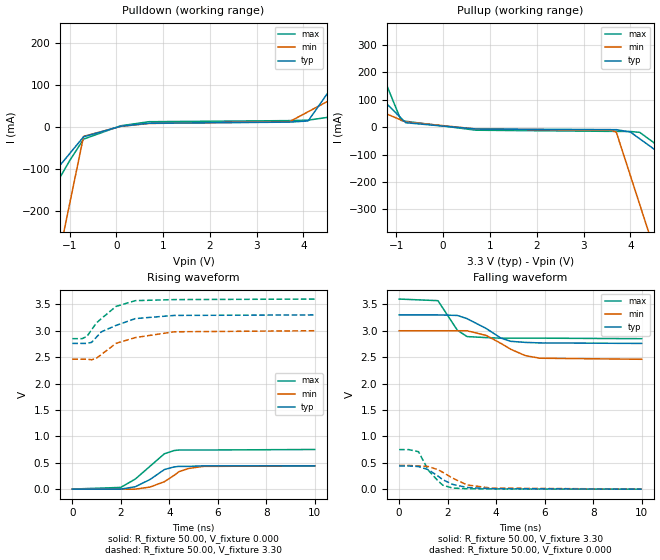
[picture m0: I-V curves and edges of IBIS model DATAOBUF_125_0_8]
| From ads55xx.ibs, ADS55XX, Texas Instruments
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|   Model DATAOBUF_125_0_8
[Model]   DATAOBUF_125_0_8
Model_type   Output
Polarity   Non-Inverting
Vmeas =   1.65V
C_comp   3.00pF   3.00pF   3.00pF
[Temperature Range]   50.00   0.10k   -20.00
[Voltage Range]   3.30V   3.00V   3.60V
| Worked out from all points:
|   slope of the pulldown table from 0 to 0.495 V, typ, clamps not added: 62.9 ohm
|   slope of the pullup table from 0 to 0.495 V, typ, clamps not added: 83.5 ohm
|   rising waveform, R_fixture 50.00, V_fixture 0.000: 20-80 % time 954ps typ, 1.01ns min, 1.11ns max; typ from 0 V to 0.44 V
|   rising waveform, R_fixture 50.00, V_fixture 3.30: 20-80 % time 1.33ns typ, 1.49ns min, 1ns max; typ from 2.76 V to 3.3 V
|   falling waveform, R_fixture 50.00, V_fixture 3.30: 20-80 % time 1.18ns typ, 1.28ns min, 616ps max; typ from 3.3 V to 2.76 V
|   falling waveform, R_fixture 50.00, V_fixture 0.000: 20-80 % time 970ps typ, 1.11ns min, 700ps max; typ from 0.44 V to 0.001 V
[Pulldown]
| voltage   I(typ)   I(min)   I(max)
-3.3V     -372.9mA   -1.424A    -524.1mA
-2.3V     -238.3mA   -884.7mA   -331.1mA
-1.9V     -184.5mA   -669mA     -253.9mA
-1.5V     -130.7mA   -453.3mA   -176.7mA
-1V       -63.35mA   -183.7mA   -80.18mA
-700mV    -22.97mA   -21.98mA   -28.5mA
100mV     2.25mA     1.9mA      3.39mA
700mV     9.17mA     8.74mA     12.95mA
3.7V      11.9mA     12.89mA    15.5mA
4.1V      14.74mA    36.61mA    16.56mA
5.5V      236.9mA    119.6mA    39.12mA
6.6V      411.5mA    184.9mA    57.88mA
[Pullup]
| voltage   I(typ)   I(min)   I(max)
-3.3V     441.6mA    197.5mA    1.029A
-1.9V     203.3mA    97.53mA    443mA
-1.7V     169.3mA    83.25mA    359.3mA
-900mV    33.12mA    26.13mA    24.62mA
-800mV    16.1mA     18.99mA    21.37mA
700mV     -6.9mA     -6.63mA    -11.18mA
3.6V      -9.09mA    -11.8mA    -15.42mA
3.7V      -9.22mA    -18.38mA   -15.48mA
4V        -17.8mA    -176.5mA   -15.89mA
4.2V      -42.42mA   -282mA     -19.03mA
4.5V      -79.35mA   -440.1mA   -56.42mA
6.6V      -337.9mA   -1.547A    -375.8mA
[Ramp]
| variable   typ   min   max
dV/dt_r   0.26/0.90n   0.27/1.07n   0.45/1.12n
dV/dt_f   0.32/1.15n   0.32/1.30n   0.45/0.61n
R_load = 50.00
[Rising Waveform]
R_fixture = 50.00
V_fixture = 0.000
V_fixture_min = 0.000
V_fixture_max = 0.000
| time   V(typ)   V(min)   V(max)
0s        16.26nV    19.53nV    30.54nV
2ns       -1.68mV    -1.17mV    31.66mV
2.6ns     44.29mV    -1.11mV    190mV
3.2ns     180mV      37.62mV    430mV
3.8ns     370mV      140mV      670mV
4.2ns     420mV      260mV      730mV
4.4ns     430mV      330mV      740mV
4.8ns     430mV      390mV      740mV
5.4ns     440mV      430mV      740mV
10ns      440mV      440mV      750mV
[Rising Waveform]
R_fixture = 50.00
V_fixture = 3.30
V_fixture_min = 3.00
V_fixture_max = 3.60
| time   V(typ)   V(min)   V(max)
0s        2.76V      2.46V      2.85V
400ps     2.76V      2.46V      2.85V
600ps     2.76V      2.46V      2.89V
800ps     2.78V      2.45V      3.02V
1ns       2.88V      2.48V      3.15V
1.2ns     2.98V      2.55V      3.23V
1.8ns     3.1V       2.76V      3.46V
2.6ns     3.23V      2.87V      3.57V
4.2ns     3.29V      2.98V      3.59V
10ns      3.3V       3V         3.6V
[Falling Waveform]
R_fixture = 50.00
V_fixture = 3.30
V_fixture_min = 3.00
V_fixture_max = 3.60
| time   V(typ)   V(min)   V(max)
0s        3.3V       3V         3.6V
1.6ns     3.3V       3V         3.57V
2.4ns     3.29V      3V         3.01V
2.8ns     3.23V      3V         2.89V
3.6ns     3.04V      2.91V      2.87V
4.2ns     2.86V      2.76V      2.86V
4.6ns     2.8V       2.65V      2.86V
5.2ns     2.78V      2.53V      2.86V
5.8ns     2.77V      2.48V      2.86V
10ns      2.76V      2.46V      2.85V
[Falling Waveform]
R_fixture = 50.00
V_fixture = 0.000
V_fixture_min = 0.000
V_fixture_max = 0.000
| time   V(typ)   V(min)   V(max)
0s        440mV      450mV      750mV
400ps     440mV      450mV      750mV
800ps     430mV      440mV      710mV
1.2ns     370mV      430mV      360mV
1.6ns     250mV      370mV      160mV
1.8ns     180mV      320mV      76.91mV
2.2ns     92.78mV    210mV      21.78mV
2.8ns     33.05mV    81.24mV    9.8mV
3.8ns     10.97mV    20.92mV    5.51mV
10ns      1.49mV     1.8mV      1.17mV
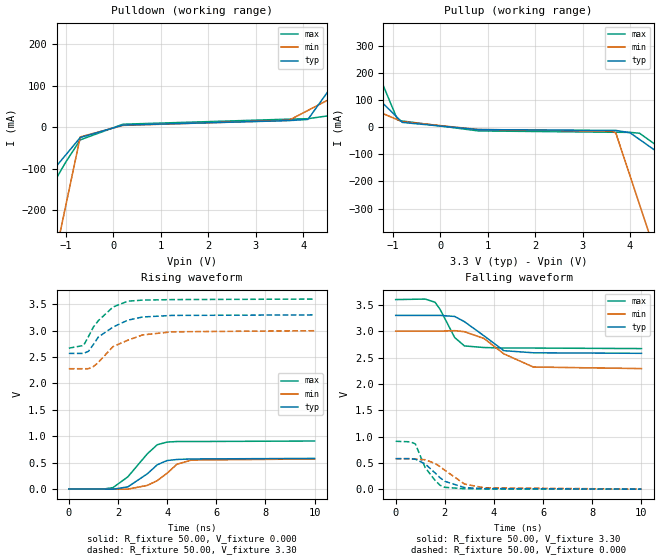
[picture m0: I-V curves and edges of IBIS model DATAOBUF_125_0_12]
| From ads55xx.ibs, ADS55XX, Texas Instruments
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|   Model DATAOBUF_125_0_12
[Model]   DATAOBUF_125_0_12
Model_type   Output
Polarity   Non-Inverting
Vmeas =   1.65V
C_comp   3.00pF   3.00pF   3.00pF
[Temperature Range]   50.00   0.10k   -20.00
[Voltage Range]   3.30V   3.00V   3.60V
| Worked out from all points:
|   slope of the pulldown table from 0 to 0.495 V, typ, clamps not added: 50.3 ohm
|   slope of the pullup table from 0 to 0.495 V, typ, clamps not added: 70.8 ohm
|   rising waveform, R_fixture 50.00, V_fixture 0.000: 20-80 % time 929ps typ, 949ps min, 1.02ns max; typ from 0 V to 0.58 V
|   rising waveform, R_fixture 50.00, V_fixture 3.30: 20-80 % time 1.21ns typ, 1.38ns min, 937ps max; typ from 2.57 V to 3.3 V
|   falling waveform, R_fixture 50.00, V_fixture 3.30: 20-80 % time 1.19ns typ, 1.32ns min, 642ps max; typ from 3.3 V to 2.58 V
|   falling waveform, R_fixture 50.00, V_fixture 0.000: 20-80 % time 887ps typ, 1.04ns min, 659ps max; typ from 0.58 V to 0.001 V
[Pulldown]
| voltage   I(typ)   I(min)   I(max)
-3.3V     -380.4mA   -1.43A     -533.1mA
-2.3V     -243.7mA   -889.2mA   -337.4mA
-1.9V     -189.1mA   -672.8mA   -259.2mA
-1.7V     -161.7mA   -564.6mA   -220mA
-1.5V     -134.4mA   -456.4mA   -180.9mA
-1V       -66.02mA   -185.9mA   -83.03mA
-700mV    -25.01mA   -23.62mA   -30.58mA
200mV     4.94mA     4.18mA     7.01mA
3.7V      15.69mA    16.43mA    19.22mA
4.1V      18.55mA    40.15mA    20.3mA
5.5V      240.7mA    123.2mA    43mA
6.6V      415.3mA    188.4mA    61.87mA
[Pullup]
| voltage   I(typ)   I(min)   I(max)
-3.3V     445.9mA    201.3mA    1.033A
-3.1V     411.6mA    186.8mA    949.1mA
-1.9V     205.9mA    99.81mA    445.6mA
-900mV    34.49mA    27.31mA    26mA
-800mV    17.35mA    20.06mA    22.63mA
800mV     -9.11mA    -8.62mA    -13.93mA
3.6V      -11.95mA   -14.58mA   -18.78mA
3.7V      -12.08mA   -21.17mA   -18.84mA
4V        -20.68mA   -179.4mA   -19.28mA
4.2V      -45.32mA   -284.8mA   -22.43mA
4.5V      -82.28mA   -443mA     -59.83mA
6.6V      -341mA     -1.55A     -379.3mA
[Ramp]
| variable   typ   min   max
dV/dt_r   0.35/0.88n   0.34/1.03n   0.55/1.02n
dV/dt_f   0.43/1.15n   0.43/1.32n   0.56/0.62n
R_load = 50.00
[Rising Waveform]
R_fixture = 50.00
V_fixture = 0.000
V_fixture_min = 0.000
V_fixture_max = 0.000
| time   V(typ)   V(min)   V(max)
0s        15.03nV    18.26nV    28.69nV
1.4ns     -1.2mV     -2.01mV    -2.37mV
1.8ns     -2.69mV    -1.43mV    27.92mV
2.4ns     40.54mV    -2.56mV    230mV
3.2ns     290mV      69.48mV    670mV
3.6ns     460mV      160mV      840mV
4ns       540mV      300mV      890mV
4.4ns     560mV      470mV      900mV
5ns       570mV      550mV      900mV
10ns      580mV      570mV      910mV
[Rising Waveform]
R_fixture = 50.00
V_fixture = 3.30
V_fixture_min = 3.00
V_fixture_max = 3.60
| time   V(typ)   V(min)   V(max)
0s        2.57V      2.28V      2.67V
600ps     2.57V      2.28V      2.72V
800ps     2.61V      2.28V      2.89V
1ns       2.74V      2.32V      3.07V
1.2ns     2.88V      2.4V       3.19V
1.8ns     3.07V      2.7V       3.45V
2.4ns     3.2V       2.82V      3.56V
3ns       3.26V      2.92V      3.58V
4.2ns     3.29V      2.98V      3.59V
10ns      3.3V       3V         3.6V
[Falling Waveform]
R_fixture = 50.00
V_fixture = 3.30
V_fixture_min = 3.00
V_fixture_max = 3.60
| time   V(typ)   V(min)   V(max)
0s        3.3V       3V         3.6V
1.2ns     3.3V       3V         3.61V
1.6ns     3.3V       3V         3.55V
1.8ns     3.3V       3V         3.42V
2.4ns     3.28V      3.01V      2.88V
2.8ns     3.18V      2.99V      2.72V
3.6ns     2.91V      2.86V      2.69V
4.4ns     2.63V      2.57V      2.68V
5.6ns     2.59V      2.32V      2.68V
10ns      2.58V      2.29V      2.67V
[Falling Waveform]
R_fixture = 50.00
V_fixture = 0.000
V_fixture_min = 0.000
V_fixture_max = 0.000
| time   V(typ)   V(min)   V(max)
0s        580mV      580mV      910mV
600ps     580mV      580mV      900mV
800ps     570mV      570mV      860mV
1.2ns     480mV      560mV      410mV
1.6ns     310mV      490mV      170mV
1.8ns     220mV      430mV      77.11mV
2ns       150mV      360mV      35.68mV
2.8ns     30.76mV    98.9mV     9.26mV
3.6ns     12.05mV    26.42mV    5.69mV
10ns      1.37mV     1.69mV     1.11mV
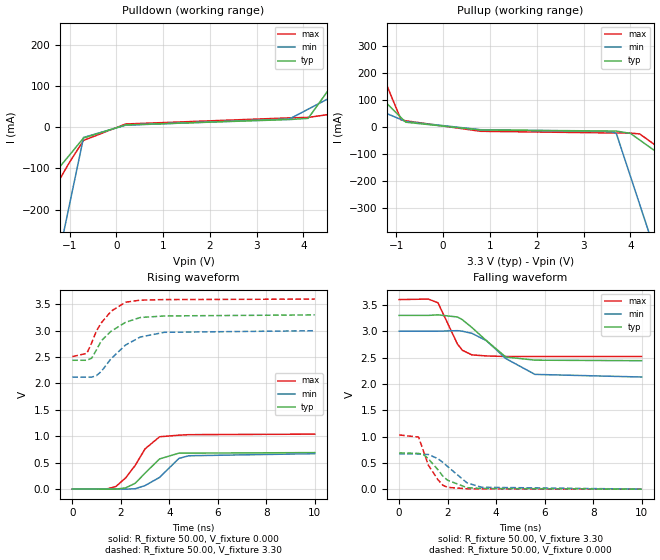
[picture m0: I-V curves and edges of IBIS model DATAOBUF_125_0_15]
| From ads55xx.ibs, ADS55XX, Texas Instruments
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|   Model DATAOBUF_125_0_15
[Model]   DATAOBUF_125_0_15
Model_type   Output
Polarity   Non-Inverting
Vmeas =   1.65V
C_comp   3.00pF   3.00pF   3.00pF
[Temperature Range]   50.00   0.10k   -20.00
[Voltage Range]   3.30V   3.00V   3.60V
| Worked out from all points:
|   slope of the pulldown table from 0 to 0.495 V, typ, clamps not added: 44.7 ohm
|   slope of the pullup table from 0 to 0.495 V, typ, clamps not added: 63.7 ohm
|   rising waveform, R_fixture 50.00, V_fixture 0.000: 20-80 % time 904ps typ, 953ps min, 964ps max; typ from 0 V to 0.69 V
|   rising waveform, R_fixture 50.00, V_fixture 3.30: 20-80 % time 1.13ns typ, 1.24ns min, 872ps max; typ from 2.44 V to 3.3 V
|   falling waveform, R_fixture 50.00, V_fixture 3.30: 20-80 % time 1.24ns typ, 1.41ns min, 645ps max; typ from 3.3 V to 2.44 V
|   falling waveform, R_fixture 50.00, V_fixture 0.000: 20-80 % time 842ps typ, 1.02ns min, 634ps max; typ from 0.69 V to 0.001 V
[Pulldown]
| voltage   I(typ)   I(min)   I(max)
-3.3V     -385.4mA   -1.435A    -539.7mA
-2.3V     -247.3mA   -892.8mA   -342.1mA
-1.9V     -192mA     -675.9mA   -263.1mA
-1.7V     -164.4mA   -567.4mA   -223.5mA
-1.5V     -136.8mA   -458.9mA   -184mA
-1V       -67.74mA   -187.7mA   -85.21mA
-700mV    -26.31mA   -25mA      -32.2mA
200mV     5.44mA     4.68mA     7.65mA
3.7V      18.43mA    19.83mA    22.49mA
4.1V      21.3mA     43.59mA    23.57mA
5.5V      243.5mA    126.8mA    46.4mA
6.6V      418mA      192.1mA    65.38mA
[Pullup]
| voltage   I(typ)   I(min)   I(max)
-3.3V     449.3mA    204.3mA    1.036A
-3.1V     414.8mA    189.6mA    952.1mA
-1.9V     207.9mA    101.5mA    447.5mA
-900mV    35.5mA     28.11mA    27.01mA
-800mV    18.26mA    20.77mA    23.54mA
800mV     -10.45mA   -9.59mA    -15.42mA
3.6V      -14.38mA   -16.67mA   -21.52mA
3.7V      -14.52mA   -23.27mA   -21.59mA
4V        -23.14mA   -181.5mA   -22.04mA
4.2V      -47.78mA   -286.9mA   -25.2mA
4.5V      -84.74mA   -445.1mA   -62.62mA
6.6V      -343.5mA   -1.552A    -382.2mA
[Ramp]
| variable   typ   min   max
dV/dt_r   0.41/0.88n   0.40/1.00n   0.62/0.96n
dV/dt_f   0.51/1.17n   0.52/1.41n   0.65/0.64n
R_load = 50.00
[Rising Waveform]
R_fixture = 50.00
V_fixture = 0.000
V_fixture_min = 0.000
V_fixture_max = 0.000
| time   V(typ)   V(min)   V(max)
0s        14.37nV    17.34nV    27.48nV
1.4ns     -1.43mV    -2.24mV    -1.93mV
1.8ns     -2.79mV    -1.77mV    48.3mV
2.2ns     21.77mV    -3.07mV    210mV
2.6ns     110mV      5.28mV     450mV
3ns       300mV      64.86mV    760mV
3.6ns     570mV      220mV      990mV
4.4ns     680mV      580mV      1.02V
4.8ns     680mV      630mV      1.03V
10ns      690mV      670mV      1.04V
[Rising Waveform]
R_fixture = 50.00
V_fixture = 3.30
V_fixture_min = 3.00
V_fixture_max = 3.60
| time   V(typ)   V(min)   V(max)
0s        2.44V      2.12V      2.51V
600ps     2.44V      2.12V      2.57V
800ps     2.48V      2.12V      2.77V
1ns       2.64V      2.15V      3V
1.2ns     2.81V      2.23V      3.15V
1.6ns     2.99V      2.47V      3.37V
2.2ns     3.16V      2.73V      3.54V
2.8ns     3.25V      2.88V      3.58V
3.8ns     3.28V      2.97V      3.59V
10ns      3.3V       3V         3.6V
[Falling Waveform]
R_fixture = 50.00
V_fixture = 3.30
V_fixture_min = 3.00
V_fixture_max = 3.60
| time   V(typ)   V(min)   V(max)
0s        3.3V       3V         3.6V
1.2ns     3.3V       3V         3.61V
1.6ns     3.31V      3V         3.54V
2.4ns     3.27V      3.01V      2.76V
2.6ns     3.22V      3V         2.64V
3ns       3.07V      2.96V      2.55V
3.6ns     2.82V      2.82V      2.53V
4.4ns     2.51V      2.48V      2.52V
5.6ns     2.45V      2.18V      2.52V
10ns      2.44V      2.13V      2.52V
[Falling Waveform]
R_fixture = 50.00
V_fixture = 0.000
V_fixture_min = 0.000
V_fixture_max = 0.000
| time   V(typ)   V(min)   V(max)
0s        690mV      670mV      1.03V
800ps     680mV      670mV      990mV
1ns       660mV      660mV      730mV
1.2ns     580mV      660mV      460mV
1.6ns     370mV      580mV      180mV
1.8ns     250mV      510mV      76.45mV
2ns       170mV      430mV      34.69mV
2.8ns     29.84mV    120mV      9.16mV
3.4ns     14.19mV    37.21mV    6.2mV
10ns      1.31mV     1.61mV     1.07mV
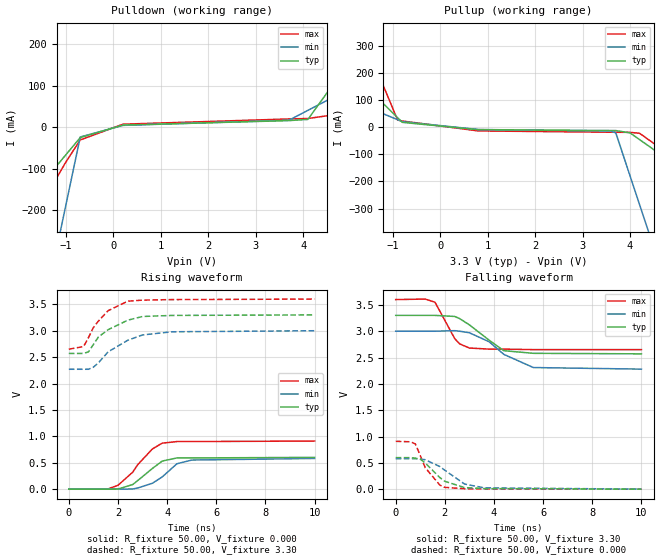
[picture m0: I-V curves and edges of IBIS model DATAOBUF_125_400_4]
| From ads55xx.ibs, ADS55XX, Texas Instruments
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|   Model DATAOBUF_125_400_4
[Model]   DATAOBUF_125_400_4
Model_type   Output
Polarity   Non-Inverting
Vmeas =   1.65V
C_comp   3.00pF   3.00pF   3.00pF
[Temperature Range]   50.00   0.10k   -20.00
[Voltage Range]   3.30V   3.00V   3.60V
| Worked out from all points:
|   slope of the pulldown table from 0 to 0.495 V, typ, clamps not added: 50.2 ohm
|   slope of the pullup table from 0 to 0.495 V, typ, clamps not added: 69.1 ohm
|   rising waveform, R_fixture 50.00, V_fixture 0.000: 20-80 % time 941ps typ, 940ps min, 1.03ns max; typ from 0 V to 0.6 V
|   rising waveform, R_fixture 50.00, V_fixture 3.30: 20-80 % time 1.2ns typ, 1.36ns min, 921ps max; typ from 2.57 V to 3.3 V
|   falling waveform, R_fixture 50.00, V_fixture 3.30: 20-80 % time 1.21ns typ, 1.34ns min, 640ps max; typ from 3.3 V to 2.57 V
|   falling waveform, R_fixture 50.00, V_fixture 0.000: 20-80 % time 895ps typ, 1.04ns min, 659ps max; typ from 0.6 V to 0.001 V
[Pulldown]
| voltage   I(typ)   I(min)   I(max)
-3.3V     -380.7mA   -1.431A    -534.4mA
-2.3V     -243.9mA   -889.5mA   -338.3mA
-1.9V     -189.2mA   -673mA     -259.9mA
-1.7V     -161.8mA   -564.8mA   -220.7mA
-1.5V     -134.5mA   -456.6mA   -181.4mA
-1V       -66.07mA   -186.1mA   -83.39mA
-700mV    -25.03mA   -23.72mA   -30.84mA
200mV     4.95mA     4.21mA     7.11mA
3.7V      15.74mA    16.65mA    19.72mA
4.1V      18.59mA    40.41mA    20.8mA
5.5V      240.9mA    123.6mA    43.5mA
6.6V      415.6mA    188.9mA    62.37mA
[Pullup]
| voltage   I(typ)   I(min)   I(max)
-3.3V     446.5mA    201.6mA    1.033A
-3.1V     412.2mA    187.1mA    949.3mA
-1.9V     206.3mA    99.94mA    445.7mA
-900mV    34.7mA     27.34mA    26mA
-800mV    17.54mA    20.08mA    22.63mA
800mV     -9.39mA    -8.64mA    -13.94mA
3.6V      -12.43mA   -14.62mA   -18.79mA
3.7V      -12.56mA   -21.21mA   -18.85mA
4V        -21.17mA   -179.4mA   -19.29mA
4.2V      -45.81mA   -284.9mA   -22.44mA
4.5V      -82.77mA   -443mA     -59.84mA
6.6V      -341.5mA   -1.55A     -379.4mA
[Ramp]
| variable   typ   min   max
dV/dt_r   0.36/0.89n   0.35/1.03n   0.55/1.03n
dV/dt_f   0.44/1.16n   0.43/1.32n   0.57/0.62n
R_load = 50.00
[Rising Waveform]
R_fixture = 50.00
V_fixture = 0.000
V_fixture_min = 0.000
V_fixture_max = 0.000
| time   V(typ)   V(min)   V(max)
0s        15.03nV    18.19nV    28.45nV
1.6ns     -1.91mV    -1.94mV    3.9mV
2ns       420uV      -1.63mV    70.84mV
2.6ns     85.46mV    1.66mV     320mV
2.8ns     160mV      19.63mV    460mV
3.4ns     390mV      110mV      760mV
3.8ns     530mV      230mV      870mV
4.4ns     590mV      480mV      900mV
5ns       590mV      550mV      900mV
10ns      600mV      580mV      910mV
[Rising Waveform]
R_fixture = 50.00
V_fixture = 3.30
V_fixture_min = 3.00
V_fixture_max = 3.60
| time   V(typ)   V(min)   V(max)
0s        2.57V      2.27V      2.65V
600ps     2.57V      2.27V      2.7V
800ps     2.6V       2.27V      2.87V
1ns       2.74V      2.31V      3.06V
1.2ns     2.88V      2.39V      3.18V
1.6ns     3.02V      2.6V       3.38V
2.4ns     3.2V       2.82V      3.56V
3ns       3.27V      2.92V      3.58V
4.2ns     3.29V      2.98V      3.59V
10ns      3.3V       3V         3.6V
[Falling Waveform]
R_fixture = 50.00
V_fixture = 3.30
V_fixture_min = 3.00
V_fixture_max = 3.60
| time   V(typ)   V(min)   V(max)
0s        3.3V       3V         3.6V
1.2ns     3.3V       3V         3.61V
1.6ns     3.3V       3V         3.55V
2.4ns     3.28V      3.01V      2.86V
2.6ns     3.24V      3V         2.76V
3ns       3.12V      2.97V      2.68V
3.8ns     2.83V      2.8V       2.66V
4.4ns     2.63V      2.56V      2.66V
5.6ns     2.58V      2.31V      2.65V
10ns      2.57V      2.28V      2.65V
[Falling Waveform]
R_fixture = 50.00
V_fixture = 0.000
V_fixture_min = 0.000
V_fixture_max = 0.000
| time   V(typ)   V(min)   V(max)
0s        600mV      580mV      910mV
600ps     600mV      580mV      900mV
800ps     590mV      580mV      860mV
1ns       570mV      570mV      640mV
1.2ns     500mV      560mV      410mV
1.8ns     220mV      430mV      76.14mV
2ns       150mV      360mV      35.2mV
2.8ns     31.08mV    99.07mV    9.25mV
3.6ns     12.12mV    26.27mV    5.68mV
10ns      1.37mV     1.68mV     1.1mV
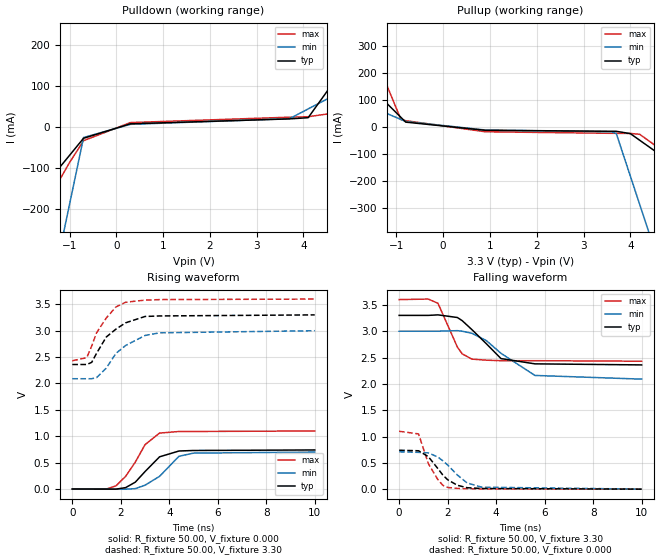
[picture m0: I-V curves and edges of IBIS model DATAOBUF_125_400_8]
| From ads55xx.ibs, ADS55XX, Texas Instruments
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|   Model DATAOBUF_125_400_8
[Model]   DATAOBUF_125_400_8
Model_type   Output
Polarity   Non-Inverting
Vmeas =   1.65V
C_comp   3.00pF   3.00pF   3.00pF
[Temperature Range]   50.00   0.10k   -20.00
[Voltage Range]   3.30V   3.00V   3.60V
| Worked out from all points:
|   slope of the pulldown table from 0 to 0.495 V, typ, clamps not added: 42.1 ohm
|   slope of the pullup table from 0 to 0.495 V, typ, clamps not added: 61.4 ohm
|   rising waveform, R_fixture 50.00, V_fixture 0.000: 20-80 % time 924ps typ, 950ps min, 925ps max; typ from 0 V to 0.74 V
|   rising waveform, R_fixture 50.00, V_fixture 3.30: 20-80 % time 1.07ns typ, 1.23ns min, 855ps max; typ from 2.36 V to 3.3 V
|   falling waveform, R_fixture 50.00, V_fixture 3.30: 20-80 % time 1.23ns typ, 1.51ns min, 662ps max; typ from 3.3 V to 2.36 V
|   falling waveform, R_fixture 50.00, V_fixture 0.000: 20-80 % time 848ps typ, 1.02ns min, 620ps max; typ from 0.74 V to 0.001 V
[Pulldown]
| voltage   I(typ)   I(min)   I(max)
-3.3V     -388.2mA   -1.437A    -542.8mA
-2.3V     -249.3mA   -893.7mA   -344.3mA
-1.9V     -193.7mA   -676.6mA   -264.9mA
-1.7V     -165.9mA   -568.1mA   -225.2mA
-1.5V     -138.1mA   -459.5mA   -185.5mA
-1V       -68.7mA    -188.1mA   -86.26mA
-700mV    -27.03mA   -25.27mA   -32.99mA
300mV     8.06mA     6.82mA     11.1mA
3.7V      20.07mA    20.56mA    24.2mA
4.1V      22.93mA    44.32mA    25.28mA
5.5V      245.1mA    127.5mA    48.1mA
6.6V      419.7mA    192.8mA    67.08mA
[Pullup]
| voltage   I(typ)   I(min)   I(max)
-3.3V     450.4mA    205mA      1.038A
-3.1V     415.8mA    190.3mA    953.7mA
-1.9V     208.6mA    101.9mA    448.5mA
-900mV    35.87mA    28.35mA    27.5mA
-800mV    18.6mA     20.99mA    23.99mA
900mV     -11.69mA   -10.68mA   -17.24mA
3.6V      -15.36mA   -17.38mA   -22.97mA
3.7V      -15.49mA   -23.98mA   -23.04mA
4V        -24.12mA   -182.2mA   -23.5mA
4.2V      -48.78mA   -287.6mA   -26.67mA
4.5V      -85.77mA   -445.8mA   -64.09mA
6.6V      -344.7mA   -1.553A    -383.7mA
[Ramp]
| variable   typ   min   max
dV/dt_r   0.44/0.88n   0.42/1.00n   0.66/0.95n
dV/dt_f   0.56/1.18n   0.54/1.48n   0.70/0.64n
R_load = 50.00
[Rising Waveform]
R_fixture = 50.00
V_fixture = 0.000
V_fixture_min = 0.000
V_fixture_max = 0.000
| time   V(typ)   V(min)   V(max)
0s        14.04nV    17.18nV    26.95nV
1.4ns     -1.56mV    -2.21mV    -1.58mV
1.8ns     -2.79mV    -1.84mV    58.66mV
2.2ns     25.94mV    -3.18mV    240mV
2.6ns     130mV      6.61mV     510mV
3ns       330mV      71.68mV    840mV
3.6ns     610mV      240mV      1.06V
4.4ns     720mV      620mV      1.09V
5ns       730mV      680mV      1.09V
10ns      740mV      700mV      1.1V
[Rising Waveform]
R_fixture = 50.00
V_fixture = 3.30
V_fixture_min = 3.00
V_fixture_max = 3.60
| time   V(typ)   V(min)   V(max)
0s        2.36V      2.09V      2.43V
600ps     2.36V      2.09V      2.49V
800ps     2.4V       2.09V      2.71V
1ns       2.57V      2.11V      2.96V
1.4ns     2.88V      2.29V      3.24V
1.8ns     3.03V      2.57V      3.45V
2.2ns     3.15V      2.72V      3.54V
3ns       3.27V      2.91V      3.58V
3.6ns     3.28V      2.96V      3.59V
10ns      3.3V       3V         3.6V
[Falling Waveform]
R_fixture = 50.00
V_fixture = 3.30
V_fixture_min = 3.00
V_fixture_max = 3.60
| time   V(typ)   V(min)   V(max)
0s        3.3V       3V         3.6V
1.2ns     3.3V       3V         3.61V
1.6ns     3.31V      3V         3.53V
2.4ns     3.26V      3.01V      2.7V
2.6ns     3.2V       3V         2.57V
3ns       3.03V      2.96V      2.47V
3.6ns     2.76V      2.82V      2.45V
4.2ns     2.48V      2.58V      2.44V
5.6ns     2.38V      2.16V      2.44V
10ns      2.36V      2.09V      2.43V
[Falling Waveform]
R_fixture = 50.00
V_fixture = 0.000
V_fixture_min = 0.000
V_fixture_max = 0.000
| time   V(typ)   V(min)   V(max)
0s        740mV      710mV      1.1V
800ps     730mV      700mV      1.05V
1.2ns     620mV      690mV      490mV
1.6ns     390mV      610mV      180mV
1.8ns     270mV      540mV      75.46mV
2ns       180mV      460mV      34.04mV
2.4ns     74.95mV    270mV      15.27mV
2.8ns     28.99mV    120mV      9.01mV
3.4ns     13.85mV    38.81mV    6.08mV
10ns      1.28mV     1.6mV      1.05mV
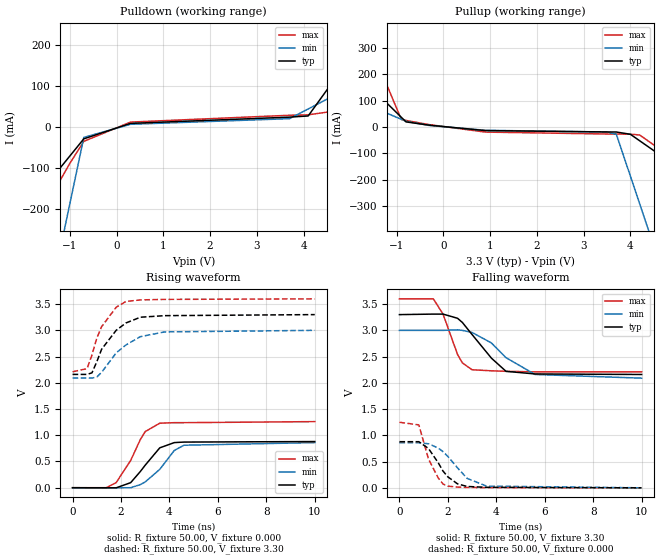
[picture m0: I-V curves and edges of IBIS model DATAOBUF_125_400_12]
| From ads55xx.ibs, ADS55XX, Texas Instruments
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|   Model DATAOBUF_125_400_12
[Model]   DATAOBUF_125_400_12
Model_type   Output
Polarity   Non-Inverting
Vmeas =   1.65V
C_comp   3.00pF   3.00pF   3.00pF
[Temperature Range]   50.00   0.10k   -20.00
[Voltage Range]   3.30V   3.00V   3.60V
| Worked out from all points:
|   slope of the pulldown table from 0 to 0.495 V, typ, clamps not added: 37.1 ohm
|   slope of the pullup table from 0 to 0.495 V, typ, clamps not added: 55.5 ohm
|   rising waveform, R_fixture 50.00, V_fixture 0.000: 20-80 % time 898ps typ, 939ps min, 857ps max; typ from 0 V to 0.88 V
|   rising waveform, R_fixture 50.00, V_fixture 3.30: 20-80 % time 1.02ns typ, 1.2ns min, 807ps max; typ from 2.16 V to 3.3 V
|   falling waveform, R_fixture 50.00, V_fixture 3.30: 20-80 % time 1.22ns typ, 1.51ns min, 678ps max; typ from 3.3 V to 2.16 V
|   falling waveform, R_fixture 50.00, V_fixture 0.000: 20-80 % time 799ps typ, 1.02ns min, 600ps max; typ from 0.88 V to 0.001 V
[Pulldown]
| voltage   I(typ)   I(min)   I(max)
-3.3V     -394.8mA   -1.437A    -550.8mA
-2.3V     -254mA     -893.7mA   -350mA
-1.9V     -197.7mA   -676.6mA   -269.6mA
-1.7V     -169.5mA   -568.1mA   -229.5mA
-1.5V     -141.4mA   -459.5mA   -189.3mA
-1V       -70.96mA   -188.1mA   -88.92mA
-700mV    -28.72mA   -25.27mA   -34.95mA
300mV     9.02mA     6.82mA     12.22mA
3.7V      24.3mA     20.56mA    28.88mA
4.1V      27.17mA    44.32mA    29.95mA
5.5V      249.3mA    127.5mA    52.76mA
6.6V      423.9mA    192.8mA    71.73mA
[Pullup]
| voltage   I(typ)   I(min)   I(max)
-3.3V     453.9mA    208.5mA    1.041A
-1.9V     210.7mA    104mA      450.5mA
-900mV    36.98mA    29.44mA    28.58mA
-800mV    19.61mA    21.98mA    24.97mA
-300mV    7.08mA     5.98mA     9.17mA
900mV     -13.36mA   -12.24mA   -19.04mA
3.5V      -18.46mA   -18.81mA   -26.28mA
3.7V      -18.69mA   -27.48mA   -26.44mA
4V        -27.34mA   -185.7mA   -26.92mA
4.2V      -52.02mA   -291.2mA   -30.1mA
4.5V      -89.04mA   -449.5mA   -67.54mA
6.6V      -348.2mA   -1.557A    -387.4mA
[Ramp]
| variable   typ   min   max
dV/dt_r   0.53/0.87n   0.51/0.98n   0.75/0.89n
dV/dt_f   0.68/1.17n   0.54/1.48n   0.83/0.66n
R_load = 50.00
[Rising Waveform]
R_fixture = 50.00
V_fixture = 0.000
V_fixture_min = 0.000
V_fixture_max = 0.000
| time   V(typ)   V(min)   V(max)
0s        13.35nV    17.31nV    25.81nV
1.4ns     -1.91mV    -2.21mV    640uV
1.8ns     -2.53mV    -1.84mV    97.84mV
2.4ns     96.59mV    -250uV     520mV
2.8ns     310mV      59.87mV    920mV
3ns       430mV      110mV      1.07V
3.6ns     760mV      350mV      1.23V
4.2ns     860mV      710mV      1.24V
4.6ns     870mV      810mV      1.24V
10ns      880mV      860mV      1.26V
[Rising Waveform]
R_fixture = 50.00
V_fixture = 3.30
V_fixture_min = 3.00
V_fixture_max = 3.60
| time   V(typ)   V(min)   V(max)
0s        2.16V      2.09V      2.21V
600ps     2.16V      2.09V      2.27V
800ps     2.19V      2.09V      2.53V
1ns       2.4V       2.11V      2.85V
1.2ns     2.64V      2.2V       3.07V
1.8ns     3V         2.57V      3.44V
2.2ns     3.14V      2.72V      3.55V
2.8ns     3.25V      2.88V      3.58V
3.8ns     3.28V      2.97V      3.59V
10ns      3.3V       3V         3.6V
[Falling Waveform]
R_fixture = 50.00
V_fixture = 3.30
V_fixture_min = 3.00
V_fixture_max = 3.60
| time   V(typ)   V(min)   V(max)
0s        3.3V       3V         3.6V
1.4ns     3.31V      3V         3.6V
1.8ns     3.31V      3V         3.31V
2.4ns     3.23V      3.01V      2.54V
2.6ns     3.15V      3V         2.38V
3ns       2.92V      2.96V      2.25V
3.8ns     2.47V      2.76V      2.23V
4.4ns     2.22V      2.48V      2.22V
5.6ns     2.17V      2.16V      2.21V
10ns      2.16V      2.09V      2.21V
[Falling Waveform]
R_fixture = 50.00
V_fixture = 0.000
V_fixture_min = 0.000
V_fixture_max = 0.000
| time   V(typ)   V(min)   V(max)
0s        880mV      860mV      1.25V
800ps     880mV      860mV      1.2V
1.2ns     750mV      840mV      550mV
1.6ns     480mV      760mV      190mV
1.8ns     320mV      690mV      73.09mV
2ns       210mV      600mV      32.92mV
2.4ns     76.29mV    380mV      15.41mV
2.8ns     26.94mV    180mV      8.83mV
3.6ns     10.97mV    34.05mV    5.27mV
10ns      1.21mV     1.65mV     1.01mV
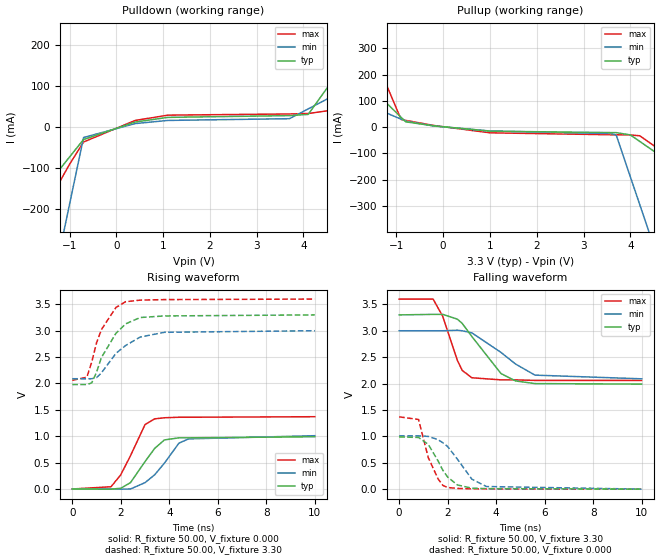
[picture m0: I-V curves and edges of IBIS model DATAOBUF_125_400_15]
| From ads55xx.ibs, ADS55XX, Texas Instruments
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|   Model DATAOBUF_125_400_15
[Model]   DATAOBUF_125_400_15
Model_type   Output
Polarity   Non-Inverting
Vmeas =   1.65V
C_comp   3.00pF   3.00pF   3.00pF
[Temperature Range]   50.00   0.10k   -20.00
[Voltage Range]   3.30V   3.00V   3.60V
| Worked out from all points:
|   slope of the pulldown table from 0 to 0.495 V, typ, clamps not added: 34 ohm
|   slope of the pullup table from 0 to 0.495 V, typ, clamps not added: 52.3 ohm
|   rising waveform, R_fixture 50.00, V_fixture 0.000: 20-80 % time 888ps typ, 1.04ns min, 830ps max; typ from 0 V to 0.99 V
|   rising waveform, R_fixture 50.00, V_fixture 3.30: 20-80 % time 967ps typ, 1.2ns min, 775ps max; typ from 1.98 V to 3.3 V
|   falling waveform, R_fixture 50.00, V_fixture 3.30: 20-80 % time 1.33ns typ, 1.48ns min, 696ps max; typ from 3.3 V to 1.99 V
|   falling waveform, R_fixture 50.00, V_fixture 0.000: 20-80 % time 773ps typ, 973ps min, 590ps max; typ from 0.99 V to 0.001 V
[Pulldown]
| voltage   I(typ)   I(min)   I(max)
-3.3V     -400mA     -1.437A    -555.6mA
-2.3V     -257.7mA   -893.7mA   -353.4mA
-1.7V     -172.4mA   -568.1mA   -232.1mA
-1.5V     -143.9mA   -459.5mA   -191.6mA
-1V       -72.74mA   -188.1mA   -90.51mA
-700mV    -30.05mA   -25.27mA   -36.12mA
400mV     12.36mA    8.63mA     16.2mA
1.1V      23.75mA    16.31mA    29.18mA
3.7V      28.06mA    20.56mA    32.03mA
4.1V      30.92mA    44.32mA    33.09mA
5.5V      253.1mA    127.5mA    55.78mA
6.6V      427.7mA    192.8mA    74.65mA
[Pullup]
| voltage   I(typ)   I(min)   I(max)
-3.3V     456.3mA    211.9mA    1.044A
-1.9V     212.1mA    106mA      452mA
-900mV    37.7mA     30.45mA    29.37mA
-800mV    20.26mA    22.89mA    25.69mA
-200mV    4.96mA     4.26mA     6.28mA
1V        -15.4mA    -14.74mA   -21.67mA
3.6V      -20.84mA   -24.59mA   -29.1mA
3.7V      -20.99mA   -31.22mA   -29.18mA
4V        -29.67mA   -189.5mA   -29.68mA
4.2V      -54.35mA   -295mA     -32.87mA
4.5V      -91.37mA   -453.2mA   -70.32mA
6.6V      -350.5mA   -1.561A    -390.1mA
[Ramp]
| variable   typ   min   max
dV/dt_r   0.59/0.87n   0.61/1.08n   0.82/0.87n
dV/dt_f   0.79/1.31n   0.54/1.47n   0.92/0.68n
R_load = 50.00
[Rising Waveform]
R_fixture = 50.00
V_fixture = 0.000
V_fixture_min = 0.000
V_fixture_max = 0.000
| time   V(typ)   V(min)   V(max)
0s        12.88nV    17.34nV    25.23nV
1.6ns     -3.26mV    -2.33mV    42.8mV
2ns       13.81mV    -2.42mV    270mV
2.4ns     120mV      350uV      630mV
3ns       520mV      120mV      1.22V
3.4ns     770mV      270mV      1.33V
3.8ns     930mV      490mV      1.35V
4.4ns     970mV      870mV      1.36V
4.8ns     970mV      950mV      1.36V
10ns      990mV      1.01V      1.37V
[Rising Waveform]
R_fixture = 50.00
V_fixture = 3.30
V_fixture_min = 3.00
V_fixture_max = 3.60
| time   V(typ)   V(min)   V(max)
0s        1.98V      2.09V      2.06V
600ps     1.98V      2.09V      2.12V
800ps     2.01V      2.09V      2.4V
1ns       2.21V      2.11V      2.77V
1.2ns     2.49V      2.2V       3.02V
1.8ns     2.95V      2.57V      3.44V
2.2ns     3.13V      2.72V      3.55V
2.8ns     3.25V      2.88V      3.58V
3.8ns     3.28V      2.97V      3.59V
10ns      3.3V       3V         3.6V
[Falling Waveform]
R_fixture = 50.00
V_fixture = 3.30
V_fixture_min = 3.00
V_fixture_max = 3.60
| time   V(typ)   V(min)   V(max)
0s        3.3V       3V         3.6V
1.4ns     3.31V      3V         3.6V
1.8ns     3.31V      3V         3.27V
2.4ns     3.22V      3.01V      2.44V
2.6ns     3.14V      3V         2.25V
3ns       2.89V      2.96V      2.11V
4.2ns     2.19V      2.59V      2.07V
4.8ns     2.05V      2.37V      2.07V
5.6ns     2V         2.16V      2.06V
10ns      1.99V      2.09V      2.06V
[Falling Waveform]
R_fixture = 50.00
V_fixture = 0.000
V_fixture_min = 0.000
V_fixture_max = 0.000
| time   V(typ)   V(min)   V(max)
0s        990mV      1.01V      1.37V
800ps     980mV      1.01V      1.32V
1.2ns     850mV      1V         600mV
1.6ns     540mV      940mV      200mV
1.8ns     360mV      880mV      72.42mV
2ns       230mV      810mV      32.54mV
2.4ns     81.09mV    570mV      15.48mV
3ns       19.41mV    190mV      7.3mV
3.6ns     11mV       50.96mV    5.16mV
10ns      1.16mV     1.73mV     990uV
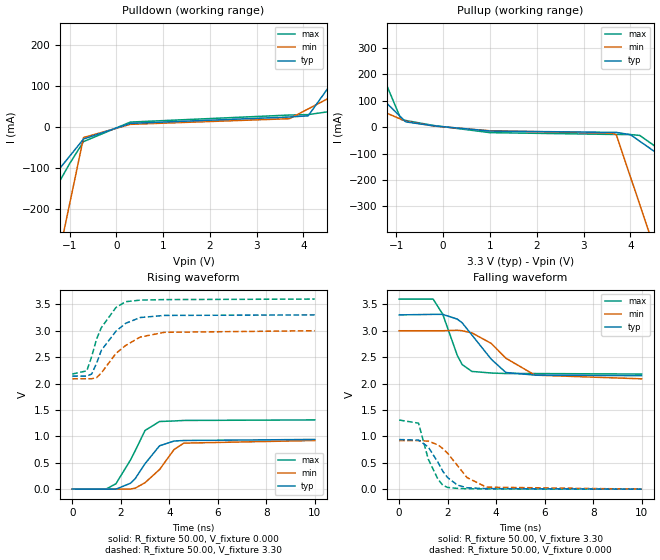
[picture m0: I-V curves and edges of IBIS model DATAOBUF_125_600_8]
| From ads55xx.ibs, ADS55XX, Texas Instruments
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|   Model DATAOBUF_125_600_8
[Model]   DATAOBUF_125_600_8
Model_type   Output
Polarity   Non-Inverting
Vmeas =   1.65V
C_comp   3.00pF   3.00pF   3.00pF
[Temperature Range]   50.00   0.10k   -20.00
[Voltage Range]   3.30V   3.00V   3.60V
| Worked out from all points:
|   slope of the pulldown table from 0 to 0.495 V, typ, clamps not added: 36.8 ohm
|   slope of the pullup table from 0 to 0.495 V, typ, clamps not added: 53.7 ohm
|   rising waveform, R_fixture 50.00, V_fixture 0.000: 20-80 % time 891ps typ, 970ps min, 866ps max; typ from 0 V to 0.94 V
|   rising waveform, R_fixture 50.00, V_fixture 3.30: 20-80 % time 1ns typ, 1.2ns min, 800ps max; typ from 2.14 V to 3.3 V
|   falling waveform, R_fixture 50.00, V_fixture 3.30: 20-80 % time 1.21ns typ, 1.51ns min, 684ps max; typ from 3.3 V to 2.15 V
|   falling waveform, R_fixture 50.00, V_fixture 0.000: 20-80 % time 798ps typ, 1.01ns min, 597ps max; typ from 0.94 V to 0.001 V
[Pulldown]
| voltage   I(typ)   I(min)   I(max)
-3.3V     -395.2mA   -1.437A    -551.5mA
-2.3V     -254.3mA   -893.7mA   -350.5mA
-1.9V     -197.9mA   -676.6mA   -270.1mA
-1.7V     -169.8mA   -568.1mA   -229.9mA
-1.5V     -141.6mA   -459.5mA   -189.7mA
-1V       -71.12mA   -188.1mA   -89.19mA
-700mV    -28.85mA   -25.27mA   -35.16mA
300mV     9.09mA     6.82mA     12.34mA
3.7V      24.65mA    20.56mA    29.42mA
4.1V      27.51mA    44.32mA    30.49mA
5.5V      249.8mA    127.5mA    53.24mA
6.6V      424.5mA    192.8mA    72.16mA
[Pullup]
| voltage   I(typ)   I(min)   I(max)
-3.3V     455.2mA    210.1mA    1.042A
-1.9V     211.4mA    105mA      451.1mA
-900mV    37.35mA    29.88mA    28.92mA
-800mV    19.94mA    22.37mA    25.28mA
-200mV    4.87mA     4.11mA     6.16mA
1V        -14.82mA   -13.81mA   -20.83mA
3.6V      -19.71mA   -22.4mA    -27.53mA
3.7V      -19.86mA   -29.01mA   -27.61mA
4V        -28.52mA   -187.3mA   -28.1mA
4.2V      -53.2mA    -292.8mA   -31.28mA
4.5V      -90.22mA   -451mA     -68.72mA
6.6V      -349.4mA   -1.559A    -388.4mA
[Ramp]
| variable   typ   min   max
dV/dt_r   0.56/0.87n   0.55/1.00n   0.78/0.90n
dV/dt_f   0.69/1.18n   0.54/1.47n   0.85/0.67n
R_load = 50.00
[Rising Waveform]
R_fixture = 50.00
V_fixture = 0.000
V_fixture_min = 0.000
V_fixture_max = 0.000
| time   V(typ)   V(min)   V(max)
0s        13.33nV    17.34nV    25.71nV
1.4ns     -1.95mV    -2.21mV    1.13mV
1.8ns     -2.26mV    -1.84mV    100mV
2.4ns     110mV      260uV      550mV
2.6ns     200mV      17.66mV    730mV
3ns       480mV      120mV      1.11V
3.6ns     820mV      370mV      1.28V
4.2ns     910mV      750mV      1.29V
4.6ns     920mV      870mV      1.3V
10ns      940mV      920mV      1.31V
[Rising Waveform]
R_fixture = 50.00
V_fixture = 3.30
V_fixture_min = 3.00
V_fixture_max = 3.60
| time   V(typ)   V(min)   V(max)
0s        2.14V      2.09V      2.18V
600ps     2.14V      2.09V      2.24V
800ps     2.18V      2.09V      2.51V
1ns       2.38V      2.11V      2.84V
1.2ns     2.63V      2.2V       3.06V
1.8ns     2.99V      2.57V      3.44V
2.2ns     3.14V      2.72V      3.55V
2.8ns     3.25V      2.88V      3.58V
3.8ns     3.29V      2.97V      3.59V
10ns      3.3V       3V         3.6V
[Falling Waveform]
R_fixture = 50.00
V_fixture = 3.30
V_fixture_min = 3.00
V_fixture_max = 3.60
| time   V(typ)   V(min)   V(max)
0s        3.3V       3V         3.6V
1.4ns     3.31V      3V         3.6V
1.8ns     3.31V      3V         3.31V
2.4ns     3.22V      3.01V      2.53V
2.6ns     3.15V      3V         2.36V
3ns       2.92V      2.96V      2.23V
3.8ns     2.46V      2.76V      2.2V
4.4ns     2.21V      2.48V      2.19V
5.6ns     2.16V      2.16V      2.19V
10ns      2.15V      2.09V      2.18V
[Falling Waveform]
R_fixture = 50.00
V_fixture = 0.000
V_fixture_min = 0.000
V_fixture_max = 0.000
| time   V(typ)   V(min)   V(max)
0s        940mV      920mV      1.31V
800ps     930mV      920mV      1.25V
1.2ns     800mV      910mV      570mV
1.6ns     510mV      840mV      190mV
1.8ns     340mV      770mV      74.98mV
2ns       220mV      680mV      33.53mV
2.4ns     79.14mV    450mV      15.55mV
2.8ns     27.29mV    220mV      8.88mV
3.6ns     11.05mV    38.96mV    5.27mV
10ns      1.21mV     1.67mV     1.01mV
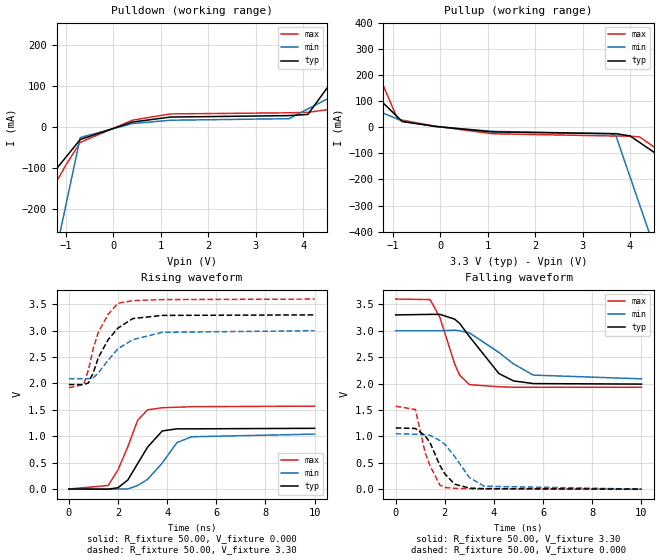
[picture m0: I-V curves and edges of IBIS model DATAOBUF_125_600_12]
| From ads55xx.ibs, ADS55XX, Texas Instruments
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|   Model DATAOBUF_125_600_12
[Model]   DATAOBUF_125_600_12
Model_type   Output
Polarity   Non-Inverting
Vmeas =   1.65V
C_comp   3.00pF   3.00pF   3.00pF
[Temperature Range]   50.00   0.10k   -20.00
[Voltage Range]   3.30V   3.00V   3.60V
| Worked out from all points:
|   slope of the pulldown table from 0 to 0.495 V, typ, clamps not added: 34 ohm
|   slope of the pullup table from 0 to 0.495 V, typ, clamps not added: 48 ohm
|   rising waveform, R_fixture 50.00, V_fixture 0.000: 20-80 % time 873ps typ, 1.06ns min, 819ps max; typ from 0 V to 1.15 V
|   rising waveform, R_fixture 50.00, V_fixture 3.30: 20-80 % time 948ps typ, 1.2ns min, 749ps max; typ from 1.98 V to 3.3 V
|   falling waveform, R_fixture 50.00, V_fixture 3.30: 20-80 % time 1.33ns typ, 1.48ns min, 715ps max; typ from 3.3 V to 1.99 V
|   falling waveform, R_fixture 50.00, V_fixture 0.000: 20-80 % time 769ps typ, 1.01ns min, 577ps max; typ from 1.16 V to 0.001 V
[Pulldown]
| voltage   I(typ)   I(min)   I(max)
-3.3V     -400mA     -1.437A    -559.4mA
-2.3V     -257.7mA   -893.7mA   -356.1mA
-1.7V     -172.4mA   -568.1mA   -234.1mA
-1.5V     -143.9mA   -459.5mA   -193.5mA
-1V       -72.74mA   -188.1mA   -91.81mA
-700mV    -30.05mA   -25.27mA   -37.08mA
400mV     12.36mA    8.63mA     16.91mA
1.2V      24.51mA    16.8mA     32.16mA
3.7V      28.06mA    20.56mA    34.85mA
4.1V      30.93mA    44.32mA    35.89mA
5.5V      253.1mA    127.5mA    58.57mA
6.6V      427.7mA    192.8mA    77.44mA
[Pullup]
| voltage   I(typ)   I(min)   I(max)
-3.3V     459.8mA    212.8mA    1.047A
-1.9V     214.2mA    106.6mA    454.3mA
-900mV    38.8mA     30.68mA    30.59mA
-800mV    21.26mA    23.09mA    26.79mA
-100mV    2.76mA     2.24mA     3.28mA
1.1V      -18.33mA   -16.1mA    -25.34mA
3.6V      -24.77mA   -25.44mA   -33.71mA
3.7V      -24.93mA   -32.06mA   -33.8mA
4V        -33.64mA   -190.3mA   -34.33mA
4.2V      -58.34mA   -295.9mA   -37.54mA
4.5V      -95.39mA   -454.1mA   -75.01mA
6.6V      -354.7mA   -1.562A    -394.9mA
[Ramp]
| variable   typ   min   max
dV/dt_r   0.69/0.86n   0.63/1.12n   0.94/0.85n
dV/dt_f   0.79/1.31n   0.54/1.46n   1.00/0.71n
R_load = 50.00
[Rising Waveform]
R_fixture = 50.00
V_fixture = 0.000
V_fixture_min = 0.000
V_fixture_max = 0.000
| time   V(typ)   V(min)   V(max)
0s        12.98nV    17.34nV    24.86nV
1.6ns     -3.5mV     -2.33mV    65.35mV
2ns       23.45mV    -2.42mV    360mV
2.4ns     170mV      360uV      800mV
2.8ns     480mV      66.25mV    1.3V
3.2ns     790mV      180mV      1.5V
3.8ns     1.1V       490mV      1.54V
4.4ns     1.14V      880mV      1.55V
5ns       1.14V      990mV      1.56V
10ns      1.15V      1.04V      1.57V
[Rising Waveform]
R_fixture = 50.00
V_fixture = 3.30
V_fixture_min = 3.00
V_fixture_max = 3.60
| time   V(typ)   V(min)   V(max)
0s        1.98V      2.09V      1.92V
600ps     1.98V      2.09V      1.98V
800ps     2.01V      2.09V      2.26V
1ns       2.21V      2.11V      2.67V
1.2ns     2.49V      2.2V       2.97V
1.6ns     2.83V      2.44V      3.31V
2ns       3.05V      2.66V      3.52V
2.6ns     3.23V      2.83V      3.57V
3.8ns     3.29V      2.97V      3.59V
10ns      3.3V       3V         3.6V
[Falling Waveform]
R_fixture = 50.00
V_fixture = 3.30
V_fixture_min = 3.00
V_fixture_max = 3.60
| time   V(typ)   V(min)   V(max)
0s        3.3V       3V         3.6V
1.4ns     3.31V      3V         3.59V
1.8ns     3.31V      3V         3.25V
2.4ns     3.22V      3.01V      2.37V
2.6ns     3.14V      3V         2.16V
3ns       2.89V      2.96V      1.98V
4.2ns     2.19V      2.59V      1.94V
4.8ns     2.05V      2.37V      1.93V
5.6ns     2V         2.16V      1.93V
10ns      1.99V      2.09V      1.93V
[Falling Waveform]
R_fixture = 50.00
V_fixture = 0.000
V_fixture_min = 0.000
V_fixture_max = 0.000
| time   V(typ)   V(min)   V(max)
0s        1.16V      1.05V      1.57V
800ps     1.15V      1.04V      1.51V
1.2ns     1.01V      1.03V      690mV
1.4ns     880mV      1.02V      440mV
1.8ns     450mV      920mV      76.52mV
2ns       290mV      850mV      33.19mV
2.4ns     95.54mV    620mV      15.95mV
3ns       20.73mV    220mV      7.4mV
3.6ns     11.5mV     56.88mV    5.17mV
10ns      1.17mV     1.75mV     970uV
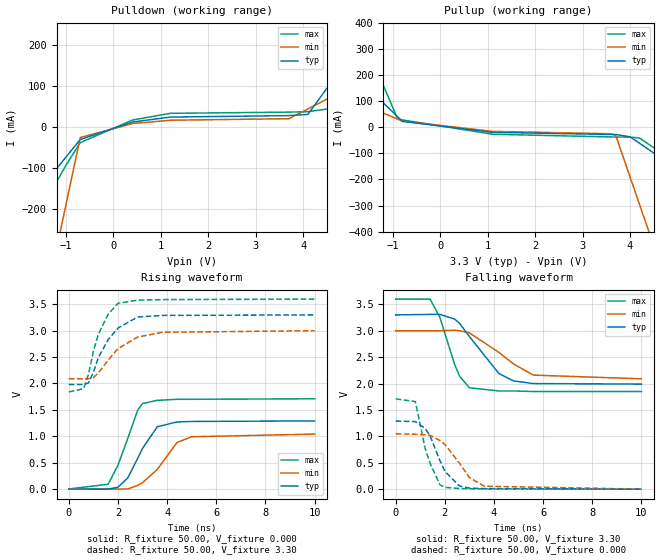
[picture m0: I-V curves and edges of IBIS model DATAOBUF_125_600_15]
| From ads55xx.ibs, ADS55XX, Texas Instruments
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|   Model DATAOBUF_125_600_15
[Model]   DATAOBUF_125_600_15
Model_type   Output
Polarity   Non-Inverting
Vmeas =   1.65V
C_comp   3.00pF   3.00pF   3.00pF
[Temperature Range]   50.00   0.10k   -20.00
[Voltage Range]   3.30V   3.00V   3.60V
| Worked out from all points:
|   slope of the pulldown table from 0 to 0.495 V, typ, clamps not added: 34 ohm
|   slope of the pullup table from 0 to 0.495 V, typ, clamps not added: 45.2 ohm
|   rising waveform, R_fixture 50.00, V_fixture 0.000: 20-80 % time 871ps typ, 1.06ns min, 812ps max; typ from 0 V to 1.29 V
|   rising waveform, R_fixture 50.00, V_fixture 3.30: 20-80 % time 948ps typ, 1.2ns min, 725ps max; typ from 1.98 V to 3.3 V
|   falling waveform, R_fixture 50.00, V_fixture 3.30: 20-80 % time 1.33ns typ, 1.48ns min, 745ps max; typ from 3.3 V to 1.99 V
|   falling waveform, R_fixture 50.00, V_fixture 0.000: 20-80 % time 756ps typ, 1.01ns min, 568ps max; typ from 1.29 V to 0.001 V
[Pulldown]
| voltage   I(typ)   I(min)   I(max)
-3.3V     -400mA     -1.437A    -561.5mA
-2.3V     -257.7mA   -893.7mA   -357.6mA
-1.7V     -172.4mA   -568.1mA   -235.2mA
-1.5V     -143.9mA   -459.5mA   -194.5mA
-1V       -72.74mA   -188.1mA   -92.51mA
-700mV    -30.05mA   -25.27mA   -37.6mA
400mV     12.36mA    8.63mA     17.3mA
1.2V      24.51mA    16.8mA     33.6mA
3.7V      28.06mA    20.56mA    36.5mA
4.1V      30.93mA    44.32mA    37.53mA
5.5V      253.1mA    127.5mA    60.22mA
6.6V      427.7mA    192.8mA    79.08mA
[Pullup]
| voltage   I(typ)   I(min)   I(max)
-3.3V     462.5mA    212.8mA    1.051A
-3.1V     427.3mA    197.7mA    965.6mA
-1.9V     215.8mA    106.6mA    456.1mA
-900mV    39.63mA    30.68mA    31.49mA
-800mV    22.01mA    23.09mA    27.61mA
1.1V      -19.9mA    -16.1mA    -27.22mA
3.6V      -28.09mA   -25.44mA   -37.51mA
3.7V      -28.27mA   -32.06mA   -37.61mA
4V        -37mA      -190.3mA   -38.17mA
4.2V      -61.72mA   -295.9mA   -41.39mA
4.5V      -98.8mA    -454.1mA   -78.88mA
6.6V      -358.4mA   -1.562A    -399mA
[Ramp]
| variable   typ   min   max
dV/dt_r   0.77/0.86n   0.63/1.12n   1.03/0.82n
dV/dt_f   0.79/1.30n   0.54/1.46n   1.05/0.74n
R_load = 50.00
[Rising Waveform]
R_fixture = 50.00
V_fixture = 0.000
V_fixture_min = 0.000
V_fixture_max = 0.000
| time   V(typ)   V(min)   V(max)
0s        13.07nV    17.34nV    24.73nV
1.6ns     -3.69mV    -2.33mV    89.61mV
2ns       33.25mV    -2.42mV    450mV
2.4ns     210mV      360uV      960mV
2.8ns     580mV      66.27mV    1.49V
3ns       770mV      120mV      1.62V
3.6ns     1.18V      370mV      1.68V
4.4ns     1.27V      880mV      1.7V
5ns       1.28V      990mV      1.7V
10ns      1.29V      1.04V      1.71V
[Rising Waveform]
R_fixture = 50.00
V_fixture = 3.30
V_fixture_min = 3.00
V_fixture_max = 3.60
| time   V(typ)   V(min)   V(max)
0s        1.98V      2.09V      1.84V
600ps     1.98V      2.09V      1.9V
800ps     2.01V      2.09V      2.17V
1ns       2.21V      2.11V      2.61V
1.2ns     2.49V      2.2V       2.93V
1.6ns     2.83V      2.44V      3.31V
2ns       3.05V      2.66V      3.52V
2.8ns     3.26V      2.88V      3.58V
3.8ns     3.29V      2.97V      3.59V
10ns      3.3V       3V         3.6V
[Falling Waveform]
R_fixture = 50.00
V_fixture = 3.30
V_fixture_min = 3.00
V_fixture_max = 3.60
| time   V(typ)   V(min)   V(max)
0s        3.3V       3V         3.6V
1.4ns     3.31V      3V         3.6V
1.8ns     3.31V      3V         3.25V
2.4ns     3.22V      3.01V      2.36V
2.6ns     3.14V      3V         2.14V
3ns       2.89V      2.96V      1.92V
4.2ns     2.19V      2.59V      1.86V
4.8ns     2.05V      2.37V      1.86V
5.6ns     2V         2.16V      1.85V
10ns      1.99V      2.09V      1.85V
[Falling Waveform]
R_fixture = 50.00
V_fixture = 0.000
V_fixture_min = 0.000
V_fixture_max = 0.000
| time   V(typ)   V(min)   V(max)
0s        1.29V      1.05V      1.71V
800ps     1.28V      1.04V      1.66V
1.2ns     1.15V      1.03V      770mV
1.4ns     1.01V      1.02V      490mV
1.8ns     540mV      920mV      83.27mV
2ns       340mV      850mV      35.46mV
2.6ns     59.96mV    490mV      12.58mV
3ns       21.68mV    220mV      7.57mV
3.6ns     11.95mV    56.88mV    5.2mV
10ns      1.18mV     1.75mV     960uV
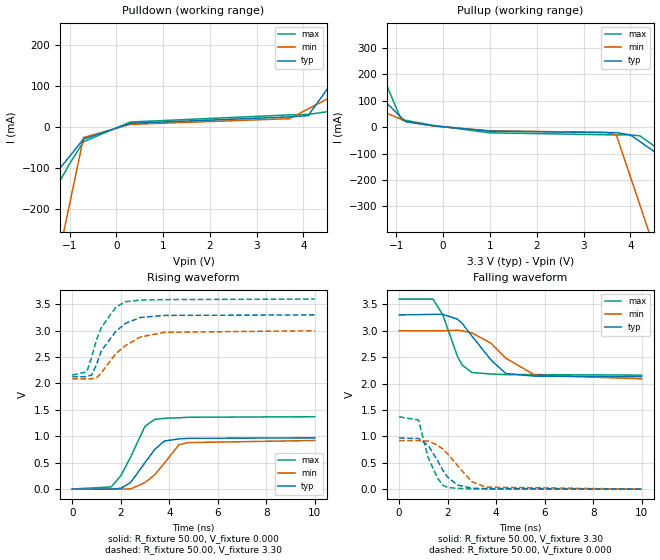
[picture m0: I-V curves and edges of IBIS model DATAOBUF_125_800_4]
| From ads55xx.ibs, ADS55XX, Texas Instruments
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|   Model DATAOBUF_125_800_4
[Model]   DATAOBUF_125_800_4
Model_type   Output
Polarity   Non-Inverting
Vmeas =   1.65V
C_comp   3.00pF   3.00pF   3.00pF
[Temperature Range]   50.00   0.10k   -20.00
[Voltage Range]   3.30V   3.00V   3.60V
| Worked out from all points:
|   slope of the pulldown table from 0 to 0.495 V, typ, clamps not added: 36.4 ohm
|   slope of the pullup table from 0 to 0.495 V, typ, clamps not added: 52.8 ohm
|   rising waveform, R_fixture 50.00, V_fixture 0.000: 20-80 % time 888ps typ, 971ps min, 854ps max; typ from 0 V to 0.97 V
|   rising waveform, R_fixture 50.00, V_fixture 3.30: 20-80 % time 987ps typ, 1.2ns min, 800ps max; typ from 2.13 V to 3.3 V
|   falling waveform, R_fixture 50.00, V_fixture 3.30: 20-80 % time 1.21ns typ, 1.51ns min, 697ps max; typ from 3.3 V to 2.13 V
|   falling waveform, R_fixture 50.00, V_fixture 0.000: 20-80 % time 788ps typ, 1.03ns min, 592ps max; typ from 0.97 V to 0.001 V
[Pulldown]
| voltage   I(typ)   I(min)   I(max)
-3.3V     -395.6mA   -1.437A    -552.2mA
-2.3V     -254.6mA   -893.7mA   -351mA
-1.9V     -198.2mA   -676.6mA   -270.5mA
-1.7V     -170mA     -568.1mA   -230.2mA
-1.5V     -141.8mA   -459.5mA   -190mA
-1V       -71.29mA   -188.1mA   -89.4mA
-700mV    -28.99mA   -25.27mA   -35.31mA
300mV     9.16mA     6.82mA     12.42mA
3.7V      25.02mA    20.56mA    29.82mA
4.1V      27.88mA    44.32mA    30.88mA
5.5V      250.1mA    127.5mA    53.64mA
6.6V      424.6mA    192.8mA    72.56mA
[Pullup]
| voltage   I(typ)   I(min)   I(max)
-3.3V     455.9mA    209.9mA    1.044A
-1.9V     211.9mA    104.8mA    451.9mA
-900mV    37.58mA    29.85mA    29.32mA
-800mV    20.15mA    22.35mA    25.64mA
-200mV    4.93mA     4.11mA     6.27mA
1V        -15.21mA   -13.78mA   -21.57mA
3.5V      -20.37mA   -20.26mA   -28.82mA
3.7V      -20.6mA    -28.94mA   -28.99mA
4V        -29.27mA   -187.2mA   -29.49mA
4.2V      -53.97mA   -292.7mA   -32.68mA
4.5V      -91.02mA   -450.9mA   -70.13mA
6.6V      -350.4mA   -1.559A    -390mA
[Ramp]
| variable   typ   min   max
dV/dt_r   0.58/0.87n   0.55/1.00n   0.82/0.89n
dV/dt_f   0.70/1.17n   0.54/1.47n   0.86/0.67n
R_load = 50.00
[Rising Waveform]
R_fixture = 50.00
V_fixture = 0.000
V_fixture_min = 0.000
V_fixture_max = 0.000
| time   V(typ)   V(min)   V(max)
0s        13.3nV     17.34nV    25.67nV
1.6ns     -3.04mV    -2.33mV    39.27mV
2ns       13.11mV    -2.42mV    250mV
2.4ns     120mV      280uV      600mV
3ns       500mV      120mV      1.19V
3.4ns     750mV      270mV      1.32V
3.8ns     910mV      490mV      1.34V
4.4ns     950mV      840mV      1.35V
4.8ns     960mV      880mV      1.36V
10ns      970mV      920mV      1.37V
[Rising Waveform]
R_fixture = 50.00
V_fixture = 3.30
V_fixture_min = 3.00
V_fixture_max = 3.60
| time   V(typ)   V(min)   V(max)
0s        2.13V      2.09V      2.16V
600ps     2.13V      2.09V      2.22V
800ps     2.16V      2.09V      2.5V
1ns       2.36V      2.11V      2.83V
1.2ns     2.62V      2.2V       3.06V
1.8ns     2.99V      2.57V      3.45V
2.2ns     3.14V      2.72V      3.55V
2.8ns     3.25V      2.88V      3.58V
3.8ns     3.29V      2.97V      3.59V
10ns      3.3V       3V         3.6V
[Falling Waveform]
R_fixture = 50.00
V_fixture = 3.30
V_fixture_min = 3.00
V_fixture_max = 3.60
| time   V(typ)   V(min)   V(max)
0s        3.3V       3V         3.6V
1.4ns     3.31V      3V         3.6V
1.8ns     3.31V      3V         3.3V
2.4ns     3.22V      3.01V      2.52V
2.6ns     3.14V      3V         2.35V
3ns       2.9V       2.96V      2.21V
3.8ns     2.44V      2.76V      2.18V
4.4ns     2.19V      2.48V      2.17V
5.6ns     2.14V      2.16V      2.17V
10ns      2.13V      2.09V      2.16V
[Falling Waveform]
R_fixture = 50.00
V_fixture = 0.000
V_fixture_min = 0.000
V_fixture_max = 0.000
| time   V(typ)   V(min)   V(max)
0s        970mV      920mV      1.37V
800ps     960mV      920mV      1.31V
1.2ns     830mV      910mV      590mV
1.6ns     530mV      830mV      200mV
1.8ns     360mV      760mV      76.86mV
2ns       230mV      670mV      33.91mV
2.4ns     80.61mV    450mV      15.71mV
3ns       19.52mV    140mV      7.45mV
3.6ns     11.03mV    38.7mV     5.28mV
10ns      1.2mV      1.67mV     1mV
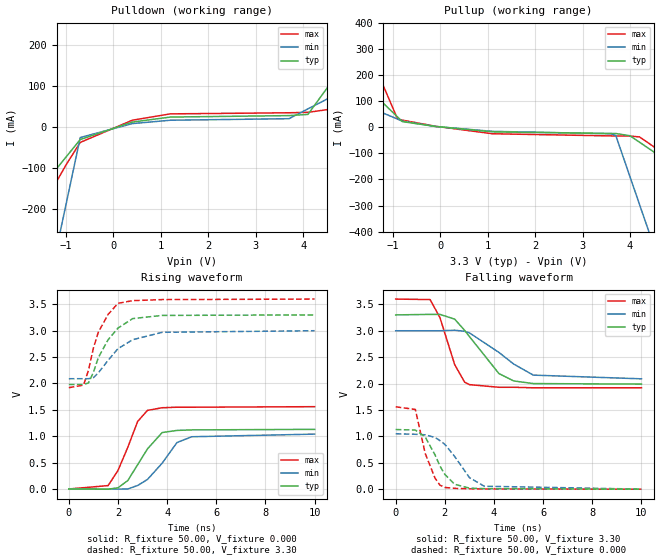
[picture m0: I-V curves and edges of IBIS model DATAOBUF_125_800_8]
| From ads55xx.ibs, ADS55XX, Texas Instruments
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|   Model DATAOBUF_125_800_8
[Model]   DATAOBUF_125_800_8
Model_type   Output
Polarity   Non-Inverting
Vmeas =   1.65V
C_comp   3.00pF   3.00pF   3.00pF
[Temperature Range]   50.00   0.10k   -20.00
[Voltage Range]   3.30V   3.00V   3.60V
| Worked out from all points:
|   slope of the pulldown table from 0 to 0.495 V, typ, clamps not added: 34 ohm
|   slope of the pullup table from 0 to 0.495 V, typ, clamps not added: 48.6 ohm
|   rising waveform, R_fixture 50.00, V_fixture 0.000: 20-80 % time 882ps typ, 1.06ns min, 820ps max; typ from 0 V to 1.13 V
|   rising waveform, R_fixture 50.00, V_fixture 3.30: 20-80 % time 948ps typ, 1.2ns min, 743ps max; typ from 1.98 V to 3.3 V
|   falling waveform, R_fixture 50.00, V_fixture 3.30: 20-80 % time 1.33ns typ, 1.48ns min, 717ps max; typ from 3.3 V to 1.99 V
|   falling waveform, R_fixture 50.00, V_fixture 0.000: 20-80 % time 765ps typ, 1.01ns min, 573ps max; typ from 1.13 V to 0.001 V
[Pulldown]
| voltage   I(typ)   I(min)   I(max)
-3.3V     -400mA     -1.437A    -559.7mA
-2.3V     -257.7mA   -893.7mA   -356.3mA
-1.7V     -172.4mA   -568.1mA   -234.3mA
-1.5V     -143.9mA   -459.5mA   -193.6mA
-1V       -72.74mA   -188.1mA   -91.87mA
-700mV    -30.05mA   -25.27mA   -37.12mA
400mV     12.36mA    8.63mA     16.94mA
1.2V      24.51mA    16.8mA     32.25mA
3.7V      28.06mA    20.56mA    34.95mA
4.1V      30.93mA    44.32mA    36mA
5.5V      253.1mA    127.5mA    58.62mA
6.6V      427.7mA    192.8mA    77.43mA
[Pullup]
| voltage   I(typ)   I(min)   I(max)
-3.3V     459.4mA    212.8mA    1.047A
-1.9V     213.9mA    106.6mA    454.2mA
-900mV    38.64mA    30.68mA    30.55mA
-800mV    21.11mA    23.09mA    26.76mA
-100mV    2.74mA     2.24mA     3.28mA
1.1V      -18.02mA   -16.1mA    -25.27mA
3.6V      -24.15mA   -25.44mA   -33.56mA
3.7V      -24.31mA   -32.06mA   -33.66mA
4V        -33.01mA   -190.3mA   -34.18mA
4.2V      -57.71mA   -295.9mA   -37.39mA
4.5V      -94.76mA   -454.1mA   -74.86mA
6.6V      -354.1mA   -1.562A    -394.8mA
[Ramp]
| variable   typ   min   max
dV/dt_r   0.68/0.86n   0.63/1.12n   0.94/0.85n
dV/dt_f   0.79/1.31n   0.54/1.46n   1.01/0.71n
R_load = 50.00
[Rising Waveform]
R_fixture = 50.00
V_fixture = 0.000
V_fixture_min = 0.000
V_fixture_max = 0.000
| time   V(typ)   V(min)   V(max)
0s        12.96nV    17.34nV    24.84nV
1.6ns     -3.46mV    -2.33mV    64.42mV
2ns       21.74mV    -2.42mV    350mV
2.4ns     160mV      360uV      790mV
2.8ns     460mV      66.25mV    1.28V
3.2ns     760mV      180mV      1.49V
3.8ns     1.07V      490mV      1.54V
4.4ns     1.11V      880mV      1.55V
5ns       1.12V      990mV      1.55V
10ns      1.13V      1.04V      1.56V
[Rising Waveform]
R_fixture = 50.00
V_fixture = 3.30
V_fixture_min = 3.00
V_fixture_max = 3.60
| time   V(typ)   V(min)   V(max)
0s        1.98V      2.09V      1.92V
600ps     1.98V      2.09V      1.97V
800ps     2.01V      2.09V      2.25V
1ns       2.21V      2.11V      2.67V
1.2ns     2.49V      2.2V       2.97V
1.6ns     2.83V      2.44V      3.31V
2ns       3.05V      2.66V      3.52V
2.6ns     3.23V      2.83V      3.57V
3.8ns     3.29V      2.97V      3.59V
10ns      3.3V       3V         3.6V
[Falling Waveform]
R_fixture = 50.00
V_fixture = 3.30
V_fixture_min = 3.00
V_fixture_max = 3.60
| time   V(typ)   V(min)   V(max)
0s        3.3V       3V         3.6V
1.4ns     3.31V      3V         3.59V
1.8ns     3.31V      3V         3.25V
2.4ns     3.22V      3.01V      2.36V
2.8ns     3.01V      2.99V      2.03V
3ns       2.89V      2.96V      1.98V
4.2ns     2.19V      2.59V      1.93V
4.8ns     2.05V      2.37V      1.93V
5.6ns     2V         2.16V      1.92V
10ns      1.99V      2.09V      1.92V
[Falling Waveform]
R_fixture = 50.00
V_fixture = 0.000
V_fixture_min = 0.000
V_fixture_max = 0.000
| time   V(typ)   V(min)   V(max)
0s        1.13V      1.05V      1.56V
800ps     1.12V      1.04V      1.51V
1.2ns     990mV      1.03V      680mV
1.6ns     650mV      980mV      210mV
1.8ns     440mV      920mV      76.39mV
2ns       280mV      850mV      33.27mV
2.4ns     93.11mV    620mV      15.99mV
3ns       20.39mV    220mV      7.4mV
3.6ns     11.4mV     56.88mV    5.17mV
10ns      1.17mV     1.75mV     970uV
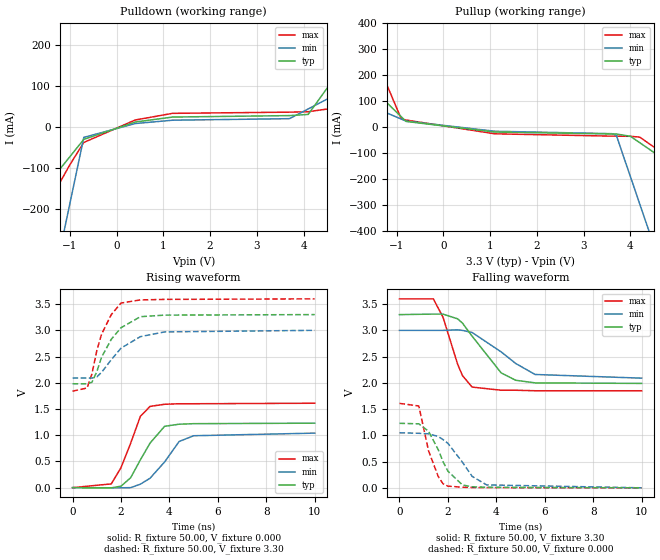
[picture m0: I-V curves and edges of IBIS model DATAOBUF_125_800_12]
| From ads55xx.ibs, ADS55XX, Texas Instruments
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|   Model DATAOBUF_125_800_12
[Model]   DATAOBUF_125_800_12
Model_type   Output
Polarity   Non-Inverting
Vmeas =   1.65V
C_comp   3.00pF   3.00pF   3.00pF
[Temperature Range]   50.00   0.10k   -20.00
[Voltage Range]   3.30V   3.00V   3.60V
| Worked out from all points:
|   slope of the pulldown table from 0 to 0.495 V, typ, clamps not added: 34 ohm
|   slope of the pullup table from 0 to 0.495 V, typ, clamps not added: 46.5 ohm
|   rising waveform, R_fixture 50.00, V_fixture 0.000: 20-80 % time 881ps typ, 1.06ns min, 811ps max; typ from 0 V to 1.23 V
|   rising waveform, R_fixture 50.00, V_fixture 3.30: 20-80 % time 948ps typ, 1.2ns min, 732ps max; typ from 1.98 V to 3.3 V
|   falling waveform, R_fixture 50.00, V_fixture 3.30: 20-80 % time 1.33ns typ, 1.48ns min, 745ps max; typ from 3.3 V to 1.99 V
|   falling waveform, R_fixture 50.00, V_fixture 0.000: 20-80 % time 765ps typ, 1.01ns min, 571ps max; typ from 1.23 V to 0.001 V
[Pulldown]
| voltage   I(typ)   I(min)   I(max)
-3.3V     -400mA     -1.437A    -561.5mA
-2.3V     -257.7mA   -893.7mA   -357.6mA
-1.7V     -172.4mA   -568.1mA   -235.3mA
-1.5V     -143.9mA   -459.5mA   -194.5mA
-1V       -72.74mA   -188.1mA   -92.53mA
-700mV    -30.05mA   -25.27mA   -37.61mA
400mV     12.36mA    8.63mA     17.3mA
1.2V      24.51mA    16.8mA     33.6mA
3.7V      28.06mA    20.56mA    36.5mA
4.1V      30.93mA    44.32mA    37.53mA
5.5V      253.1mA    127.5mA    60.15mA
6.6V      427.7mA    192.8mA    78.96mA
[Pullup]
| voltage   I(typ)   I(min)   I(max)
-3.3V     461.2mA    212.8mA    1.048A
-3.1V     426mA      197.7mA    963.7mA
-1.9V     215.1mA    106.6mA    454.9mA
-900mV    39.25mA    30.68mA    30.88mA
-800mV    21.67mA    23.09mA    27.06mA
1.1V      -19.18mA   -16.1mA    -25.95mA
3.6V      -26.53mA   -25.44mA   -34.9mA
3.7V      -26.7mA    -32.06mA   -35mA
4V        -35.42mA   -190.3mA   -35.54mA
4.2V      -60.14mA   -295.9mA   -38.75mA
4.5V      -97.22mA   -454.1mA   -76.23mA
6.6V      -356.8mA   -1.562A    -396.3mA
[Ramp]
| variable   typ   min   max
dV/dt_r   0.74/0.86n   0.63/1.12n   0.97/0.84n
dV/dt_f   0.79/1.30n   0.54/1.46n   1.05/0.74n
R_load = 50.00
[Rising Waveform]
R_fixture = 50.00
V_fixture = 0.000
V_fixture_min = 0.000
V_fixture_max = 0.000
| time   V(typ)   V(min)   V(max)
0s        13.02nV    17.34nV    24.63nV
1.6ns     -3.59mV    -2.33mV    71.85mV
2ns       27.89mV    -2.42mV    380mV
2.4ns     190mV      360uV      850mV
2.8ns     530mV      66.25mV    1.36V
3.2ns     850mV      180mV      1.55V
3.8ns     1.17V      490mV      1.59V
4.4ns     1.21V      880mV      1.6V
5ns       1.22V      990mV      1.6V
10ns      1.23V      1.04V      1.61V
[Rising Waveform]
R_fixture = 50.00
V_fixture = 3.30
V_fixture_min = 3.00
V_fixture_max = 3.60
| time   V(typ)   V(min)   V(max)
0s        1.98V      2.09V      1.84V
600ps     1.98V      2.09V      1.9V
800ps     2.01V      2.09V      2.17V
1ns       2.21V      2.11V      2.61V
1.2ns     2.49V      2.2V       2.93V
1.6ns     2.83V      2.44V      3.3V
2ns       3.05V      2.66V      3.52V
2.8ns     3.26V      2.88V      3.58V
3.8ns     3.29V      2.97V      3.59V
10ns      3.3V       3V         3.6V
[Falling Waveform]
R_fixture = 50.00
V_fixture = 3.30
V_fixture_min = 3.00
V_fixture_max = 3.60
| time   V(typ)   V(min)   V(max)
0s        3.3V       3V         3.6V
1.4ns     3.31V      3V         3.6V
1.8ns     3.31V      3V         3.25V
2.4ns     3.22V      3.01V      2.36V
2.6ns     3.14V      3V         2.14V
3ns       2.89V      2.96V      1.92V
4.2ns     2.19V      2.59V      1.86V
4.8ns     2.05V      2.37V      1.86V
5.6ns     2V         2.16V      1.85V
10ns      1.99V      2.09V      1.85V
[Falling Waveform]
R_fixture = 50.00
V_fixture = 0.000
V_fixture_min = 0.000
V_fixture_max = 0.000
| time   V(typ)   V(min)   V(max)
0s        1.23V      1.05V      1.61V
800ps     1.22V      1.04V      1.56V
1.2ns     1.08V      1.03V      710mV
1.6ns     730mV      980mV      220mV
1.8ns     500mV      920mV      78.38mV
2ns       320mV      850mV      34.1mV
2.6ns     56.52mV    490mV      12.32mV
3ns       20.83mV    220mV      7.44mV
3.6ns     11.67mV    56.87mV    5.14mV
10ns      1.17mV     1.75mV     960uV
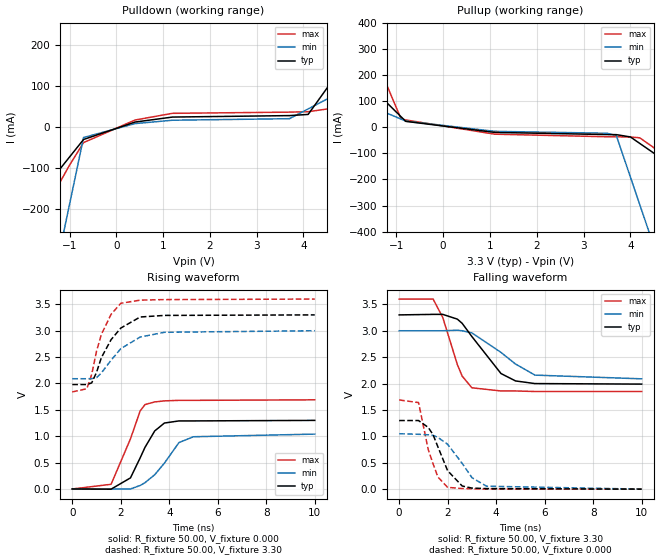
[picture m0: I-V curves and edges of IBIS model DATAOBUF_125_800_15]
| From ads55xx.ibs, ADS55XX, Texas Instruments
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|   Model DATAOBUF_125_800_15
[Model]   DATAOBUF_125_800_15
Model_type   Output
Polarity   Non-Inverting
Vmeas =   1.65V
C_comp   3.00pF   3.00pF   3.00pF
[Temperature Range]   50.00   0.10k   -20.00
[Voltage Range]   3.30V   3.00V   3.60V
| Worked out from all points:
|   slope of the pulldown table from 0 to 0.495 V, typ, clamps not added: 34 ohm
|   slope of the pullup table from 0 to 0.495 V, typ, clamps not added: 44.9 ohm
|   rising waveform, R_fixture 50.00, V_fixture 0.000: 20-80 % time 858ps typ, 1.06ns min, 802ps max; typ from 0 V to 1.3 V
|   rising waveform, R_fixture 50.00, V_fixture 3.30: 20-80 % time 948ps typ, 1.2ns min, 725ps max; typ from 1.98 V to 3.3 V
|   falling waveform, R_fixture 50.00, V_fixture 3.30: 20-80 % time 1.33ns typ, 1.48ns min, 745ps max; typ from 3.3 V to 1.99 V
|   falling waveform, R_fixture 50.00, V_fixture 0.000: 20-80 % time 742ps typ, 1.01ns min, 565ps max; typ from 1.3 V to 0.001 V
[Pulldown]
| voltage   I(typ)   I(min)   I(max)
-3.3V     -400mA     -1.437A    -561.5mA
-2.3V     -257.7mA   -893.7mA   -357.6mA
-1.7V     -172.4mA   -568.1mA   -235.3mA
-1.5V     -143.9mA   -459.5mA   -194.5mA
-1V       -72.74mA   -188.1mA   -92.53mA
-700mV    -30.05mA   -25.27mA   -37.61mA
400mV     12.36mA    8.63mA     17.3mA
1.2V      24.51mA    16.8mA     33.6mA
3.7V      28.06mA    20.56mA    36.5mA
4.1V      30.93mA    44.32mA    37.53mA
5.5V      253.1mA    127.5mA    60.15mA
6.6V      427.7mA    192.8mA    78.96mA
[Pullup]
| voltage   I(typ)   I(min)   I(max)
-3.3V     462.9mA    212.8mA    1.05A
-3.1V     427.6mA    197.7mA    965.3mA
-1.9V     216mA      106.6mA    455.9mA
-900mV    39.74mA    30.68mA    31.35mA
-800mV    22.11mA    23.09mA    27.48mA
1.1V      -20.1mA    -16.1mA    -26.94mA
3.5V      -28.42mA   -23.36mA   -36.8mA
3.7V      -28.71mA   -32.06mA   -37.02mA
4V        -37.45mA   -190.3mA   -37.57mA
4.2V      -62.17mA   -295.9mA   -40.78mA
4.5V      -99.25mA   -454.1mA   -78.27mA
6.6V      -358.8mA   -1.562A    -398.3mA
[Ramp]
| variable   typ   min   max
dV/dt_r   0.78/0.85n   0.63/1.12n   1.01/0.81n
dV/dt_f   0.79/1.30n   0.54/1.46n   1.05/0.74n
R_load = 50.00
[Rising Waveform]
R_fixture = 50.00
V_fixture = 0.000
V_fixture_min = 0.000
V_fixture_max = 0.000
| time   V(typ)   V(min)   V(max)
0s        13.08nV    17.34nV    24.73nV
1.6ns     -3.71mV    -2.33mV    88.46mV
2.4ns     210mV      360uV      950mV
2.8ns     590mV      66.26mV    1.48V
3ns       790mV      120mV      1.6V
3.4ns     1.1V       270mV      1.65V
3.8ns     1.25V      490mV      1.67V
4.4ns     1.29V      880mV      1.68V
5ns       1.29V      990mV      1.68V
10ns      1.3V       1.04V      1.69V
[Rising Waveform]
R_fixture = 50.00
V_fixture = 3.30
V_fixture_min = 3.00
V_fixture_max = 3.60
| time   V(typ)   V(min)   V(max)
0s        1.98V      2.09V      1.84V
600ps     1.98V      2.09V      1.9V
800ps     2.01V      2.09V      2.17V
1ns       2.21V      2.11V      2.61V
1.2ns     2.49V      2.2V       2.93V
1.6ns     2.83V      2.44V      3.31V
2ns       3.05V      2.66V      3.52V
2.8ns     3.26V      2.88V      3.58V
3.8ns     3.29V      2.97V      3.59V
10ns      3.3V       3V         3.6V
[Falling Waveform]
R_fixture = 50.00
V_fixture = 3.30
V_fixture_min = 3.00
V_fixture_max = 3.60
| time   V(typ)   V(min)   V(max)
0s        3.3V       3V         3.6V
1.4ns     3.31V      3V         3.6V
1.8ns     3.31V      3V         3.25V
2.4ns     3.22V      3.01V      2.36V
2.6ns     3.14V      3V         2.14V
3ns       2.89V      2.96V      1.92V
4.2ns     2.19V      2.59V      1.86V
4.8ns     2.05V      2.37V      1.86V
5.6ns     2V         2.16V      1.85V
10ns      1.99V      2.09V      1.85V
[Falling Waveform]
R_fixture = 50.00
V_fixture = 0.000
V_fixture_min = 0.000
V_fixture_max = 0.000
| time   V(typ)   V(min)   V(max)
0s        1.3V       1.05V      1.69V
800ps     1.3V       1.04V      1.64V
1.2ns     1.17V      1.03V      750mV
1.4ns     1.03V      1.02V      480mV
1.6ns     800mV      980mV      230mV
2ns       350mV      850mV      35.19mV
2.6ns     61mV       490mV      12.53mV
3ns       21.7mV     220mV      7.55mV
3.6ns     11.98mV    56.87mV    5.19mV
10ns      1.18mV     1.75mV     960uV
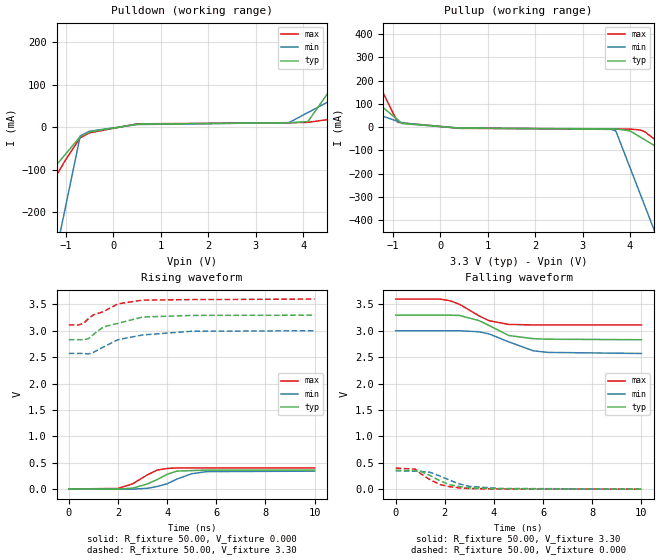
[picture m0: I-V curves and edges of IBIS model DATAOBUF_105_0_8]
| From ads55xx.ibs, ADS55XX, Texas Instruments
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|   Model DATAOBUF_105_0_8
[Model]   DATAOBUF_105_0_8
Model_type   Output
Polarity   Non-Inverting
Vmeas =   1.65V
C_comp   3.00pF   3.00pF   3.00pF
[Temperature Range]   50.00   0.10k   -20.00
[Voltage Range]   3.30V   3.00V   3.60V
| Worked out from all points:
|   slope of the pulldown table from 0 to 0.495 V, typ, clamps not added: 70.8 ohm
|   slope of the pullup table from 0 to 0.495 V, typ, clamps not added: 95.3 ohm
|   rising waveform, R_fixture 50.00, V_fixture 0.000: 20-80 % time 1.04ns typ, 1.15ns min, 910ps max; typ from 0 V to 0.36 V
|   rising waveform, R_fixture 50.00, V_fixture 3.30: 20-80 % time 1.36ns typ, 1.62ns min, 1.21ns max; typ from 2.83 V to 3.29 V
|   falling waveform, R_fixture 50.00, V_fixture 3.30: 20-80 % time 1.19ns typ, 1.4ns min, 1.12ns max; typ from 3.29 V to 2.83 V
|   falling waveform, R_fixture 50.00, V_fixture 0.000: 20-80 % time 1.06ns typ, 1.15ns min, 920ps max; typ from 0.36 V to 0.002 V
[Pulldown]
| voltage   I(typ)   I(min)   I(max)
-3.3V     -369.7mA   -1.42A     -510.4mA
-2.3V     -236mA     -881.6mA   -321.3mA
-1.9V     -182.5mA   -666.4mA   -245.7mA
-1.5V     -129mA     -451.2mA   -170mA
-1V       -62.17mA   -182.2mA   -75.49mA
-700mV    -22.06mA   -20.78mA   -25.01mA
-500mV    -11.26mA   -9.48mA    -13.42mA
500mV     7.03mA     6.12mA     7.75mA
3.7V      10.38mA    10.63mA    10.23mA
4.1V      13.21mA    34.35mA    11.24mA
5.5V      235.4mA    117.4mA    33.34mA
6.6V      410mA      182.6mA    51.71mA
[Pullup]
| voltage   I(typ)   I(min)   I(max)
-3.3V     438.5mA    194.3mA    1.017A
-1.9V     201.5mA    95.59mA    436mA
-900mV    32.18mA    25.09mA    20.79mA
-800mV    15.25mA    18.04mA    17.87mA
400mV     -4.16mA    -3.77mA    -5.08mA
3.6V      -7.42mA    -9.71mA    -8.19mA
3.7V      -7.54mA    -16.29mA   -8.23mA
4V        -16.11mA   -174.4mA   -8.59mA
4.2V      -40.73mA   -279.8mA   -11.69mA
4.3V      -53.04mA   -332.6mA   -18.64mA
4.5V      -77.66mA   -438mA     -49.03mA
6.6V      -336.2mA   -1.545A    -368.1mA
[Ramp]
| variable   typ   min   max
dV/dt_r   0.22/0.98n   0.21/1.16n   0.24/0.93n
dV/dt_f   0.28/1.28n   0.26/1.43n   0.29/1.11n
R_load = 50.00
[Rising Waveform]
R_fixture = 50.00
V_fixture = 0.000
V_fixture_min = 0.000
V_fixture_max = 0.000
| time   V(typ)   V(min)   V(max)
0s        16.82nV    20.57nV    34.98nV
2ns       -2.07mV    -820uV     12.29mV
2.6ns     17.92mV    -1.99mV    100mV
3.2ns     97.57mV    14.67mV    270mV
3.6ns     180mV      49.02mV    360mV
4ns       280mV      100mV      390mV
4.4ns     340mV      190mV      400mV
5ns       350mV      290mV      400mV
5.6ns     360mV      330mV      400mV
10ns      360mV      340mV      400mV
[Rising Waveform]
R_fixture = 50.00
V_fixture = 3.30
V_fixture_min = 3.00
V_fixture_max = 3.60
| time   V(typ)   V(min)   V(max)
0s        2.83V      2.57V      3.11V
400ps     2.83V      2.57V      3.11V
600ps     2.83V      2.57V      3.14V
800ps     2.85V      2.56V      3.23V
1ns       2.93V      2.59V      3.3V
1.4ns     3.07V      2.69V      3.36V
2ns       3.14V      2.83V      3.51V
3ns       3.26V      2.92V      3.58V
5ns       3.29V      2.99V      3.59V
10ns      3.295V     3V         3.6V
[Falling Waveform]
R_fixture = 50.00
V_fixture = 3.30
V_fixture_min = 3.00
V_fixture_max = 3.60
| time   V(typ)   V(min)   V(max)
0s        3.295V     3V         3.6V
1.8ns     3.295V     3V         3.6V
2.2ns     3.295V     3V         3.57V
2.6ns     3.29V      3V         3.5V
3.4ns     3.19V      2.98V      3.28V
3.8ns     3.1V       2.94V      3.19V
4.6ns     2.91V      2.79V      3.12V
5.6ns     2.85V      2.62V      3.11V
6.2ns     2.84V      2.59V      3.11V
10ns      2.83V      2.57V      3.11V
[Falling Waveform]
R_fixture = 50.00
V_fixture = 0.000
V_fixture_min = 0.000
V_fixture_max = 0.000
| time   V(typ)   V(min)   V(max)
0s        360mV      350mV      400mV
800ps     350mV      340mV      380mV
1ns       340mV      340mV      300mV
1.4ns     260mV      320mV      180mV
1.8ns     160mV      250mV      89.34mV
2.2ns     85.81mV    170mV      47.63mV
2.6ns     49.47mV    98.86mV    24.35mV
3ns       26.87mV    54.59mV    13.17mV
4.2ns     8.58mV     14.99mV    5.32mV
10ns      1.55mV     1.89mV     1.29mV
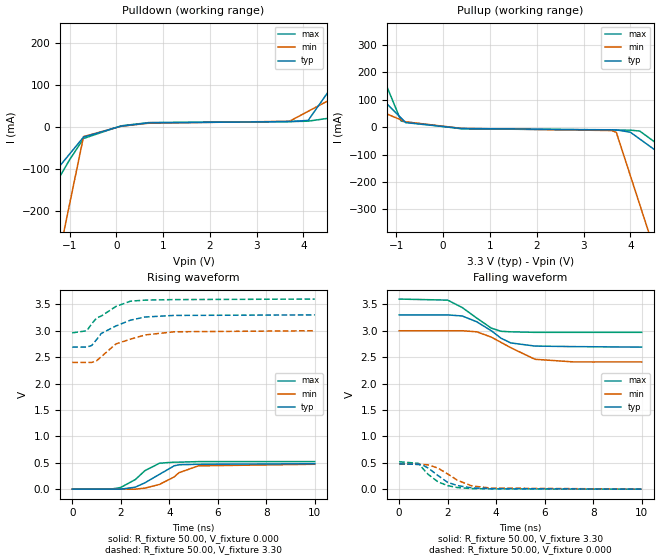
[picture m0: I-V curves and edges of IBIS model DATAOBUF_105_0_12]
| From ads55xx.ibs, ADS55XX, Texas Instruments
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|   Model DATAOBUF_105_0_12
[Model]   DATAOBUF_105_0_12
Model_type   Output
Polarity   Non-Inverting
Vmeas =   1.65V
C_comp   3.00pF   3.00pF   3.00pF
[Temperature Range]   50.00   0.10k   -20.00
[Voltage Range]   3.30V   3.00V   3.60V
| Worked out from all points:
|   slope of the pulldown table from 0 to 0.495 V, typ, clamps not added: 57.5 ohm
|   slope of the pullup table from 0 to 0.495 V, typ, clamps not added: 79.4 ohm
|   rising waveform, R_fixture 50.00, V_fixture 0.000: 20-80 % time 1.05ns typ, 1.15ns min, 914ps max; typ from 0 V to 0.48 V
|   rising waveform, R_fixture 50.00, V_fixture 3.30: 20-80 % time 1.29ns typ, 1.44ns min, 1.11ns max; typ from 2.69 V to 3.3 V
|   falling waveform, R_fixture 50.00, V_fixture 3.30: 20-80 % time 1.21ns typ, 1.42ns min, 1.13ns max; typ from 3.3 V to 2.69 V
|   falling waveform, R_fixture 50.00, V_fixture 0.000: 20-80 % time 941ps typ, 1.09ns min, 828ps max; typ from 0.48 V to 0.001 V
[Pulldown]
| voltage   I(typ)   I(min)   I(max)
-3.3V     -375.8mA   -1.426A    -518mA
-2.3V     -240.4mA   -886.2mA   -326.8mA
-1.9V     -186.2mA   -670.3mA   -250.3mA
-1.5V     -132.1mA   -454.3mA   -173.8mA
-1V       -64.35mA   -184.4mA   -78.21mA
-700mV    -23.73mA   -22.5mA    -27.07mA
100mV     2.4mA      2mA        3.08mA
700mV     10.18mA    9.4mA      10.94mA
3.7V      13.25mA    13.96mA    13.2mA
4.1V      16.09mA    37.72mA    14.24mA
5.5V      238.3mA    120.9mA    36.61mA
6.6V      412.8mA    186.2mA    55.2mA
[Pullup]
| voltage   I(typ)   I(min)   I(max)
-3.3V     442.7mA    198.5mA    1.022A
-3.1V     408.6mA    184.2mA    938.6mA
-1.9V     204mA      98.13mA    438.8mA
-900mV    33.51mA    26.43mA    22.27mA
-800mV    16.46mA    19.26mA    19.23mA
400mV     -4.99mA    -4.57mA    -6.13mA
3.6V      -9.86mA    -12.45mA   -10.65mA
3.7V      -9.98mA    -19.04mA   -10.7mA
4V        -18.57mA   -177.2mA   -11.08mA
4.2V      -43.21mA   -282.6mA   -14.19mA
4.5V      -80.17mA   -440.8mA   -51.54mA
6.6V      -338.9mA   -1.548A    -370.7mA
[Ramp]
| variable   typ   min   max
dV/dt_r   0.29/0.97n   0.28/1.14n   0.31/0.90n
dV/dt_f   0.36/1.27n   0.36/1.43n   0.38/1.13n
R_load = 50.00
[Rising Waveform]
R_fixture = 50.00
V_fixture = 0.000
V_fixture_min = 0.000
V_fixture_max = 0.000
| time   V(typ)   V(min)   V(max)
0s        15.68nV    19.03nV    32.22nV
1.6ns     -1.38mV    -1.66mV    -600uV
2ns       -1.93mV    -1.21mV    30.74mV
2.6ns     36.02mV    -1.44mV    180mV
3ns       120mV      18.22mV    350mV
3.6ns     280mV      88.58mV    490mV
4.2ns     440mV      230mV      510mV
4.4ns     460mV      310mV      510mV
5.2ns     470mV      440mV      520mV
10ns      480mV      470mV      520mV
[Rising Waveform]
R_fixture = 50.00
V_fixture = 3.30
V_fixture_min = 3.00
V_fixture_max = 3.60
| time   V(typ)   V(min)   V(max)
0s        2.69V      2.4V       2.96V
600ps     2.69V      2.4V       3V
800ps     2.72V      2.4V       3.13V
1ns       2.83V      2.43V      3.24V
1.2ns     2.95V      2.51V      3.28V
1.8ns     3.09V      2.75V      3.46V
2.4ns     3.2V       2.84V      3.56V
3ns       3.26V      2.92V      3.58V
4.2ns     3.29V      2.98V      3.59V
10ns      3.3V       3V         3.6V
[Falling Waveform]
R_fixture = 50.00
V_fixture = 3.30
V_fixture_min = 3.00
V_fixture_max = 3.60
| time   V(typ)   V(min)   V(max)
0s        3.3V       3V         3.6V
2ns       3.3V       3V         3.58V
2.6ns     3.28V      3V         3.44V
3.2ns     3.17V      2.98V      3.24V
3.8ns     3V         2.88V      3.05V
4.2ns     2.86V      2.78V      2.99V
4.6ns     2.77V      2.68V      2.98V
5.6ns     2.71V      2.46V      2.97V
7.2ns     2.7V       2.41V      2.97V
10ns      2.69V      2.41V      2.97V
[Falling Waveform]
R_fixture = 50.00
V_fixture = 0.000
V_fixture_min = 0.000
V_fixture_max = 0.000
| time   V(typ)   V(min)   V(max)
0s        480mV      480mV      520mV
800ps     470mV      470mV      490mV
1ns       450mV      470mV      380mV
1.2ns     400mV      460mV      280mV
1.6ns     260mV      400mV      140mV
2ns       130mV      290mV      68.39mV
2.4ns     69.91mV    170mV      31.66mV
3ns       25.28mV    62.08mV    11.99mV
3.8ns     11.3mV     21.83mV    6.45mV
10ns      1.44mV     1.76mV     1.22mV
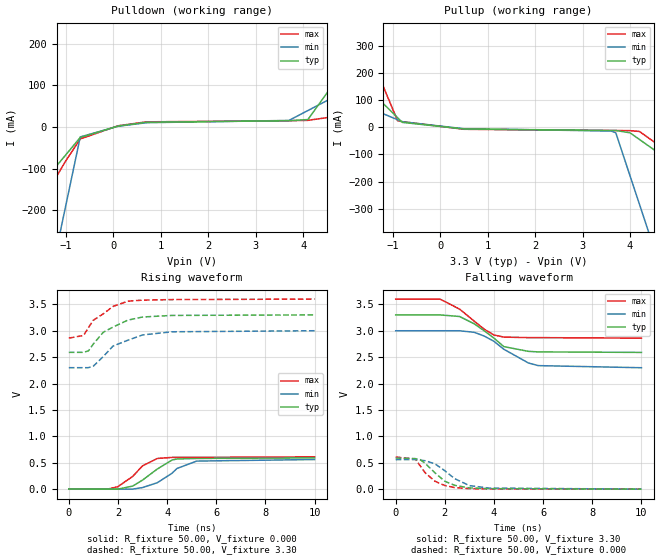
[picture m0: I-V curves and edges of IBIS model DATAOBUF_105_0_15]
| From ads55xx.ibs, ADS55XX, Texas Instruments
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|   Model DATAOBUF_105_0_15
[Model]   DATAOBUF_105_0_15
Model_type   Output
Polarity   Non-Inverting
Vmeas =   1.65V
C_comp   3.00pF   3.00pF   3.00pF
[Temperature Range]   50.00   0.10k   -20.00
[Voltage Range]   3.30V   3.00V   3.60V
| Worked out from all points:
|   slope of the pulldown table from 0 to 0.495 V, typ, clamps not added: 51.1 ohm
|   slope of the pullup table from 0 to 0.495 V, typ, clamps not added: 70 ohm
|   rising waveform, R_fixture 50.00, V_fixture 0.000: 20-80 % time 1.02ns typ, 1.13ns min, 877ps max; typ from 0 V to 0.59 V
|   rising waveform, R_fixture 50.00, V_fixture 3.30: 20-80 % time 1.22ns typ, 1.36ns min, 1.04ns max; typ from 2.59 V to 3.3 V
|   falling waveform, R_fixture 50.00, V_fixture 3.30: 20-80 % time 1.25ns typ, 1.44ns min, 1.21ns max; typ from 3.3 V to 2.59 V
|   falling waveform, R_fixture 50.00, V_fixture 0.000: 20-80 % time 904ps typ, 1.04ns min, 782ps max; typ from 0.59 V to 0.001 V
[Pulldown]
| voltage   I(typ)   I(min)   I(max)
-3.3V     -380mA     -1.43A     -523.7mA
-2.3V     -243.4mA   -888.8mA   -330.8mA
-1.9V     -188.8mA   -672.5mA   -253.6mA
-1.5V     -134.1mA   -456.1mA   -176.5mA
-1V       -65.84mA   -185.7mA   -80.01mA
-700mV    -24.86mA   -23.5mA    -28.37mA
100mV     2.63mA     2.19mA     3.36mA
700mV     11.68mA    10.66mA    12.76mA
3.7V      15.39mA    16.14mA    15.28mA
4.1V      18.25mA    39.86mA    16.34mA
5.5V      240.4mA    122.9mA    38.9mA
6.6V      415mA      188.1mA    57.66mA
[Pullup]
| voltage   I(typ)   I(min)   I(max)
-3.3V     446.2mA    201.2mA    1.025A
-3.1V     411.9mA    186.7mA    941.3mA
-1.9V     206.1mA    99.7mA     440.5mA
-900mV    34.59mA    27.2mA     23.22mA
-800mV    17.44mA    19.95mA    20.09mA
500mV     -6.79mA    -6.05mA    -7.9mA
3.6V      -12.17mA   -14.25mA   -12.45mA
3.7V      -12.3mA    -20.84mA   -12.5mA
4V        -20.9mA    -179mA     -12.89mA
4.2V      -45.54mA   -284.4mA   -16mA
4.5V      -82.5mA    -442.6mA   -53.37mA
6.6V      -341.2mA   -1.55A     -372.7mA
[Ramp]
| variable   typ   min   max
dV/dt_r   0.35/0.97n   0.34/1.13n   0.37/0.89n
dV/dt_f   0.43/1.28n   0.42/1.44n   0.44/1.17n
R_load = 50.00
[Rising Waveform]
R_fixture = 50.00
V_fixture = 0.000
V_fixture_min = 0.000
V_fixture_max = 0.000
| time   V(typ)   V(min)   V(max)
0s        15.04nV    18.28nV    30.77nV
1.6ns     -1.67mV    -1.88mV    810uV
2ns       -1.24mV    -1.45mV    46.18mV
2.6ns     56.65mV    -470uV     240mV
3ns       170mV      28.32mV    440mV
3.6ns     380mV      120mV      580mV
4.2ns     550mV      300mV      600mV
4.4ns     570mV      390mV      600mV
5.2ns     580mV      530mV      600mV
10ns      590mV      560mV      610mV
[Rising Waveform]
R_fixture = 50.00
V_fixture = 3.30
V_fixture_min = 3.00
V_fixture_max = 3.60
| time   V(typ)   V(min)   V(max)
0s        2.59V      2.3V       2.86V
600ps     2.59V      2.3V       2.91V
800ps     2.62V      2.3V       3.06V
1ns       2.75V      2.33V      3.2V
1.4ns     2.97V      2.51V      3.32V
1.8ns     3.07V      2.71V      3.46V
2.4ns     3.2V       2.82V      3.56V
3ns       3.26V      2.92V      3.58V
4.2ns     3.29V      2.98V      3.59V
10ns      3.3V       3V         3.6V
[Falling Waveform]
R_fixture = 50.00
V_fixture = 3.30
V_fixture_min = 3.00
V_fixture_max = 3.60
| time   V(typ)   V(min)   V(max)
0s        3.3V       3V         3.6V
1.8ns     3.3V       3V         3.6V
2.6ns     3.27V      3V         3.41V
3.2ns     3.13V      2.97V      3.18V
3.6ns     3V         2.9V       3.03V
4ns       2.86V      2.8V       2.92V
4.4ns     2.7V       2.65V      2.88V
5.4ns     2.61V      2.39V      2.87V
5.8ns     2.6V       2.34V      2.87V
10ns      2.59V      2.3V       2.86V
[Falling Waveform]
R_fixture = 50.00
V_fixture = 0.000
V_fixture_min = 0.000
V_fixture_max = 0.000
| time   V(typ)   V(min)   V(max)
0s        590mV      560mV      610mV
800ps     580mV      560mV      570mV
1ns       560mV      550mV      440mV
1.2ns     490mV      540mV      310mV
1.6ns     310mV      480mV      150mV
2ns       150mV      350mV      70.03mV
2.4ns     74.1mV     200mV      30.68mV
3ns       24.54mV    68.34mV    11.73mV
3.8ns     10.96mV    21.83mV    6.31mV
10ns      1.38mV     1.7mV      1.18mV
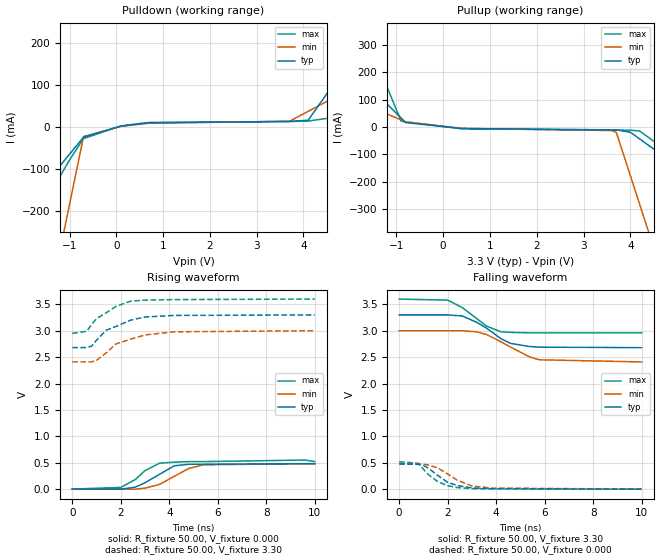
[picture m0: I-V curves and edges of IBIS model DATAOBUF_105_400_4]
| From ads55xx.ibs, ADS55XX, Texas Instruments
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|   Model DATAOBUF_105_400_4
[Model]   DATAOBUF_105_400_4
Model_type   Output
Polarity   Non-Inverting
Vmeas =   1.65V
C_comp   3.00pF   3.00pF   3.00pF
[Temperature Range]   50.00   0.10k   -20.00
[Voltage Range]   3.30V   3.00V   3.60V
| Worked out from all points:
|   slope of the pulldown table from 0 to 0.495 V, typ, clamps not added: 56.5 ohm
|   slope of the pullup table from 0 to 0.495 V, typ, clamps not added: 79.3 ohm
|   rising waveform, R_fixture 50.00, V_fixture 0.000: 20-80 % time 1.05ns typ, 1.14ns min, 915ps max; typ from 0 V to 0.48 V
|   rising waveform, R_fixture 50.00, V_fixture 3.30: 20-80 % time 1.27ns typ, 1.43ns min, 1.1ns max; typ from 2.68 V to 3.3 V
|   falling waveform, R_fixture 50.00, V_fixture 3.30: 20-80 % time 1.23ns typ, 1.45ns min, 1.11ns max; typ from 3.3 V to 2.68 V
|   falling waveform, R_fixture 50.00, V_fixture 0.000: 20-80 % time 942ps typ, 1.09ns min, 828ps max; typ from 0.48 V to 0.001 V
[Pulldown]
| voltage   I(typ)   I(min)   I(max)
-3.3V     -376.5mA   -1.426A    -518.6mA
-2.3V     -240.9mA   -886.2mA   -327.2mA
-1.9V     -186.6mA   -670.2mA   -250.7mA
-1.5V     -132.4mA   -454.3mA   -174.1mA
-1V       -64.57mA   -184.4mA   -78.43mA
-700mV    -23.89mA   -22.48mA   -27.23mA
100mV     2.44mA     2mA        3.12mA
700mV     10.4mA     9.37mA     11.16mA
3.7V      13.55mA    13.92mA    13.45mA
4.1V      16.4mA     37.64mA    14.49mA
5.5V      238.6mA    120.7mA    36.92mA
6.6V      413.1mA    185.9mA    55.56mA
[Pullup]
| voltage   I(typ)   I(min)   I(max)
-3.3V     442.7mA    198.5mA    1.022A
-3.1V     408.6mA    184.2mA    938.4mA
-1.9V     204mA      98.14mA    438.7mA
-900mV    33.52mA    26.44mA    22.28mA
-800mV    16.47mA    19.27mA    19.23mA
400mV     -5mA       -4.58mA    -6.14mA
3.6V      -9.88mA    -12.48mA   -10.66mA
3.7V      -10mA      -19.06mA   -10.71mA
4V        -18.59mA   -177.2mA   -11.09mA
4.2V      -43.21mA   -282.7mA   -14.2mA
4.5V      -80.14mA   -440.9mA   -51.55mA
6.6V      -338.7mA   -1.548A    -370.8mA
[Ramp]
| variable   typ   min   max
dV/dt_r   0.29/0.98n   0.29/1.14n   0.31/0.89n
dV/dt_f   0.37/1.28n   0.35/1.44n   0.39/1.13n
R_load = 50.00
[Rising Waveform]
R_fixture = 50.00
V_fixture = 0.000
V_fixture_min = 0.000
V_fixture_max = 0.000
| time   V(typ)   V(min)   V(max)
0s        15.57nV    19.05nV    32.02nV
2ns       -1.94mV    -1.2mV     30.79mV
2.6ns     35.95mV    -1.42mV    180mV
3ns       120mV      18.34mV    350mV
3.6ns     280mV      89.05mV    490mV
4.2ns     440mV      240mV      510mV
4.8ns     470mV      390mV      520mV
5.4ns     470mV      460mV      520mV
9.6ns     480mV      480mV      550mV
10ns      480mV      480mV      520mV
[Rising Waveform]
R_fixture = 50.00
V_fixture = 3.30
V_fixture_min = 3.00
V_fixture_max = 3.60
| time   V(typ)   V(min)   V(max)
0s        2.68V      2.41V      2.95V
600ps     2.68V      2.41V      2.99V
800ps     2.71V      2.41V      3.12V
1ns       2.82V      2.44V      3.23V
1.4ns     3.01V      2.58V      3.34V
1.8ns     3.08V      2.75V      3.46V
2.4ns     3.2V       2.84V      3.56V
3ns       3.26V      2.92V      3.58V
4.2ns     3.29V      2.98V      3.59V
10ns      3.3V       3V         3.6V
[Falling Waveform]
R_fixture = 50.00
V_fixture = 3.30
V_fixture_min = 3.00
V_fixture_max = 3.60
| time   V(typ)   V(min)   V(max)
0s        3.3V       3V         3.6V
2ns       3.3V       3V         3.58V
2.6ns     3.28V      3V         3.44V
3.2ns     3.16V      2.98V      3.23V
3.6ns     3.05V      2.93V      3.09V
4.2ns     2.85V      2.79V      2.98V
4.6ns     2.76V      2.69V      2.97V
5.4ns     2.7V       2.5V       2.96V
5.8ns     2.69V      2.45V      2.96V
10ns      2.68V      2.41V      2.96V
[Falling Waveform]
R_fixture = 50.00
V_fixture = 0.000
V_fixture_min = 0.000
V_fixture_max = 0.000
| time   V(typ)   V(min)   V(max)
0s        480mV      480mV      520mV
800ps     470mV      480mV      490mV
1ns       450mV      470mV      380mV
1.2ns     400mV      460mV      280mV
1.6ns     260mV      400mV      140mV
2ns       130mV      290mV      68.18mV
2.4ns     69.84mV    170mV      31.37mV
3ns       25.04mV    62.41mV    12mV
3.8ns     11.21mV    22.04mV    6.43mV
10ns      1.43mV     1.76mV     1.21mV
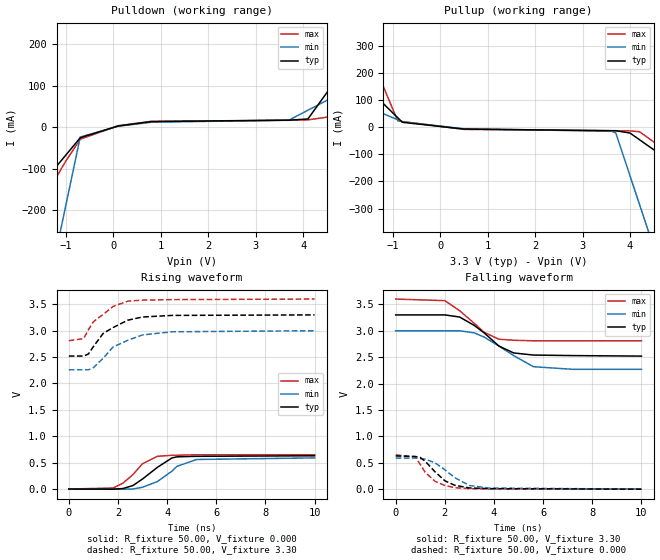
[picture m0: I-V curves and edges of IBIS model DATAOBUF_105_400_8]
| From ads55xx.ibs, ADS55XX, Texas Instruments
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|   Model DATAOBUF_105_400_8
[Model]   DATAOBUF_105_400_8
Model_type   Output
Polarity   Non-Inverting
Vmeas =   1.65V
C_comp   3.00pF   3.00pF   3.00pF
[Temperature Range]   50.00   0.10k   -20.00
[Voltage Range]   3.30V   3.00V   3.60V
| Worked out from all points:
|   slope of the pulldown table from 0 to 0.495 V, typ, clamps not added: 47.9 ohm
|   slope of the pullup table from 0 to 0.495 V, typ, clamps not added: 67.3 ohm
|   rising waveform, R_fixture 50.00, V_fixture 0.000: 20-80 % time 1.03ns typ, 1.1ns min, 876ps max; typ from 0 V to 0.63 V
|   rising waveform, R_fixture 50.00, V_fixture 3.30: 20-80 % time 1.17ns typ, 1.35ns min, 1ns max; typ from 2.52 V to 3.3 V
|   falling waveform, R_fixture 50.00, V_fixture 3.30: 20-80 % time 1.27ns typ, 1.45ns min, 1.16ns max; typ from 3.3 V to 2.52 V
|   falling waveform, R_fixture 50.00, V_fixture 0.000: 20-80 % time 875ps typ, 1.04ns min, 748ps max; typ from 0.63 V to 0.001 V
[Pulldown]
| voltage   I(typ)   I(min)   I(max)
-3.3V     -382.5mA   -1.431A    -526.7mA
-2.3V     -245.2mA   -889.7mA   -332.9mA
-1.9V     -190.3mA   -673.3mA   -255.4mA
-1.5V     -135.4mA   -456.8mA   -177.9mA
-1V       -66.73mA   -186.2mA   -80.98mA
-700mV    -25.54mA   -23.81mA   -29.08mA
100mV     2.76mA     2.25mA     3.51mA
800mV     13.34mA    11.88mA    14.16mA
3.7V      16.78mA    16.88mA    16.49mA
4.1V      19.64mA    40.64mA    17.55mA
5.5V      241.8mA    123.8mA    40.18mA
6.6V      416.4mA    189.1mA    58.99mA
[Pullup]
| voltage   I(typ)   I(min)   I(max)
-3.3V     447.5mA    201.9mA    1.026A
-3.1V     413.1mA    187.4mA    942.4mA
-1.9V     206.9mA    100.1mA    441.3mA
-900mV    34.96mA    27.42mA    23.67mA
-800mV    17.77mA    20.15mA    20.51mA
500mV     -7.08mA    -6.21mA    -8.3mA
3.6V      -13.04mA   -14.82mA   -13.36mA
3.7V      -13.17mA   -21.41mA   -13.41mA
4V        -21.78mA   -179.6mA   -13.81mA
4.2V      -46.42mA   -285.1mA   -16.93mA
4.5V      -83.38mA   -443.3mA   -54.3mA
6.6V      -342.1mA   -1.551A    -373.6mA
[Ramp]
| variable   typ   min   max
dV/dt_r   0.38/0.97n   0.35/1.11n   0.39/0.88n
dV/dt_f   0.47/1.29n   0.44/1.44n   0.48/1.18n
R_load = 50.00
[Rising Waveform]
R_fixture = 50.00
V_fixture = 0.000
V_fixture_min = 0.000
V_fixture_max = 0.000
| time   V(typ)   V(min)   V(max)
0s        14.66nV    18.06nV    30.06nV
1.8ns     -2.63mV    -1.46mV    19.2mV
2.2ns     8.78mV     -2.47mV    110mV
2.6ns     64.72mV    190uV      270mV
3ns       190mV      33.78mV    480mV
3.6ns     410mV      140mV      620mV
4.2ns     590mV      340mV      640mV
4.4ns     610mV      430mV      640mV
5.2ns     620mV      560mV      650mV
10ns      630mV      590mV      650mV
[Rising Waveform]
R_fixture = 50.00
V_fixture = 3.30
V_fixture_min = 3.00
V_fixture_max = 3.60
| time   V(typ)   V(min)   V(max)
0s        2.52V      2.26V      2.81V
600ps     2.52V      2.26V      2.85V
800ps     2.56V      2.26V      3.02V
1ns       2.7V       2.3V       3.17V
1.4ns     2.95V      2.48V      3.31V
1.8ns     3.06V      2.69V      3.46V
2.4ns     3.2V       2.82V      3.56V
3ns       3.26V      2.92V      3.58V
4.2ns     3.29V      2.98V      3.59V
10ns      3.3V       3V         3.6V
[Falling Waveform]
R_fixture = 50.00
V_fixture = 3.30
V_fixture_min = 3.00
V_fixture_max = 3.60
| time   V(typ)   V(min)   V(max)
0s        3.3V       3V         3.6V
2ns       3.3V       3V         3.57V
2.6ns     3.26V      3V         3.38V
3.2ns     3.1V       2.96V      3.14V
3.6ns     2.96V      2.88V      2.97V
4.2ns     2.71V      2.71V      2.84V
4.8ns     2.58V      2.53V      2.82V
5.6ns     2.54V      2.32V      2.81V
7.2ns     2.53V      2.27V      2.81V
10ns      2.52V      2.27V      2.81V
[Falling Waveform]
R_fixture = 50.00
V_fixture = 0.000
V_fixture_min = 0.000
V_fixture_max = 0.000
| time   V(typ)   V(min)   V(max)
0s        630mV      590mV      650mV
800ps     620mV      590mV      610mV
1ns       600mV      580mV      470mV
1.2ns     530mV      570mV      320mV
1.6ns     330mV      500mV      150mV
2ns       160mV      370mV      70.38mV
2.4ns     75.27mV    220mV      29.65mV
3ns       23.86mV    70.64mV    11.42mV
3.8ns     10.71mV    22.01mV    6.17mV
10ns      1.34mV     1.68mV     1.15mV
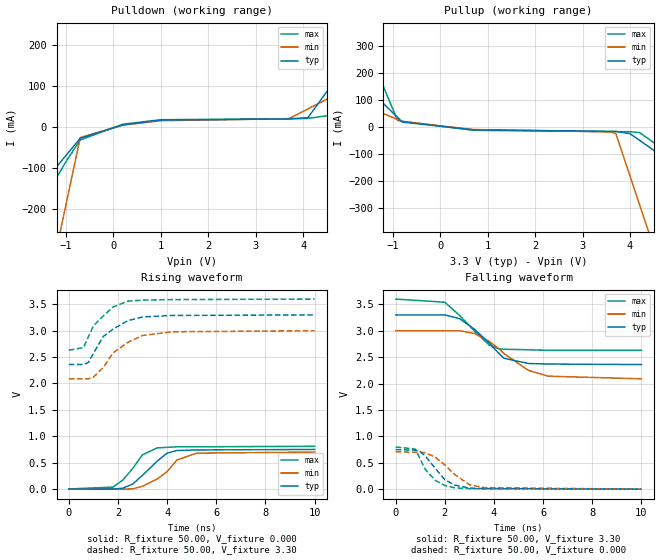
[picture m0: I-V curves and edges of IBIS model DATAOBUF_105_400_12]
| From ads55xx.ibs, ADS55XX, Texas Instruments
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|   Model DATAOBUF_105_400_12
[Model]   DATAOBUF_105_400_12
Model_type   Output
Polarity   Non-Inverting
Vmeas =   1.65V
C_comp   3.00pF   3.00pF   3.00pF
[Temperature Range]   50.00   0.10k   -20.00
[Voltage Range]   3.30V   3.00V   3.60V
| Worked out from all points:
|   slope of the pulldown table from 0 to 0.495 V, typ, clamps not added: 42 ohm
|   slope of the pullup table from 0 to 0.495 V, typ, clamps not added: 60.9 ohm
|   rising waveform, R_fixture 50.00, V_fixture 0.000: 20-80 % time 1.03ns typ, 1.01ns min, 817ps max; typ from 0 V to 0.75 V
|   rising waveform, R_fixture 50.00, V_fixture 3.30: 20-80 % time 1.07ns typ, 1.25ns min, 937ps max; typ from 2.36 V to 3.3 V
|   falling waveform, R_fixture 50.00, V_fixture 3.30: 20-80 % time 1.31ns typ, 1.6ns min, 1.21ns max; typ from 3.3 V to 2.36 V
|   falling waveform, R_fixture 50.00, V_fixture 0.000: 20-80 % time 837ps typ, 1.04ns min, 704ps max; typ from 0.75 V to 0.001 V
[Pulldown]
| voltage   I(typ)   I(min)   I(max)
-3.3V     -388.2mA   -1.437A    -535.2mA
-2.3V     -249.3mA   -893.7mA   -338.9mA
-1.9V     -193.7mA   -676.6mA   -260.4mA
-1.5V     -138.2mA   -459.5mA   -181.8mA
-1V       -68.73mA   -188.1mA   -83.69mA
-700mV    -27.06mA   -25.26mA   -31.07mA
200mV     5.73mA     4.78mA     7.2mA
1V        17.06mA    15.68mA    18.05mA
3.7V      20.14mA    20.55mA    20.17mA
4.1V      23.01mA    44.31mA    21.25mA
5.5V      245.2mA    127.5mA    44.01mA
6.6V      419.8mA    192.8mA    62.93mA
[Pullup]
| voltage   I(typ)   I(min)   I(max)
-3.3V     450.7mA    205mA      1.03A
-3.1V     416.1mA    190.3mA    946.7mA
-1.9V     208.8mA    102mA      444mA
-900mV    35.96mA    28.36mA    25.13mA
-800mV    18.68mA    21mA       21.84mA
700mV     -10.14mA   -9.02mA    -11.84mA
3.6V      -15.59mA   -17.42mA   -16.62mA
3.7V      -15.73mA   -24.02mA   -16.68mA
4V        -24.36mA   -182.2mA   -17.09mA
4.2V      -49.02mA   -287.7mA   -20.23mA
4.5V      -86.01mA   -445.9mA   -57.61mA
6.6V      -344.9mA   -1.553A    -377mA
[Ramp]
| variable   typ   min   max
dV/dt_r   0.45/0.96n   0.42/1.10n   0.48/0.87n
dV/dt_f   0.56/1.31n   0.54/1.61n   0.58/1.20n
R_load = 50.00
[Rising Waveform]
R_fixture = 50.00
V_fixture = 0.000
V_fixture_min = 0.000
V_fixture_max = 0.000
| time   V(typ)   V(min)   V(max)
0s        13.94nV    17.11nV    28.33nV
1.8ns     -2.83mV    -1.82mV    37mV
2.2ns     16.46mV    -2.94mV    170mV
2.6ns     93.8mV     2.79mV     390mV
3ns       260mV      51.42mV    650mV
3.6ns     530mV      190mV      780mV
4ns       680mV      330mV      790mV
4.4ns     730mV      550mV      800mV
5.2ns     740mV      680mV      800mV
10ns      750mV      700mV      810mV
[Rising Waveform]
R_fixture = 50.00
V_fixture = 3.30
V_fixture_min = 3.00
V_fixture_max = 3.60
| time   V(typ)   V(min)   V(max)
0s        2.36V      2.09V      2.63V
600ps     2.36V      2.09V      2.68V
800ps     2.4V       2.09V      2.89V
1ns       2.57V      2.12V      3.09V
1.4ns     2.89V      2.3V       3.28V
1.8ns     3.03V      2.58V      3.45V
2.4ns     3.19V      2.78V      3.56V
3ns       3.26V      2.91V      3.58V
4.2ns     3.29V      2.98V      3.59V
10ns      3.3V       3V         3.6V
[Falling Waveform]
R_fixture = 50.00
V_fixture = 3.30
V_fixture_min = 3.00
V_fixture_max = 3.60
| time   V(typ)   V(min)   V(max)
0s        3.3V       3V         3.6V
2ns       3.3V       3V         3.54V
2.6ns     3.23V      3V         3.29V
3.2ns     3.03V      2.95V      3V
3.8ns     2.77V      2.8V       2.73V
4.2ns     2.57V      2.66V      2.66V
4.4ns     2.48V      2.57V      2.65V
5.4ns     2.38V      2.25V      2.64V
6.2ns     2.37V      2.14V      2.63V
10ns      2.36V      2.09V      2.63V
[Falling Waveform]
R_fixture = 50.00
V_fixture = 0.000
V_fixture_min = 0.000
V_fixture_max = 0.000
| time   V(typ)   V(min)   V(max)
0s        750mV      710mV      800mV
800ps     740mV      700mV      760mV
1ns       710mV      700mV      570mV
1.2ns     630mV      690mV      380mV
1.6ns     400mV      610mV      170mV
2ns       180mV      460mV      70.89mV
2.4ns     78.71mV    280mV      26.87mV
3ns       22.73mV    84.66mV    10.59mV
3.6ns     12.23mV    29.92mV    6.75mV
10ns      1.28mV     1.61mV     1.1mV
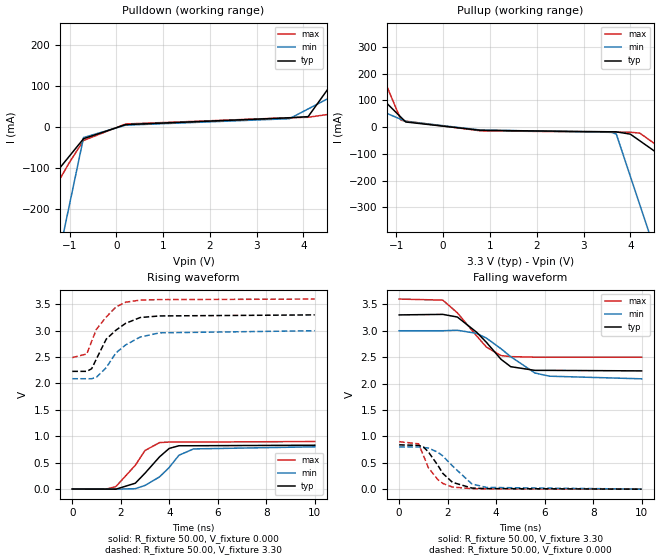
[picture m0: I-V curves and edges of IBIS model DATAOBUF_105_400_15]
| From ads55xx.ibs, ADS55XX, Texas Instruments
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|   Model DATAOBUF_105_400_15
[Model]   DATAOBUF_105_400_15
Model_type   Output
Polarity   Non-Inverting
Vmeas =   1.65V
C_comp   3.00pF   3.00pF   3.00pF
[Temperature Range]   50.00   0.10k   -20.00
[Voltage Range]   3.30V   3.00V   3.60V
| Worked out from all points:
|   slope of the pulldown table from 0 to 0.495 V, typ, clamps not added: 38.8 ohm
|   slope of the pullup table from 0 to 0.495 V, typ, clamps not added: 57.2 ohm
|   rising waveform, R_fixture 50.00, V_fixture 0.000: 20-80 % time 996ps typ, 1ns min, 843ps max; typ from 0 V to 0.83 V
|   rising waveform, R_fixture 50.00, V_fixture 3.30: 20-80 % time 1.05ns typ, 1.25ns min, 893ps max; typ from 2.23 V to 3.3 V
|   falling waveform, R_fixture 50.00, V_fixture 3.30: 20-80 % time 1.34ns typ, 1.57ns min, 1.22ns max; typ from 3.3 V to 2.24 V
|   falling waveform, R_fixture 50.00, V_fixture 0.000: 20-80 % time 820ps typ, 1.03ns min, 671ps max; typ from 0.84 V to 0.001 V
[Pulldown]
| voltage   I(typ)   I(min)   I(max)
-3.3V     -392.4mA   -1.437A    -540.4mA
-2.3V     -252.3mA   -893.7mA   -342.6mA
-1.9V     -196.2mA   -676.6mA   -263.5mA
-1.7V     -168.2mA   -568.1mA   -223.9mA
-1.5V     -140.2mA   -459.5mA   -184.4mA
-1V       -70.15mA   -188.1mA   -85.48mA
-700mV    -28.12mA   -25.26mA   -32.41mA
200mV     6.13mA     4.78mA     7.73mA
3.7V      22.72mA    20.55mA    22.93mA
4.1V      25.59mA    44.31mA    24.01mA
5.5V      247.8mA    127.5mA    46.83mA
6.6V      422.3mA    192.8mA    65.8mA
[Pullup]
| voltage   I(typ)   I(min)   I(max)
-3.3V     452.8mA    207.4mA    1.033A
-3.1V     418.1mA    192.5mA    949.1mA
-1.9V     210mA      103.3mA    445.5mA
-900mV    36.63mA    29.05mA    25.94mA
-800mV    19.29mA    21.62mA    22.58mA
800mV     -11.94mA   -10.76mA   -13.85mA
3.6V      -17.48mA   -19.53mA   -18.63mA
3.7V      -17.62mA   -26.14mA   -18.7mA
4V        -26.27mA   -184.4mA   -19.12mA
4.2V      -50.93mA   -289.8mA   -22.26mA
4.5V      -87.92mA   -448.1mA   -59.66mA
6.6V      -346.9mA   -1.556A    -379.1mA
[Ramp]
| variable   typ   min   max
dV/dt_r   0.50/0.96n   0.48/1.09n   0.54/0.88n
dV/dt_f   0.64/1.32n   0.54/1.60n   0.66/1.22n
R_load = 50.00
[Rising Waveform]
R_fixture = 50.00
V_fixture = 0.000
V_fixture_min = 0.000
V_fixture_max = 0.000
| time   V(typ)   V(min)   V(max)
0s        13.49nV    17.17nV    27.31nV
1.4ns     -1.72mV    -2.3mV     -1.95mV
1.8ns     -2.9mV     -1.82mV    47.09mV
2.6ns     110mV      5.86mV     450mV
3ns       300mV      68.15mV    730mV
3.6ns     610mV      230mV      880mV
4ns       770mV      410mV      890mV
4.4ns     820mV      640mV      890mV
5ns       820mV      760mV      890mV
10ns      830mV      800mV      900mV
[Rising Waveform]
R_fixture = 50.00
V_fixture = 3.30
V_fixture_min = 3.00
V_fixture_max = 3.60
| time   V(typ)   V(min)   V(max)
0s        2.23V      2.09V      2.49V
600ps     2.23V      2.09V      2.56V
800ps     2.28V      2.09V      2.8V
1ns       2.47V      2.12V      3.03V
1.4ns     2.84V      2.3V       3.26V
1.8ns     3.01V      2.58V      3.45V
2.2ns     3.14V      2.73V      3.54V
2.8ns     3.25V      2.88V      3.58V
3.6ns     3.28V      2.96V      3.59V
10ns      3.3V       3V         3.6V
[Falling Waveform]
R_fixture = 50.00
V_fixture = 3.30
V_fixture_min = 3.00
V_fixture_max = 3.60
| time   V(typ)   V(min)   V(max)
0s        3.3V       3V         3.6V
1.8ns     3.31V      3V         3.58V
2.4ns     3.26V      3.01V      3.34V
3.2ns     2.97V      2.95V      2.9V
3.6ns     2.78V      2.86V      2.69V
4.2ns     2.46V      2.66V      2.53V
4.6ns     2.32V      2.51V      2.51V
5.6ns     2.25V      2.2V       2.5V
6.2ns     2.25V      2.14V      2.5V
10ns      2.24V      2.09V      2.5V
[Falling Waveform]
R_fixture = 50.00
V_fixture = 0.000
V_fixture_min = 0.000
V_fixture_max = 0.000
| time   V(typ)   V(min)   V(max)
0s        840mV      800mV      900mV
800ps     830mV      800mV      860mV
1ns       800mV      790mV      640mV
1.2ns     710mV      780mV      410mV
1.6ns     450mV      700mV      180mV
1.8ns     300mV      630mV      110mV
2.2ns     130mV      440mV      41.26mV
3ns       21.77mV    100mV      10.34mV
3.6ns     11.88mV    33.56mV    6.61mV
10ns      1.23mV     1.63mV     1.07mV
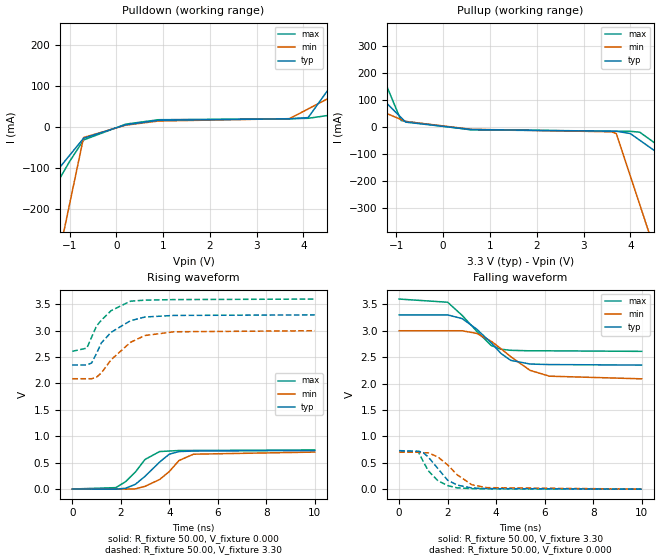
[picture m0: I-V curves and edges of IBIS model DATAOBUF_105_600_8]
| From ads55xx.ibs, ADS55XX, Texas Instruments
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|   Model DATAOBUF_105_600_8
[Model]   DATAOBUF_105_600_8
Model_type   Output
Polarity   Non-Inverting
Vmeas =   1.65V
C_comp   3.00pF   3.00pF   3.00pF
[Temperature Range]   50.00   0.10k   -20.00
[Voltage Range]   3.30V   3.00V   3.60V
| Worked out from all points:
|   slope of the pulldown table from 0 to 0.495 V, typ, clamps not added: 41.7 ohm
|   slope of the pullup table from 0 to 0.495 V, typ, clamps not added: 61.8 ohm
|   rising waveform, R_fixture 50.00, V_fixture 0.000: 20-80 % time 1.02ns typ, 1.04ns min, 887ps max; typ from 0 V to 0.73 V
|   rising waveform, R_fixture 50.00, V_fixture 3.30: 20-80 % time 1.07ns typ, 1.25ns min, 931ps max; typ from 2.35 V to 3.3 V
|   falling waveform, R_fixture 50.00, V_fixture 3.30: 20-80 % time 1.32ns typ, 1.6ns min, 1.21ns max; typ from 3.3 V to 2.35 V
|   falling waveform, R_fixture 50.00, V_fixture 0.000: 20-80 % time 835ps typ, 1.03ns min, 724ps max; typ from 0.73 V to 0.001 V
[Pulldown]
| voltage   I(typ)   I(min)   I(max)
-3.3V     -388.6mA   -1.437A    -535.8mA
-2.3V     -249.6mA   -893.7mA   -339.3mA
-1.9V     -193.9mA   -676.6mA   -260.7mA
-1.5V     -138.4mA   -459.5mA   -182.1mA
-1V       -68.85mA   -188.1mA   -83.89mA
-700mV    -27.15mA   -25.26mA   -31.21mA
200mV     5.76mA     4.78mA     7.26mA
900mV     16.61mA    14.91mA    18.05mA
3.7V      20.35mA    20.55mA    20.46mA
4.1V      23.21mA    44.31mA    21.54mA
5.5V      245.4mA    127.5mA    44.3mA
6.6V      420mA      192.8mA    63.22mA
[Pullup]
| voltage   I(typ)   I(min)   I(max)
-3.3V     450.3mA    205mA      1.028A
-3.1V     415.7mA    190.3mA    944.7mA
-1.9V     208.5mA    101.9mA    442.8mA
-900mV    35.79mA    28.34mA    24.49mA
-800mV    18.52mA    20.98mA    21.25mA
600mV     -8.91mA    -8mA       -10.13mA
3.6V      -15.13mA   -17.35mA   -15.12mA
3.7V      -15.27mA   -23.95mA   -15.18mA
4V        -23.9mA    -182.1mA   -15.59mA
4.2V      -48.54mA   -287.6mA   -18.71mA
4.5V      -85.5mA    -445.8mA   -56.1mA
6.6V      -344.2mA   -1.553A    -375.5mA
[Ramp]
| variable   typ   min   max
dV/dt_r   0.44/0.96n   0.42/1.10n   0.44/0.89n
dV/dt_f   0.57/1.33n   0.54/1.61n   0.59/1.20n
R_load = 50.00
[Rising Waveform]
R_fixture = 50.00
V_fixture = 0.000
V_fixture_min = 0.000
V_fixture_max = 0.000
| time   V(typ)   V(min)   V(max)
0s        13.88nV    17.1nV     28.13nV
1.8ns     -2.84mV    -1.82mV    26.26mV
2.2ns     15.04mV    -2.93mV    140mV
2.6ns     88.74mV    2.7mV      320mV
3ns       240mV      50.85mV    560mV
3.6ns     510mV      180mV      710mV
4ns       660mV      330mV      720mV
4.4ns     710mV      540mV      730mV
5ns       720mV      660mV      730mV
10ns      730mV      700mV      740mV
[Rising Waveform]
R_fixture = 50.00
V_fixture = 3.30
V_fixture_min = 3.00
V_fixture_max = 3.60
| time   V(typ)   V(min)   V(max)
0s        2.35V      2.09V      2.61V
600ps     2.35V      2.09V      2.67V
800ps     2.39V      2.09V      2.88V
1ns       2.57V      2.12V      3.09V
1.2ns     2.77V      2.2V       3.2V
1.6ns     2.97V      2.45V      3.38V
2.4ns     3.19V      2.78V      3.56V
3ns       3.26V      2.91V      3.58V
4.2ns     3.29V      2.98V      3.59V
10ns      3.3V       3V         3.6V
[Falling Waveform]
R_fixture = 50.00
V_fixture = 3.30
V_fixture_min = 3.00
V_fixture_max = 3.60
| time   V(typ)   V(min)   V(max)
0s        3.3V       3V         3.6V
2ns       3.3V       3V         3.54V
2.6ns     3.23V      3V         3.29V
3.2ns     3.03V      2.95V      2.99V
3.8ns     2.77V      2.8V       2.72V
4.2ns     2.57V      2.66V      2.65V
4.6ns     2.44V      2.51V      2.63V
5.4ns     2.37V      2.25V      2.62V
6.2ns     2.36V      2.14V      2.62V
10ns      2.35V      2.09V      2.61V
[Falling Waveform]
R_fixture = 50.00
V_fixture = 0.000
V_fixture_min = 0.000
V_fixture_max = 0.000
| time   V(typ)   V(min)   V(max)
0s        730mV      700mV      730mV
800ps     720mV      700mV      700mV
1ns       690mV      690mV      520mV
1.2ns     610mV      690mV      350mV
1.6ns     390mV      610mV      160mV
2ns       170mV      460mV      68.01mV
2.4ns     77.72mV    270mV      25.75mV
3ns       22.65mV    84.12mV    10.36mV
3.6ns     12.2mV     29.81mV    6.64mV
10ns      1.27mV     1.61mV     1.09mV
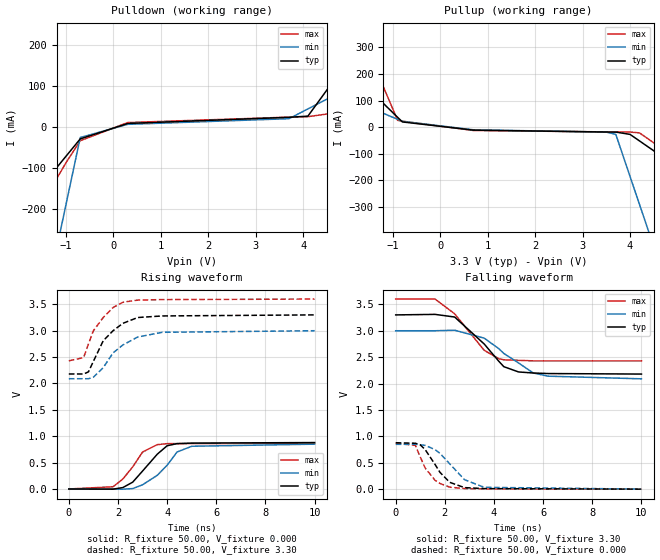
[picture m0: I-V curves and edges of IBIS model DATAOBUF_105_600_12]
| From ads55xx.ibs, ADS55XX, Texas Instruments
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|   Model DATAOBUF_105_600_12
[Model]   DATAOBUF_105_600_12
Model_type   Output
Polarity   Non-Inverting
Vmeas =   1.65V
C_comp   3.00pF   3.00pF   3.00pF
[Temperature Range]   50.00   0.10k   -20.00
[Voltage Range]   3.30V   3.00V   3.60V
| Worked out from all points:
|   slope of the pulldown table from 0 to 0.495 V, typ, clamps not added: 37.5 ohm
|   slope of the pullup table from 0 to 0.495 V, typ, clamps not added: 55.6 ohm
|   rising waveform, R_fixture 50.00, V_fixture 0.000: 20-80 % time 1ns typ, 1ns min, 829ps max; typ from 0 V to 0.88 V
|   rising waveform, R_fixture 50.00, V_fixture 3.30: 20-80 % time 1.01ns typ, 1.21ns min, 881ps max; typ from 2.18 V to 3.3 V
|   falling waveform, R_fixture 50.00, V_fixture 3.30: 20-80 % time 1.35ns typ, 1.57ns min, 1.23ns max; typ from 3.3 V to 2.18 V
|   falling waveform, R_fixture 50.00, V_fixture 0.000: 20-80 % time 799ps typ, 1.03ns min, 670ps max; typ from 0.88 V to 0.001 V
[Pulldown]
| voltage   I(typ)   I(min)   I(max)
-3.3V     -394.1mA   -1.437A    -543.1mA
-2.3V     -253.5mA   -893.7mA   -344.5mA
-1.9V     -197.3mA   -676.6mA   -265.1mA
-1.7V     -169.2mA   -568.1mA   -225.4mA
-1.5V     -141.1mA   -459.5mA   -185.7mA
-1V       -70.76mA   -188.1mA   -86.35mA
-700mV    -28.58mA   -25.26mA   -33.04mA
300mV     8.93mA     6.82mA     11.14mA
3.7V      23.91mA    20.55mA    24.33mA
4.1V      26.78mA    44.31mA    25.41mA
5.5V      249mA      127.5mA    48.23mA
6.6V      423.5mA    192.8mA    67.21mA
[Pullup]
| voltage   I(typ)   I(min)   I(max)
-3.3V     453.8mA    208.4mA    1.032A
-3.1V     419.1mA    193.5mA    948.4mA
-1.9V     210.7mA    104mA      445.1mA
-900mV    36.95mA    29.39mA    25.68mA
-800mV    19.58mA    21.93mA    22.34mA
700mV     -11.26mA   -10.12mA   -12.55mA
3.5V      -18.38mA   -18.62mA   -17.91mA
3.7V      -18.6mA    -27.29mA   -18.03mA
4V        -27.25mA   -185.5mA   -18.46mA
4.2V      -51.93mA   -291mA     -21.59mA
4.5V      -88.95mA   -449.3mA   -58.99mA
6.6V      -348.1mA   -1.557A    -378.5mA
[Ramp]
| variable   typ   min   max
dV/dt_r   0.53/0.95n   0.51/1.08n   0.52/0.88n
dV/dt_f   0.67/1.34n   0.54/1.60n   0.70/1.23n
R_load = 50.00
[Rising Waveform]
R_fixture = 50.00
V_fixture = 0.000
V_fixture_min = 0.000
V_fixture_max = 0.000
| time   V(typ)   V(min)   V(max)
0s        13.32nV    17.21nV    26.81nV
1.8ns     -2.86mV    -1.83mV    42.75mV
2.2ns     27.25mV    -3.2mV     190mV
2.6ns     130mV      8.11mV     420mV
3ns       340mV      79.29mV    700mV
3.6ns     660mV      260mV      840mV
4ns       820mV      450mV      860mV
4.4ns     860mV      700mV      860mV
5ns       870mV      810mV      860mV
10ns      880mV      850mV      870mV
[Rising Waveform]
R_fixture = 50.00
V_fixture = 3.30
V_fixture_min = 3.00
V_fixture_max = 3.60
| time   V(typ)   V(min)   V(max)
0s        2.18V      2.09V      2.43V
600ps     2.18V      2.09V      2.49V
800ps     2.22V      2.09V      2.75V
1ns       2.42V      2.12V      3V
1.4ns     2.81V      2.3V       3.25V
1.8ns     3V         2.58V      3.44V
2.2ns     3.14V      2.73V      3.54V
2.8ns     3.25V      2.88V      3.58V
3.8ns     3.28V      2.97V      3.59V
10ns      3.3V       3V         3.6V
[Falling Waveform]
R_fixture = 50.00
V_fixture = 3.30
V_fixture_min = 3.00
V_fixture_max = 3.60
| time   V(typ)   V(min)   V(max)
0s        3.3V       3V         3.6V
1.6ns     3.31V      3V         3.6V
2.4ns     3.26V      3.01V      3.32V
3.6ns     2.75V      2.86V      2.63V
4.2ns     2.42V      2.66V      2.47V
4.4ns     2.32V      2.57V      2.45V
5ns       2.22V      2.39V      2.44V
5.6ns     2.2V       2.2V       2.43V
6.2ns     2.19V      2.14V      2.43V
10ns      2.18V      2.09V      2.43V
[Falling Waveform]
R_fixture = 50.00
V_fixture = 0.000
V_fixture_min = 0.000
V_fixture_max = 0.000
| time   V(typ)   V(min)   V(max)
0s        880mV      850mV      870mV
800ps     870mV      850mV      830mV
1ns       840mV      840mV      610mV
1.2ns     750mV      830mV      400mV
1.6ns     470mV      750mV      170mV
1.8ns     320mV      680mV      110mV
2.2ns     130mV      480mV      38.58mV
2.8ns     30.6mV     180mV      12.4mV
3.6ns     11.83mV    36.13mV    6.46mV
10ns      1.22mV     1.65mV     1.05mV
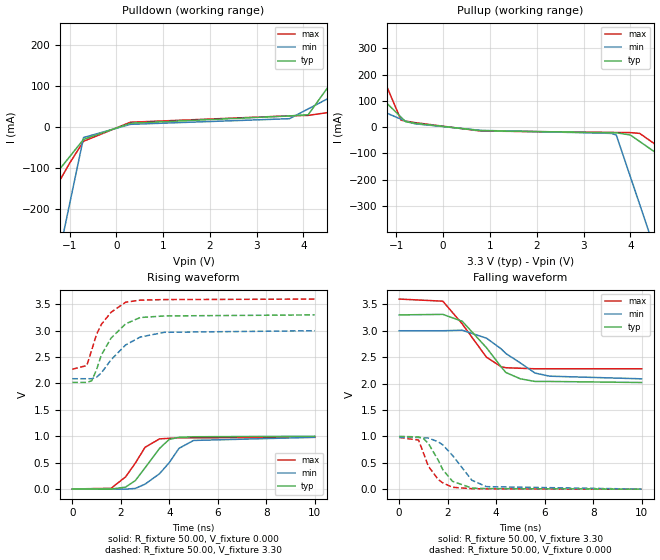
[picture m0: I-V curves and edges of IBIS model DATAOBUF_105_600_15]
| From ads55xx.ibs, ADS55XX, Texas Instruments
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|   Model DATAOBUF_105_600_15
[Model]   DATAOBUF_105_600_15
Model_type   Output
Polarity   Non-Inverting
Vmeas =   1.65V
C_comp   3.00pF   3.00pF   3.00pF
[Temperature Range]   50.00   0.10k   -20.00
[Voltage Range]   3.30V   3.00V   3.60V
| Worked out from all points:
|   slope of the pulldown table from 0 to 0.495 V, typ, clamps not added: 34.6 ohm
|   slope of the pullup table from 0 to 0.495 V, typ, clamps not added: 51.9 ohm
|   rising waveform, R_fixture 50.00, V_fixture 0.000: 20-80 % time 988ps typ, 1.08ns min, 858ps max; typ from 0 V to 1 V
|   rising waveform, R_fixture 50.00, V_fixture 3.30: 20-80 % time 975ps typ, 1.21ns min, 838ps max; typ from 2.02 V to 3.3 V
|   falling waveform, R_fixture 50.00, V_fixture 3.30: 20-80 % time 1.41ns typ, 1.57ns min, 1.25ns max; typ from 3.3 V to 2.02 V
|   falling waveform, R_fixture 50.00, V_fixture 0.000: 20-80 % time 779ps typ, 1.02ns min, 666ps max; typ from 1 V to 0.001 V
[Pulldown]
| voltage   I(typ)   I(min)   I(max)
-3.3V     -399mA     -1.437A    -548.6mA
-2.3V     -257mA     -893.7mA   -348.4mA
-1.9V     -200.2mA   -676.6mA   -268.3mA
-1.7V     -171.8mA   -568.1mA   -228.3mA
-1.5V     -143.4mA   -459.5mA   -188.3mA
-1V       -72.37mA   -188.1mA   -88.16mA
-700mV    -29.77mA   -25.26mA   -34.39mA
300mV     9.6mA      6.82mA     11.91mA
3.7V      27.24mA    20.55mA    27.49mA
4.1V      30.1mA     44.31mA    28.56mA
5.5V      252.3mA    127.5mA    51.39mA
6.6V      426.8mA    192.8mA    70.36mA
[Pullup]
| voltage   I(typ)   I(min)   I(max)
-3.3V     456.6mA    211.2mA    1.035A
-1.9V     212.3mA    105.6mA    446.6mA
-900mV    37.8mA     30.24mA    26.55mA
-800mV    20.35mA    22.7mA     23.13mA
-600mV    14.83mA    12.72mA    17.15mA
800mV     -13.47mA   -12.25mA   -14.75mA
3.6V      -21.17mA   -23.75mA   -20.24mA
3.7V      -21.32mA   -30.37mA   -20.31mA
4V        -29.99mA   -188.6mA   -20.75mA
4.2V      -54.69mA   -294.1mA   -23.9mA
4.5V      -91.74mA   -452.4mA   -61.3mA
6.6V      -351.1mA   -1.56A     -380.8mA
[Ramp]
| variable   typ   min   max
dV/dt_r   0.60/0.96n   0.59/1.15n   0.59/0.89n
dV/dt_f   0.77/1.42n   0.54/1.59n   0.79/1.25n
R_load = 50.00
[Rising Waveform]
R_fixture = 50.00
V_fixture = 0.000
V_fixture_min = 0.000
V_fixture_max = 0.000
| time   V(typ)   V(min)   V(max)
0s        12.89nV    17.25nV    25.97nV
1.6ns     -2.93mV    -2.34mV    13.24mV
2.2ns     36.23mV    -3.29mV    230mV
2.6ns     160mV      10.66mV    490mV
3ns       400mV      91.18mV    790mV
3.6ns     770mV      290mV      950mV
4ns       940mV      500mV      960mV
4.4ns     980mV      770mV      970mV
5ns       990mV      920mV      970mV
10ns      1V         980mV      980mV
[Rising Waveform]
R_fixture = 50.00
V_fixture = 3.30
V_fixture_min = 3.00
V_fixture_max = 3.60
| time   V(typ)   V(min)   V(max)
0s        2.02V      2.09V      2.27V
600ps     2.02V      2.09V      2.34V
800ps     2.05V      2.09V      2.63V
1ns       2.26V      2.12V      2.93V
1.2ns     2.54V      2.2V       3.12V
1.6ns     2.86V      2.45V      3.35V
2.2ns     3.13V      2.73V      3.54V
2.8ns     3.25V      2.88V      3.58V
3.8ns     3.28V      2.97V      3.59V
10ns      3.3V       3V         3.6V
[Falling Waveform]
R_fixture = 50.00
V_fixture = 3.30
V_fixture_min = 3.00
V_fixture_max = 3.60
| time   V(typ)   V(min)   V(max)
0s        3.3V       3V         3.6V
1.8ns     3.31V      3V         3.56V
2.6ns     3.18V      3.01V      3.13V
3.6ns     2.68V      2.86V      2.5V
4.2ns     2.32V      2.66V      2.32V
4.4ns     2.21V      2.57V      2.3V
5ns       2.09V      2.39V      2.29V
5.6ns     2.04V      2.2V       2.28V
6.2ns     2.04V      2.14V      2.28V
10ns      2.02V      2.09V      2.28V
[Falling Waveform]
R_fixture = 50.00
V_fixture = 0.000
V_fixture_min = 0.000
V_fixture_max = 0.000
| time   V(typ)   V(min)   V(max)
0s        1V         980mV      980mV
800ps     990mV      980mV      930mV
1ns       960mV      970mV      690mV
1.2ns     870mV      970mV      440mV
1.6ns     560mV      900mV      190mV
1.8ns     370mV      840mV      120mV
2.2ns     150mV      640mV      36.56mV
3ns       21.44mV    170mV      9.78mV
3.6ns     11.77mV    48.73mV    6.34mV
10ns      1.18mV     1.71mV     1.02mV
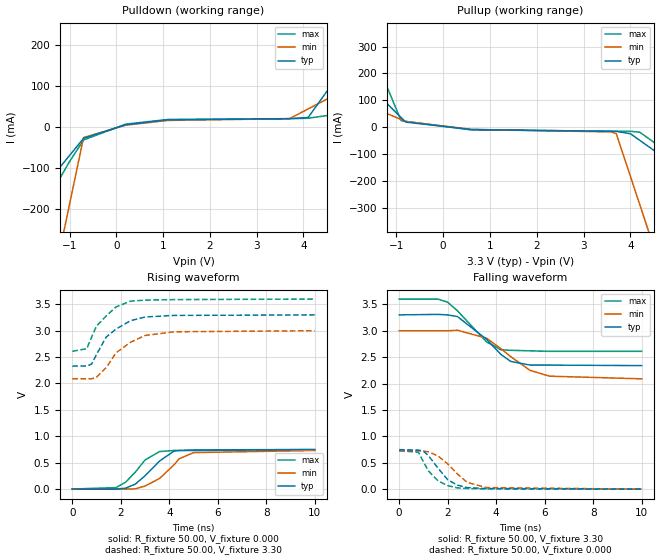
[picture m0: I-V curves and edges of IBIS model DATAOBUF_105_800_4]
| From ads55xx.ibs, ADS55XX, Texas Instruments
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|   Model DATAOBUF_105_800_4
[Model]   DATAOBUF_105_800_4
Model_type   Output
Polarity   Non-Inverting
Vmeas =   1.65V
C_comp   3.00pF   3.00pF   3.00pF
[Temperature Range]   50.00   0.10k   -20.00
[Voltage Range]   3.30V   3.00V   3.60V
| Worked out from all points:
|   slope of the pulldown table from 0 to 0.495 V, typ, clamps not added: 41.3 ohm
|   slope of the pullup table from 0 to 0.495 V, typ, clamps not added: 60.7 ohm
|   rising waveform, R_fixture 50.00, V_fixture 0.000: 20-80 % time 1.01ns typ, 1.04ns min, 880ps max; typ from 0 V to 0.75 V
|   rising waveform, R_fixture 50.00, V_fixture 3.30: 20-80 % time 1.08ns typ, 1.25ns min, 928ps max; typ from 2.33 V to 3.3 V
|   falling waveform, R_fixture 50.00, V_fixture 3.30: 20-80 % time 1.32ns typ, 1.6ns min, 1.21ns max; typ from 3.3 V to 2.34 V
|   falling waveform, R_fixture 50.00, V_fixture 0.000: 20-80 % time 817ps typ, 1.03ns min, 724ps max; typ from 0.75 V to 0.001 V
[Pulldown]
| voltage   I(typ)   I(min)   I(max)
-3.3V     -388.9mA   -1.437A    -536.2mA
-2.3V     -249.8mA   -893.7mA   -339.6mA
-1.9V     -194.2mA   -676.6mA   -260.9mA
-1.5V     -138.6mA   -459.5mA   -182.3mA
-1V       -69.01mA   -188.1mA   -83.97mA
-700mV    -27.28mA   -25.26mA   -31.27mA
200mV     5.81mA     4.78mA     7.28mA
1.1V      17.9mA     16.31mA    18.61mA
3.7V      20.66mA    20.55mA    20.57mA
4.1V      23.52mA    44.31mA    21.64mA
5.5V      245.7mA    127.5mA    44.41mA
6.6V      420.3mA    192.8mA    63.33mA
[Pullup]
| voltage   I(typ)   I(min)   I(max)
-3.3V     450.7mA    205.4mA    1.028A
-3.1V     416.1mA    190.7mA    944.7mA
-1.9V     208.8mA    102.2mA    442.8mA
-900mV    35.99mA    28.53mA    24.49mA
-800mV    18.71mA    21.16mA    21.25mA
600mV     -9.1mA     -8.18mA    -10.14mA
3.6V      -15.67mA   -17.96mA   -15.13mA
3.7V      -15.81mA   -24.56mA   -15.19mA
4V        -24.44mA   -182.8mA   -15.59mA
4.2V      -49.1mA    -288.3mA   -18.72mA
4.5V      -86.09mA   -446.5mA   -56.1mA
6.6V      -345mA     -1.554A    -375.4mA
[Ramp]
| variable   typ   min   max
dV/dt_r   0.45/0.96n   0.44/1.09n   0.44/0.89n
dV/dt_f   0.58/1.31n   0.54/1.61n   0.59/1.20n
R_load = 50.00
[Rising Waveform]
R_fixture = 50.00
V_fixture = 0.000
V_fixture_min = 0.000
V_fixture_max = 0.000
| time   V(typ)   V(min)   V(max)
0s        13.83nV    17.12nV    28.08nV
1.8ns     -2.85mV    -1.82mV    25.8mV
2.2ns     16.13mV    -2.98mV    130mV
2.6ns     92.69mV    3.52mV     320mV
3ns       250mV      55.59mV    550mV
3.6ns     530mV      200mV      710mV
4.2ns     720mV      460mV      730mV
4.4ns     730mV      570mV      730mV
5ns       740mV      690mV      730mV
10ns      750mV      730mV      740mV
[Rising Waveform]
R_fixture = 50.00
V_fixture = 3.30
V_fixture_min = 3.00
V_fixture_max = 3.60
| time   V(typ)   V(min)   V(max)
0s        2.33V      2.09V      2.61V
600ps     2.33V      2.09V      2.66V
800ps     2.37V      2.09V      2.88V
1ns       2.55V      2.12V      3.09V
1.4ns     2.88V      2.3V       3.28V
1.8ns     3.03V      2.58V      3.45V
2.4ns     3.19V      2.78V      3.56V
3ns       3.26V      2.91V      3.58V
4.2ns     3.29V      2.98V      3.59V
10ns      3.3V       3V         3.6V
[Falling Waveform]
R_fixture = 50.00
V_fixture = 3.30
V_fixture_min = 3.00
V_fixture_max = 3.60
| time   V(typ)   V(min)   V(max)
0s        3.3V       3V         3.6V
1.6ns     3.31V      3V         3.6V
2ns       3.3V       3V         3.54V
2.4ns     3.27V      3.01V      3.38V
3.6ns     2.84V      2.86V      2.79V
4.2ns     2.55V      2.66V      2.64V
4.6ns     2.42V      2.51V      2.63V
5.4ns     2.35V      2.25V      2.62V
6.2ns     2.35V      2.14V      2.61V
10ns      2.34V      2.09V      2.61V
[Falling Waveform]
R_fixture = 50.00
V_fixture = 0.000
V_fixture_min = 0.000
V_fixture_max = 0.000
| time   V(typ)   V(min)   V(max)
0s        750mV      730mV      730mV
800ps     740mV      730mV      700mV
1ns       720mV      720mV      520mV
1.2ns     640mV      710mV      350mV
1.6ns     400mV      630mV      160mV
2ns       180mV      480mV      67.94mV
2.4ns     78.37mV    290mV      25.77mV
2.8ns     31.34mV    130mV      12.97mV
3.6ns     12.1mV     30.74mV    6.66mV
10ns      1.27mV     1.61mV     1.09mV
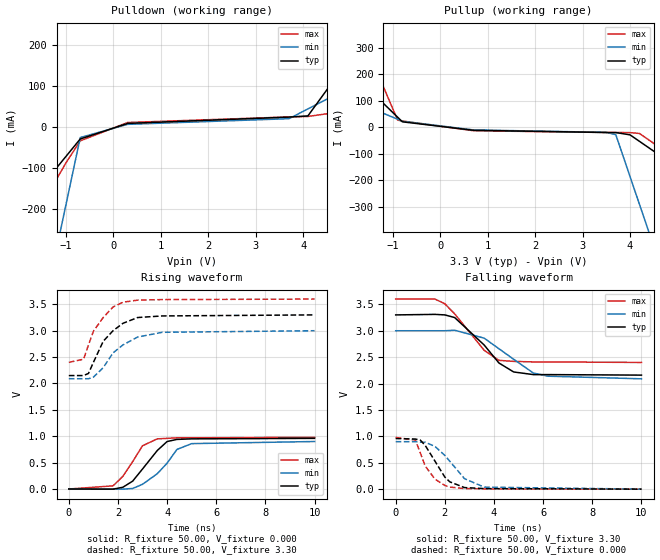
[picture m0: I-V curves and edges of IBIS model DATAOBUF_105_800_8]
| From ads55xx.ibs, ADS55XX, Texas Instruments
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|   Model DATAOBUF_105_800_8
[Model]   DATAOBUF_105_800_8
Model_type   Output
Polarity   Non-Inverting
Vmeas =   1.65V
C_comp   3.00pF   3.00pF   3.00pF
[Temperature Range]   50.00   0.10k   -20.00
[Voltage Range]   3.30V   3.00V   3.60V
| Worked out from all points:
|   slope of the pulldown table from 0 to 0.495 V, typ, clamps not added: 37 ohm
|   slope of the pullup table from 0 to 0.495 V, typ, clamps not added: 52.9 ohm
|   rising waveform, R_fixture 50.00, V_fixture 0.000: 20-80 % time 999ps typ, 1.01ns min, 833ps max; typ from 0 V to 0.96 V
|   rising waveform, R_fixture 50.00, V_fixture 3.30: 20-80 % time 1.02ns typ, 1.21ns min, 867ps max; typ from 2.15 V to 3.3 V
|   falling waveform, R_fixture 50.00, V_fixture 3.30: 20-80 % time 1.34ns typ, 1.57ns min, 1.26ns max; typ from 3.3 V to 2.16 V
|   falling waveform, R_fixture 50.00, V_fixture 0.000: 20-80 % time 779ps typ, 1.01ns min, 666ps max; typ from 0.96 V to 0.001 V
[Pulldown]
| voltage   I(typ)   I(min)   I(max)
-3.3V     -395.1mA   -1.437A    -544.1mA
-2.3V     -254.2mA   -893.7mA   -345.2mA
-1.9V     -197.8mA   -676.6mA   -265.7mA
-1.7V     -169.7mA   -568.1mA   -225.9mA
-1.5V     -141.5mA   -459.5mA   -186.1mA
-1V       -71.04mA   -188.1mA   -86.67mA
-700mV    -28.77mA   -25.26mA   -33.28mA
300mV     9.04mA     6.82mA     11.28mA
3.7V      24.44mA    20.55mA    24.87mA
4.1V      27.3mA     44.31mA    25.95mA
5.5V      249.6mA    127.5mA    48.78mA
6.6V      424.3mA    192.8mA    67.75mA
[Pullup]
| voltage   I(typ)   I(min)   I(max)
-3.3V     455.6mA    209.5mA    1.035A
-3.1V     420.8mA    194.5mA    950.8mA
-1.9V     211.7mA    104.6mA    446.6mA
-900mV    37.54mA    29.72mA    26.55mA
-800mV    20.12mA    22.23mA    23.13mA
700mV     -11.93mA   -10.48mA   -13.65mA
3.5V      -20.24mA   -19.76mA   -20.18mA
3.7V      -20.47mA   -28.44mA   -20.31mA
4V        -29.14mA   -186.7mA   -20.75mA
4.2V      -53.82mA   -292.2mA   -23.9mA
4.5V      -90.84mA   -450.4mA   -61.3mA
6.6V      -350mA     -1.558A    -380.8mA
[Ramp]
| variable   typ   min   max
dV/dt_r   0.58/0.96n   0.54/1.08n   0.59/0.87n
dV/dt_f   0.69/1.34n   0.54/1.60n   0.72/1.25n
R_load = 50.00
[Rising Waveform]
R_fixture = 50.00
V_fixture = 0.000
V_fixture_min = 0.000
V_fixture_max = 0.000
| time   V(typ)   V(min)   V(max)
0s        13.28nV    17.24nV    26.74nV
1.8ns     -2.76mV    -1.83mV    59.88mV
2.2ns     33.06mV    -3.27mV    240mV
2.6ns     150mV      10.21mV    520mV
3ns       380mV      89.12mV    820mV
3.6ns     730mV      290mV      950mV
4ns       900mV      490mV      960mV
4.4ns     940mV      750mV      970mV
5ns       950mV      860mV      970mV
10ns      960mV      900mV      980mV
[Rising Waveform]
R_fixture = 50.00
V_fixture = 3.30
V_fixture_min = 3.00
V_fixture_max = 3.60
| time   V(typ)   V(min)   V(max)
0s        2.15V      2.09V      2.4V
600ps     2.15V      2.09V      2.46V
800ps     2.19V      2.09V      2.73V
1ns       2.4V       2.12V      2.99V
1.4ns     2.8V       2.3V       3.25V
1.8ns     3V         2.58V      3.45V
2.2ns     3.14V      2.73V      3.54V
2.8ns     3.25V      2.88V      3.58V
3.8ns     3.28V      2.97V      3.59V
10ns      3.3V       3V         3.6V
[Falling Waveform]
R_fixture = 50.00
V_fixture = 3.30
V_fixture_min = 3.00
V_fixture_max = 3.60
| time   V(typ)   V(min)   V(max)
0s        3.3V       3V         3.6V
1.6ns     3.31V      3V         3.6V
2ns       3.3V       3V         3.51V
2.4ns     3.25V      3.01V      3.32V
3.6ns     2.73V      2.86V      2.63V
4.2ns     2.39V      2.66V      2.44V
4.8ns     2.22V      2.46V      2.42V
5.6ns     2.17V      2.2V       2.41V
6.2ns     2.17V      2.14V      2.41V
10ns      2.16V      2.09V      2.4V
[Falling Waveform]
R_fixture = 50.00
V_fixture = 0.000
V_fixture_min = 0.000
V_fixture_max = 0.000
| time   V(typ)   V(min)   V(max)
0s        960mV      900mV      980mV
800ps     950mV      900mV      930mV
1ns       930mV      890mV      690mV
1.2ns     830mV      890mV      440mV
1.6ns     530mV      810mV      190mV
2ns       230mV      640mV      71.03mV
2.2ns     140mV      530mV      40.7mV
2.8ns     31.19mV    200mV      12.68mV
3.6ns     11.94mV    39.63mV    6.56mV
10ns      1.21mV     1.67mV     1.05mV
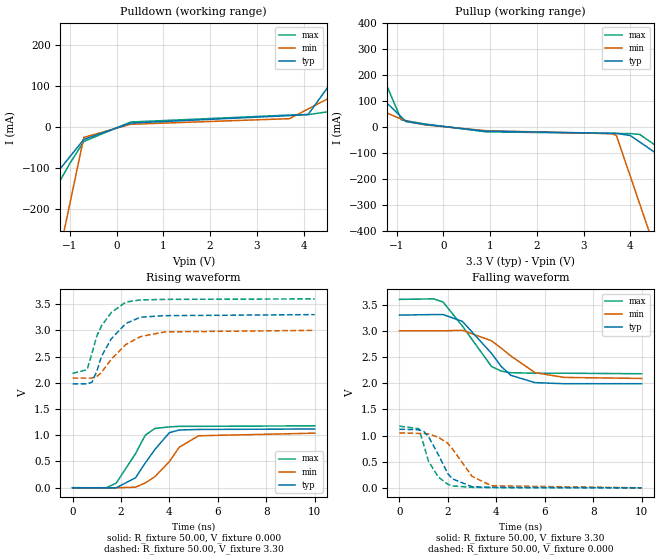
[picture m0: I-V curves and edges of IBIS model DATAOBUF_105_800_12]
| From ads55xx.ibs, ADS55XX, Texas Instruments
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|   Model DATAOBUF_105_800_12
[Model]   DATAOBUF_105_800_12
Model_type   Output
Polarity   Non-Inverting
Vmeas =   1.65V
C_comp   3.00pF   3.00pF   3.00pF
[Temperature Range]   50.00   0.10k   -20.00
[Voltage Range]   3.30V   3.00V   3.60V
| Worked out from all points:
|   slope of the pulldown table from 0 to 0.495 V, typ, clamps not added: 34 ohm
|   slope of the pullup table from 0 to 0.495 V, typ, clamps not added: 48.9 ohm
|   rising waveform, R_fixture 50.00, V_fixture 0.000: 20-80 % time 984ps typ, 1.18ns min, 849ps max; typ from 0 V to 1.12 V
|   rising waveform, R_fixture 50.00, V_fixture 3.30: 20-80 % time 955ps typ, 1.21ns min, 825ps max; typ from 1.98 V to 3.3 V
|   falling waveform, R_fixture 50.00, V_fixture 3.30: 20-80 % time 1.44ns typ, 1.59ns min, 1.29ns max; typ from 3.3 V to 1.99 V
|   falling waveform, R_fixture 50.00, V_fixture 0.000: 20-80 % time 761ps typ, 1.01ns min, 638ps max; typ from 1.12 V to 0.001 V
[Pulldown]
| voltage   I(typ)   I(min)   I(max)
-3.3V     -400mA     -1.437A    -551.5mA
-2.3V     -257.7mA   -893.7mA   -350.5mA
-1.9V     -200.8mA   -676.6mA   -270.1mA
-1.7V     -172.4mA   -568.1mA   -229.9mA
-1.5V     -143.9mA   -459.5mA   -189.7mA
-1V       -72.74mA   -188.1mA   -89.17mA
-700mV    -30.05mA   -25.26mA   -35.15mA
300mV     9.75mA     6.82mA     12.34mA
3.7V      28.05mA    20.55mA    29.42mA
4.1V      30.91mA    44.31mA    30.49mA
5.5V      253.1mA    127.5mA    53.31mA
6.6V      427.7mA    192.8mA    72.29mA
[Pullup]
| voltage   I(typ)   I(min)   I(max)
-3.3V     459.1mA    212.6mA    1.039A
-1.9V     213.8mA    106.5mA    449.4mA
-900mV    38.57mA    30.66mA    28.04mA
-800mV    21.05mA    23.08mA    24.48mA
-400mV    10.22mA    8.6mA      12.02mA
900mV     -15.74mA   -13.98mA   -18.15mA
3.6V      -23.9mA    -25.43mA   -24.63mA
3.7V      -24.06mA   -32.05mA   -24.7mA
4V        -32.76mA   -190.3mA   -25.17mA
4.2V      -57.44mA   -295.9mA   -28.33mA
4.5V      -94.46mA   -454.1mA   -65.76mA
6.6V      -353.6mA   -1.562A    -385.5mA
[Ramp]
| variable   typ   min   max
dV/dt_r   0.67/0.97n   0.63/1.23n   0.71/0.89n
dV/dt_f   0.79/1.46n   0.54/1.59n   0.85/1.27n
R_load = 50.00
[Rising Waveform]
R_fixture = 50.00
V_fixture = 0.000
V_fixture_min = 0.000
V_fixture_max = 0.000
| time   V(typ)   V(min)   V(max)
0s        12.84nV    17.25nV    25.64nV
1.4ns     -2.23mV    -2.3mV     -73.26uV
1.8ns     -2.4mV     -1.83mV    86.65mV
2.6ns     190mV      10.68mV    650mV
3ns       470mV      91.24mV    1V
3.4ns     730mV      210mV      1.13V
4ns       1.05V      500mV      1.16V
4.4ns     1.1V       770mV      1.17V
5.2ns     1.11V      990mV      1.17V
10ns      1.12V      1.04V      1.18V
[Rising Waveform]
R_fixture = 50.00
V_fixture = 3.30
V_fixture_min = 3.00
V_fixture_max = 3.60
| time   V(typ)   V(min)   V(max)
0s        1.98V      2.09V      2.18V
600ps     1.98V      2.09V      2.25V
800ps     2.01V      2.09V      2.56V
1ns       2.22V      2.12V      2.89V
1.2ns     2.51V      2.2V       3.09V
1.6ns     2.84V      2.45V      3.34V
2.2ns     3.13V      2.73V      3.54V
2.8ns     3.25V      2.88V      3.58V
3.8ns     3.28V      2.97V      3.59V
10ns      3.3V       3V         3.6V
[Falling Waveform]
R_fixture = 50.00
V_fixture = 3.30
V_fixture_min = 3.00
V_fixture_max = 3.60
| time   V(typ)   V(min)   V(max)
0s        3.3V       3V         3.6V
1.4ns     3.31V      3V         3.61V
1.8ns     3.31V      3V         3.55V
2.6ns     3.18V      3.01V      3.09V
3.8ns     2.57V      2.81V      2.32V
4.2ns     2.32V      2.67V      2.23V
4.6ns     2.15V      2.52V      2.2V
5.6ns     2.01V      2.2V       2.19V
6.8ns     1.99V      2.11V      2.19V
10ns      1.99V      2.09V      2.18V
[Falling Waveform]
R_fixture = 50.00
V_fixture = 0.000
V_fixture_min = 0.000
V_fixture_max = 0.000
| time   V(typ)   V(min)   V(max)
0s        1.12V      1.05V      1.18V
800ps     1.11V      1.04V      1.13V
1ns       1.08V      1.04V      830mV
1.2ns     980mV      1.03V      510mV
1.6ns     640mV      970mV      210mV
2ns       270mV      850mV      69.57mV
2.2ns     170mV      740mV      37.84mV
3ns       22.36mV    220mV      9.81mV
3.8ns     10.23mV    40.16mV    5.53mV
10ns      1.17mV     1.75mV     1.01mV
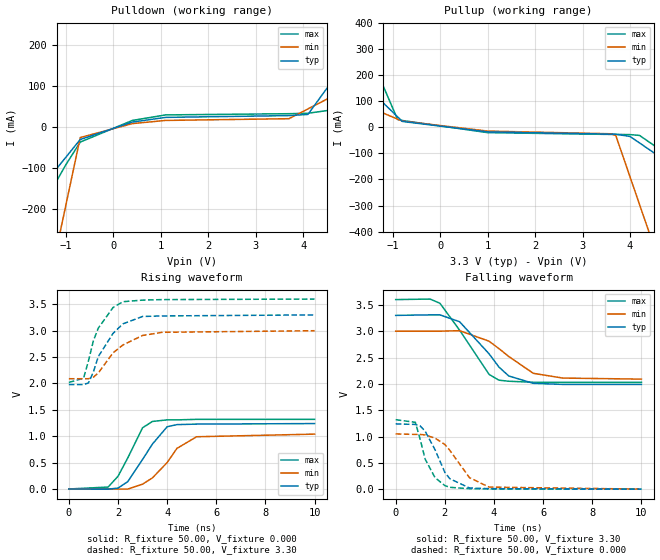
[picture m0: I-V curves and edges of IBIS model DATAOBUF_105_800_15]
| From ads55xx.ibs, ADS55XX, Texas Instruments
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|   Model DATAOBUF_105_800_15
[Model]   DATAOBUF_105_800_15
Model_type   Output
Polarity   Non-Inverting
Vmeas =   1.65V
C_comp   3.00pF   3.00pF   3.00pF
[Temperature Range]   50.00   0.10k   -20.00
[Voltage Range]   3.30V   3.00V   3.60V
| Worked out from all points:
|   slope of the pulldown table from 0 to 0.495 V, typ, clamps not added: 34 ohm
|   slope of the pullup table from 0 to 0.495 V, typ, clamps not added: 46.2 ohm
|   rising waveform, R_fixture 50.00, V_fixture 0.000: 20-80 % time 980ps typ, 1.18ns min, 831ps max; typ from 0 V to 1.24 V
|   rising waveform, R_fixture 50.00, V_fixture 3.30: 20-80 % time 955ps typ, 1.21ns min, 791ps max; typ from 1.98 V to 3.3 V
|   falling waveform, R_fixture 50.00, V_fixture 3.30: 20-80 % time 1.44ns typ, 1.59ns min, 1.3ns max; typ from 3.3 V to 1.99 V
|   falling waveform, R_fixture 50.00, V_fixture 0.000: 20-80 % time 764ps typ, 1.01ns min, 614ps max; typ from 1.24 V to 0.001 V
[Pulldown]
| voltage   I(typ)   I(min)   I(max)
-3.3V     -400mA     -1.437A    -556.6mA
-2.3V     -257.7mA   -893.7mA   -354.1mA
-1.7V     -172.4mA   -568.1mA   -232.6mA
-1.5V     -143.9mA   -459.5mA   -192.1mA
-1V       -72.74mA   -188.1mA   -90.83mA
-700mV    -30.05mA   -25.26mA   -36.35mA
400mV     12.36mA    8.63mA     16.37mA
1.1V      23.74mA    16.31mA    29.75mA
3.7V      28.05mA    20.55mA    32.7mA
4.1V      30.91mA    44.31mA    33.75mA
5.5V      253.1mA    127.5mA    56.49mA
6.6V      427.7mA    192.8mA    75.41mA
[Pullup]
| voltage   I(typ)   I(min)   I(max)
-3.3V     461.7mA    212.6mA    1.043A
-3.1V     426.5mA    197.4mA    958.3mA
-1.9V     215.3mA    106.5mA    451.4mA
-900mV    39.34mA    30.66mA    29.04mA
-800mV    21.74mA    23.08mA    25.39mA
1V        -18.17mA   -15.08mA   -21.06mA
3.6V      -26.85mA   -25.43mA   -27.94mA
3.7V      -27.03mA   -32.05mA   -28.02mA
4V        -35.75mA   -190.3mA   -28.51mA
4.2V      -60.47mA   -295.9mA   -31.68mA
4.5V      -97.55mA   -454.1mA   -69.12mA
6.6V      -357.1mA   -1.562A    -388.8mA
[Ramp]
| variable   typ   min   max
dV/dt_r   0.74/0.97n   0.63/1.23n   0.79/0.88n
dV/dt_f   0.79/1.46n   0.54/1.59n   0.94/1.30n
R_load = 50.00
[Rising Waveform]
R_fixture = 50.00
V_fixture = 0.000
V_fixture_min = 0.000
V_fixture_max = 0.000
| time   V(typ)   V(min)   V(max)
0s        12.91nV    17.25nV    25.05nV
1.6ns     -3.29mV    -2.34mV    37.2mV
2ns       16.81mV    -2.24mV    240mV
2.4ns     140mV      -1.29mV    590mV
3ns       560mV      91.25mV    1.16V
3.4ns     850mV      210mV      1.28V
4ns       1.18V      500mV      1.31V
4.4ns     1.22V      770mV      1.31V
5.2ns     1.23V      990mV      1.32V
10ns      1.24V      1.04V      1.32V
[Rising Waveform]
R_fixture = 50.00
V_fixture = 3.30
V_fixture_min = 3.00
V_fixture_max = 3.60
| time   V(typ)   V(min)   V(max)
0s        1.98V      2.09V      2.02V
600ps     1.98V      2.09V      2.1V
800ps     2.01V      2.09V      2.43V
1ns       2.22V      2.12V      2.81V
1.2ns     2.51V      2.2V       3.05V
1.8ns     2.95V      2.58V      3.44V
2.2ns     3.13V      2.73V      3.55V
3ns       3.27V      2.91V      3.58V
3.8ns     3.28V      2.97V      3.59V
10ns      3.3V       3V         3.6V
[Falling Waveform]
R_fixture = 50.00
V_fixture = 3.30
V_fixture_min = 3.00
V_fixture_max = 3.60
| time   V(typ)   V(min)   V(max)
0s        3.3V       3V         3.6V
1.4ns     3.31V      3V         3.61V
1.8ns     3.31V      3V         3.53V
2.6ns     3.18V      3.01V      3.02V
3.8ns     2.57V      2.81V      2.18V
4.2ns     2.32V      2.67V      2.07V
4.6ns     2.15V      2.52V      2.05V
5.6ns     2.01V      2.2V       2.03V
6.8ns     1.99V      2.11V      2.03V
10ns      1.99V      2.09V      2.03V
[Falling Waveform]
R_fixture = 50.00
V_fixture = 0.000
V_fixture_min = 0.000
V_fixture_max = 0.000
| time   V(typ)   V(min)   V(max)
0s        1.24V      1.05V      1.32V
800ps     1.23V      1.04V      1.27V
1ns       1.2V       1.04V      940mV
1.2ns     1.1V       1.03V      570mV
1.6ns     750mV      970mV      220mV
2ns       320mV      850mV      68.82mV
2.2ns     200mV      740mV      36.4mV
3ns       23.6mV     220mV      9.7mV
3.8ns     10.59mV    40.16mV    5.51mV
10ns      1.18mV     1.75mV     980uV
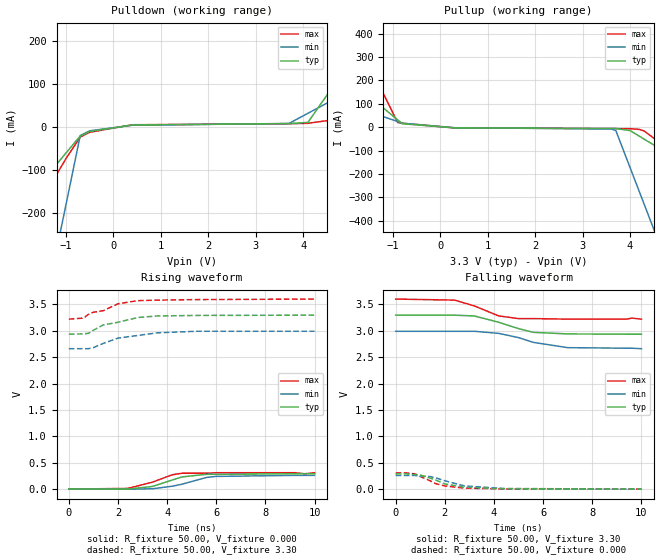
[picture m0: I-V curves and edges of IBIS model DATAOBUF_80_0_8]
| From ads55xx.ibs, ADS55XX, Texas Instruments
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|   Model DATAOBUF_80_0_8
[Model]   DATAOBUF_80_0_8
Model_type   Output
Polarity   Non-Inverting
Vmeas =   1.65V
C_comp   3.00pF   3.00pF   3.00pF
[Temperature Range]   50.00   0.10k   -20.00
[Voltage Range]   3.30V   3.00V   3.60V
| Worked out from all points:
|   slope of the pulldown table from 0 to 0.495 V, typ, clamps not added: 88 ohm
|   slope of the pullup table from 0 to 0.495 V, typ, clamps not added: 112 ohm
|   rising waveform, R_fixture 50.00, V_fixture 0.000: 20-80 % time 1.15ns typ, 1.34ns min, 1.17ns max; typ from 0 V to 0.29 V
|   rising waveform, R_fixture 50.00, V_fixture 3.30: 20-80 % time 1.54ns typ, 1.71ns min, 1.38ns max; typ from 2.94 V to 3.29 V
|   falling waveform, R_fixture 50.00, V_fixture 3.30: 20-80 % time 1.46ns typ, 1.68ns min, 1.28ns max; typ from 3.29 V to 2.94 V
|   falling waveform, R_fixture 50.00, V_fixture 0.000: 20-80 % time 1.17ns typ, 1.27ns min, 1.02ns max; typ from 0.29 V to 0.002 V
[Pulldown]
| voltage   I(typ)   I(min)   I(max)
-3.3V     -364.6mA   -1.415A    -505.7mA
-2.3V     -232.3mA   -878.5mA   -317.7mA
-1.9V     -179.4mA   -663.7mA   -242.5mA
-1.5V     -126.5mA   -449mA     -167.3mA
-1V       -60.34mA   -180.6mA   -73.3mA
-700mV    -20.65mA   -19.58mA   -23.22mA
-500mV    -10.16mA   -8.55mA    -12.02mA
400mV     5.09mA     4.42mA     5.56mA
3.7V      8.24mA     8.61mA     7.94mA
4.1V      11.05mA    32.33mA    8.91mA
5.5V      233.1mA    115.3mA    30.8mA
6.6V      407.5mA    180.6mA    49.01mA
[Pullup]
| voltage   I(typ)   I(min)   I(max)
-3.3V     435.4mA    190.6mA    1.014A
-1.9V     199.6mA    93.41mA    433.6mA
-900mV    31.21mA    24.01mA    19.43mA
-800mV    14.37mA    17.07mA    16.63mA
300mV     -2.83mA    -2.49mA    -3.48mA
3.6V      -5.91mA    -7.92mA    -6.26mA
3.7V      -6.02mA    -14.5mA    -6.3mA
4V        -14.58mA   -172.6mA   -6.64mA
4.2V      -39.18mA   -278.1mA   -9.72mA
4.3V      -51.48mA   -330.8mA   -16.67mA
4.5V      -76.08mA   -436.2mA   -47.05mA
6.6V      -334.4mA   -1.543A    -366mA
[Ramp]
| variable   typ   min   max
dV/dt_r   0.17/1.18n   0.16/1.37n   0.18/1.11n
dV/dt_f   0.22/1.49n   0.20/1.65n   0.23/1.24n
R_load = 50.00
[Rising Waveform]
R_fixture = 50.00
V_fixture = 0.000
V_fixture_min = 0.000
V_fixture_max = 0.000
| time   V(typ)   V(min)   V(max)
0s        17.89nV    21.75nV    37.85nV
2.4ns     -730uV     -1.54mV    12.65mV
3.4ns     49.91mV    5.54mV     130mV
4.2ns     170mV      53.75mV    270mV
4.6ns     230mV      91.8mV     300mV
5.6ns     280mV      220mV      300mV
6ns       280mV      240mV      310mV
9.2ns     290mV      260mV      310mV
9.6ns     290mV      260mV      290mV
10ns      290mV      260mV      310mV
[Rising Waveform]
R_fixture = 50.00
V_fixture = 3.30
V_fixture_min = 3.00
V_fixture_max = 3.60
| time   V(typ)   V(min)   V(max)
0s        2.935V     2.66V      3.22V
600ps     2.94V      2.66V      3.24V
800ps     2.95V      2.66V      3.31V
1ns       3.01V      2.68V      3.35V
1.4ns     3.11V      2.76V      3.38V
2ns       3.16V      2.86V      3.51V
2.8ns     3.25V      2.91V      3.57V
3.6ns     3.28V      2.96V      3.58V
5.2ns     3.29V      2.99V      3.59V
10ns      3.295V     2.99V      3.6V
[Falling Waveform]
R_fixture = 50.00
V_fixture = 3.30
V_fixture_min = 3.00
V_fixture_max = 3.60
| time   V(typ)   V(min)   V(max)
0s        3.295V     2.99V      3.6V
2.4ns     3.295V     2.99V      3.58V
3.2ns     3.28V      2.99V      3.47V
4.2ns     3.16V      2.95V      3.28V
5ns       3.04V      2.87V      3.23V
5.6ns     2.97V      2.78V      3.23V
7ns       2.94V      2.68V      3.22V
9.4ns     2.935V     2.67V      3.22V
9.6ns     2.935V     2.67V      3.24V
10ns      2.935V     2.66V      3.22V
[Falling Waveform]
R_fixture = 50.00
V_fixture = 0.000
V_fixture_min = 0.000
V_fixture_max = 0.000
| time   V(typ)   V(min)   V(max)
0s        290mV      260mV      310mV
400ps     290mV      260mV      310mV
800ps     280mV      260mV      290mV
1ns       270mV      250mV      240mV
1.4ns     210mV      240mV      160mV
1.6ns     180mV      220mV      110mV
2ns       100mV      160mV      61.66mV
2.8ns     36.94mV    62.69mV    21.21mV
4.4ns     8.56mV     13.93mV    5.44mV
10ns      1.66mV     2.01mV     1.36mV
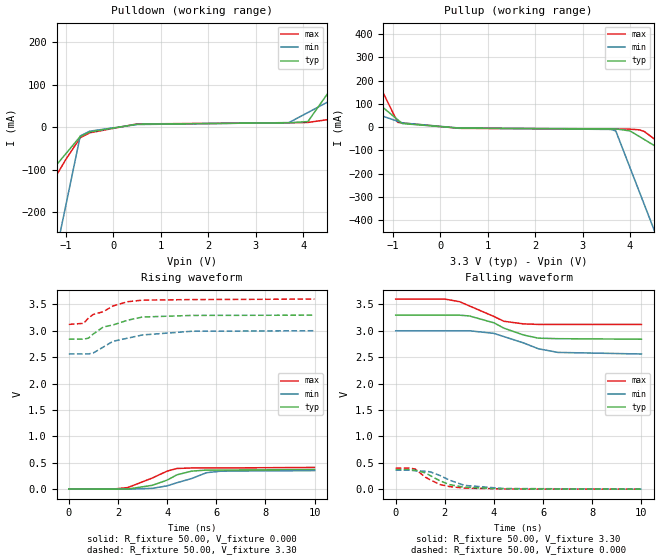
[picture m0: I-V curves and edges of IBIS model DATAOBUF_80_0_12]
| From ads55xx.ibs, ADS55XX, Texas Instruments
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|   Model DATAOBUF_80_0_12
[Model]   DATAOBUF_80_0_12
Model_type   Output
Polarity   Non-Inverting
Vmeas =   1.65V
C_comp   3.00pF   3.00pF   3.00pF
[Temperature Range]   50.00   0.10k   -20.00
[Voltage Range]   3.30V   3.00V   3.60V
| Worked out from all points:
|   slope of the pulldown table from 0 to 0.495 V, typ, clamps not added: 71.3 ohm
|   slope of the pullup table from 0 to 0.495 V, typ, clamps not added: 94.4 ohm
|   rising waveform, R_fixture 50.00, V_fixture 0.000: 20-80 % time 1.16ns typ, 1.34ns min, 1.19ns max; typ from 0 V to 0.37 V
|   rising waveform, R_fixture 50.00, V_fixture 3.30: 20-80 % time 1.45ns typ, 1.69ns min, 1.22ns max; typ from 2.84 V to 3.29 V
|   falling waveform, R_fixture 50.00, V_fixture 3.30: 20-80 % time 1.49ns typ, 1.67ns min, 1.39ns max; typ from 3.29 V to 2.84 V
|   falling waveform, R_fixture 50.00, V_fixture 0.000: 20-80 % time 1.05ns typ, 1.14ns min, 921ps max; typ from 0.37 V to 0.002 V
[Pulldown]
| voltage   I(typ)   I(min)   I(max)
-3.3V     -369.6mA   -1.42A     -510.3mA
-2.3V     -235.9mA   -881.6mA   -321.2mA
-1.9V     -182.5mA   -666.4mA   -245.5mA
-1.5V     -129mA     -451.2mA   -169.9mA
-1V       -62.12mA   -182.2mA   -75.34mA
-700mV    -22.01mA   -20.84mA   -24.88mA
-500mV    -11.22mA   -9.52mA    -13.32mA
500mV     6.98mA     6.17mA     7.61mA
3.7V      10.3mA     10.72mA    10.05mA
4.1V      13.13mA    34.44mA    11.06mA
5.5V      235.2mA    117.5mA    33.16mA
6.6V      409.6mA    182.7mA    51.53mA
[Pullup]
| voltage   I(typ)   I(min)   I(max)
-3.3V     438.8mA    194.6mA    1.018A
-1.9V     201.7mA    95.8mA     436.1mA
-900mV    32.25mA    25.2mA     20.83mA
-800mV    15.31mA    18.14mA    17.91mA
400mV     -4.21mA    -3.84mA    -5.1mA
3.6V      -7.54mA    -9.91mA    -8.25mA
3.7V      -7.66mA    -16.49mA   -8.29mA
4V        -16.22mA   -174.6mA   -8.65mA
4.2V      -40.84mA   -280mA     -11.74mA
4.3V      -53.15mA   -332.7mA   -18.69mA
4.5V      -77.77mA   -438.2mA   -49.08mA
6.6V      -336.3mA   -1.545A    -368.2mA
[Ramp]
| variable   typ   min   max
dV/dt_r   0.22/1.21n   0.21/1.37n   0.24/1.12n
dV/dt_f   0.28/1.52n   0.26/1.65n   0.29/1.35n
R_load = 50.00
[Rising Waveform]
R_fixture = 50.00
V_fixture = 0.000
V_fixture_min = 0.000
V_fixture_max = 0.000
| time   V(typ)   V(min)   V(max)
0s        16.74nV    20.43nV    35.02nV
1.8ns     -1.62mV    -940uV     -750uV
2.4ns     260uV      -1.84mV    29.05mV
3.4ns     71.63mV    14.03mV    210mV
4ns       170mV      61.01mV    340mV
4.4ns     270mV      120mV      390mV
5ns       340mV      200mV      400mV
5.6ns     360mV      310mV      400mV
6.2ns     360mV      340mV      400mV
10ns      370mV      350mV      410mV
[Rising Waveform]
R_fixture = 50.00
V_fixture = 3.30
V_fixture_min = 3.00
V_fixture_max = 3.60
| time   V(typ)   V(min)   V(max)
0s        2.84V      2.56V      3.12V
600ps     2.84V      2.56V      3.14V
800ps     2.86V      2.56V      3.24V
1ns       2.94V      2.58V      3.31V
1.4ns     3.07V      2.69V      3.36V
1.8ns     3.11V      2.8V       3.47V
2.4ns     3.2V       2.86V      3.55V
3ns       3.26V      2.92V      3.58V
5ns       3.29V      2.99V      3.59V
10ns      3.295V     3V         3.6V
[Falling Waveform]
R_fixture = 50.00
V_fixture = 3.30
V_fixture_min = 3.00
V_fixture_max = 3.60
| time   V(typ)   V(min)   V(max)
0s        3.295V     3V         3.6V
2ns       3.295V     3V         3.6V
2.6ns     3.295V     3V         3.55V
3ns       3.28V      3V         3.47V
4ns       3.15V      2.95V      3.27V
4.4ns     3.05V      2.89V      3.18V
5.2ns     2.92V      2.77V      3.13V
5.8ns     2.86V      2.66V      3.12V
6.6ns     2.85V      2.59V      3.12V
10ns      2.84V      2.56V      3.12V
[Falling Waveform]
R_fixture = 50.00
V_fixture = 0.000
V_fixture_min = 0.000
V_fixture_max = 0.000
| time   V(typ)   V(min)   V(max)
0s        370mV      360mV      400mV
600ps     370mV      360mV      400mV
800ps     360mV      350mV      380mV
1.2ns     310mV      340mV      230mV
1.4ns     260mV      330mV      180mV
1.8ns     160mV      260mV      89.3mV
2.2ns     86.49mV    170mV      50.21mV
2.8ns     37.93mV    72.65mV    20.89mV
4.4ns     8.14mV     13.55mV    5.27mV
10ns      1.56mV     1.9mV      1.3mV
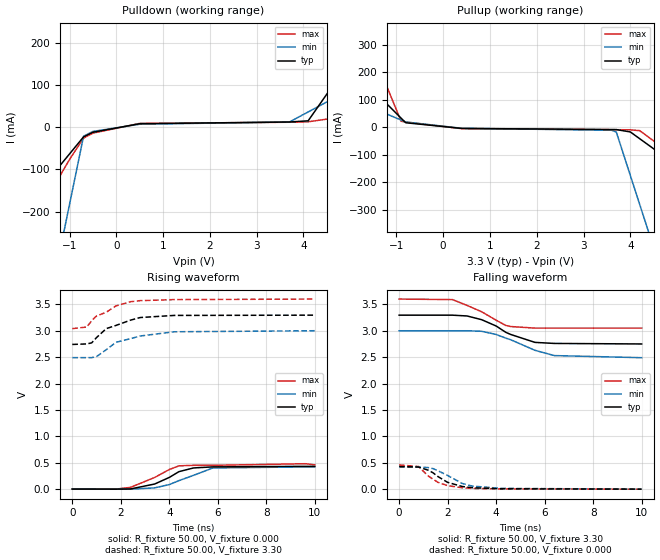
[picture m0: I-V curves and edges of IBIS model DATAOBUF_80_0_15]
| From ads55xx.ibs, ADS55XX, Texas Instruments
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|   Model DATAOBUF_80_0_15
[Model]   DATAOBUF_80_0_15
Model_type   Output
Polarity   Non-Inverting
Vmeas =   1.65V
C_comp   3.00pF   3.00pF   3.00pF
[Temperature Range]   50.00   0.10k   -20.00
[Voltage Range]   3.30V   3.00V   3.60V
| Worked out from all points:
|   slope of the pulldown table from 0 to 0.495 V, typ, clamps not added: 61.7 ohm
|   slope of the pullup table from 0 to 0.495 V, typ, clamps not added: 85.2 ohm
|   rising waveform, R_fixture 50.00, V_fixture 0.000: 20-80 % time 1.16ns typ, 1.34ns min, 1.23ns max; typ from 0 V to 0.43 V
|   rising waveform, R_fixture 50.00, V_fixture 3.30: 20-80 % time 1.33ns typ, 1.55ns min, 1.18ns max; typ from 2.74 V to 3.29 V
|   falling waveform, R_fixture 50.00, V_fixture 3.30: 20-80 % time 1.48ns typ, 1.72ns min, 1.4ns max; typ from 3.29 V to 2.75 V
|   falling waveform, R_fixture 50.00, V_fixture 0.000: 20-80 % time 977ps typ, 1.1ns min, 862ps max; typ from 0.43 V to 0.001 V
[Pulldown]
| voltage   I(typ)   I(min)   I(max)
-3.3V     -373.6mA   -1.423A    -513.8mA
-2.3V     -238.8mA   -883.9mA   -323.8mA
-1.9V     -184.9mA   -668.3mA   -247.8mA
-1.5V     -131mA     -452.8mA   -171.8mA
-1V       -63.56mA   -183.3mA   -76.78mA
-700mV    -23.12mA   -21.65mA   -26.01mA
-500mV    -12.09mA   -10.15mA   -14.2mA
500mV     8.07mA     6.93mA     8.81mA
3.7V      12.17mA    12.24mA    11.62mA
4.1V      15.01mA    36mA       12.65mA
5.5V      237mA      119.2mA    34.94mA
6.6V      411.5mA    184.5mA    53.48mA
[Pullup]
| voltage   I(typ)   I(min)   I(max)
-3.3V     441mA      196.8mA    1.019A
-3.1V     407mA      182.5mA    936.3mA
-1.9V     203mA      97.1mA     437.3mA
-900mV    32.96mA    25.9mA     21.5mA
-800mV    15.96mA    18.78mA    18.52mA
400mV     -4.65mA    -4.26mA    -5.59mA
3.6V      -8.8mA     -11.31mA   -9.32mA
3.7V      -8.92mA    -17.89mA   -9.37mA
4V        -17.5mA    -176.1mA   -9.74mA
4.2V      -42.12mA   -281.5mA   -12.84mA
4.5V      -79.05mA   -439.6mA   -50.18mA
6.6V      -337.6mA   -1.547A    -369.3mA
[Ramp]
| variable   typ   min   max
dV/dt_r   0.26/1.21n   0.25/1.35n   0.28/1.18n
dV/dt_f   0.33/1.51n   0.31/1.67n   0.33/1.38n
R_load = 50.00
[Rising Waveform]
R_fixture = 50.00
V_fixture = 0.000
V_fixture_min = 0.000
V_fixture_max = 0.000
| time   V(typ)   V(min)   V(max)
0s        15.93nV    19.67nV    33.34nV
1.8ns     -1.81mV    -1.07mV    -610uV
2.4ns     1.86mV     -2.04mV    32.06mV
3.4ns     95.89mV    22.68mV    220mV
4ns       220mV      84.7mV     370mV
4.4ns     330mV      160mV      440mV
5ns       400mV      260mV      450mV
5.8ns     420mV      400mV      450mV
9.6ns     430mV      420mV      480mV
10ns      430mV      420mV      460mV
[Rising Waveform]
R_fixture = 50.00
V_fixture = 3.30
V_fixture_min = 3.00
V_fixture_max = 3.60
| time   V(typ)   V(min)   V(max)
0s        2.74V      2.49V      3.04V
600ps     2.75V      2.49V      3.07V
800ps     2.77V      2.49V      3.19V
1ns       2.87V      2.51V      3.28V
1.4ns     3.04V      2.64V      3.35V
1.8ns     3.1V       2.78V      3.47V
2.4ns     3.2V       2.85V      3.55V
2.8ns     3.25V      2.9V       3.57V
4.2ns     3.29V      2.98V      3.59V
10ns      3.295V     3V         3.6V
[Falling Waveform]
R_fixture = 50.00
V_fixture = 3.30
V_fixture_min = 3.00
V_fixture_max = 3.60
| time   V(typ)   V(min)   V(max)
0s        3.295V     3V         3.6V
2.2ns     3.295V     3V         3.59V
2.8ns     3.28V      3V         3.48V
3.4ns     3.21V      2.99V      3.36V
4ns       3.09V      2.93V      3.2V
4.4ns     2.97V      2.86V      3.1V
4.6ns     2.93V      2.83V      3.08V
5.6ns     2.78V      2.63V      3.05V
6.4ns     2.76V      2.53V      3.05V
10ns      2.75V      2.49V      3.05V
[Falling Waveform]
R_fixture = 50.00
V_fixture = 0.000
V_fixture_min = 0.000
V_fixture_max = 0.000
| time   V(typ)   V(min)   V(max)
0s        430mV      420mV      460mV
800ps     420mV      420mV      430mV
1.2ns     360mV      410mV      250mV
1.4ns     310mV      390mV      190mV
1.6ns     240mV      350mV      130mV
2ns       130mV      260mV      67.73mV
2.6ns     52.07mV    110mV      28.17mV
3ns       28.77mV    60.52mV    15.13mV
4.2ns     9.06mV     16.22mV    5.82mV
10ns      1.48mV     1.83mV     1.26mV
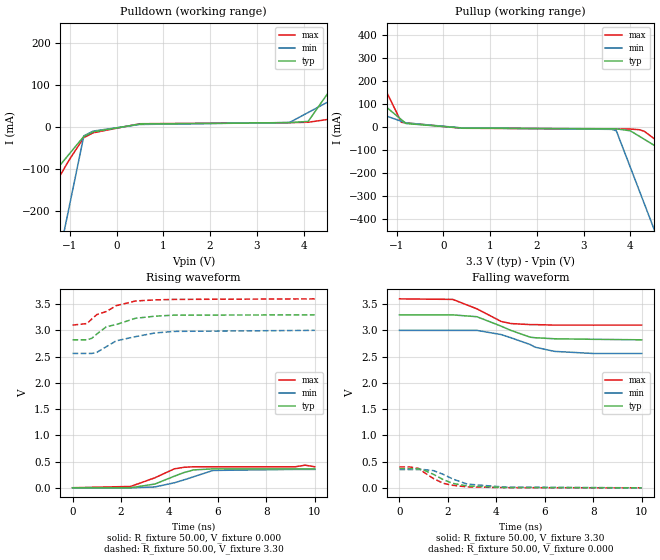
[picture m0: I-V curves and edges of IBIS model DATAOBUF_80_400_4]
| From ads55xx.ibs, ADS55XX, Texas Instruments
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|   Model DATAOBUF_80_400_4
[Model]   DATAOBUF_80_400_4
Model_type   Output
Polarity   Non-Inverting
Vmeas =   1.65V
C_comp   3.00pF   3.00pF   3.00pF
[Temperature Range]   50.00   0.10k   -20.00
[Voltage Range]   3.30V   3.00V   3.60V
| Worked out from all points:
|   slope of the pulldown table from 0 to 0.495 V, typ, clamps not added: 69.7 ohm
|   slope of the pullup table from 0 to 0.495 V, typ, clamps not added: 94.4 ohm
|   rising waveform, R_fixture 50.00, V_fixture 0.000: 20-80 % time 1.17ns typ, 1.31ns min, 1.22ns max; typ from 0 V to 0.36 V
|   rising waveform, R_fixture 50.00, V_fixture 3.30: 20-80 % time 1.44ns typ, 1.69ns min, 1.19ns max; typ from 2.82 V to 3.29 V
|   falling waveform, R_fixture 50.00, V_fixture 3.30: 20-80 % time 1.5ns typ, 1.68ns min, 1.33ns max; typ from 3.29 V to 2.82 V
|   falling waveform, R_fixture 50.00, V_fixture 0.000: 20-80 % time 1.09ns typ, 1.15ns min, 927ps max; typ from 0.37 V to 0.002 V
[Pulldown]
| voltage   I(typ)   I(min)   I(max)
-3.3V     -370.3mA   -1.42A     -510.8mA
-2.3V     -236.4mA   -881.8mA   -321.6mA
-1.9V     -182.8mA   -666.6mA   -246mA
-1.5V     -129.3mA   -451.4mA   -170.3mA
-1V       -62.34mA   -182.3mA   -75.67mA
-700mV    -22.17mA   -20.89mA   -25.16mA
-500mV    -11.35mA   -9.56mA    -13.54mA
500mV     7.14mA     6.22mA     7.9mA
3.7V      10.56mA    10.82mA    10.43mA
4.1V      13.39mA    34.54mA    11.44mA
5.5V      235.6mA    117.6mA    33.6mA
6.6V      410.1mA    182.8mA    52.03mA
[Pullup]
| voltage   I(typ)   I(min)   I(max)
-3.3V     438.8mA    194.4mA    1.017A
-1.9V     201.6mA    95.67mA    436mA
-900mV    32.24mA    25.17mA    20.79mA
-800mV    15.3mA     18.12mA    17.87mA
400mV     -4.2mA     -3.82mA    -5.08mA
3.6V      -7.53mA    -9.87mA    -8.19mA
3.7V      -7.64mA    -16.45mA   -8.23mA
4V        -16.21mA   -174.6mA   -8.59mA
4.2V      -40.83mA   -280.1mA   -11.68mA
4.3V      -53.14mA   -332.8mA   -18.63mA
4.5V      -77.76mA   -438.2mA   -49.02mA
6.6V      -336.3mA   -1.545A    -368.1mA
[Ramp]
| variable   typ   min   max
dV/dt_r   0.22/1.22n   0.21/1.34n   0.24/1.15n
dV/dt_f   0.28/1.50n   0.26/1.65n   0.30/1.28n
R_load = 50.00
[Rising Waveform]
R_fixture = 50.00
V_fixture = 0.000
V_fixture_min = 0.000
V_fixture_max = 0.000
| time   V(typ)   V(min)   V(max)
0s        16.61nV    20.38nV    34.56nV
2.4ns     190uV      -1.86mV    24.98mV
3.4ns     70.76mV    15.26mV    190mV
4.2ns     220mV      94.28mV    360mV
4.6ns     290mV      150mV      390mV
5ns       340mV      210mV      400mV
5.8ns     360mV      330mV      400mV
9.2ns     360mV      350mV      400mV
9.6ns     360mV      350mV      430mV
10ns      360mV      350mV      400mV
[Rising Waveform]
R_fixture = 50.00
V_fixture = 3.30
V_fixture_min = 3.00
V_fixture_max = 3.60
| time   V(typ)   V(min)   V(max)
0s        2.82V      2.56V      3.1V
600ps     2.82V      2.56V      3.13V
800ps     2.85V      2.56V      3.22V
1ns       2.93V      2.58V      3.3V
1.4ns     3.07V      2.69V      3.36V
1.8ns     3.11V      2.8V       3.47V
2.6ns     3.23V      2.88V      3.56V
3.4ns     3.27V      2.95V      3.58V
4.2ns     3.29V      2.98V      3.59V
10ns      3.295V     3V         3.6V
[Falling Waveform]
R_fixture = 50.00
V_fixture = 3.30
V_fixture_min = 3.00
V_fixture_max = 3.60
| time   V(typ)   V(min)   V(max)
0s        3.295V     3V         3.6V
2.2ns     3.295V     3V         3.59V
3.2ns     3.26V      3V         3.41V
4.2ns     3.08V      2.92V      3.17V
4.6ns     3V         2.86V      3.13V
5.4ns     2.87V      2.73V      3.11V
5.6ns     2.86V      2.68V      3.11V
6.4ns     2.84V      2.6V       3.1V
8ns       2.83V      2.56V      3.1V
10ns      2.82V      2.56V      3.1V
[Falling Waveform]
R_fixture = 50.00
V_fixture = 0.000
V_fixture_min = 0.000
V_fixture_max = 0.000
| time   V(typ)   V(min)   V(max)
0s        370mV      350mV      400mV
400ps     370mV      350mV      400mV
800ps     360mV      350mV      370mV
1ns       340mV      350mV      300mV
1.4ns     260mV      330mV      180mV
1.8ns     160mV      260mV      89.18mV
2.2ns     86.44mV    170mV      49.63mV
2.8ns     37.6mV     72.44mV    19.36mV
4.4ns     7.98mV     13.49mV    4.99mV
10ns      1.54mV     1.89mV     1.29mV
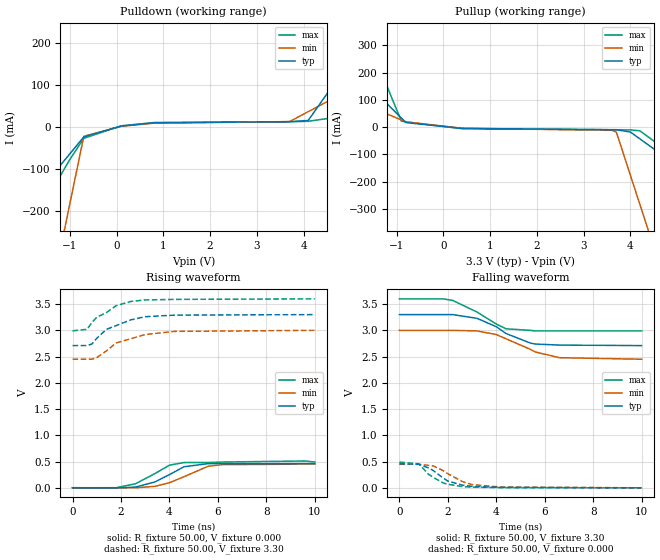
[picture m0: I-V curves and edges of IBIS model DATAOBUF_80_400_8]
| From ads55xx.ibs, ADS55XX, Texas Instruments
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|   Model DATAOBUF_80_400_8
[Model]   DATAOBUF_80_400_8
Model_type   Output
Polarity   Non-Inverting
Vmeas =   1.65V
C_comp   3.00pF   3.00pF   3.00pF
[Temperature Range]   50.00   0.10k   -20.00
[Voltage Range]   3.30V   3.00V   3.60V
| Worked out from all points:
|   slope of the pulldown table from 0 to 0.495 V, typ, clamps not added: 58.8 ohm
|   slope of the pullup table from 0 to 0.495 V, typ, clamps not added: 81.1 ohm
|   rising waveform, R_fixture 50.00, V_fixture 0.000: 20-80 % time 1.11ns typ, 1.34ns min, 1.17ns max; typ from 0 V to 0.46 V
|   rising waveform, R_fixture 50.00, V_fixture 3.30: 20-80 % time 1.32ns typ, 1.5ns min, 1.11ns max; typ from 2.71 V to 3.3 V
|   falling waveform, R_fixture 50.00, V_fixture 3.30: 20-80 % time 1.53ns typ, 1.72ns min, 1.36ns max; typ from 3.3 V to 2.71 V
|   falling waveform, R_fixture 50.00, V_fixture 0.000: 20-80 % time 966ps typ, 1.08ns min, 846ps max; typ from 0.46 V to 0.001 V
[Pulldown]
| voltage   I(typ)   I(min)   I(max)
-3.3V     -375.1mA   -1.424A    -516.6mA
-2.3V     -239.9mA   -885.1mA   -325.8mA
-1.9V     -185.8mA   -669.3mA   -249.5mA
-1.5V     -131.7mA   -453.6mA   -173.2mA
-1V       -64.11mA   -183.9mA   -77.8mA
-700mV    -23.55mA   -22.05mA   -26.77mA
100mV     2.37mA     1.92mA     3.02mA
800mV     10.35mA    9.36mA     10.75mA
3.7V      12.92mA    13.04mA    12.74mA
4.1V      15.76mA    36.76mA    13.78mA
5.5V      237.9mA    119.8mA    36.14mA
6.6V      412.5mA    185mA      54.73mA
[Pullup]
| voltage   I(typ)   I(min)   I(max)
-3.3V     442.1mA    197.8mA    1.021A
-3.1V     408mA      183.5mA    937.3mA
-1.9V     203.6mA    97.68mA    438mA
-900mV    33.34mA    26.18mA    21.9mA
-800mV    16.31mA    19.03mA    18.89mA
400mV     -4.89mA    -4.42mA    -5.87mA
3.6V      -9.53mA    -11.9mA    -10mA
3.7V      -9.65mA    -18.48mA   -10.04mA
4V        -18.23mA   -176.6mA   -10.42mA
4.2V      -42.87mA   -282.1mA   -13.52mA
4.5V      -79.83mA   -440.2mA   -50.87mA
6.6V      -338.6mA   -1.547A    -370.1mA
[Ramp]
| variable   typ   min   max
dV/dt_r   0.28/1.19n   0.27/1.35n   0.30/1.14n
dV/dt_f   0.35/1.51n   0.33/1.68n   0.37/1.32n
R_load = 50.00
[Rising Waveform]
R_fixture = 50.00
V_fixture = 0.000
V_fixture_min = 0.000
V_fixture_max = 0.000
| time   V(typ)   V(min)   V(max)
0s        15.66nV    19.31nV    32.36nV
1.8ns     -1.91mV    -1.14mV    180uV
2.6ns     12.88mV    -2.05mV    76.27mV
3.4ns     110mV      26.81mV    270mV
4ns       250mV      95.41mV    430mV
4.6ns     400mV      210mV      480mV
5.6ns     460mV      410mV      480mV
6.2ns     460mV      440mV      490mV
9.6ns     460mV      450mV      510mV
10ns      460mV      450mV      490mV
[Rising Waveform]
R_fixture = 50.00
V_fixture = 3.30
V_fixture_min = 3.00
V_fixture_max = 3.60
| time   V(typ)   V(min)   V(max)
0s        2.71V      2.45V      2.99V
600ps     2.71V      2.45V      3.02V
800ps     2.74V      2.45V      3.15V
1ns       2.85V      2.48V      3.25V
1.4ns     3.02V      2.61V      3.34V
1.8ns     3.09V      2.76V      3.47V
2.4ns     3.2V       2.84V      3.55V
3ns       3.26V      2.92V      3.58V
4.2ns     3.29V      2.98V      3.59V
10ns      3.3V       3V         3.6V
[Falling Waveform]
R_fixture = 50.00
V_fixture = 3.30
V_fixture_min = 3.00
V_fixture_max = 3.60
| time   V(typ)   V(min)   V(max)
0s        3.3V       3V         3.6V
1.8ns     3.3V       3V         3.6V
2.2ns     3.3V       3V         3.57V
3.2ns     3.23V      2.99V      3.35V
4ns       3.07V      2.92V      3.12V
4.4ns     2.94V      2.84V      3.03V
5.4ns     2.76V      2.64V      3V
5.6ns     2.74V      2.59V      2.99V
6.6ns     2.72V      2.48V      2.99V
10ns      2.71V      2.45V      2.99V
[Falling Waveform]
R_fixture = 50.00
V_fixture = 0.000
V_fixture_min = 0.000
V_fixture_max = 0.000
| time   V(typ)   V(min)   V(max)
0s        460mV      450mV      490mV
800ps     450mV      450mV      460mV
1.2ns     380mV      430mV      260mV
1.4ns     330mV      420mV      200mV
1.8ns     190mV      330mV      94.86mV
2ns       130mV      270mV      68.79mV
2.6ns     53.03mV    120mV      26.1mV
3ns       28.8mV     62.39mV    13.93mV
4.2ns     8.98mV     16.04mV    5.46mV
10ns      1.46mV     1.8mV      1.23mV
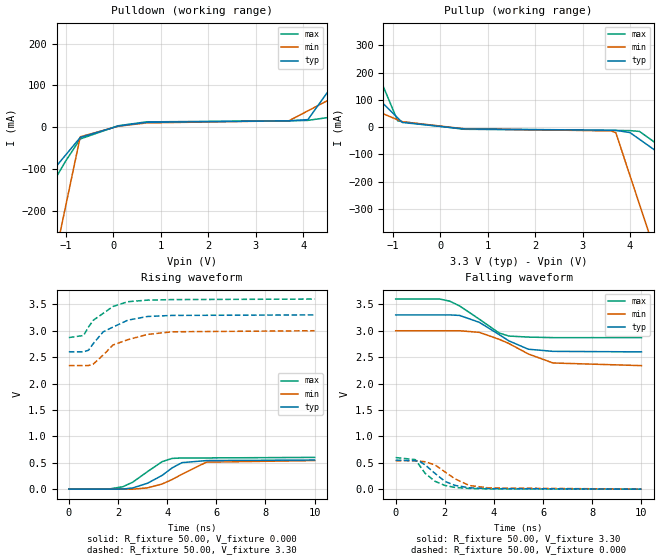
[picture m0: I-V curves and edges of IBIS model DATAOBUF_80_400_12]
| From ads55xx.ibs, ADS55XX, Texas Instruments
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|   Model DATAOBUF_80_400_12
[Model]   DATAOBUF_80_400_12
Model_type   Output
Polarity   Non-Inverting
Vmeas =   1.65V
C_comp   3.00pF   3.00pF   3.00pF
[Temperature Range]   50.00   0.10k   -20.00
[Voltage Range]   3.30V   3.00V   3.60V
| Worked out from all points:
|   slope of the pulldown table from 0 to 0.495 V, typ, clamps not added: 51.6 ohm
|   slope of the pullup table from 0 to 0.495 V, typ, clamps not added: 72.8 ohm
|   rising waveform, R_fixture 50.00, V_fixture 0.000: 20-80 % time 1.11ns typ, 1.34ns min, 1.08ns max; typ from 0 V to 0.55 V
|   rising waveform, R_fixture 50.00, V_fixture 3.30: 20-80 % time 1.23ns typ, 1.42ns min, 1.05ns max; typ from 2.6 V to 3.3 V
|   falling waveform, R_fixture 50.00, V_fixture 3.30: 20-80 % time 1.52ns typ, 1.7ns min, 1.37ns max; typ from 3.3 V to 2.6 V
|   falling waveform, R_fixture 50.00, V_fixture 0.000: 20-80 % time 899ps typ, 1.05ns min, 794ps max; typ from 0.55 V to 0.001 V
[Pulldown]
| voltage   I(typ)   I(min)   I(max)
-3.3V     -379.6mA   -1.428A    -523.3mA
-2.3V     -243.2mA   -887.8mA   -330.6mA
-1.9V     -188.6mA   -671.6mA   -253.4mA
-1.5V     -133.9mA   -455.4mA   -176.3mA
-1V       -65.7mA    -185.2mA   -79.91mA
-700mV    -24.75mA   -23.12mA   -28.3mA
100mV     2.6mA      2.12mA     3.34mA
700mV     11.54mA    10.18mA    12.65mA
3.7V      15.18mA    15.28mA    15.16mA
4.1V      18.03mA    39.04mA    16.22mA
5.5V      240.2mA    122.2mA    38.72mA
6.6V      414.8mA    187.5mA    57.42mA
[Pullup]
| voltage   I(typ)   I(min)   I(max)
-3.3V     445.1mA    200.5mA    1.024A
-3.1V     410.9mA    186.1mA    940.7mA
-1.9V     205.4mA    99.31mA    440.2mA
-900mV    34.24mA    27.01mA    23.12mA
-800mV    17.12mA    19.78mA    20mA
500mV     -6.51mA    -5.91mA    -7.81mA
3.6V      -11.38mA   -13.78mA   -12.25mA
3.7V      -11.51mA   -20.37mA   -12.3mA
4V        -20.1mA    -178.6mA   -12.69mA
4.2V      -44.74mA   -284mA     -15.8mA
4.5V      -81.7mA    -442.2mA   -53.16mA
6.6V      -340.4mA   -1.55A     -372.4mA
[Ramp]
| variable   typ   min   max
dV/dt_r   0.33/1.19n   0.32/1.33n   0.36/1.09n
dV/dt_f   0.42/1.53n   0.39/1.71n   0.44/1.37n
R_load = 50.00
[Rising Waveform]
R_fixture = 50.00
V_fixture = 0.000
V_fixture_min = 0.000
V_fixture_max = 0.000
| time   V(typ)   V(min)   V(max)
0s        14.95nV    18.46nV    30.66nV
1.6ns     -1.32mV    -1.8mV     -1.38mV
2.2ns     11.57uV    -1.93mV    44.63mV
2.6ns     21.57mV    -1.9mV     130mV
3.2ns     110mV      22.28mV    330mV
3.8ns     260mV      96.74mV    520mV
4.2ns     400mV      180mV      580mV
4.6ns     500mV      280mV      590mV
5.6ns     540mV      510mV      590mV
10ns      550mV      540mV      600mV
[Rising Waveform]
R_fixture = 50.00
V_fixture = 3.30
V_fixture_min = 3.00
V_fixture_max = 3.60
| time   V(typ)   V(min)   V(max)
0s        2.6V       2.34V      2.87V
600ps     2.6V       2.34V      2.91V
800ps     2.63V      2.34V      3.07V
1ns       2.76V      2.37V      3.2V
1.4ns     2.98V      2.54V      3.33V
1.8ns     3.07V      2.73V      3.46V
2.4ns     3.2V       2.83V      3.55V
3.2ns     3.27V      2.93V      3.58V
4.2ns     3.29V      2.98V      3.59V
10ns      3.3V       3V         3.6V
[Falling Waveform]
R_fixture = 50.00
V_fixture = 3.30
V_fixture_min = 3.00
V_fixture_max = 3.60
| time   V(typ)   V(min)   V(max)
0s        3.3V       3V         3.6V
1.8ns     3.3V       3V         3.6V
2.2ns     3.3V       3V         3.56V
2.6ns     3.29V      3V         3.47V
3.4ns     3.16V      2.97V      3.22V
4.2ns     2.93V      2.84V      2.96V
4.6ns     2.81V      2.76V      2.9V
5.4ns     2.65V      2.56V      2.88V
6.4ns     2.61V      2.39V      2.87V
10ns      2.6V       2.34V      2.87V
[Falling Waveform]
R_fixture = 50.00
V_fixture = 0.000
V_fixture_min = 0.000
V_fixture_max = 0.000
| time   V(typ)   V(min)   V(max)
0s        550mV      540mV      600mV
800ps     540mV      540mV      560mV
1ns       520mV      530mV      430mV
1.2ns     460mV      520mV      300mV
1.6ns     300mV      460mV      150mV
2ns       150mV      330mV      71.82mV
2.4ns     73.74mV    200mV      35.3mV
3ns       27.65mV    69.56mV    13.08mV
3.8ns     12.13mV    24.41mV    6.94mV
10ns      1.38mV     1.73mV     1.18mV
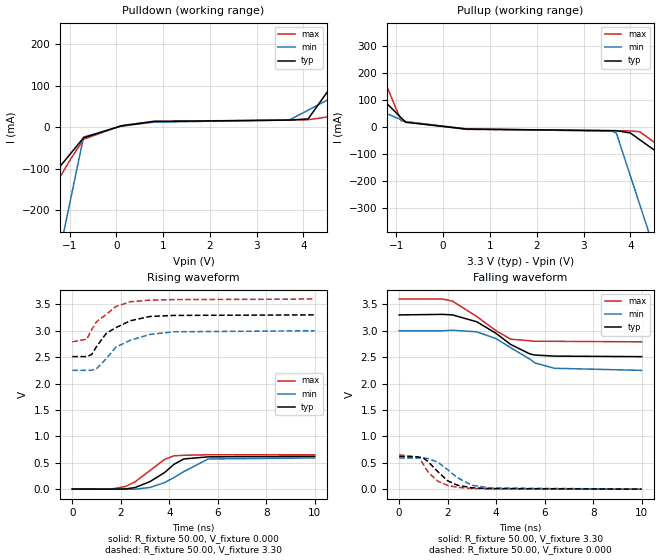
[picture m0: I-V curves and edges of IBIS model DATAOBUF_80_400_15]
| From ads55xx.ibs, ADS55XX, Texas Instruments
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|   Model DATAOBUF_80_400_15
[Model]   DATAOBUF_80_400_15
Model_type   Output
Polarity   Non-Inverting
Vmeas =   1.65V
C_comp   3.00pF   3.00pF   3.00pF
[Temperature Range]   50.00   0.10k   -20.00
[Voltage Range]   3.30V   3.00V   3.60V
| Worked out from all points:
|   slope of the pulldown table from 0 to 0.495 V, typ, clamps not added: 47.4 ohm
|   slope of the pullup table from 0 to 0.495 V, typ, clamps not added: 67.9 ohm
|   rising waveform, R_fixture 50.00, V_fixture 0.000: 20-80 % time 1.15ns typ, 1.32ns min, 1.11ns max; typ from 0 V to 0.62 V
|   rising waveform, R_fixture 50.00, V_fixture 3.30: 20-80 % time 1.17ns typ, 1.34ns min, 1ns max; typ from 2.51 V to 3.3 V
|   falling waveform, R_fixture 50.00, V_fixture 3.30: 20-80 % time 1.58ns typ, 1.57ns min, 1.47ns max; typ from 3.3 V to 2.51 V
|   falling waveform, R_fixture 50.00, V_fixture 0.000: 20-80 % time 880ps typ, 1.04ns min, 748ps max; typ from 0.62 V to 0.001 V
[Pulldown]
| voltage   I(typ)   I(min)   I(max)
-3.3V     -382.9mA   -1.432A    -527.4mA
-2.3V     -245.5mA   -890.2mA   -333.4mA
-1.9V     -190.5mA   -673.6mA   -255.8mA
-1.5V     -135.6mA   -457.1mA   -178.2mA
-1V       -66.88mA   -186.4mA   -81.2mA
-700mV    -25.66mA   -23.94mA   -29.24mA
100mV     2.78mA     2.27mA     3.54mA
800mV     13.52mA    12.07mA    14.41mA
3.7V      17.03mA    17.18mA    16.77mA
4.1V      19.88mA    40.94mA    17.84mA
5.5V      242.2mA    124.1mA    40.46mA
6.6V      416.9mA    189.4mA    59.27mA
[Pullup]
| voltage   I(typ)   I(min)   I(max)
-3.3V     447.2mA    201.9mA    1.026A
-3.1V     412.8mA    187.4mA    942.4mA
-1.9V     206.7mA    100.2mA    441.3mA
-900mV    34.87mA    27.47mA    23.69mA
-800mV    17.69mA    20.2mA     20.52mA
500mV     -7.01mA    -6.25mA    -8.31mA
3.6V      -12.83mA   -14.96mA   -13.4mA
3.7V      -12.96mA   -21.56mA   -13.45mA
4V        -21.57mA   -179.7mA   -13.84mA
4.2V      -46.21mA   -285.2mA   -16.96mA
4.5V      -83.17mA   -443.3mA   -54.33mA
6.6V      -341.9mA   -1.55A     -373.6mA
[Ramp]
| variable   typ   min   max
dV/dt_r   0.37/1.18n   0.36/1.31n   0.39/1.12n
dV/dt_f   0.47/1.55n   0.45/1.67n   0.48/1.46n
R_load = 50.00
[Rising Waveform]
R_fixture = 50.00
V_fixture = 0.000
V_fixture_min = 0.000
V_fixture_max = 0.000
| time   V(typ)   V(min)   V(max)
0s        14.46nV    17.85nV    29.68nV
1.6ns     -1.51mV    -1.99mV    -1.25mV
2.2ns     1.26mV     -2.16mV    49.67mV
2.6ns     29.59mV    -1.63mV    140mV
3.2ns     140mV      29.76mV    350mV
3.8ns     310mV      120mV      560mV
4.2ns     470mV      220mV      630mV
4.6ns     570mV      330mV      640mV
5.6ns     610mV      570mV      650mV
10ns      620mV      590mV      650mV
[Rising Waveform]
R_fixture = 50.00
V_fixture = 3.30
V_fixture_min = 3.00
V_fixture_max = 3.60
| time   V(typ)   V(min)   V(max)
0s        2.51V      2.25V      2.79V
600ps     2.51V      2.25V      2.84V
800ps     2.55V      2.25V      3.02V
1ns       2.7V       2.28V      3.17V
1.4ns     2.95V      2.47V      3.31V
1.8ns     3.06V      2.69V      3.46V
2.4ns     3.19V      2.82V      3.55V
3.2ns     3.27V      2.93V      3.58V
4.2ns     3.29V      2.98V      3.59V
10ns      3.3V       3V         3.6V
[Falling Waveform]
R_fixture = 50.00
V_fixture = 3.30
V_fixture_min = 3.00
V_fixture_max = 3.60
| time   V(typ)   V(min)   V(max)
0s        3.3V       3V         3.6V
1.8ns     3.31V      3V         3.6V
2.2ns     3.3V       3.01V      3.56V
3.2ns     3.17V      2.98V      3.27V
4ns       2.95V      2.85V      3V
4.6ns     2.74V      2.68V      2.84V
5.4ns     2.56V      2.46V      2.81V
5.6ns     2.54V      2.39V      2.8V
6.4ns     2.52V      2.29V      2.8V
10ns      2.51V      2.25V      2.79V
[Falling Waveform]
R_fixture = 50.00
V_fixture = 0.000
V_fixture_min = 0.000
V_fixture_max = 0.000
| time   V(typ)   V(min)   V(max)
0s        620mV      590mV      650mV
800ps     610mV      590mV      610mV
1ns       590mV      590mV      470mV
1.2ns     520mV      580mV      320mV
1.6ns     330mV      510mV      150mV
2ns       160mV      370mV      73.4mV
2.4ns     76.52mV    220mV      35.67mV
3ns       26.96mV    74.35mV    13.09mV
3.8ns     11.8mV     23.78mV    6.93mV
10ns      1.34mV     1.67mV     1.15mV
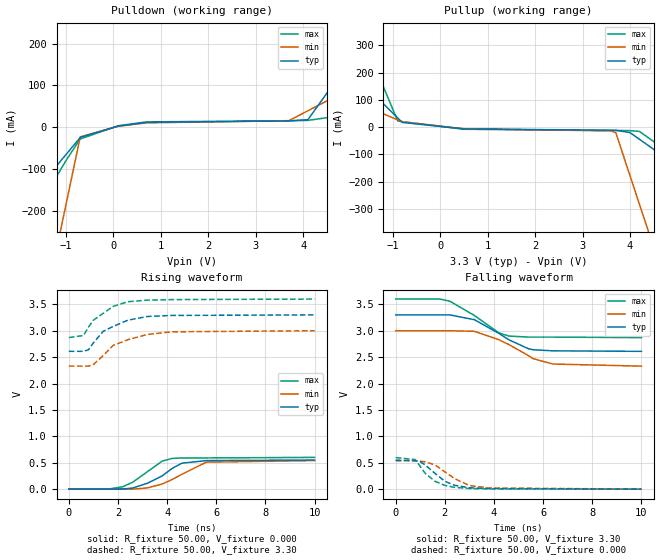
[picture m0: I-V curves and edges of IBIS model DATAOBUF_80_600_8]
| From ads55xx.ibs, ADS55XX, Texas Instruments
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|   Model DATAOBUF_80_600_8
[Model]   DATAOBUF_80_600_8
Model_type   Output
Polarity   Non-Inverting
Vmeas =   1.65V
C_comp   3.00pF   3.00pF   3.00pF
[Temperature Range]   50.00   0.10k   -20.00
[Voltage Range]   3.30V   3.00V   3.60V
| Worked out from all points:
|   slope of the pulldown table from 0 to 0.495 V, typ, clamps not added: 52.1 ohm
|   slope of the pullup table from 0 to 0.495 V, typ, clamps not added: 72.7 ohm
|   rising waveform, R_fixture 50.00, V_fixture 0.000: 20-80 % time 1.14ns typ, 1.34ns min, 1.08ns max; typ from 0 V to 0.55 V
|   rising waveform, R_fixture 50.00, V_fixture 3.30: 20-80 % time 1.24ns typ, 1.41ns min, 1.05ns max; typ from 2.61 V to 3.3 V
|   falling waveform, R_fixture 50.00, V_fixture 3.30: 20-80 % time 1.54ns typ, 1.58ns min, 1.37ns max; typ from 3.3 V to 2.61 V
|   falling waveform, R_fixture 50.00, V_fixture 0.000: 20-80 % time 899ps typ, 1.05ns min, 794ps max; typ from 0.55 V to 0.001 V
[Pulldown]
| voltage   I(typ)   I(min)   I(max)
-3.3V     -379.3mA   -1.429A    -523.1mA
-2.3V     -242.9mA   -888mA     -330.4mA
-1.9V     -188.3mA   -671.8mA   -253.3mA
-1.5V     -133.8mA   -455.6mA   -176.2mA
-1V       -65.59mA   -185.4mA   -79.89mA
-700mV    -24.67mA   -23.22mA   -28.3mA
100mV     2.59mA     2.14mA     3.34mA
700mV     11.43mA    10.3mA     12.65mA
3.7V      15.02mA    15.51mA    15.16mA
4.1V      17.88mA    39.23mA    16.21mA
5.5V      240.1mA    122.2mA    38.77mA
6.6V      414.6mA    187.5mA    57.52mA
[Pullup]
| voltage   I(typ)   I(min)   I(max)
-3.3V     445.1mA    200.5mA    1.024A
-3.1V     410.9mA    186.1mA    941mA
-1.9V     205.4mA    99.32mA    440.3mA
-900mV    34.24mA    27.02mA    23.14mA
-800mV    17.12mA    19.79mA    20.02mA
500mV     -6.52mA    -5.91mA    -7.83mA
3.6V      -11.39mA   -13.81mA   -12.29mA
3.7V      -11.52mA   -20.4mA    -12.34mA
4V        -20.11mA   -178.6mA   -12.73mA
4.2V      -44.75mA   -284mA     -15.85mA
4.5V      -81.71mA   -442.2mA   -53.21mA
6.6V      -340.4mA   -1.549A    -372.5mA
[Ramp]
| variable   typ   min   max
dV/dt_r   0.33/1.20n   0.32/1.33n   0.36/1.09n
dV/dt_f   0.41/1.56n   0.40/1.67n   0.44/1.37n
R_load = 50.00
[Rising Waveform]
R_fixture = 50.00
V_fixture = 0.000
V_fixture_min = 0.000
V_fixture_max = 0.000
| time   V(typ)   V(min)   V(max)
0s        14.99nV    18.38nV    30.67nV
1.6ns     -1.3mV     -1.82mV    -1.37mV
2.2ns     -150uV     -1.95mV    45.04mV
2.6ns     20.44mV    -1.91mV    130mV
3.2ns     110mV      22.1mV     330mV
3.8ns     250mV      96.1mV     530mV
4.2ns     390mV      180mV      580mV
4.6ns     490mV      280mV      590mV
5.6ns     540mV      510mV      590mV
10ns      550mV      540mV      600mV
[Rising Waveform]
R_fixture = 50.00
V_fixture = 3.30
V_fixture_min = 3.00
V_fixture_max = 3.60
| time   V(typ)   V(min)   V(max)
0s        2.61V      2.33V      2.87V
600ps     2.61V      2.33V      2.91V
800ps     2.64V      2.33V      3.07V
1ns       2.77V      2.36V      3.2V
1.4ns     2.99V      2.53V      3.33V
1.8ns     3.08V      2.72V      3.46V
2.4ns     3.2V       2.83V      3.55V
3.2ns     3.27V      2.93V      3.58V
4.2ns     3.29V      2.98V      3.59V
10ns      3.3V       3V         3.6V
[Falling Waveform]
R_fixture = 50.00
V_fixture = 3.30
V_fixture_min = 3.00
V_fixture_max = 3.60
| time   V(typ)   V(min)   V(max)
0s        3.3V       3V         3.6V
1.8ns     3.3V       3V         3.6V
2.2ns     3.3V       3V         3.56V
3.2ns     3.21V      2.99V      3.29V
4.2ns     2.95V      2.83V      2.96V
4.6ns     2.83V      2.74V      2.9V
5.4ns     2.66V      2.53V      2.88V
5.6ns     2.64V      2.47V      2.88V
6.4ns     2.62V      2.37V      2.88V
10ns      2.61V      2.33V      2.87V
[Falling Waveform]
R_fixture = 50.00
V_fixture = 0.000
V_fixture_min = 0.000
V_fixture_max = 0.000
| time   V(typ)   V(min)   V(max)
0s        550mV      540mV      600mV
800ps     540mV      540mV      560mV
1ns       520mV      530mV      430mV
1.2ns     460mV      520mV      300mV
1.6ns     300mV      460mV      150mV
2ns       150mV      330mV      71.89mV
2.4ns     73.85mV    200mV      35.33mV
3ns       28.13mV    69.38mV    13.09mV
3.8ns     12.32mV    23.99mV    6.94mV
10ns      1.39mV     1.72mV     1.18mV
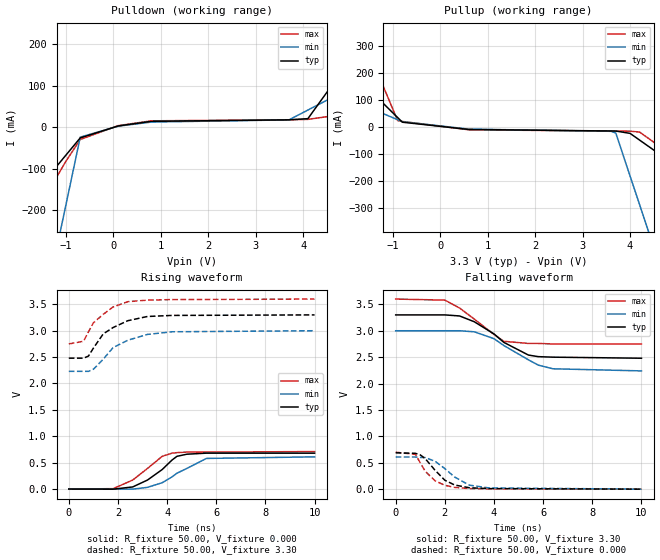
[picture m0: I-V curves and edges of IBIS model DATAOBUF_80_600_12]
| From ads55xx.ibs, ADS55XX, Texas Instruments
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|   Model DATAOBUF_80_600_12
[Model]   DATAOBUF_80_600_12
Model_type   Output
Polarity   Non-Inverting
Vmeas =   1.65V
C_comp   3.00pF   3.00pF   3.00pF
[Temperature Range]   50.00   0.10k   -20.00
[Voltage Range]   3.30V   3.00V   3.60V
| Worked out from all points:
|   slope of the pulldown table from 0 to 0.495 V, typ, clamps not added: 46.2 ohm
|   slope of the pullup table from 0 to 0.495 V, typ, clamps not added: 64 ohm
|   rising waveform, R_fixture 50.00, V_fixture 0.000: 20-80 % time 1.16ns typ, 1.3ns min, 1.14ns max; typ from 0 V to 0.68 V
|   rising waveform, R_fixture 50.00, V_fixture 3.30: 20-80 % time 1.16ns typ, 1.33ns min, 1ns max; typ from 2.48 V to 3.3 V
|   falling waveform, R_fixture 50.00, V_fixture 3.30: 20-80 % time 1.62ns typ, 1.59ns min, 1.42ns max; typ from 3.3 V to 2.48 V
|   falling waveform, R_fixture 50.00, V_fixture 0.000: 20-80 % time 841ps typ, 1.04ns min, 752ps max; typ from 0.69 V to 0.001 V
[Pulldown]
| voltage   I(typ)   I(min)   I(max)
-3.3V     -384mA     -1.432A    -529.7mA
-2.3V     -246.3mA   -890.5mA   -335mA
-1.9V     -191.2mA   -673.9mA   -257.1mA
-1.5V     -136.1mA   -457.3mA   -179.2mA
-1V       -67.25mA   -186.5mA   -81.9mA
-700mV    -25.94mA   -24.08mA   -29.75mA
100mV     2.84mA     2.3mA      3.64mA
800mV     13.95mA    12.26mA    15.22mA
3.7V      17.62mA    17.51mA    17.67mA
4.1V      20.48mA    41.23mA    18.74mA
5.5V      242.7mA    124.2mA    41.43mA
6.6V      417.2mA    189.5mA    60.3mA
[Pullup]
| voltage   I(typ)   I(min)   I(max)
-3.3V     449mA      202.6mA    1.028A
-3.1V     414.5mA    188mA      944mA
-1.9V     207.7mA    100.5mA    442.3mA
-900mV    35.44mA    27.63mA    24.19mA
-800mV    18.21mA    20.34mA    20.98mA
600mV     -8.58mA    -7.36mA    -9.81mA
3.6V      -14.23mA   -15.38mA   -14.46mA
3.7V      -14.37mA   -21.97mA   -14.52mA
4V        -22.98mA   -180.2mA   -14.92mA
4.2V      -47.64mA   -285.6mA   -18.04mA
4.5V      -84.63mA   -443.8mA   -55.42mA
6.6V      -343.6mA   -1.551A    -374.7mA
[Ramp]
| variable   typ   min   max
dV/dt_r   0.41/1.17n   0.37/1.32n   0.42/1.11n
dV/dt_f   0.49/1.59n   0.46/1.69n   0.51/1.41n
R_load = 50.00
[Rising Waveform]
R_fixture = 50.00
V_fixture = 0.000
V_fixture_min = 0.000
V_fixture_max = 0.000
| time   V(typ)   V(min)   V(max)
0s        14.35nV    17.76nV    29.23nV
1.8ns     -2.43mV    -1.51mV    7.03mV
2.6ns     39.84mV    -1.55mV    170mV
3.2ns     170mV      31.4mV     390mV
3.8ns     370mV      120mV      620mV
4.2ns     550mV      230mV      680mV
4.4ns     620mV      300mV      690mV
4.8ns     660mV      390mV      700mV
5.6ns     680mV      580mV      700mV
10ns      680mV      610mV      710mV
[Rising Waveform]
R_fixture = 50.00
V_fixture = 3.30
V_fixture_min = 3.00
V_fixture_max = 3.60
| time   V(typ)   V(min)   V(max)
0s        2.48V      2.23V      2.75V
600ps     2.48V      2.23V      2.8V
800ps     2.52V      2.23V      2.98V
1ns       2.67V      2.27V      3.15V
1.4ns     2.94V      2.46V      3.31V
1.8ns     3.06V      2.68V      3.45V
2.4ns     3.19V      2.82V      3.55V
3.2ns     3.27V      2.93V      3.58V
4.2ns     3.29V      2.98V      3.59V
10ns      3.3V       3V         3.6V
[Falling Waveform]
R_fixture = 50.00
V_fixture = 3.30
V_fixture_min = 3.00
V_fixture_max = 3.60
| time   V(typ)   V(min)   V(max)
0s        3.3V       3V         3.6V
2ns       3.3V       3V         3.58V
2.6ns     3.28V      3V         3.43V
3.2ns     3.17V      2.98V      3.22V
4ns       2.94V      2.85V      2.93V
4.4ns     2.78V      2.72V      2.8V
5.4ns     2.54V      2.45V      2.76V
5.8ns     2.51V      2.35V      2.76V
6.4ns     2.5V       2.28V      2.75V
10ns      2.48V      2.24V      2.75V
[Falling Waveform]
R_fixture = 50.00
V_fixture = 0.000
V_fixture_min = 0.000
V_fixture_max = 0.000
| time   V(typ)   V(min)   V(max)
0s        690mV      610mV      700mV
800ps     680mV      610mV      660mV
1ns       650mV      600mV      500mV
1.2ns     580mV      600mV      340mV
1.6ns     360mV      530mV      160mV
2ns       170mV      390mV      74.3mV
2.4ns     79.73mV    230mV      34mV
3ns       27.58mV    76.7mV     12.42mV
3.8ns     11.96mV    24.08mV    6.67mV
10ns      1.33mV     1.67mV     1.14mV
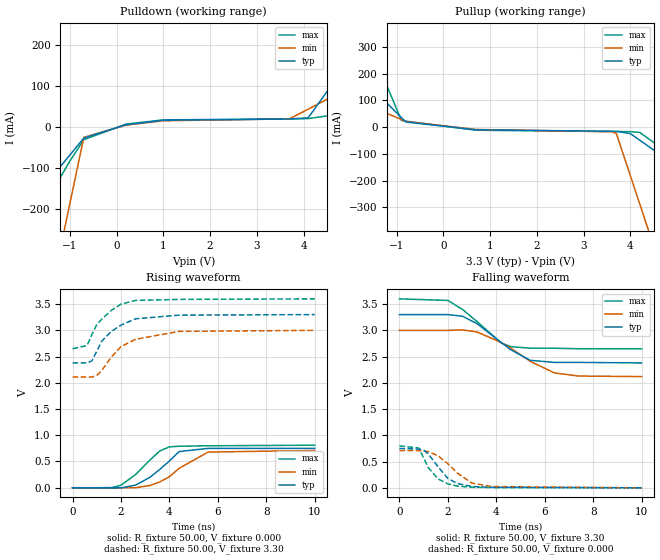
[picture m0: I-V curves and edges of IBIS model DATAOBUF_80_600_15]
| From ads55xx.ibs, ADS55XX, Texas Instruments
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|   Model DATAOBUF_80_600_15
[Model]   DATAOBUF_80_600_15
Model_type   Output
Polarity   Non-Inverting
Vmeas =   1.65V
C_comp   3.00pF   3.00pF   3.00pF
[Temperature Range]   50.00   0.10k   -20.00
[Voltage Range]   3.30V   3.00V   3.60V
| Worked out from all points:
|   slope of the pulldown table from 0 to 0.495 V, typ, clamps not added: 42.6 ohm
|   slope of the pullup table from 0 to 0.495 V, typ, clamps not added: 60.6 ohm
|   rising waveform, R_fixture 50.00, V_fixture 0.000: 20-80 % time 1.18ns typ, 1.33ns min, 1.07ns max; typ from 0 V to 0.75 V
|   rising waveform, R_fixture 50.00, V_fixture 3.30: 20-80 % time 1.1ns typ, 1.25ns min, 962ps max; typ from 2.38 V to 3.3 V
|   falling waveform, R_fixture 50.00, V_fixture 3.30: 20-80 % time 1.57ns typ, 1.8ns min, 1.45ns max; typ from 3.3 V to 2.38 V
|   falling waveform, R_fixture 50.00, V_fixture 0.000: 20-80 % time 817ps typ, 1.02ns min, 704ps max; typ from 0.75 V to 0.001 V
[Pulldown]
| voltage   I(typ)   I(min)   I(max)
-3.3V     -387.8mA   -1.436A    -534.4mA
-2.3V     -249mA     -893.2mA   -338.3mA
-1.9V     -193.4mA   -676.2mA   -259.9mA
-1.5V     -137.9mA   -459.2mA   -181.4mA
-1V       -68.52mA   -187.8mA   -83.37mA
-700mV    -26.88mA   -25.07mA   -30.82mA
200mV     5.66mA     4.71mA     7.1mA
1V        16.72mA    15.33mA    17.59mA
3.7V      19.73mA    20.04mA    19.69mA
4.1V      22.59mA    43.8mA     20.76mA
5.5V      244.8mA    127mA      43.46mA
6.6V      419.3mA    192.3mA    62.33mA
[Pullup]
| voltage   I(typ)   I(min)   I(max)
-3.3V     451mA      205mA      1.03A
-3.1V     416.4mA    190.3mA    946.5mA
-1.9V     208.9mA    102mA      443.9mA
-900mV    36mA       28.37mA    25.13mA
-800mV    18.71mA    21.01mA    21.83mA
700mV     -10.18mA   -9.03mA    -11.84mA
3.6V      -15.69mA   -17.44mA   -16.6mA
3.7V      -15.83mA   -24.03mA   -16.66mA
4V        -24.46mA   -182.2mA   -17.08mA
4.2V      -49.12mA   -287.7mA   -20.21mA
4.5V      -86.11mA   -446mA     -57.6mA
6.6V      -345mA     -1.553A    -377mA
[Ramp]
| variable   typ   min   max
dV/dt_r   0.45/1.17n   0.42/1.31n   0.48/1.06n
dV/dt_f   0.55/1.57n   0.53/1.83n   0.57/1.44n
R_load = 50.00
[Rising Waveform]
R_fixture = 50.00
V_fixture = 0.000
V_fixture_min = 0.000
V_fixture_max = 0.000
| time   V(typ)   V(min)   V(max)
0s        13.89nV    17.11nV    28.37nV
1.6ns     -1.82mV    -2.3mV     930uV
2ns       -1.61mV    -1.72mV    47.59mV
2.6ns     49.33mV    -840uV     250mV
3.2ns     200mV      43.63mV    530mV
3.6ns     350mV      110mV      700mV
4ns       510mV      210mV      780mV
4.4ns     690mV      370mV      790mV
5.6ns     750mV      680mV      800mV
10ns      750mV      710mV      810mV
[Rising Waveform]
R_fixture = 50.00
V_fixture = 3.30
V_fixture_min = 3.00
V_fixture_max = 3.60
| time   V(typ)   V(min)   V(max)
0s        2.38V      2.11V      2.65V
600ps     2.38V      2.11V      2.71V
800ps     2.42V      2.11V      2.92V
1ns       2.6V       2.14V      3.11V
1.2ns     2.79V      2.23V      3.21V
1.6ns     2.98V      2.49V      3.38V
2ns       3.1V       2.69V      3.5V
2.6ns     3.22V      2.83V      3.57V
4.4ns     3.29V      2.98V      3.59V
10ns      3.3V       3V         3.6V
[Falling Waveform]
R_fixture = 50.00
V_fixture = 3.30
V_fixture_min = 3.00
V_fixture_max = 3.60
| time   V(typ)   V(min)   V(max)
0s        3.3V       3V         3.6V
2ns       3.3V       3V         3.57V
2.6ns     3.27V      3.01V      3.4V
3.2ns     3.13V      2.97V      3.17V
4.2ns     2.77V      2.77V      2.76V
4.6ns     2.63V      2.66V      2.69V
5.4ns     2.43V      2.41V      2.66V
6.4ns     2.39V      2.19V      2.66V
7.4ns     2.39V      2.13V      2.65V
10ns      2.38V      2.12V      2.65V
[Falling Waveform]
R_fixture = 50.00
V_fixture = 0.000
V_fixture_min = 0.000
V_fixture_max = 0.000
| time   V(typ)   V(min)   V(max)
0s        750mV      710mV      800mV
800ps     740mV      710mV      760mV
1ns       720mV      700mV      570mV
1.2ns     640mV      690mV      380mV
1.6ns     400mV      610mV      170mV
2ns       180mV      460mV      76.41mV
2.4ns     82.57mV    280mV      33.3mV
3ns       26.14mV    90.23mV    12.11mV
3.8ns     11.42mV    25.51mV    6.53mV
10ns      1.28mV     1.62mV     1.11mV
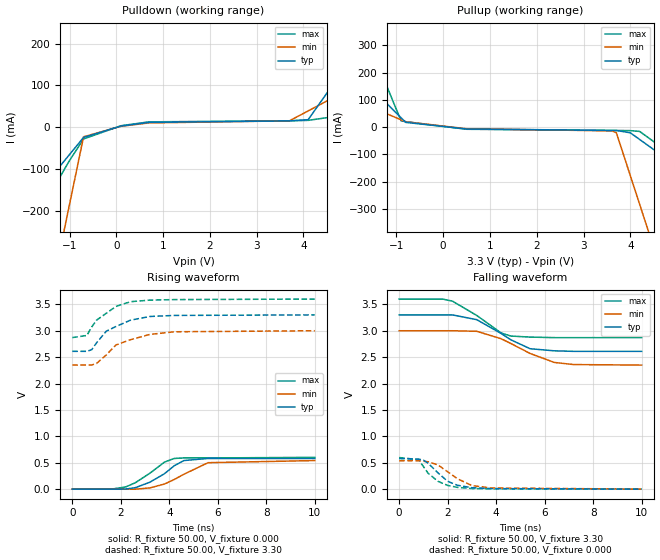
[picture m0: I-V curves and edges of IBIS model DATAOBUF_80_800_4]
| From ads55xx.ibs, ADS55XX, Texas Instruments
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|   Model DATAOBUF_80_800_4
[Model]   DATAOBUF_80_800_4
Model_type   Output
Polarity   Non-Inverting
Vmeas =   1.65V
C_comp   3.00pF   3.00pF   3.00pF
[Temperature Range]   50.00   0.10k   -20.00
[Voltage Range]   3.30V   3.00V   3.60V
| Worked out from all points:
|   slope of the pulldown table from 0 to 0.495 V, typ, clamps not added: 52.1 ohm
|   slope of the pullup table from 0 to 0.495 V, typ, clamps not added: 70.3 ohm
|   rising waveform, R_fixture 50.00, V_fixture 0.000: 20-80 % time 1.15ns typ, 1.33ns min, 1.11ns max; typ from 0 V to 0.58 V
|   rising waveform, R_fixture 50.00, V_fixture 3.30: 20-80 % time 1.24ns typ, 1.42ns min, 1.05ns max; typ from 2.61 V to 3.3 V
|   falling waveform, R_fixture 50.00, V_fixture 3.30: 20-80 % time 1.54ns typ, 1.7ns min, 1.37ns max; typ from 3.3 V to 2.61 V
|   falling waveform, R_fixture 50.00, V_fixture 0.000: 20-80 % time 867ps typ, 1.05ns min, 794ps max; typ from 0.58 V to 0.001 V
[Pulldown]
| voltage   I(typ)   I(min)   I(max)
-3.3V     -379.3mA   -1.428A    -523.4mA
-2.3V     -242.9mA   -887.5mA   -330.6mA
-1.9V     -188.3mA   -671.4mA   -253.4mA
-1.5V     -133.8mA   -455.3mA   -176.3mA
-1V       -65.59mA   -185.1mA   -79.92mA
-700mV    -24.67mA   -23.05mA   -28.31mA
100mV     2.59mA     2.11mA     3.35mA
700mV     11.43mA    10.09mA    12.67mA
3.7V      15.02mA    15.13mA    15.17mA
4.1V      17.87mA    38.85mA    16.23mA
5.5V      240mA      121.9mA    38.79mA
6.6V      414.6mA    187.1mA    57.55mA
[Pullup]
| voltage   I(typ)   I(min)   I(max)
-3.3V     446.1mA    200.3mA    1.024A
-3.1V     411.9mA    185.8mA    941mA
-1.9V     206.1mA    99.18mA    440.3mA
-900mV    34.55mA    26.98mA    23.14mA
-800mV    17.4mA     19.76mA    20.02mA
500mV     -6.76mA    -5.89mA    -7.82mA
3.6V      -12.08mA   -13.75mA   -12.29mA
3.7V      -12.21mA   -20.33mA   -12.34mA
4V        -20.8mA    -178.5mA   -12.72mA
4.2V      -45.44mA   -284mA     -15.84mA
4.5V      -82.4mA    -442.2mA   -53.2mA
6.6V      -341.1mA   -1.55A     -372.4mA
[Ramp]
| variable   typ   min   max
dV/dt_r   0.35/1.17n   0.32/1.34n   0.36/1.12n
dV/dt_f   0.41/1.56n   0.39/1.72n   0.44/1.37n
R_load = 50.00
[Rising Waveform]
R_fixture = 50.00
V_fixture = 0.000
V_fixture_min = 0.000
V_fixture_max = 0.000
| time   V(typ)   V(min)   V(max)
0s        15.02nV    18.52nV    30.63nV
1.6ns     -1.36mV    -1.78mV    -1.5mV
2.2ns     750uV      -1.92mV    39.69mV
2.6ns     26.36mV    -1.92mV    120mV
3.2ns     130mV      21.76mV    300mV
3.8ns     290mV      95.18mV    510mV
4.2ns     440mV      180mV      580mV
4.6ns     540mV      280mV      590mV
5.6ns     580mV      500mV      590mV
10ns      580mV      540mV      600mV
[Rising Waveform]
R_fixture = 50.00
V_fixture = 3.30
V_fixture_min = 3.00
V_fixture_max = 3.60
| time   V(typ)   V(min)   V(max)
0s        2.61V      2.35V      2.87V
600ps     2.61V      2.35V      2.91V
800ps     2.64V      2.35V      3.07V
1ns       2.77V      2.38V      3.2V
1.4ns     2.99V      2.54V      3.33V
1.8ns     3.08V      2.73V      3.46V
2.4ns     3.2V       2.83V      3.55V
3.2ns     3.27V      2.93V      3.58V
4.2ns     3.29V      2.98V      3.59V
10ns      3.3V       3V         3.6V
[Falling Waveform]
R_fixture = 50.00
V_fixture = 3.30
V_fixture_min = 3.00
V_fixture_max = 3.60
| time   V(typ)   V(min)   V(max)
0s        3.3V       3V         3.6V
1.8ns     3.3V       3V         3.6V
2.2ns     3.3V       3V         3.56V
3.2ns     3.21V      2.99V      3.29V
4.2ns     2.95V      2.85V      2.96V
4.6ns     2.83V      2.76V      2.9V
5.4ns     2.66V      2.57V      2.88V
6.4ns     2.62V      2.4V       2.87V
7.2ns     2.61V      2.36V      2.87V
10ns      2.61V      2.35V      2.87V
[Falling Waveform]
R_fixture = 50.00
V_fixture = 0.000
V_fixture_min = 0.000
V_fixture_max = 0.000
| time   V(typ)   V(min)   V(max)
0s        580mV      540mV      600mV
800ps     570mV      540mV      560mV
1ns       550mV      530mV      430mV
1.2ns     490mV      520mV      300mV
1.6ns     310mV      460mV      150mV
2ns       150mV      330mV      71.97mV
2.4ns     75.24mV    200mV      35.4mV
3ns       28.45mV    69.36mV    13.15mV
3.8ns     12.42mV    24.48mV    6.96mV
10ns      1.39mV     1.73mV     1.18mV
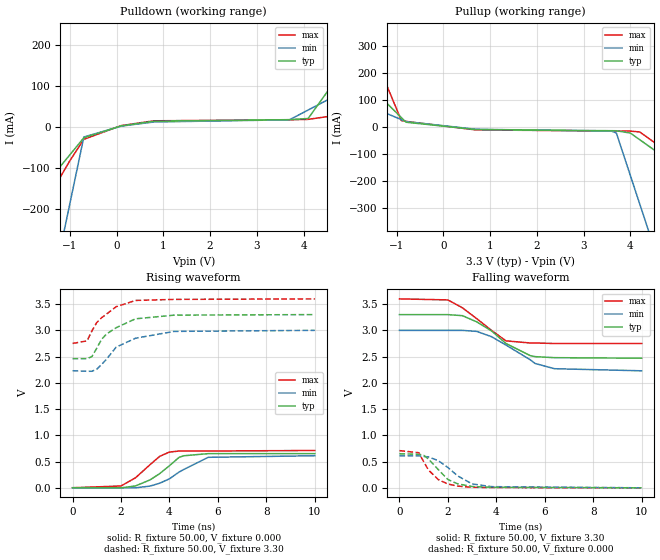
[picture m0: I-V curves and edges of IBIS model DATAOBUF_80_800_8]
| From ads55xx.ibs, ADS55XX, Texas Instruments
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|   Model DATAOBUF_80_800_8
[Model]   DATAOBUF_80_800_8
Model_type   Output
Polarity   Non-Inverting
Vmeas =   1.65V
C_comp   3.00pF   3.00pF   3.00pF
[Temperature Range]   50.00   0.10k   -20.00
[Voltage Range]   3.30V   3.00V   3.60V
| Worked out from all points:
|   slope of the pulldown table from 0 to 0.495 V, typ, clamps not added: 45.5 ohm
|   slope of the pullup table from 0 to 0.495 V, typ, clamps not added: 65.8 ohm
|   rising waveform, R_fixture 50.00, V_fixture 0.000: 20-80 % time 1.16ns typ, 1.3ns min, 1.08ns max; typ from 0 V to 0.65 V
|   rising waveform, R_fixture 50.00, V_fixture 3.30: 20-80 % time 1.15ns typ, 1.31ns min, 1.01ns max; typ from 2.46 V to 3.3 V
|   falling waveform, R_fixture 50.00, V_fixture 3.30: 20-80 % time 1.55ns typ, 1.59ns min, 1.42ns max; typ from 3.3 V to 2.47 V
|   falling waveform, R_fixture 50.00, V_fixture 0.000: 20-80 % time 850ps typ, 1.05ns min, 749ps max; typ from 0.65 V to 0.001 V
[Pulldown]
| voltage   I(typ)   I(min)   I(max)
-3.3V     -384.6mA   -1.432A    -529.7mA
-2.3V     -246.7mA   -890.5mA   -335mA
-1.9V     -191.6mA   -673.9mA   -257.1mA
-1.5V     -136.4mA   -457.4mA   -179.2mA
-1V       -67.48mA   -186.6mA   -81.89mA
-700mV    -26.11mA   -24.15mA   -29.74mA
100mV     2.87mA     2.31mA     3.64mA
800mV     14.2mA     12.37mA    15.2mA
3.7V      17.99mA    17.68mA    17.65mA
4.1V      20.85mA    41.4mA     18.72mA
5.5V      243mA      124.4mA    41.41mA
6.6V      417.6mA    189.7mA    60.28mA
[Pullup]
| voltage   I(typ)   I(min)   I(max)
-3.3V     448.2mA    202.6mA    1.028A
-3.1V     413.8mA    188mA      944mA
-1.9V     207.3mA    100.5mA    442.3mA
-900mV    35.17mA    27.61mA    24.22mA
-800mV    17.96mA    20.32mA    21mA
700mV     -9.24mA    -8.2mA     -10.66mA
3.6V      -13.54mA   -15.3mA    -14.52mA
3.7V      -13.68mA   -21.89mA   -14.58mA
4V        -22.29mA   -180.1mA   -14.98mA
4.2V      -46.93mA   -285.5mA   -18.1mA
4.5V      -83.89mA   -443.7mA   -55.48mA
6.6V      -342.6mA   -1.551A    -374.9mA
[Ramp]
| variable   typ   min   max
dV/dt_r   0.39/1.18n   0.36/1.31n   0.43/1.06n
dV/dt_f   0.50/1.56n   0.46/1.68n   0.51/1.41n
R_load = 50.00
[Rising Waveform]
R_fixture = 50.00
V_fixture = 0.000
V_fixture_min = 0.000
V_fixture_max = 0.000
| time   V(typ)   V(min)   V(max)
0s        14.24nV    17.71nV    29.29nV
2ns       -2.02mV    -1.45mV    33.66mV
2.6ns     34.54mV    -1.54mV    190mV
3.2ns     150mV      31.57mV    440mV
3.6ns     270mV      86.53mV    600mV
4ns       420mV      170mV      680mV
4.4ns     580mV      300mV      700mV
4.6ns     610mV      350mV      700mV
5.6ns     650mV      580mV      700mV
10ns      650mV      610mV      710mV
[Rising Waveform]
R_fixture = 50.00
V_fixture = 3.30
V_fixture_min = 3.00
V_fixture_max = 3.60
| time   V(typ)   V(min)   V(max)
0s        2.46V      2.23V      2.75V
600ps     2.46V      2.22V      2.8V
800ps     2.5V       2.22V      2.99V
1ns       2.66V      2.26V      3.15V
1.2ns     2.83V      2.35V      3.24V
1.4ns     2.93V      2.45V      3.31V
1.8ns     3.05V      2.68V      3.45V
2.6ns     3.22V      2.85V      3.57V
4.2ns     3.29V      2.98V      3.59V
10ns      3.3V       3V         3.6V
[Falling Waveform]
R_fixture = 50.00
V_fixture = 3.30
V_fixture_min = 3.00
V_fixture_max = 3.60
| time   V(typ)   V(min)   V(max)
0s        3.3V       3V         3.6V
2ns       3.3V       3V         3.58V
2.6ns     3.28V      3V         3.43V
3.2ns     3.16V      2.98V      3.22V
3.8ns     2.99V      2.88V      3V
4.4ns     2.75V      2.72V      2.8V
5.4ns     2.52V      2.44V      2.76V
5.6ns     2.5V       2.37V      2.76V
6.4ns     2.48V      2.27V      2.75V
10ns      2.47V      2.23V      2.75V
[Falling Waveform]
R_fixture = 50.00
V_fixture = 0.000
V_fixture_min = 0.000
V_fixture_max = 0.000
| time   V(typ)   V(min)   V(max)
0s        650mV      610mV      710mV
800ps     640mV      610mV      670mV
1ns       620mV      600mV      500mV
1.2ns     550mV      590mV      340mV
1.6ns     350mV      520mV      160mV
2ns       160mV      390mV      74.17mV
2.4ns     77.91mV    230mV      33.97mV
3ns       26.62mV    76.01mV    12.4mV
3.8ns     11.64mV    23.84mV    6.67mV
10ns      1.32mV     1.66mV     1.14mV
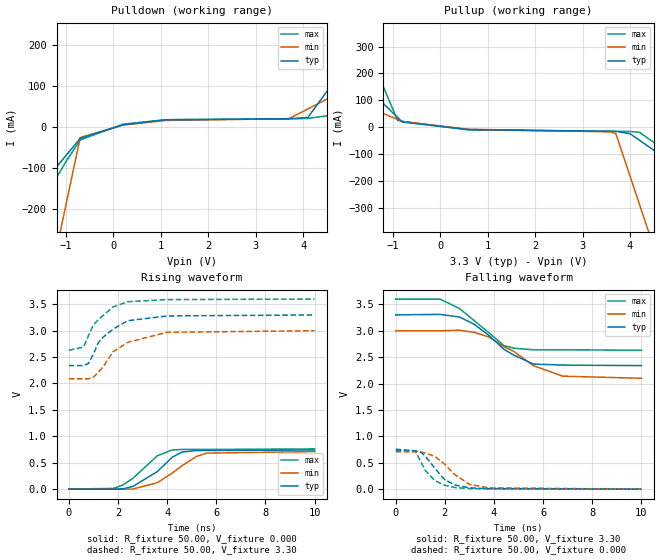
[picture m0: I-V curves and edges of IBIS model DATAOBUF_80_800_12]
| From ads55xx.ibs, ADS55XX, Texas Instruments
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|   Model DATAOBUF_80_800_12
[Model]   DATAOBUF_80_800_12
Model_type   Output
Polarity   Non-Inverting
Vmeas =   1.65V
C_comp   3.00pF   3.00pF   3.00pF
[Temperature Range]   50.00   0.10k   -20.00
[Voltage Range]   3.30V   3.00V   3.60V
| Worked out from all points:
|   slope of the pulldown table from 0 to 0.495 V, typ, clamps not added: 41.4 ohm
|   slope of the pullup table from 0 to 0.495 V, typ, clamps not added: 61.2 ohm
|   rising waveform, R_fixture 50.00, V_fixture 0.000: 20-80 % time 1.19ns typ, 1.28ns min, 1.09ns max; typ from 0 V to 0.74 V
|   rising waveform, R_fixture 50.00, V_fixture 3.30: 20-80 % time 1.09ns typ, 1.24ns min, 952ps max; typ from 2.34 V to 3.3 V
|   falling waveform, R_fixture 50.00, V_fixture 3.30: 20-80 % time 1.59ns typ, 1.87ns min, 1.49ns max; typ from 3.3 V to 2.34 V
|   falling waveform, R_fixture 50.00, V_fixture 0.000: 20-80 % time 828ps typ, 1.01ns min, 704ps max; typ from 0.74 V to 0.001 V
[Pulldown]
| voltage   I(typ)   I(min)   I(max)
-3.3V     -388.9mA   -1.437A    -535.1mA
-2.3V     -249.8mA   -893.7mA   -338.8mA
-1.9V     -194.2mA   -676.6mA   -260.3mA
-1.5V     -138.5mA   -459.5mA   -181.8mA
-1V       -68.97mA   -188.1mA   -83.63mA
-700mV    -27.24mA   -25.25mA   -31.02mA
200mV     5.8mA      4.78mA     7.18mA
1.1V      17.83mA    16.29mA    18.13mA
3.7V      20.57mA    20.52mA    20.07mA
4.1V      23.43mA    44.28mA    21.14mA
5.5V      245.6mA    127.4mA    43.9mA
6.6V      420.2mA    192.8mA    62.82mA
[Pullup]
| voltage   I(typ)   I(min)   I(max)
-3.3V     450.6mA    205mA      1.029A
-3.1V     416.1mA    190.3mA    945.4mA
-1.9V     208.7mA    102mA      443.2mA
-900mV    35.9mA     28.38mA    24.71mA
-800mV    18.62mA    21.02mA    21.46mA
600mV     -9.02mA    -8.04mA    -10.38mA
3.6V      -15.43mA   -17.48mA   -15.63mA
3.7V      -15.56mA   -24.08mA   -15.69mA
4V        -24.19mA   -182.3mA   -16.1mA
4.2V      -48.85mA   -287.8mA   -19.22mA
4.5V      -85.84mA   -446mA     -56.61mA
6.6V      -344.8mA   -1.554A    -376mA
[Ramp]
| variable   typ   min   max
dV/dt_r   0.44/1.17n   0.42/1.29n   0.46/1.09n
dV/dt_f   0.58/1.58n   0.54/1.88n   0.58/1.52n
R_load = 50.00
[Rising Waveform]
R_fixture = 50.00
V_fixture = 0.000
V_fixture_min = 0.000
V_fixture_max = 0.000
| time   V(typ)   V(min)   V(max)
0s        13.71nV    17nV       28.13nV
1.8ns     -2.6mV     -1.8mV     10.64mV
2.2ns     4.62mV     -2.57mV    76.74mV
2.6ns     46.74mV    -620uV     200mV
3.6ns     330mV      120mV      630mV
4.2ns     600mV      300mV      740mV
4.6ns     700mV      440mV      750mV
5.2ns     730mV      620mV      750mV
5.6ns     730mV      680mV      750mV
10ns      740mV      710mV      760mV
[Rising Waveform]
R_fixture = 50.00
V_fixture = 3.30
V_fixture_min = 3.00
V_fixture_max = 3.60
| time   V(typ)   V(min)   V(max)
0s        2.34V      2.09V      2.63V
600ps     2.34V      2.09V      2.69V
800ps     2.38V      2.09V      2.91V
1ns       2.56V      2.12V      3.11V
1.2ns     2.77V      2.21V      3.21V
1.4ns     2.88V      2.32V      3.29V
1.8ns     3.03V      2.6V       3.45V
2.4ns     3.19V      2.78V      3.55V
4ns       3.28V      2.97V      3.59V
10ns      3.3V       3V         3.6V
[Falling Waveform]
R_fixture = 50.00
V_fixture = 3.30
V_fixture_min = 3.00
V_fixture_max = 3.60
| time   V(typ)   V(min)   V(max)
0s        3.3V       3V         3.6V
1.8ns     3.31V      3V         3.6V
2.6ns     3.26V      3.01V      3.42V
3.2ns     3.12V      2.97V      3.19V
3.8ns     2.91V      2.88V      2.96V
4.4ns     2.65V      2.7V       2.72V
4.8ns     2.54V      2.61V      2.67V
5.6ns     2.37V      2.34V      2.64V
6.8ns     2.35V      2.14V      2.64V
10ns      2.34V      2.1V       2.63V
[Falling Waveform]
R_fixture = 50.00
V_fixture = 0.000
V_fixture_min = 0.000
V_fixture_max = 0.000
| time   V(typ)   V(min)   V(max)
0s        740mV      710mV      760mV
800ps     730mV      710mV      720mV
1ns       710mV      700mV      540mV
1.2ns     630mV      690mV      360mV
1.6ns     390mV      620mV      160mV
2ns       180mV      470mV      75.45mV
2.4ns     81.56mV    280mV      33.66mV
3ns       25.74mV    90.53mV    12.27mV
3.8ns     11.27mV    25.55mV    6.6mV
10ns      1.27mV     1.61mV     1.1mV
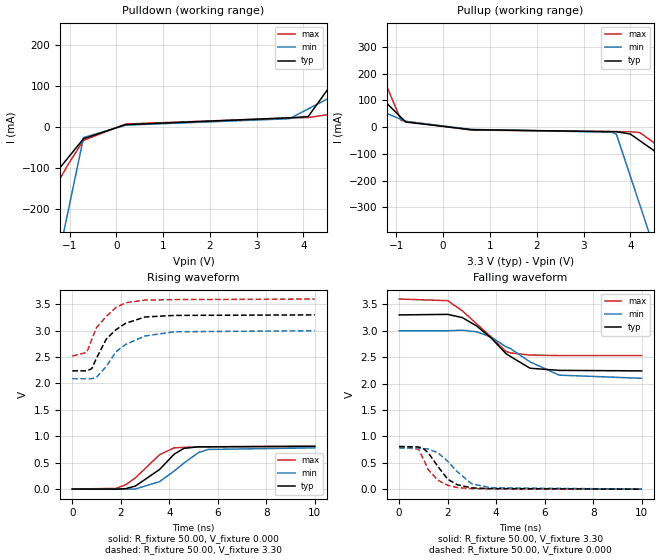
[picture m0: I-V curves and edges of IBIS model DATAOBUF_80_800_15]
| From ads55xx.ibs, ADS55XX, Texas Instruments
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|   Model DATAOBUF_80_800_15
[Model]   DATAOBUF_80_800_15
Model_type   Output
Polarity   Non-Inverting
Vmeas =   1.65V
C_comp   3.00pF   3.00pF   3.00pF
[Temperature Range]   50.00   0.10k   -20.00
[Voltage Range]   3.30V   3.00V   3.60V
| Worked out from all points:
|   slope of the pulldown table from 0 to 0.495 V, typ, clamps not added: 38.8 ohm
|   slope of the pullup table from 0 to 0.495 V, typ, clamps not added: 58.2 ohm
|   rising waveform, R_fixture 50.00, V_fixture 0.000: 20-80 % time 1.2ns typ, 1.32ns min, 1.13ns max; typ from 0 V to 0.81 V
|   rising waveform, R_fixture 50.00, V_fixture 3.30: 20-80 % time 1.05ns typ, 1.24ns min, 918ps max; typ from 2.24 V to 3.3 V
|   falling waveform, R_fixture 50.00, V_fixture 3.30: 20-80 % time 1.59ns typ, 1.87ns min, 1.51ns max; typ from 3.3 V to 2.24 V
|   falling waveform, R_fixture 50.00, V_fixture 0.000: 20-80 % time 814ps typ, 1.02ns min, 704ps max; typ from 0.81 V to 0.001 V
[Pulldown]
| voltage   I(typ)   I(min)   I(max)
-3.3V     -392.4mA   -1.437A    -539.6mA
-2.3V     -252.3mA   -893.7mA   -342mA
-1.9V     -196.2mA   -676.6mA   -263mA
-1.7V     -168.2mA   -568mA     -223.4mA
-1.5V     -140.2mA   -459.5mA   -183.9mA
-1V       -70.12mA   -188.1mA   -85.12mA
-700mV    -28.09mA   -25.25mA   -32.12mA
200mV     6.12mA     4.78mA     7.62mA
3.7V      22.65mA    20.52mA    22.32mA
4.1V      25.52mA    44.28mA    23.4mA
5.5V      247.7mA    127.4mA    46.22mA
6.6V      422.3mA    192.8mA    65.19mA
[Pullup]
| voltage   I(typ)   I(min)   I(max)
-3.3V     452.1mA    207mA      1.03A
-3.1V     417.5mA    192.2mA    946.7mA
-1.9V     209.6mA    103.1mA    444mA
-900mV    36.44mA    28.92mA    25.13mA
-800mV    19.12mA    21.5mA     21.84mA
600mV     -9.53mA    -8.52mA    -10.83mA
3.6V      -16.93mA   -19.1mA    -16.61mA
3.7V      -17.07mA   -25.7mA    -16.67mA
4V        -25.71mA   -183.9mA   -17.09mA
4.2V      -50.37mA   -289.4mA   -20.22mA
4.5V      -87.36mA   -447.6mA   -57.61mA
6.6V      -346.3mA   -1.555A    -377mA
[Ramp]
| variable   typ   min   max
dV/dt_r   0.49/1.19n   0.47/1.31n   0.48/1.13n
dV/dt_f   0.64/1.60n   0.54/1.88n   0.64/1.54n
R_load = 50.00
[Rising Waveform]
R_fixture = 50.00
V_fixture = 0.000
V_fixture_min = 0.000
V_fixture_max = 0.000
| time   V(typ)   V(min)   V(max)
0s        13.35nV    17.03nV    27.24nV
1.8ns     -2.73mV    -1.8mV     11.4mV
2.2ns     6.53mV     -2.66mV    79.75mV
2.6ns     55.46mV    180uV      210mV
3.6ns     370mV      140mV      650mV
4.2ns     660mV      340mV      780mV
4.6ns     770mV      490mV      790mV
5.2ns     800mV      690mV      800mV
5.6ns     800mV      750mV      800mV
10ns      810mV      780mV      810mV
[Rising Waveform]
R_fixture = 50.00
V_fixture = 3.30
V_fixture_min = 3.00
V_fixture_max = 3.60
| time   V(typ)   V(min)   V(max)
0s        2.24V      2.09V      2.52V
600ps     2.24V      2.09V      2.59V
800ps     2.28V      2.09V      2.83V
1ns       2.48V      2.12V      3.06V
1.4ns     2.84V      2.32V      3.27V
1.8ns     3.02V      2.6V       3.44V
2.2ns     3.14V      2.74V      3.53V
3ns       3.26V      2.9V       3.58V
4.2ns     3.29V      2.98V      3.59V
10ns      3.3V       3V         3.6V
[Falling Waveform]
R_fixture = 50.00
V_fixture = 3.30
V_fixture_min = 3.00
V_fixture_max = 3.60
| time   V(typ)   V(min)   V(max)
0s        3.3V       3V         3.6V
2ns       3.31V      3V         3.57V
2.6ns     3.25V      3.01V      3.38V
3.2ns     3.09V      2.98V      3.13V
3.8ns     2.86V      2.88V      2.88V
4.4ns     2.57V      2.7V       2.61V
4.6ns     2.51V      2.66V      2.58V
5.4ns     2.29V      2.41V      2.54V
6.6ns     2.25V      2.16V      2.53V
10ns      2.24V      2.1V       2.53V
[Falling Waveform]
R_fixture = 50.00
V_fixture = 0.000
V_fixture_min = 0.000
V_fixture_max = 0.000
| time   V(typ)   V(min)   V(max)
0s        810mV      780mV      800mV
800ps     800mV      780mV      760mV
1ns       770mV      770mV      570mV
1.2ns     690mV      760mV      370mV
1.6ns     430mV      690mV      170mV
2ns       190mV      530mV      75.44mV
2.4ns     84.5mV     330mV      31.79mV
3ns       24.92mV    100mV      11.84mV
3.8ns     10.99mV    27.49mV    6.4mV
10ns      1.23mV     1.63mV     1.07mV
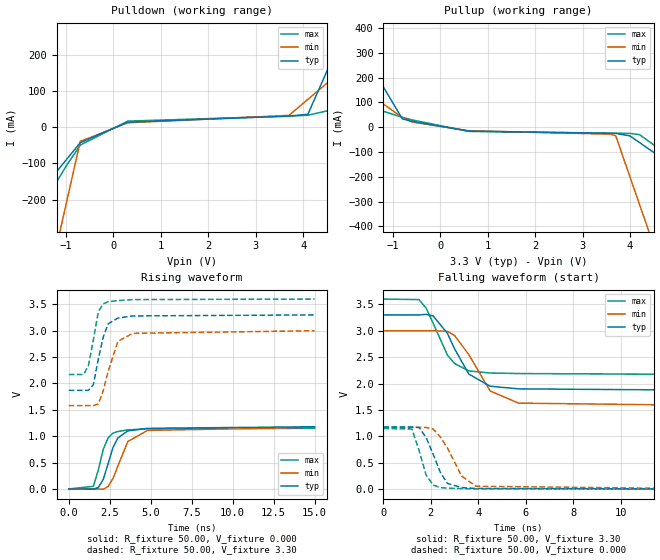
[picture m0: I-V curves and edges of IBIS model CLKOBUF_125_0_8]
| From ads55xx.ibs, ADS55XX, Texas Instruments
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|   Model CLKOBUF_125_0_8
[Model]   CLKOBUF_125_0_8
Model_type   Output
Polarity   Non-Inverting
Vmeas =   1.65V
C_comp   2pf   2pf   2pf
[Temperature Range]   50.00   0.10k   -20.00
[Voltage Range]   3.30V   3.00V   3.60V
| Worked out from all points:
|   slope of the pulldown table from 0 to 0.495 V, typ, clamps not added: 25 ohm
|   slope of the pullup table from 0 to 0.495 V, typ, clamps not added: 35.8 ohm
|   rising waveform, R_fixture 50.00, V_fixture 0.000: 20-80 % time 801ps typ, 956ps min, 658ps max; typ from 0 V to 1.18 V
|   rising waveform, R_fixture 50.00, V_fixture 3.30: 20-80 % time 651ps typ, 777ps min, 503ps max; typ from 1.87 V to 3.3 V
|   falling waveform, R_fixture 50.00, V_fixture 3.30: 20-80 % time 1.05ns typ, 1.13ns min, 937ps max; typ from 3.3 V to 1.87 V
|   falling waveform, R_fixture 50.00, V_fixture 0.000: 20-80 % time 685ps typ, 855ps min, 496ps max; typ from 1.18 V to 0.001 V
[Pulldown]
| voltage   I(typ)   I(min)   I(max)
-3.3V     -458.6mA   -1.546A    -604.6mA
-2.1V     -266.7mA   -850.4mA   -345.5mA
-1.7V     -202.7mA   -618.6mA   -259.2mA
-1.5V     -170.8mA   -502.8mA   -216mA
-1V       -90.8mA    -213.1mA   -108mA
-700mV    -42.83mA   -39.23mA   -49.46mA
300mV     13.85mA    11.98mA    16.55mA
3.7V      30.36mA    32.41mA    30.47mA
4.1V      35.54mA    76.65mA    32.71mA
4.9V      272.4mA    165.1mA    56.64mA
5.9V      568.5mA    275.7mA    89.54mA
6.6V      775.8mA    353.1mA    112.6mA
[Pullup]
| voltage   I(typ)   I(min)   I(max)
-3.3V     837.1mA    381.2mA    190.7mA
-2.3V     515.5mA    244.1mA    130.3mA
-2.1V     451.2mA    216.7mA    118.2mA
-800mV    33.13mA    38.44mA    39.72mA
-600mV    23.7mA     20.55mA    29.23mA
600mV     -15.89mA   -14.64mA   -17.2mA
3.6V      -25.01mA   -28.38mA   -24.35mA
3.7V      -25.24mA   -35.57mA   -24.45mA
4V        -35.48mA   -201.2mA   -25.34mA
4.2V      -62.1mA    -311.7mA   -30.29mA
4.5V      -102mA     -477.3mA   -71.61mA
6.6V      -381.5mA   -1.637A    -419.8mA
[Ramp]
| variable   typ   min   max
dV/dt_r   0.71/0.75n   0.70/0.92n   0.69/0.61n
dV/dt_f   0.86/1.02n   0.85/1.12n   0.86/0.89n
R_load = 50.00
[Rising Waveform]
R_fixture = 50.00
V_fixture = 0.000
V_fixture_min = 0.000
V_fixture_max = 0.000
| time   V(typ)   V(min)   V(max)
0s        28.17nV    36.21nV    55.96nV
1.5ns     -3.42mV    30.69uV    50.78mV
1.8ns     27.14mV    -2.41mV    360mV
2.1ns     180mV      -3.55mV    750mV
2.4ns     480mV      47.18mV    970mV
2.7ns     790mV      200mV      1.06V
3ns       970mV      440mV      1.09V
3.6ns     1.1V       900mV      1.12V
4.8ns     1.15V      1.11V      1.14V
15ns      1.18V      1.17V      1.15V
[Rising Waveform]
R_fixture = 50.00
V_fixture = 3.30
V_fixture_min = 3.00
V_fixture_max = 3.60
| time   V(typ)   V(min)   V(max)
0s        1.87V      1.58V      2.17V
900ps     1.87V      1.58V      2.17V
1.2ns     1.87V      1.58V      2.34V
1.5ns     1.98V      1.58V      2.83V
1.8ns     2.46V      1.61V      3.36V
2.1ns     2.88V      1.86V      3.51V
2.4ns     3.13V      2.23V      3.55V
3ns       3.24V      2.8V       3.57V
3.9ns     3.28V      2.95V      3.59V
15ns      3.3V       3V         3.6V
[Falling Waveform]
R_fixture = 50.00
V_fixture = 3.30
V_fixture_min = 3.00
V_fixture_max = 3.60
| time   V(typ)   V(min)   V(max)
0s        3.3V       3V         3.6V
1.5ns     3.3V       3V         3.59V
1.8ns     3.31V      3V         3.43V
2.1ns     3.28V      3V         3.14V
2.7ns     2.95V      2.99V      2.54V
3ns       2.66V      2.91V      2.38V
3.6ns     2.18V      2.55V      2.24V
4.5ns     1.95V      1.86V      2.2V
5.7ns     1.9V       1.63V      2.19V
15ns      1.87V      1.58V      2.17V
[Falling Waveform]
R_fixture = 50.00
V_fixture = 0.000
V_fixture_min = 0.000
V_fixture_max = 0.000
| time   V(typ)   V(min)   V(max)
0s        1.18V      1.17V      1.15V
1.2ns     1.18V      1.17V      1.14V
1.5ns     1.17V      1.17V      740mV
1.8ns     980mV      1.17V      270mV
2.1ns     660mV      1.14V      76.42mV
2.4ns     320mV      990mV      30.95mV
2.7ns     110mV      780mV      20.34mV
3.3ns     29.79mV    250mV      11.16mV
3.9ns     15.37mV    56.35mV    7.71mV
15ns      1.11mV     1.39mV     1.13mV
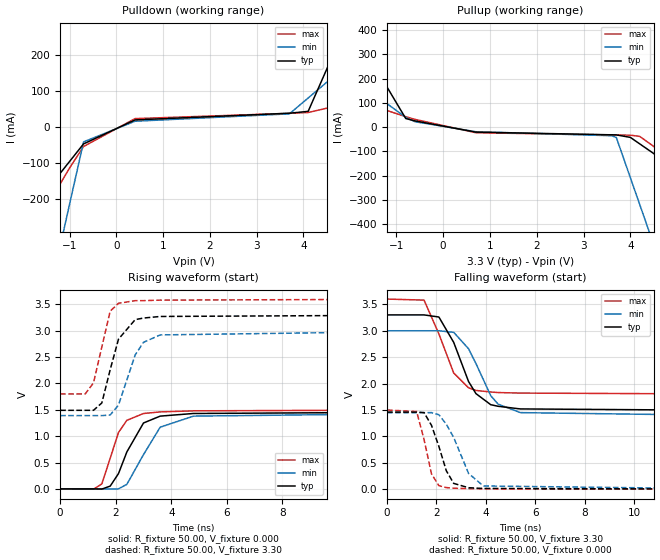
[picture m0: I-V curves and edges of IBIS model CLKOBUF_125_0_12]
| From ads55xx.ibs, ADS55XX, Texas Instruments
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|   Model CLKOBUF_125_0_12
[Model]   CLKOBUF_125_0_12
Model_type   Output
Polarity   Non-Inverting
Vmeas =   1.65V
C_comp   2pf   2pf   2pf
[Temperature Range]   50.00   0.10k   -20.00
[Voltage Range]   3.30V   3.00V   3.60V
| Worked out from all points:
|   slope of the pulldown table from 0 to 0.495 V, typ, clamps not added: 21.1 ohm
|   slope of the pullup table from 0 to 0.495 V, typ, clamps not added: 31.2 ohm
|   rising waveform, R_fixture 50.00, V_fixture 0.000: 20-80 % time 762ps typ, 902ps min, 642ps max; typ from 0 V to 1.46 V
|   rising waveform, R_fixture 50.00, V_fixture 3.30: 20-80 % time 599ps typ, 693ps min, 476ps max; typ from 1.49 V to 3.3 V
|   falling waveform, R_fixture 50.00, V_fixture 3.30: 20-80 % time 1ns typ, 1.04ns min, 892ps max; typ from 3.3 V to 1.49 V
|   falling waveform, R_fixture 50.00, V_fixture 0.000: 20-80 % time 640ps typ, 832ps min, 442ps max; typ from 1.46 V to 0.001 V
[Pulldown]
| voltage   I(typ)   I(min)   I(max)
-3.3V     -473.1mA   -1.553A    -624.1mA
-2.1V     -276.3mA   -855.2mA   -358.1mA
-1.7V     -210.7mA   -622.6mA   -269.4mA
-1.5V     -177.9mA   -506.3mA   -225.1mA
-1V       -95.92mA   -215.6mA   -114.2mA
-700mV    -46.72mA   -41.12mA   -53.97mA
400mV     20.15mA    16.46mA    23.74mA
3.7V      38.8mA     37.08mA    38.54mA
4.1V      43.99mA    81.28mA    40.81mA
4.9V      280.9mA    169.7mA    64.95mA
5.9V      577mA      280.2mA    98.15mA
6.6V      784.2mA    357.5mA    121.4mA
[Pullup]
| voltage   I(typ)   I(min)   I(max)
-3.3V     845.5mA    389.1mA    202mA
-2.3V     521.5mA    249.7mA    138.4mA
-2.1V     456.7mA    221.8mA    125.7mA
-800mV    35.52mA    40.63mA    43.03mA
-600mV    25.58mA    22.27mA    31.87mA
700mV     -20.53mA   -18.97mA   -23.09mA
3.6V      -31.69mA   -35.38mA   -32.13mA
3.7V      -31.93mA   -42.59mA   -32.25mA
4V        -42.22mA   -208.3mA   -33.19mA
4.2V      -68.88mA   -318.7mA   -38.17mA
4.5V      -108.9mA   -484.4mA   -79.53mA
6.6V      -388.8mA   -1.644A    -428.1mA
[Ramp]
| variable   typ   min   max
dV/dt_r   0.88/0.73n   0.87/0.89n   0.90/0.60n
dV/dt_f   1.08/0.97n   0.96/1.00n   1.08/0.87n
R_load = 50.00
[Rising Waveform]
R_fixture = 50.00
V_fixture = 0.000
V_fixture_min = 0.000
V_fixture_max = 0.000
| time   V(typ)   V(min)   V(max)
0s        25.96nV    34.92nV    51.42nV
1.2ns     -10.42uV   590nV      -5.28mV
1.5ns     -3.41mV    29.97uV    94.06mV
1.8ns     52.24mV    -2.17mV    580mV
2.1ns     290mV      720uV      1.07V
2.4ns     700mV      85.68mV    1.3V
3ns       1.25V      650mV      1.43V
3.6ns     1.38V      1.17V      1.46V
4.8ns     1.43V      1.38V      1.48V
15ns      1.46V      1.44V      1.5V
[Rising Waveform]
R_fixture = 50.00
V_fixture = 3.30
V_fixture_min = 3.00
V_fixture_max = 3.60
| time   V(typ)   V(min)   V(max)
0s        1.49V      1.39V      1.8V
900ps     1.49V      1.39V      1.8V
1.2ns     1.49V      1.39V      2.01V
1.5ns     1.63V      1.39V      2.69V
1.8ns     2.26V      1.4V       3.37V
2.1ns     2.84V      1.59V      3.52V
2.7ns     3.21V      2.54V      3.57V
3ns       3.24V      2.78V      3.57V
3.6ns     3.27V      2.92V      3.58V
15ns      3.3V       3V         3.6V
[Falling Waveform]
R_fixture = 50.00
V_fixture = 3.30
V_fixture_min = 3.00
V_fixture_max = 3.60
| time   V(typ)   V(min)   V(max)
0s        3.3V       3V         3.6V
1.5ns     3.3V       3V         3.58V
2.1ns     3.26V      3V         2.94V
2.7ns     2.78V      2.97V      2.2V
3.3ns     2.04V      2.66V      1.92V
3.6ns     1.81V      2.38V      1.87V
4.2ns     1.6V       1.77V      1.84V
4.5ns     1.57V      1.61V      1.83V
5.4ns     1.52V      1.45V      1.82V
15ns      1.49V      1.39V      1.8V
[Falling Waveform]
R_fixture = 50.00
V_fixture = 0.000
V_fixture_min = 0.000
V_fixture_max = 0.000
| time   V(typ)   V(min)   V(max)
0s        1.46V      1.45V      1.5V
1.2ns     1.46V      1.45V      1.47V
1.5ns     1.45V      1.45V      940mV
1.8ns     1.21V      1.45V      290mV
2.1ns     810mV      1.41V      67.16mV
2.4ns     350mV      1.23V      30.82mV
2.7ns     110mV      980mV      19.56mV
3.3ns     28.29mV    300mV      10.52mV
3.9ns     14.38mV    61.6mV     7.24mV
15ns      1.01mV     1.33mV     1.04mV
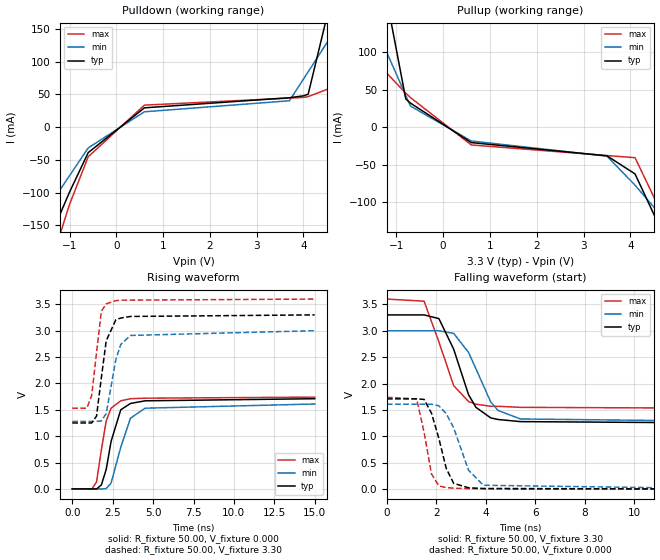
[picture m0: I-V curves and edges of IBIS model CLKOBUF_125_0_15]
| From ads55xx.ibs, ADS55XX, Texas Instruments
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|   Model CLKOBUF_125_0_15
[Model]   CLKOBUF_125_0_15
Model_type   Output
Polarity   Non-Inverting
Vmeas =   1.65V
C_comp   2pf   2pf   2pf
[Temperature Range]   50.00   0.10k   -20.00
[Voltage Range]   3.30V   3.00V   3.60V
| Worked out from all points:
|   slope of the pulldown table from 0 to 0.495 V, typ, clamps not added: 19.2 ohm
|   slope of the pullup table from 0 to 0.495 V, typ, clamps not added: 28.1 ohm
|   rising waveform, R_fixture 50.00, V_fixture 0.000: 20-80 % time 720ps typ, 895ps min, 620ps max; typ from 0 V to 1.71 V
|   rising waveform, R_fixture 50.00, V_fixture 3.30: 20-80 % time 562ps typ, 681ps min, 466ps max; typ from 1.25 V to 3.3 V
|   falling waveform, R_fixture 50.00, V_fixture 3.30: 20-80 % time 957ps typ, 1.04ns min, 877ps max; typ from 3.3 V to 1.25 V
|   falling waveform, R_fixture 50.00, V_fixture 0.000: 20-80 % time 606ps typ, 798ps min, 426ps max; typ from 1.71 V to 0.001 V
[Pulldown]
| voltage   I(typ)   I(min)   I(max)
-3.3V     -482.9mA   -318.5mA   -635.9mA
-1.9V     -249.4mA   -169.8mA   -320.7mA
-1.5V     -182.7mA   -127.3mA   -230.7mA
-1V       -99.26mA   -74.19mA   -118.1mA
-600mV    -38.89mA   -31.71mA   -45.19mA
600mV     29.47mA    23.45mA    33.61mA
3.7V      44.95mA    40.27mA    44.35mA
4V        47.79mA    73.45mA    45.37mA
4.1V      50.14mA    84.51mA    46.64mA
4.5V      168.6mA    128.8mA    57.53mA
4.9V      287mA      173mA      70.85mA
6.6V      790.4mA    361mA      127.5mA
[Pullup]
| voltage   I(typ)   I(min)   I(max)
-3.3V     852.8mA    394.9mA    209.2mA
-2.1V     461.5mA    225.6mA    130.4mA
-1.5V     265.8mA    140.9mA    91.08mA
-1V       102.8mA    70.39mA    58.28mA
-800mV    37.54mA    42.17mA    45.16mA
-700mV    31.96mA    28.06mA    39.34mA
600mV     -20.53mA   -18.38mA   -23.66mA
3.5V      -38.11mA   -38.58mA   -37.77mA
4.1V      -62.18mA   -77.18mA   -40.6mA
4.7V      -142.2mA   -120.6mA   -118.6mA
4.9V      -168.9mA   -135mA     -151.8mA
6.6V      -395.7mA   -257.9mA   -434.2mA
[Ramp]
| variable   typ   min   max
dV/dt_r   1.02/0.69n   0.96/0.84n   1.04/0.57n
dV/dt_f   1.23/0.91n   1.03/1.01n   1.24/0.86n
R_load = 50.00
[Rising Waveform]
R_fixture = 50.00
V_fixture = 0.000
V_fixture_min = 0.000
V_fixture_max = 0.000
| time   V(typ)   V(min)   V(max)
0s        24.81nV    34.21nV    49.05nV
1.2ns     -10.53uV   590nV      -5.65mV
1.5ns     -3.1mV     34.91uV    130mV
1.8ns     74.64mV    -2.18mV    740mV
2.1ns     370mV      5.64mV     1.29V
2.4ns     900mV      110mV      1.53V
3ns       1.5V       790mV      1.67V
3.6ns     1.62V      1.34V      1.71V
4.5ns     1.67V      1.53V      1.72V
15ns      1.71V      1.61V      1.74V
[Rising Waveform]
R_fixture = 50.00
V_fixture = 3.30
V_fixture_min = 3.00
V_fixture_max = 3.60
| time   V(typ)   V(min)   V(max)
0s        1.25V      1.28V      1.53V
900ps     1.25V      1.28V      1.53V
1.2ns     1.25V      1.28V      1.77V
1.5ns     1.38V      1.28V      2.58V
1.8ns     2.11V      1.29V      3.37V
2.1ns     2.81V      1.43V      3.51V
2.7ns     3.21V      2.46V      3.57V
3ns       3.24V      2.74V      3.58V
3.6ns     3.27V      2.91V      3.58V
15ns      3.3V       3V         3.6V
[Falling Waveform]
R_fixture = 50.00
V_fixture = 3.30
V_fixture_min = 3.00
V_fixture_max = 3.60
| time   V(typ)   V(min)   V(max)
0s        3.3V       3V         3.6V
1.5ns     3.3V       3V         3.56V
2.1ns     3.23V      3V         2.79V
2.7ns     2.65V      2.95V      1.96V
3.3ns     1.79V      2.59V      1.66V
3.6ns     1.55V      2.28V      1.61V
4.2ns     1.35V      1.65V      1.57V
4.5ns     1.32V      1.49V      1.57V
5.4ns     1.28V      1.33V      1.55V
15ns      1.25V      1.28V      1.53V
[Falling Waveform]
R_fixture = 50.00
V_fixture = 0.000
V_fixture_min = 0.000
V_fixture_max = 0.000
| time   V(typ)   V(min)   V(max)
0s        1.71V      1.61V      1.74V
1.2ns     1.71V      1.61V      1.71V
1.5ns     1.7V       1.61V      1.08V
1.8ns     1.44V      1.61V      290mV
2.1ns     960mV      1.58V      63.27mV
2.4ns     390mV      1.43V      30.47mV
2.7ns     110mV      1.16V      19.06mV
3.3ns     27.83mV    360mV      10.21mV
3.9ns     13.96mV    74.93mV    6.99mV
15ns      960uV      1.3mV      990uV
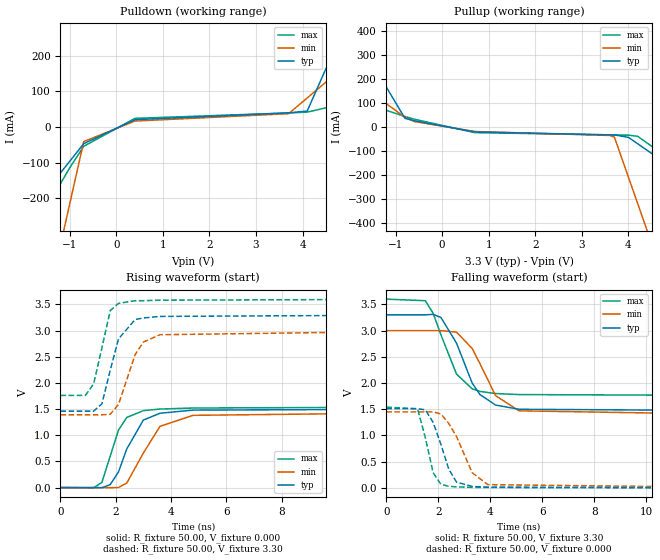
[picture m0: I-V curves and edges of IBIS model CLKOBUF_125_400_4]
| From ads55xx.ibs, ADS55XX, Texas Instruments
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|   Model CLKOBUF_125_400_4
[Model]   CLKOBUF_125_400_4
Model_type   Output
Polarity   Non-Inverting
Vmeas =   1.65V
C_comp   2pf   2pf   2pf
[Temperature Range]   50.00   0.10k   -20.00
[Voltage Range]   3.30V   3.00V   3.60V
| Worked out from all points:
|   slope of the pulldown table from 0 to 0.495 V, typ, clamps not added: 20.9 ohm
|   slope of the pullup table from 0 to 0.495 V, typ, clamps not added: 30.6 ohm
|   rising waveform, R_fixture 50.00, V_fixture 0.000: 20-80 % time 750ps typ, 901ps min, 640ps max; typ from 0 V to 1.5 V
|   rising waveform, R_fixture 50.00, V_fixture 3.30: 20-80 % time 588ps typ, 691ps min, 473ps max; typ from 1.46 V to 3.3 V
|   falling waveform, R_fixture 50.00, V_fixture 3.30: 20-80 % time 992ps typ, 1.02ns min, 895ps max; typ from 3.3 V to 1.47 V
|   falling waveform, R_fixture 50.00, V_fixture 0.000: 20-80 % time 639ps typ, 815ps min, 440ps max; typ from 1.51 V to 0.001 V
[Pulldown]
| voltage   I(typ)   I(min)   I(max)
-3.3V     -474.4mA   -1.553A    -625.6mA
-2.1V     -277.2mA   -855.3mA   -359.1mA
-1.7V     -211.4mA   -622.7mA   -270.2mA
-1.5V     -178.5mA   -506.4mA   -225.8mA
-1V       -96.31mA   -215.6mA   -114.8mA
-700mV    -46.99mA   -41.17mA   -54.37mA
400mV     20.36mA    16.49mA    24.07mA
3.7V      39.45mA    37.18mA    39.31mA
4.1V      44.65mA    81.42mA    41.59mA
4.9V      281.5mA    169.9mA    65.73mA
5.9V      577.6mA    280.5mA    98.93mA
6.6V      784.9mA    357.9mA    122.2mA
[Pullup]
| voltage   I(typ)   I(min)   I(max)
-3.3V     846.9mA    389.4mA    203.1mA
-2.3V     522.5mA    249.9mA    139.2mA
-2.1V     457.6mA    222mA      126.5mA
-800mV    35.88mA    40.64mA    43.39mA
-600mV    25.87mA    22.27mA    32.15mA
700mV     -20.99mA   -18.97mA   -23.59mA
3.6V      -32.81mA   -35.4mA    -33.05mA
3.7V      -33.06mA   -42.61mA   -33.16mA
4V        -43.35mA   -208.3mA   -34.11mA
4.2V      -70.01mA   -318.8mA   -39.09mA
4.5V      -110mA     -484.4mA   -80.46mA
6.6V      -389.9mA   -1.644A    -429.1mA
[Ramp]
| variable   typ   min   max
dV/dt_r   0.90/0.72n   0.87/0.89n   0.92/0.59n
dV/dt_f   1.10/0.96n   0.97/1.00n   1.10/0.87n
R_load = 50.00
[Rising Waveform]
R_fixture = 50.00
V_fixture = 0.000
V_fixture_min = 0.000
V_fixture_max = 0.000
| time   V(typ)   V(min)   V(max)
0s        25.84nV    34.9nV     51.08nV
1.2ns     -10.31uV   590nV      -5.34mV
1.5ns     -3.38mV    30.11uV    99.78mV
1.8ns     55.9mV     -2.18mV    600mV
2.1ns     300mV      960uV      1.1V
2.4ns     740mV      87.43mV    1.34V
3ns       1.29V      660mV      1.47V
3.6ns     1.42V      1.17V      1.5V
4.8ns     1.48V      1.38V      1.52V
15ns      1.5V       1.44V      1.54V
[Rising Waveform]
R_fixture = 50.00
V_fixture = 3.30
V_fixture_min = 3.00
V_fixture_max = 3.60
| time   V(typ)   V(min)   V(max)
0s        1.46V      1.39V      1.76V
900ps     1.46V      1.39V      1.76V
1.2ns     1.46V      1.39V      1.98V
1.5ns     1.6V       1.39V      2.67V
1.8ns     2.24V      1.4V       3.38V
2.1ns     2.84V      1.59V      3.52V
2.7ns     3.21V      2.54V      3.57V
3ns       3.24V      2.78V      3.57V
3.6ns     3.27V      2.92V      3.58V
15ns      3.3V       3V         3.6V
[Falling Waveform]
R_fixture = 50.00
V_fixture = 3.30
V_fixture_min = 3.00
V_fixture_max = 3.60
| time   V(typ)   V(min)   V(max)
0s        3.3V       3V         3.6V
1.5ns     3.3V       3V         3.57V
1.8ns     3.31V      3V         3.33V
2.1ns     3.25V      3V         2.92V
2.7ns     2.76V      2.97V      2.17V
3.3ns     2V         2.66V      1.89V
3.6ns     1.78V      2.37V      1.84V
4.2ns     1.58V      1.76V      1.8V
5.1ns     1.5V       1.47V      1.78V
15ns      1.47V      1.39V      1.76V
[Falling Waveform]
R_fixture = 50.00
V_fixture = 0.000
V_fixture_min = 0.000
V_fixture_max = 0.000
| time   V(typ)   V(min)   V(max)
0s        1.51V      1.45V      1.54V
1.2ns     1.51V      1.45V      1.51V
1.5ns     1.49V      1.45V      960mV
1.8ns     1.25V      1.45V      290mV
2.1ns     830mV      1.41V      67.26mV
2.4ns     360mV      1.23V      31.05mV
2.7ns     110mV      980mV      19.54mV
3.3ns     28.23mV    290mV      10.5mV
3.9ns     14.35mV    62.24mV    7.21mV
15ns      1.01mV     1.33mV     1.03mV
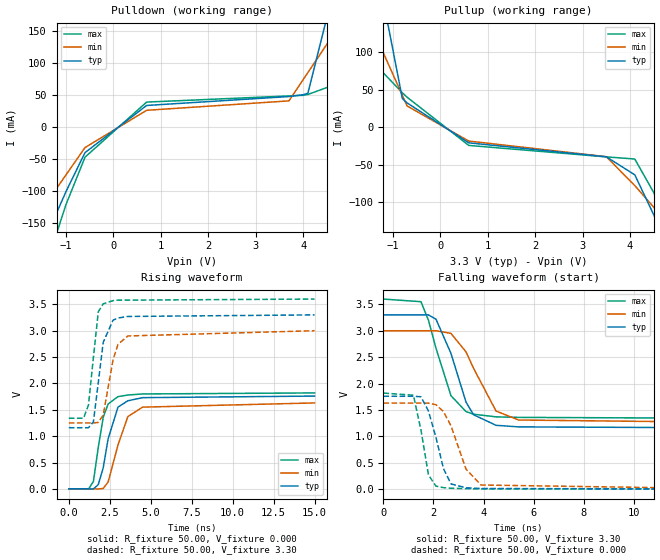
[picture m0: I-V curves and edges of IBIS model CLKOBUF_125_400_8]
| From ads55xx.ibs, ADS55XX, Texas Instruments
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|   Model CLKOBUF_125_400_8
[Model]   CLKOBUF_125_400_8
Model_type   Output
Polarity   Non-Inverting
Vmeas =   1.65V
C_comp   2pf   2pf   2pf
[Temperature Range]   50.00   0.10k   -20.00
[Voltage Range]   3.30V   3.00V   3.60V
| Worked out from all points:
|   slope of the pulldown table from 0 to 0.495 V, typ, clamps not added: 18.4 ohm
|   slope of the pullup table from 0 to 0.495 V, typ, clamps not added: 27.6 ohm
|   rising waveform, R_fixture 50.00, V_fixture 0.000: 20-80 % time 721ps typ, 886ps min, 612ps max; typ from 0 V to 1.76 V
|   rising waveform, R_fixture 50.00, V_fixture 3.30: 20-80 % time 556ps typ, 674ps min, 460ps max; typ from 1.16 V to 3.3 V
|   falling waveform, R_fixture 50.00, V_fixture 3.30: 20-80 % time 898ps typ, 1.06ns min, 853ps max; typ from 3.3 V to 1.16 V
|   falling waveform, R_fixture 50.00, V_fixture 0.000: 20-80 % time 595ps typ, 792ps min, 419ps max; typ from 1.76 V to 0.001 V
[Pulldown]
| voltage   I(typ)   I(min)   I(max)
-3.3V     -487.4mA   -319.5mA   -643.9mA
-1.9V     -252mA     -170.4mA   -325.5mA
-1.5V     -184.8mA   -127.8mA   -234.6mA
-1V       -100.7mA   -74.57mA   -120.9mA
-600mV    -39.85mA   -31.97mA   -46.98mA
700mV     33.89mA    26.33mA    39.16mA
3.7V      47.82mA    41.07mA    48.76mA
4V        50.66mA    74.25mA    49.78mA
4.1V      53.01mA    85.31mA    51.05mA
4.5V      171.4mA    129.6mA    61.95mA
4.9V      289.9mA    173.8mA    75.29mA
6.6V      793.3mA    361.8mA    132mA
[Pullup]
| voltage   I(typ)   I(min)   I(max)
-3.3V     854.5mA    395.9mA    211.6mA
-2.1V     462.6mA    226.2mA    132mA
-1.5V     266.6mA    141.4mA    92.24mA
-1V       103.3mA    70.68mA    59.09mA
-800mV    37.97mA    42.4mA     45.83mA
-700mV    32.34mA    28.26mA    39.95mA
600mV     -20.98mA   -18.61mA   -24.44mA
3.5V      -39.61mA   -39.47mA   -39.73mA
4.1V      -63.71mA   -78.08mA   -42.59mA
4.5V      -117.1mA   -107mA     -87.4mA
4.9V      -170.5mA   -135.9mA   -153.8mA
6.6V      -397.5mA   -258.8mA   -436.2mA
[Ramp]
| variable   typ   min   max
dV/dt_r   1.06/0.68n   0.98/0.83n   1.09/0.57n
dV/dt_f   1.28/0.86n   1.05/1.03n   1.36/0.85n
R_load = 50.00
[Rising Waveform]
R_fixture = 50.00
V_fixture = 0.000
V_fixture_min = 0.000
V_fixture_max = 0.000
| time   V(typ)   V(min)   V(max)
0s        24.34nV    34.08nV    47.53nV
1.2ns     -10.25uV   590nV      -5.75mV
1.5ns     -2.87mV    36.31uV    140mV
1.8ns     82.41mV    -2.21mV    790mV
2.1ns     400mV      7.4mV      1.36V
2.4ns     950mV      130mV      1.61V
3ns       1.55V      830mV      1.75V
3.6ns     1.67V      1.37V      1.78V
4.5ns     1.73V      1.55V      1.8V
15ns      1.76V      1.63V      1.82V
[Rising Waveform]
R_fixture = 50.00
V_fixture = 3.30
V_fixture_min = 3.00
V_fixture_max = 3.60
| time   V(typ)   V(min)   V(max)
0s        1.16V      1.25V      1.34V
900ps     1.16V      1.25V      1.34V
1.2ns     1.16V      1.25V      1.59V
1.5ns     1.27V      1.25V      2.49V
1.8ns     2.02V      1.26V      3.36V
2.1ns     2.78V      1.4V       3.51V
2.7ns     3.2V       2.45V      3.57V
3ns       3.24V      2.74V      3.58V
3.6ns     3.27V      2.9V       3.58V
15ns      3.3V       3V         3.6V
[Falling Waveform]
R_fixture = 50.00
V_fixture = 3.30
V_fixture_min = 3.00
V_fixture_max = 3.60
| time   V(typ)   V(min)   V(max)
0s        3.3V       3V         3.6V
1.5ns     3.3V       3V         3.55V
1.8ns     3.3V       3V         3.2V
2.1ns     3.22V      3V         2.67V
2.7ns     2.57V      2.95V      1.77V
3.3ns     1.65V      2.6V       1.47V
3.6ns     1.41V      2.29V      1.42V
4.5ns     1.21V      1.48V      1.37V
5.4ns     1.18V      1.31V      1.36V
15ns      1.16V      1.26V      1.34V
[Falling Waveform]
R_fixture = 50.00
V_fixture = 0.000
V_fixture_min = 0.000
V_fixture_max = 0.000
| time   V(typ)   V(min)   V(max)
0s        1.76V      1.63V      1.82V
1.2ns     1.76V      1.63V      1.78V
1.5ns     1.75V      1.63V      1.12V
1.8ns     1.48V      1.63V      270mV
2.1ns     980mV      1.6V       57.68mV
2.4ns     390mV      1.47V      29.35mV
2.7ns     100mV      1.2V       18.3mV
3.3ns     26.89mV    380mV      9.88mV
3.9ns     13.49mV    79.7mV     6.76mV
15ns      940uV      1.3mV      950uV
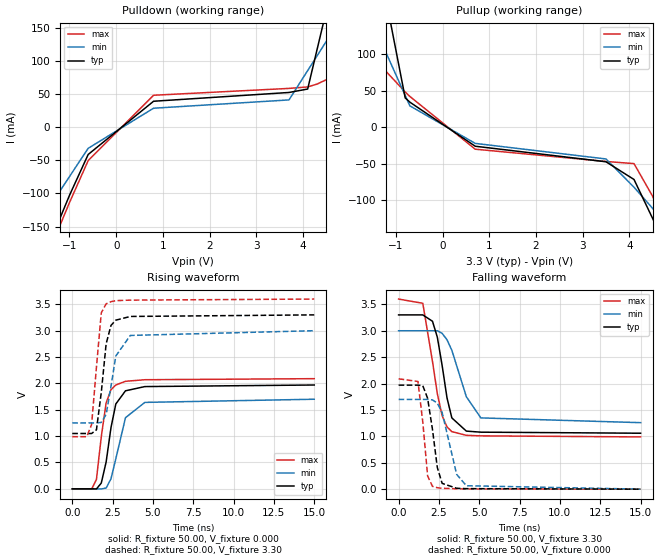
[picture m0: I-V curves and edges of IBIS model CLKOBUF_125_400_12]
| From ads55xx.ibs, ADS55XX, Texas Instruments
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|   Model CLKOBUF_125_400_12
[Model]   CLKOBUF_125_400_12
Model_type   Output
Polarity   Non-Inverting
Vmeas =   1.65V
C_comp   2pf   2pf   2pf
[Temperature Range]   50.00   0.10k   -20.00
[Voltage Range]   3.30V   3.00V   3.60V
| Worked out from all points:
|   slope of the pulldown table from 0 to 0.495 V, typ, clamps not added: 17.5 ohm
|   slope of the pullup table from 0 to 0.495 V, typ, clamps not added: 25.1 ohm
|   rising waveform, R_fixture 50.00, V_fixture 0.000: 20-80 % time 664ps typ, 802ps min, 562ps max; typ from 0 V to 1.97 V
|   rising waveform, R_fixture 50.00, V_fixture 3.30: 20-80 % time 525ps typ, 655ps min, 443ps max; typ from 1.05 V to 3.3 V
|   falling waveform, R_fixture 50.00, V_fixture 3.30: 20-80 % time 760ps typ, 1.14ns min, 825ps max; typ from 3.3 V to 1.06 V
|   falling waveform, R_fixture 50.00, V_fixture 0.000: 20-80 % time 542ps typ, 770ps min, 407ps max; typ from 1.97 V to 0.001 V
[Pulldown]
| voltage   I(typ)   I(min)   I(max)
-3.3V     -493.7mA   -319.5mA   -503.6mA
-1.7V     -221.8mA   -149.1mA   -232.4mA
-1.5V     -187.8mA   -127.8mA   -198.5mA
-1V       -102.9mA   -74.57mA   -113.8mA
-600mV    -41.27mA   -31.97mA   -50.5mA
800mV     39.06mA    28.56mA    48.11mA
3.7V      52.32mA    41.08mA    58.45mA
4.1V      57.51mA    85.32mA    60.72mA
4.3V      116.7mA    107.4mA    64.94mA
4.5V      175.9mA    129.6mA    71.61mA
4.7V      235.2mA    151.7mA    78.28mA
6.6V      797.8mA    361.8mA    141.6mA
[Pullup]
| voltage   I(typ)   I(min)   I(max)
-3.3V     861.8mA    399.6mA    219.6mA
-2.1V     467.3mA    228.6mA    137.3mA
-1.5V     270.1mA    143.1mA    96.14mA
-1V       105.8mA    71.89mA    61.84mA
-800mV    40.02mA    43.39mA    48.12mA
-700mV    34.18mA    29.14mA    42mA
700mV     -26.12mA   -22.23mA   -30.18mA
3.5V      -47.39mA   -43.53mA   -46.96mA
4.1V      -71.63mA   -82.21mA   -49.9mA
4.5V      -125.1mA   -111.2mA   -94.75mA
4.9V      -178.5mA   -140.1mA   -161.2mA
6.6V      -405.6mA   -263.2mA   -443.8mA
[Ramp]
| variable   typ   min   max
dV/dt_r   1.18/0.62n   1.02/0.77n   1.25/0.55n
dV/dt_f   1.35/0.73n   1.05/1.11n   1.57/0.80n
R_load = 50.00
[Rising Waveform]
R_fixture = 50.00
V_fixture = 0.000
V_fixture_min = 0.000
V_fixture_max = 0.000
| time   V(typ)   V(min)   V(max)
0s        23.8nV     34.56nV    45.01nV
1.2ns     -7.03uV    590nV      -5.95mV
1.5ns     -1.51mV    36.39uV    180mV
1.8ns     110mV      -2.48mV    990mV
2.1ns     510mV      16.09mV    1.63V
2.4ns     1.16V      190mV      1.88V
2.7ns     1.61V      570mV      1.97V
3.3ns     1.86V      1.35V      2.04V
4.5ns     1.94V      1.64V      2.07V
15ns      1.97V      1.7V       2.09V
[Rising Waveform]
R_fixture = 50.00
V_fixture = 3.30
V_fixture_min = 3.00
V_fixture_max = 3.60
| time   V(typ)   V(min)   V(max)
0s        1.05V      1.25V      990mV
900ps     1.05V      1.25V      990mV
1.2ns     1.05V      1.25V      1.22V
1.5ns     1.12V      1.25V      2.31V
1.8ns     1.83V      1.26V      3.34V
2.1ns     2.75V      1.41V      3.51V
2.4ns     3.1V       1.94V      3.55V
2.7ns     3.2V       2.52V      3.57V
3.6ns     3.27V      2.91V      3.58V
15ns      3.3V       3V         3.6V
[Falling Waveform]
R_fixture = 50.00
V_fixture = 3.30
V_fixture_min = 3.00
V_fixture_max = 3.60
| time   V(typ)   V(min)   V(max)
0s        3.3V       3V         3.6V
1.5ns     3.3V       3V         3.52V
2.1ns     3.18V      3V         2.42V
2.4ns     2.88V      3V         1.81V
2.7ns     2.34V      2.95V      1.39V
3ns       1.73V      2.83V      1.18V
3.3ns     1.35V      2.63V      1.09V
4.2ns     1.1V       1.75V      1.02V
5.1ns     1.08V      1.35V      1.01V
15ns      1.06V      1.26V      990mV
[Falling Waveform]
R_fixture = 50.00
V_fixture = 0.000
V_fixture_min = 0.000
V_fixture_max = 0.000
| time   V(typ)   V(min)   V(max)
0s        1.97V      1.7V       2.09V
1.2ns     1.97V      1.7V       2.04V
1.5ns     1.96V      1.7V       1.27V
1.8ns     1.72V      1.7V       250mV
2.1ns     1.13V      1.69V      54.64mV
2.4ns     410mV      1.63V      28.26mV
2.7ns     110mV      1.45V      17.49mV
3.6ns     17.8mV     280mV      7.66mV
4.2ns     10.74mV    65.82mV    5.54mV
15ns      920uV      1.32mV     900uV
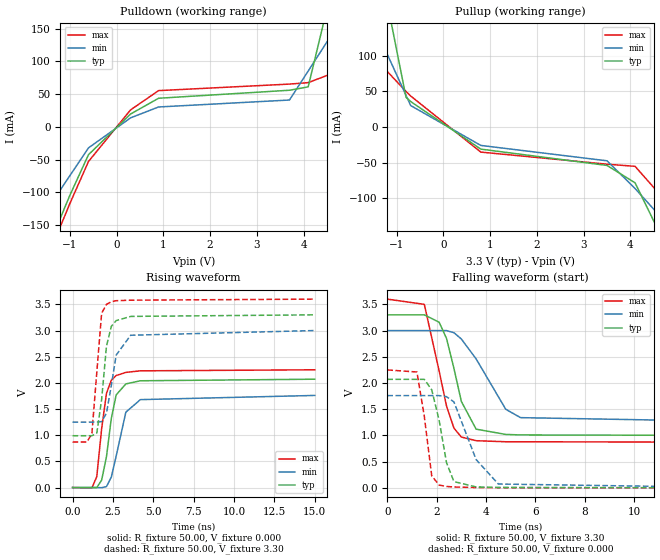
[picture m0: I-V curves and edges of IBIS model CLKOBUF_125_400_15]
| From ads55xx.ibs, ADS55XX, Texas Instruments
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|   Model CLKOBUF_125_400_15
[Model]   CLKOBUF_125_400_15
Model_type   Output
Polarity   Non-Inverting
Vmeas =   1.65V
C_comp   2pf   2pf   2pf
[Temperature Range]   50.00   0.10k   -20.00
[Voltage Range]   3.30V   3.00V   3.60V
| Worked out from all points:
|   slope of the pulldown table from 0 to 0.495 V, typ, clamps not added: 16.8 ohm
|   slope of the pullup table from 0 to 0.495 V, typ, clamps not added: 23.6 ohm
|   rising waveform, R_fixture 50.00, V_fixture 0.000: 20-80 % time 641ps typ, 757ps min, 521ps max; typ from 0 V to 2.07 V
|   rising waveform, R_fixture 50.00, V_fixture 3.30: 20-80 % time 516ps typ, 648ps min, 429ps max; typ from 0.99 V to 3.3 V
|   falling waveform, R_fixture 50.00, V_fixture 3.30: 20-80 % time 745ps typ, 1.3ns min, 760ps max; typ from 3.3 V to 1 V
|   falling waveform, R_fixture 50.00, V_fixture 0.000: 20-80 % time 544ps typ, 848ps min, 397ps max; typ from 2.07 V to 0.001 V
[Pulldown]
| voltage   I(typ)   I(min)   I(max)
-3.3V     -498.6mA   -319.5mA   -514.2mA
-1.9V     -258.7mA   -170.4mA   -272.6mA
-1.5V     -190.2mA   -127.8mA   -203.5mA
-1V       -104.6mA   -74.57mA   -117.2mA
-600mV    -42.36mA   -31.97mA   -52.72mA
300mV     19.71mA    13.85mA    26mA
900mV     43.79mA    30.47mA    55.44mA
3.7V      55.99mA    41.08mA    65.4mA
4.1V      61.18mA    85.32mA    67.64mA
4.5V      179.6mA    129.6mA    78.5mA
4.9V      298mA      173.8mA    91.82mA
6.6V      801.2mA    361.8mA    148.4mA
[Pullup]
| voltage   I(typ)   I(min)   I(max)
-3.3V     867.3mA    402.8mA    225.1mA
-2.1V     470.9mA    230.7mA    140.9mA
-1.5V     272.8mA    144.7mA    98.76mA
-1V       107.6mA    72.96mA    63.66mA
-800mV    41.56mA    44.28mA    49.62mA
-700mV    35.55mA    29.94mA    43.35mA
800mV     -31.09mA   -25.92mA   -35.27mA
3.5V      -53.95mA   -47.47mA   -52.21mA
4.1V      -78.31mA   -86.26mA   -55.21mA
4.7V      -158.6mA   -129.8mA   -99.65mA
5.3V      -238.9mA   -173.4mA   -148.9mA
6.6V      -412.8mA   -267.8mA   -255.5mA
[Ramp]
| variable   typ   min   max
dV/dt_r   1.24/0.58n   1.06/0.72n   1.35/0.52n
dV/dt_f   1.38/0.71n   1.05/1.29n   1.64/0.72n
R_load = 50.00
[Rising Waveform]
R_fixture = 50.00
V_fixture = 0.000
V_fixture_min = 0.000
V_fixture_max = 0.000
| time   V(typ)   V(min)   V(max)
0s        23.43nV    34.65nV    43.64nV
1.2ns     -5.54uV    600nV      -5.84mV
1.5ns     -76.41uV   36.4uV     210mV
1.8ns     140mV      -2.53mV    1.12V
2.1ns     590mV      17.9mV     1.8V
2.4ns     1.32V      200mV      2.05V
2.7ns     1.77V      600mV      2.14V
3.3ns     1.98V      1.44V      2.2V
4.2ns     2.04V      1.68V      2.23V
15ns      2.07V      1.76V      2.25V
[Rising Waveform]
R_fixture = 50.00
V_fixture = 3.30
V_fixture_min = 3.00
V_fixture_max = 3.60
| time   V(typ)   V(min)   V(max)
0s        990mV      1.25V      870mV
900ps     990mV      1.25V      870mV
1.2ns     990mV      1.25V      1.04V
1.5ns     1.04V      1.25V      2.2V
1.8ns     1.68V      1.26V      3.33V
2.1ns     2.7V       1.42V      3.5V
2.4ns     3.08V      1.95V      3.55V
2.7ns     3.19V      2.53V      3.57V
3.6ns     3.27V      2.91V      3.58V
15ns      3.3V       3V         3.6V
[Falling Waveform]
R_fixture = 50.00
V_fixture = 3.30
V_fixture_min = 3.00
V_fixture_max = 3.60
| time   V(typ)   V(min)   V(max)
0s        3.3V       3V         3.6V
1.5ns     3.3V       3V         3.5V
2.1ns     3.16V      3V         2.23V
2.4ns     2.85V      3V         1.56V
2.7ns     2.28V      2.96V      1.14V
3ns       1.65V      2.84V      970mV
3.6ns     1.12V      2.46V      900mV
4.8ns     1.02V      1.5V       880mV
5.4ns     1.01V      1.34V      880mV
15ns      1V         1.26V      870mV
[Falling Waveform]
R_fixture = 50.00
V_fixture = 0.000
V_fixture_min = 0.000
V_fixture_max = 0.000
| time   V(typ)   V(min)   V(max)
0s        2.07V      1.76V      2.25V
1.2ns     2.07V      1.76V      2.21V
1.5ns     2.07V      1.76V      1.36V
1.8ns     1.87V      1.76V      230mV
2.1ns     1.29V      1.76V      53.73mV
2.4ns     480mV      1.74V      27.44mV
2.7ns     120mV      1.64V      17.02mV
3.6ns     18.3mV     540mV      7.46mV
4.5ns     8.84mV     74.09mV    4.72mV
15ns      900uV      1.38mV     870uV
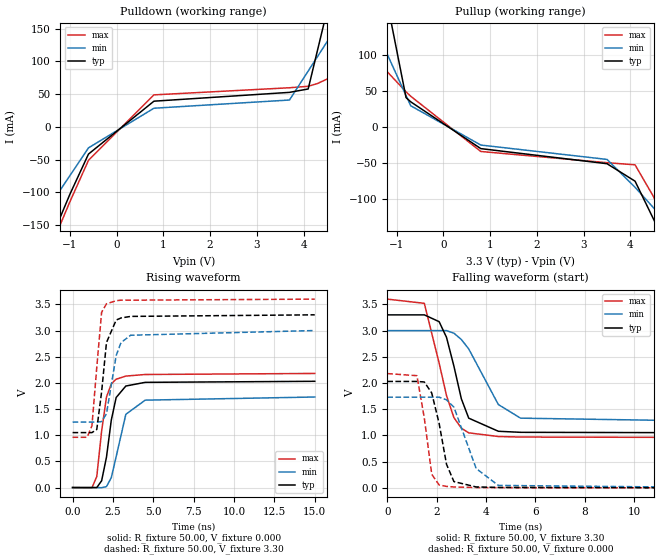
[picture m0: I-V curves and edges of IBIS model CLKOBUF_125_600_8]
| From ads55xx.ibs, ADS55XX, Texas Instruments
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|   Model CLKOBUF_125_600_8
[Model]   CLKOBUF_125_600_8
Model_type   Output
Polarity   Non-Inverting
Vmeas =   1.65V
C_comp   2pf   2pf   2pf
[Temperature Range]   50.00   0.10k   -20.00
[Voltage Range]   3.30V   3.00V   3.60V
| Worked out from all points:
|   slope of the pulldown table from 0 to 0.495 V, typ, clamps not added: 17.4 ohm
|   slope of the pullup table from 0 to 0.495 V, typ, clamps not added: 24.2 ohm
|   rising waveform, R_fixture 50.00, V_fixture 0.000: 20-80 % time 649ps typ, 768ps min, 539ps max; typ from 0 V to 2.03 V
|   rising waveform, R_fixture 50.00, V_fixture 3.30: 20-80 % time 510ps typ, 650ps min, 438ps max; typ from 1.05 V to 3.3 V
|   falling waveform, R_fixture 50.00, V_fixture 3.30: 20-80 % time 751ps typ, 1.18ns min, 814ps max; typ from 3.3 V to 1.05 V
|   falling waveform, R_fixture 50.00, V_fixture 0.000: 20-80 % time 543ps typ, 790ps min, 404ps max; typ from 2.03 V to 0.001 V
[Pulldown]
| voltage   I(typ)   I(min)   I(max)
-3.3V     -494.1mA   -319.5mA   -505.7mA
-1.9V     -256.1mA   -170.4mA   -267.5mA
-1.5V     -188.1mA   -127.8mA   -199.5mA
-1V       -103.1mA   -74.57mA   -114.5mA
-600mV    -41.41mA   -31.97mA   -50.95mA
800mV     39.3mA     28.56mA    48.94mA
3.7V      52.77mA    41.08mA    59.8mA
4.1V      57.96mA    85.32mA    62.05mA
4.3V      117.2mA    107.4mA    66.28mA
4.5V      176.4mA    129.6mA    72.94mA
4.7V      235.6mA    151.7mA    79.6mA
6.6V      798.2mA    361.8mA    142.9mA
[Pullup]
| voltage   I(typ)   I(min)   I(max)
-3.3V     864.9mA    401mA      222.7mA
-2.1V     469.4mA    229.6mA    139.3mA
-1.5V     271.7mA    143.8mA    97.59mA
-1V       106.9mA    72.36mA    62.84mA
-800mV    40.94mA    43.78mA    48.94mA
-700mV    34.99mA    29.49mA    42.74mA
800mV     -30.2mA    -25.23mA   -34.19mA
3.5V      -51.2mA    -45.23mA   -49.78mA
4.1V      -75.51mA   -84.01mA   -52.76mA
4.5V      -129mA     -113mA     -97.63mA
4.9V      -182.5mA   -142.1mA   -164.1mA
6.6V      -409.8mA   -265.5mA   -446.8mA
[Ramp]
| variable   typ   min   max
dV/dt_r   1.22/0.58n   1.04/0.74n   1.31/0.53n
dV/dt_f   1.35/0.72n   1.05/1.18n   1.58/0.79n
R_load = 50.00
[Rising Waveform]
R_fixture = 50.00
V_fixture = 0.000
V_fixture_min = 0.000
V_fixture_max = 0.000
| time   V(typ)   V(min)   V(max)
0s        23.84nV    34.61nV    44.78nV
1.2ns     -6.74uV    600nV      -5.86mV
1.5ns     -790uV     36.4uV     210mV
1.8ns     130mV      -2.51mV    1.08V
2.1ns     580mV      17.22mV    1.73V
2.4ns     1.29V      190mV      1.98V
2.7ns     1.72V      590mV      2.07V
3.3ns     1.94V      1.4V       2.13V
4.5ns     2.01V      1.67V      2.16V
15ns      2.03V      1.73V      2.18V
[Rising Waveform]
R_fixture = 50.00
V_fixture = 3.30
V_fixture_min = 3.00
V_fixture_max = 3.60
| time   V(typ)   V(min)   V(max)
0s        1.05V      1.25V      960mV
900ps     1.05V      1.25V      960mV
1.2ns     1.05V      1.25V      1.18V
1.5ns     1.11V      1.25V      2.3V
1.8ns     1.83V      1.26V      3.35V
2.1ns     2.77V      1.41V      3.51V
2.7ns     3.2V       2.52V      3.57V
3ns       3.24V      2.77V      3.58V
3.6ns     3.27V      2.91V      3.58V
15ns      3.3V       3V         3.6V
[Falling Waveform]
R_fixture = 50.00
V_fixture = 3.30
V_fixture_min = 3.00
V_fixture_max = 3.60
| time   V(typ)   V(min)   V(max)
0s        3.3V       3V         3.6V
1.5ns     3.3V       3V         3.52V
2.1ns     3.17V      3V         2.38V
2.4ns     2.87V      3V         1.76V
2.7ns     2.32V      2.95V      1.34V
3ns       1.7V       2.83V      1.14V
3.3ns     1.33V      2.65V      1.05V
4.5ns     1.08V      1.59V      980mV
5.4ns     1.06V      1.33V      970mV
15ns      1.05V      1.26V      960mV
[Falling Waveform]
R_fixture = 50.00
V_fixture = 0.000
V_fixture_min = 0.000
V_fixture_max = 0.000
| time   V(typ)   V(min)   V(max)
0s        2.03V      1.73V      2.18V
1.2ns     2.03V      1.73V      2.14V
1.5ns     2.02V      1.73V      1.33V
1.8ns     1.81V      1.73V      260mV
2.1ns     1.23V      1.73V      55.25mV
2.4ns     450mV      1.68V      28.47mV
2.7ns     120mV      1.54V      17.59mV
3.6ns     18.28mV    370mV      7.64mV
4.5ns     8.98mV     47.46mV    4.84mV
15ns      920uV      1.34mV     890uV
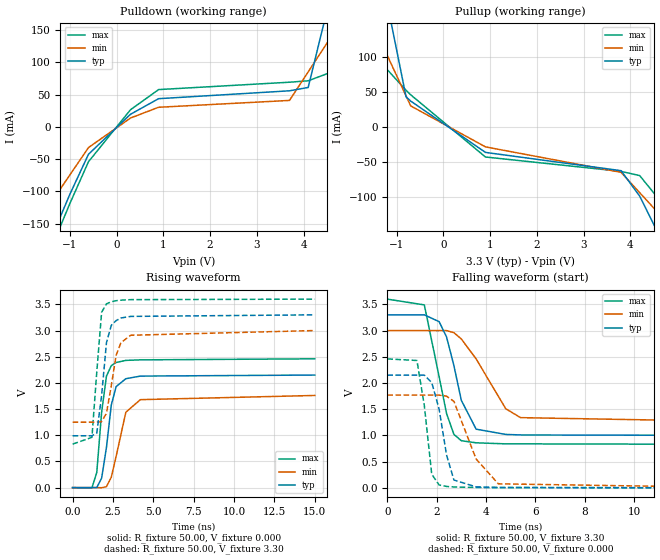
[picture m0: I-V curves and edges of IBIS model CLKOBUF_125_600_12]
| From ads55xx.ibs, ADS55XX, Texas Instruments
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|   Model CLKOBUF_125_600_12
[Model]   CLKOBUF_125_600_12
Model_type   Output
Polarity   Non-Inverting
Vmeas =   1.65V
C_comp   2pf   2pf   2pf
[Temperature Range]   50.00   0.10k   -20.00
[Voltage Range]   3.30V   3.00V   3.60V
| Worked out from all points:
|   slope of the pulldown table from 0 to 0.495 V, typ, clamps not added: 16.8 ohm
|   slope of the pullup table from 0 to 0.495 V, typ, clamps not added: 22.3 ohm
|   rising waveform, R_fixture 50.00, V_fixture 0.000: 20-80 % time 593ps typ, 757ps min, 477ps max; typ from 0 V to 2.15 V
|   rising waveform, R_fixture 50.00, V_fixture 3.30: 20-80 % time 490ps typ, 648ps min, 418ps max; typ from 0.99 V to 3.3 V
|   falling waveform, R_fixture 50.00, V_fixture 3.30: 20-80 % time 740ps typ, 1.33ns min, 701ps max; typ from 3.3 V to 1 V
|   falling waveform, R_fixture 50.00, V_fixture 0.000: 20-80 % time 554ps typ, 855ps min, 386ps max; typ from 2.15 V to 0.001 V
[Pulldown]
| voltage   I(typ)   I(min)   I(max)
-3.3V     -498.6mA   -319.5mA   -519.7mA
-1.9V     -258.7mA   -170.4mA   -275.8mA
-1.5V     -190.2mA   -127.8mA   -206.1mA
-1V       -104.6mA   -74.57mA   -119mA
-600mV    -42.36mA   -31.97mA   -53.88mA
300mV     19.71mA    13.85mA    26.71mA
900mV     43.79mA    30.47mA    57.88mA
3.7V      55.99mA    41.08mA    69.31mA
4.1V      61.18mA    85.32mA    71.53mA
4.5V      179.6mA    129.6mA    82.37mA
4.9V      298.1mA    173.8mA    95.65mA
6.6V      801.4mA    361.8mA    152.1mA
[Pullup]
| voltage   I(typ)   I(min)   I(max)
-3.3V     872.5mA    402.8mA    234.8mA
-2.1V     474.4mA    230.7mA    147.2mA
-1.5V     275.3mA    144.7mA    103.4mA
-1V       109.4mA    73mA       66.93mA
-800mV    43.01mA    44.32mA    52.33mA
-700mV    36.84mA    29.98mA    45.77mA
900mV     -36.3mA    -28.43mA   -42.84mA
3.8V      -62.31mA   -64.68mA   -63.32mA
4.2V      -98.68mA   -93.72mA   -69.36mA
4.7V      -165.7mA   -130mA     -110.5mA
5.1V      -219.3mA   -159.1mA   -143.3mA
6.6V      -420.3mA   -268mA     -266.6mA
[Ramp]
| variable   typ   min   max
dV/dt_r   1.29/0.51n   1.06/0.72n   1.48/0.45n
dV/dt_f   1.38/0.71n   1.05/1.31n   1.66/0.68n
R_load = 50.00
[Rising Waveform]
R_fixture = 50.00
V_fixture = 0.000
V_fixture_min = 0.000
V_fixture_max = 0.000
| time   V(typ)   V(min)   V(max)
0s        23.66nV    34.66nV    43.21nV
1.2ns     -5.49uV    590nV      -4.8mV
1.5ns     1.9mV      36.4uV     290mV
1.8ns     180mV      -2.54mV    1.44V
2.1ns     770mV      18.09mV    2.13V
2.4ns     1.58V      200mV      2.33V
2.7ns     1.93V      600mV      2.39V
3.3ns     2.08V      1.44V      2.43V
4.2ns     2.13V      1.68V      2.44V
15ns      2.15V      1.76V      2.46V
[Rising Waveform]
R_fixture = 50.00
V_fixture = 3.30
V_fixture_min = 3.00
V_fixture_max = 3.60
| time   V(typ)   V(min)   V(max)
0s        990mV      1.25V      830mV
1.2ns     990mV      1.25V      960mV
1.5ns     1.04V      1.25V      2.21V
1.8ns     1.76V      1.26V      3.35V
2.1ns     2.77V      1.42V      3.51V
2.4ns     3.1V       1.95V      3.55V
2.7ns     3.19V      2.53V      3.57V
3ns       3.24V      2.77V      3.58V
3.6ns     3.27V      2.91V      3.59V
15ns      3.3V       3V         3.6V
[Falling Waveform]
R_fixture = 50.00
V_fixture = 3.30
V_fixture_min = 3.00
V_fixture_max = 3.60
| time   V(typ)   V(min)   V(max)
0s        3.3V       3V         3.6V
1.5ns     3.3V       3V         3.49V
2.1ns     3.17V      3V         2.12V
2.4ns     2.88V      3V         1.42V
2.7ns     2.33V      2.96V      1.02V
3ns       1.67V      2.84V      900mV
3.6ns     1.12V      2.46V      860mV
4.8ns     1.02V      1.51V      840mV
5.4ns     1.01V      1.34V      840mV
15ns      1V         1.26V      830mV
[Falling Waveform]
R_fixture = 50.00
V_fixture = 0.000
V_fixture_min = 0.000
V_fixture_max = 0.000
| time   V(typ)   V(min)   V(max)
0s        2.15V      1.77V      2.46V
1.2ns     2.15V      1.77V      2.43V
1.5ns     2.15V      1.77V      1.57V
1.8ns     2.01V      1.77V      260mV
2.1ns     1.5V       1.77V      55.53mV
2.4ns     630mV      1.75V      28.04mV
2.7ns     150mV      1.65V      17.29mV
3.6ns     19.55mV    550mV      7.5mV
4.5ns     9.18mV     77.74mV    4.7mV
15ns      900uV      1.38mV     860uV
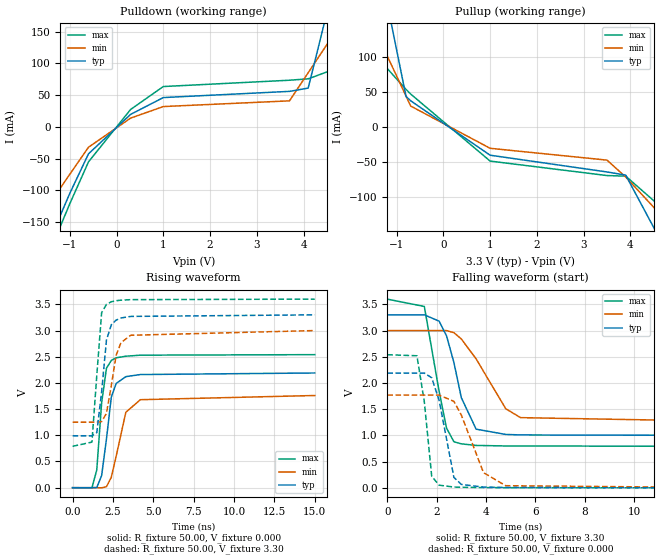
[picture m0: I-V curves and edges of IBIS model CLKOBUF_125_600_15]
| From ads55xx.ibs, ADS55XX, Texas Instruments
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|   Model CLKOBUF_125_600_15
[Model]   CLKOBUF_125_600_15
Model_type   Output
Polarity   Non-Inverting
Vmeas =   1.65V
C_comp   2pf   2pf   2pf
[Temperature Range]   50.00   0.10k   -20.00
[Voltage Range]   3.30V   3.00V   3.60V
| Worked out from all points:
|   slope of the pulldown table from 0 to 0.495 V, typ, clamps not added: 16.8 ohm
|   slope of the pullup table from 0 to 0.495 V, typ, clamps not added: 21.7 ohm
|   rising waveform, R_fixture 50.00, V_fixture 0.000: 20-80 % time 536ps typ, 757ps min, 448ps max; typ from 0 V to 2.19 V
|   rising waveform, R_fixture 50.00, V_fixture 3.30: 20-80 % time 464ps typ, 648ps min, 411ps max; typ from 0.99 V to 3.3 V
|   falling waveform, R_fixture 50.00, V_fixture 3.30: 20-80 % time 750ps typ, 1.33ns min, 633ps max; typ from 3.3 V to 1 V
|   falling waveform, R_fixture 50.00, V_fixture 0.000: 20-80 % time 536ps typ, 855ps min, 373ps max; typ from 2.19 V to 0.001 V
[Pulldown]
| voltage   I(typ)   I(min)   I(max)
-3.3V     -498.6mA   -319.5mA   -525.7mA
-1.9V     -258.7mA   -170.4mA   -279.3mA
-1.5V     -190.2mA   -127.8mA   -208.9mA
-1V       -104.6mA   -74.57mA   -120.9mA
-600mV    -42.36mA   -31.97mA   -55.05mA
300mV     19.71mA    13.85mA    27.44mA
1V        46.24mA    32.08mA    63.6mA
3.7V      56mA       41.08mA    73.55mA
4.1V      61.19mA    85.32mA    75.75mA
4.5V      179.6mA    129.6mA    86.55mA
4.9V      298mA      173.8mA    99.79mA
6.6V      801.2mA    361.8mA    156.1mA
[Pullup]
| voltage   I(typ)   I(min)   I(max)
-3.3V     875.5mA    402.8mA    240.4mA
-2.1V     476.3mA    230.7mA    150.9mA
-1.5V     276.7mA    144.7mA    106.2mA
-1V       110.3mA    73mA       68.87mA
-800mV    43.78mA    44.32mA    53.95mA
-700mV    37.53mA    29.98mA    47.2mA
1V        -40.64mA   -30.7mA    -49.07mA
3.5V      -64.67mA   -47.67mA   -69.85mA
3.9V      -69.22mA   -71.94mA   -70.7mA
4.7V      -169.7mA   -130mA     -117.7mA
5.1V      -223.4mA   -159.1mA   -150.6mA
6.6V      -424.5mA   -268mA     -274.1mA
[Ramp]
| variable   typ   min   max
dV/dt_r   1.31/0.49n   1.06/0.72n   1.52/0.42n
dV/dt_f   1.38/0.70n   1.05/1.31n   1.68/0.60n
R_load = 50.00
[Rising Waveform]
R_fixture = 50.00
V_fixture = 0.000
V_fixture_min = 0.000
V_fixture_max = 0.000
| time   V(typ)   V(min)   V(max)
0s        23.85nV    34.66nV    42.7nV
1.2ns     -5.45uV    600nV      -3.35mV
1.5ns     3.93mV     36.41uV    340mV
1.8ns     230mV      -2.54mV    1.62V
2.1ns     930mV      18.1mV     2.28V
2.4ns     1.73V      200mV      2.43V
2.7ns     1.99V      600mV      2.48V
3.3ns     2.12V      1.44V      2.51V
4.2ns     2.16V      1.68V      2.53V
15ns      2.19V      1.76V      2.54V
[Rising Waveform]
R_fixture = 50.00
V_fixture = 3.30
V_fixture_min = 3.00
V_fixture_max = 3.60
| time   V(typ)   V(min)   V(max)
0s        990mV      1.25V      790mV
1.2ns     990mV      1.25V      870mV
1.5ns     1.05V      1.25V      2.14V
1.8ns     1.83V      1.26V      3.34V
2.1ns     2.82V      1.42V      3.5V
2.4ns     3.11V      1.95V      3.55V
2.7ns     3.2V       2.53V      3.57V
3ns       3.24V      2.77V      3.58V
3.6ns     3.27V      2.91V      3.59V
15ns      3.3V       3V         3.6V
[Falling Waveform]
R_fixture = 50.00
V_fixture = 3.30
V_fixture_min = 3.00
V_fixture_max = 3.60
| time   V(typ)   V(min)   V(max)
0s        3.3V       3V         3.6V
1.5ns     3.3V       3V         3.46V
2.1ns     3.18V      3V         1.84V
2.4ns     2.9V       3V         1.14V
2.7ns     2.39V      2.96V      880mV
3ns       1.72V      2.84V      840mV
3.6ns     1.12V      2.46V      810mV
4.8ns     1.02V      1.51V      800mV
5.4ns     1.01V      1.34V      800mV
15ns      1V         1.26V      790mV
[Falling Waveform]
R_fixture = 50.00
V_fixture = 0.000
V_fixture_min = 0.000
V_fixture_max = 0.000
| time   V(typ)   V(min)   V(max)
0s        2.19V      1.77V      2.54V
1.2ns     2.19V      1.77V      2.52V
1.5ns     2.19V      1.77V      1.64V
1.8ns     2.1V       1.77V      220mV
2.1ns     1.67V      1.77V      52.14mV
2.7ns     200mV      1.65V      16.39mV
3ns       66.6mV     1.39V      11.81mV
3.9ns     14.98mV    290mV      6.2mV
4.8ns     7.87mV     41.86mV    4.11mV
15ns      910uV      1.38mV     840uV
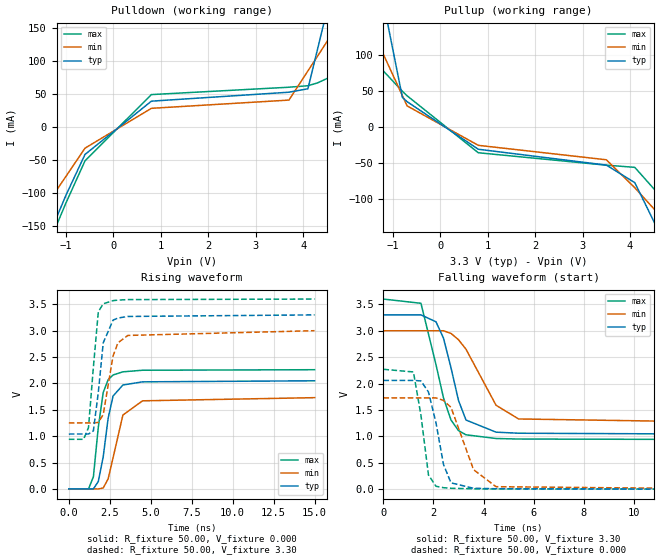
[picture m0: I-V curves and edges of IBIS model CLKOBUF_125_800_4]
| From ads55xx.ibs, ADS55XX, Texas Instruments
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|   Model CLKOBUF_125_800_4
[Model]   CLKOBUF_125_800_4
Model_type   Output
Polarity   Non-Inverting
Vmeas =   1.65V
C_comp   2pf   2pf   2pf
[Temperature Range]   50.00   0.10k   -20.00
[Voltage Range]   3.30V   3.00V   3.60V
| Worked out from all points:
|   slope of the pulldown table from 0 to 0.495 V, typ, clamps not added: 17.3 ohm
|   slope of the pullup table from 0 to 0.495 V, typ, clamps not added: 23.9 ohm
|   rising waveform, R_fixture 50.00, V_fixture 0.000: 20-80 % time 642ps typ, 768ps min, 519ps max; typ from 0 V to 2.05 V
|   rising waveform, R_fixture 50.00, V_fixture 3.30: 20-80 % time 510ps typ, 650ps min, 435ps max; typ from 1.04 V to 3.3 V
|   falling waveform, R_fixture 50.00, V_fixture 3.30: 20-80 % time 746ps typ, 1.18ns min, 808ps max; typ from 3.3 V to 1.04 V
|   falling waveform, R_fixture 50.00, V_fixture 0.000: 20-80 % time 550ps typ, 786ps min, 403ps max; typ from 2.06 V to 0.001 V
[Pulldown]
| voltage   I(typ)   I(min)   I(max)
-3.3V     -494.7mA   -319.5mA   -507mA
-1.9V     -256.4mA   -170.4mA   -268.3mA
-1.5V     -188.3mA   -127.8mA   -200.1mA
-1V       -103.2mA   -74.57mA   -114.9mA
-600mV    -41.48mA   -31.97mA   -51.21mA
800mV     39.43mA    28.56mA    49.42mA
3.7V      53.03mA    41.08mA    60.59mA
4.1V      58.22mA    85.32mA    62.85mA
4.3V      117.4mA    107.4mA    67.07mA
4.5V      176.7mA    129.6mA    73.73mA
4.7V      235.9mA    151.7mA    80.39mA
6.6V      798.5mA    361.8mA    143.7mA
[Pullup]
| voltage   I(typ)   I(min)   I(max)
-3.3V     866.3mA    401mA      225.5mA
-2.1V     470.3mA    229.6mA    141.2mA
-1.5V     272.3mA    143.8mA    98.99mA
-1V       107.3mA    72.37mA    63.84mA
-800mV    41.27mA    43.79mA    49.78mA
-700mV    35.29mA    29.5mA     43.48mA
800mV     -30.68mA   -25.24mA   -35.52mA
3.5V      -52.67mA   -45.27mA   -52.77mA
4.1V      -77.01mA   -84.05mA   -55.78mA
4.7V      -157.3mA   -127.6mA   -100.2mA
5.3V      -237.6mA   -171.2mA   -149.4mA
6.6V      -411.5mA   -265.6mA   -256mA
[Ramp]
| variable   typ   min   max
dV/dt_r   1.23/0.57n   1.04/0.74n   1.36/0.51n
dV/dt_f   1.35/0.71n   1.05/1.18n   1.59/0.78n
R_load = 50.00
[Rising Waveform]
R_fixture = 50.00
V_fixture = 0.000
V_fixture_min = 0.000
V_fixture_max = 0.000
| time   V(typ)   V(min)   V(max)
0s        23.84nV    34.61nV    44.69nV
1.2ns     -6.58uV    590nV      -5.66mV
1.5ns     -460uV     36.39uV    230mV
1.8ns     140mV      -2.51mV    1.17V
2.1ns     610mV      17.22mV    1.83V
2.4ns     1.34V      190mV      2.07V
2.7ns     1.76V      590mV      2.16V
3.3ns     1.97V      1.4V       2.22V
4.5ns     2.03V      1.67V      2.25V
15ns      2.05V      1.73V      2.26V
[Rising Waveform]
R_fixture = 50.00
V_fixture = 3.30
V_fixture_min = 3.00
V_fixture_max = 3.60
| time   V(typ)   V(min)   V(max)
0s        1.04V      1.25V      940mV
900ps     1.04V      1.25V      940mV
1.2ns     1.04V      1.25V      1.16V
1.5ns     1.1V       1.25V      2.31V
1.8ns     1.83V      1.26V      3.36V
2.1ns     2.77V      1.41V      3.51V
2.7ns     3.2V       2.52V      3.57V
3ns       3.24V      2.77V      3.58V
3.6ns     3.27V      2.91V      3.59V
15ns      3.3V       3V         3.6V
[Falling Waveform]
R_fixture = 50.00
V_fixture = 3.30
V_fixture_min = 3.00
V_fixture_max = 3.60
| time   V(typ)   V(min)   V(max)
0s        3.3V       3V         3.6V
1.5ns     3.3V       3V         3.52V
2.1ns     3.17V      3V         2.36V
2.4ns     2.86V      3V         1.73V
2.7ns     2.3V       2.95V      1.31V
3ns       1.68V      2.83V      1.11V
3.3ns     1.31V      2.65V      1.03V
4.5ns     1.08V      1.59V      960mV
5.4ns     1.06V      1.33V      950mV
15ns      1.04V      1.26V      940mV
[Falling Waveform]
R_fixture = 50.00
V_fixture = 0.000
V_fixture_min = 0.000
V_fixture_max = 0.000
| time   V(typ)   V(min)   V(max)
0s        2.06V      1.73V      2.27V
1.2ns     2.06V      1.73V      2.22V
1.5ns     2.05V      1.73V      1.4V
1.8ns     1.84V      1.73V      270mV
2.1ns     1.26V      1.73V      56.2mV
2.4ns     470mV      1.68V      28.79mV
2.7ns     120mV      1.55V      17.75mV
3.6ns     18.32mV    370mV      7.67mV
4.5ns     8.98mV     47.79mV    4.84mV
15ns      910uV      1.34mV     890uV
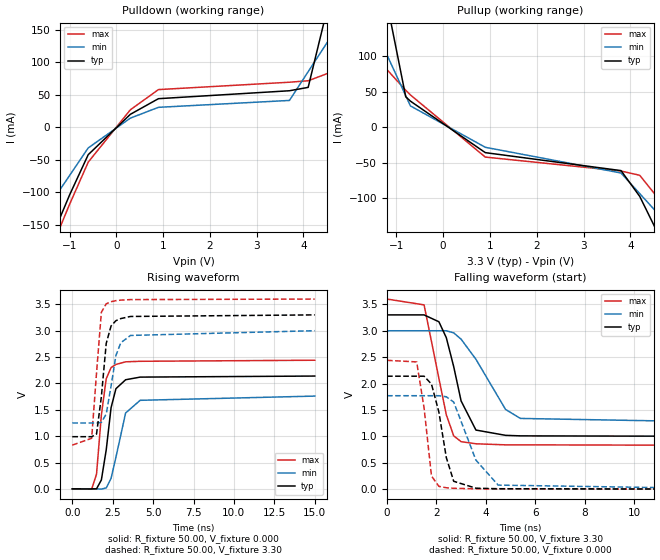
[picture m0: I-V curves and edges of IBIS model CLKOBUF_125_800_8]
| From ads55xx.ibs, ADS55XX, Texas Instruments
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|   Model CLKOBUF_125_800_8
[Model]   CLKOBUF_125_800_8
Model_type   Output
Polarity   Non-Inverting
Vmeas =   1.65V
C_comp   2pf   2pf   2pf
[Temperature Range]   50.00   0.10k   -20.00
[Voltage Range]   3.30V   3.00V   3.60V
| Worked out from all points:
|   slope of the pulldown table from 0 to 0.495 V, typ, clamps not added: 16.8 ohm
|   slope of the pullup table from 0 to 0.495 V, typ, clamps not added: 22.5 ohm
|   rising waveform, R_fixture 50.00, V_fixture 0.000: 20-80 % time 608ps typ, 757ps min, 484ps max; typ from 0 V to 2.14 V
|   rising waveform, R_fixture 50.00, V_fixture 3.30: 20-80 % time 497ps typ, 648ps min, 418ps max; typ from 0.99 V to 3.3 V
|   falling waveform, R_fixture 50.00, V_fixture 3.30: 20-80 % time 745ps typ, 1.33ns min, 697ps max; typ from 3.3 V to 1 V
|   falling waveform, R_fixture 50.00, V_fixture 0.000: 20-80 % time 557ps typ, 855ps min, 387ps max; typ from 2.14 V to 0.001 V
[Pulldown]
| voltage   I(typ)   I(min)   I(max)
-3.3V     -498.6mA   -319.5mA   -519.6mA
-1.9V     -258.7mA   -170.4mA   -275.8mA
-1.5V     -190.2mA   -127.8mA   -206.1mA
-1V       -104.6mA   -74.57mA   -119mA
-600mV    -42.36mA   -31.97mA   -53.83mA
300mV     19.71mA    13.85mA    26.68mA
900mV     43.79mA    30.47mA    57.77mA
3.7V      55.99mA    41.08mA    69.13mA
4.1V      61.18mA    85.32mA    71.35mA
4.5V      179.6mA    129.6mA    82.19mA
4.9V      298.1mA    173.8mA    95.47mA
6.6V      801.4mA    361.8mA    151.9mA
[Pullup]
| voltage   I(typ)   I(min)   I(max)
-3.3V     871.8mA    402.8mA    233.5mA
-2.1V     473.9mA    230.7mA    146.4mA
-1.5V     274.9mA    144.7mA    102.8mA
-1V       109.1mA    73mA       66.51mA
-800mV    42.81mA    44.32mA    51.99mA
-700mV    36.66mA    29.98mA    45.46mA
900mV     -35.97mA   -28.43mA   -42.23mA
3.8V      -61.31mA   -64.68mA   -61.9mA
4.2V      -97.67mA   -93.72mA   -67.94mA
4.7V      -164.7mA   -130mA     -109mA
5.1V      -218.3mA   -159.1mA   -141.8mA
6.6V      -419.3mA   -268mA     -265mA
[Ramp]
| variable   typ   min   max
dV/dt_r   1.29/0.52n   1.06/0.72n   1.46/0.46n
dV/dt_f   1.38/0.71n   1.05/1.31n   1.66/0.68n
R_load = 50.00
[Rising Waveform]
R_fixture = 50.00
V_fixture = 0.000
V_fixture_min = 0.000
V_fixture_max = 0.000
| time   V(typ)   V(min)   V(max)
0s        23.62nV    34.66nV    43.21nV
1.2ns     -5.5uV     590nV      -4.98mV
1.5ns     1.51mV     36.41uV    280mV
1.8ns     170mV      -2.54mV    1.4V
2.1ns     740mV      18.14mV    2.09V
2.4ns     1.54V      200mV      2.3V
2.7ns     1.9V       600mV      2.36V
3.3ns     2.07V      1.44V      2.41V
4.2ns     2.12V      1.68V      2.42V
15ns      2.14V      1.76V      2.44V
[Rising Waveform]
R_fixture = 50.00
V_fixture = 3.30
V_fixture_min = 3.00
V_fixture_max = 3.60
| time   V(typ)   V(min)   V(max)
0s        990mV      1.25V      830mV
1.2ns     990mV      1.25V      960mV
1.5ns     1.04V      1.25V      2.2V
1.8ns     1.75V      1.26V      3.35V
2.1ns     2.76V      1.42V      3.51V
2.4ns     3.09V      1.95V      3.55V
2.7ns     3.19V      2.53V      3.57V
3ns       3.23V      2.77V      3.58V
3.6ns     3.27V      2.91V      3.59V
15ns      3.3V       3V         3.6V
[Falling Waveform]
R_fixture = 50.00
V_fixture = 3.30
V_fixture_min = 3.00
V_fixture_max = 3.60
| time   V(typ)   V(min)   V(max)
0s        3.3V       3V         3.6V
1.5ns     3.3V       3V         3.49V
2.1ns     3.17V      3V         2.1V
2.4ns     2.87V      3V         1.41V
2.7ns     2.32V      2.96V      1.01V
3ns       1.67V      2.84V      900mV
3.6ns     1.12V      2.46V      860mV
4.8ns     1.02V      1.51V      840mV
5.4ns     1.01V      1.34V      840mV
15ns      1V         1.26V      830mV
[Falling Waveform]
R_fixture = 50.00
V_fixture = 0.000
V_fixture_min = 0.000
V_fixture_max = 0.000
| time   V(typ)   V(min)   V(max)
0s        2.14V      1.77V      2.44V
1.2ns     2.14V      1.77V      2.41V
1.5ns     2.14V      1.77V      1.54V
1.8ns     1.99V      1.77V      250mV
2.1ns     1.46V      1.77V      54.56mV
2.4ns     600mV      1.75V      27.68mV
2.7ns     150mV      1.65V      17.12mV
3.6ns     19.29mV    550mV      7.46mV
4.5ns     9.11mV     77.75mV    4.69mV
15ns      900uV      1.38mV     860uV
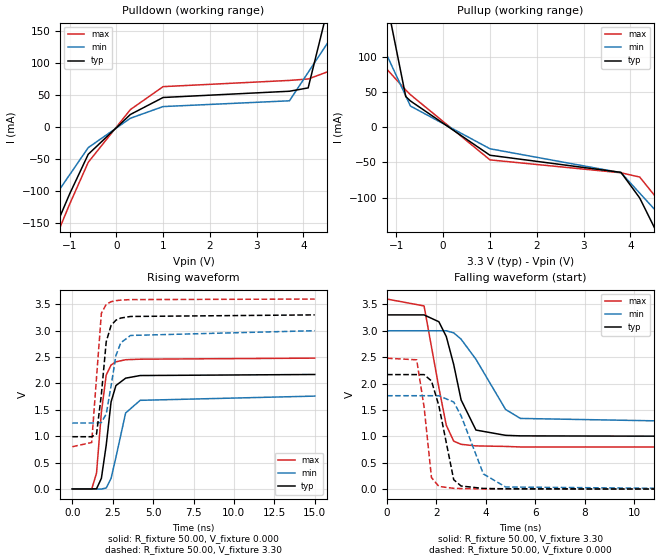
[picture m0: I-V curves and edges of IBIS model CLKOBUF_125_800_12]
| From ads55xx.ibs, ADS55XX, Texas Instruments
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|   Model CLKOBUF_125_800_12
[Model]   CLKOBUF_125_800_12
Model_type   Output
Polarity   Non-Inverting
Vmeas =   1.65V
C_comp   2pf   2pf   2pf
[Temperature Range]   50.00   0.10k   -20.00
[Voltage Range]   3.30V   3.00V   3.60V
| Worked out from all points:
|   slope of the pulldown table from 0 to 0.495 V, typ, clamps not added: 16.8 ohm
|   slope of the pullup table from 0 to 0.495 V, typ, clamps not added: 22 ohm
|   rising waveform, R_fixture 50.00, V_fixture 0.000: 20-80 % time 572ps typ, 757ps min, 475ps max; typ from 0 V to 2.17 V
|   rising waveform, R_fixture 50.00, V_fixture 3.30: 20-80 % time 482ps typ, 648ps min, 412ps max; typ from 0.99 V to 3.3 V
|   falling waveform, R_fixture 50.00, V_fixture 3.30: 20-80 % time 744ps typ, 1.33ns min, 650ps max; typ from 3.3 V to 1 V
|   falling waveform, R_fixture 50.00, V_fixture 0.000: 20-80 % time 553ps typ, 855ps min, 381ps max; typ from 2.17 V to 0.001 V
[Pulldown]
| voltage   I(typ)   I(min)   I(max)
-3.3V     -498.6mA   -319.5mA   -524.7mA
-1.9V     -258.7mA   -170.4mA   -278.8mA
-1.5V     -190.2mA   -127.8mA   -208.5mA
-1V       -104.6mA   -74.57mA   -120.6mA
-600mV    -42.36mA   -31.97mA   -54.87mA
300mV     19.71mA    13.85mA    27.33mA
1V        46.24mA    32.08mA    63.16mA
3.7V      55.99mA    41.08mA    72.87mA
4.1V      61.19mA    85.32mA    75.07mA
4.5V      179.6mA    129.6mA    85.88mA
4.9V      298mA      173.8mA    99.14mA
6.6V      801.2mA    361.8mA    155.5mA
[Pullup]
| voltage   I(typ)   I(min)   I(max)
-3.3V     873.9mA    402.8mA    235.9mA
-2.1V     475.3mA    230.7mA    148mA
-1.5V     275.9mA    144.7mA    104mA
-1V       109.8mA    73mA       67.34mA
-800mV    43.39mA    44.32mA    52.68mA
-700mV    37.18mA    29.98mA    46.08mA
1V        -39.91mA   -30.7mA    -46.48mA
3.8V      -64.21mA   -64.68mA   -64.82mA
4.2V      -100.6mA   -93.72mA   -70.87mA
4.7V      -167.6mA   -130mA     -112mA
5.1V      -221.2mA   -159.1mA   -144.9mA
6.6V      -422.2mA   -268mA     -268.1mA
[Ramp]
| variable   typ   min   max
dV/dt_r   1.30/0.50n   1.06/0.72n   1.49/0.45n
dV/dt_f   1.38/0.71n   1.05/1.31n   1.68/0.62n
R_load = 50.00
[Rising Waveform]
R_fixture = 50.00
V_fixture = 0.000
V_fixture_min = 0.000
V_fixture_max = 0.000
| time   V(typ)   V(min)   V(max)
0s        23.74nV    34.66nV    42.66nV
1.2ns     -5.47uV    600nV      -4.46mV
1.5ns     2.67mV     36.4uV     300mV
1.8ns     200mV      -2.54mV    1.45V
2.1ns     830mV      18.12mV    2.16V
2.4ns     1.65V      200mV      2.35V
2.7ns     1.96V      600mV      2.41V
3.3ns     2.1V       1.44V      2.45V
4.2ns     2.15V      1.68V      2.46V
15ns      2.17V      1.76V      2.48V
[Rising Waveform]
R_fixture = 50.00
V_fixture = 3.30
V_fixture_min = 3.00
V_fixture_max = 3.60
| time   V(typ)   V(min)   V(max)
0s        990mV      1.25V      800mV
1.2ns     990mV      1.25V      880mV
1.5ns     1.04V      1.25V      2.11V
1.8ns     1.79V      1.26V      3.33V
2.1ns     2.79V      1.42V      3.5V
2.4ns     3.1V       1.95V      3.55V
2.7ns     3.2V       2.53V      3.57V
3ns       3.24V      2.77V      3.58V
3.6ns     3.27V      2.91V      3.59V
15ns      3.3V       3V         3.6V
[Falling Waveform]
R_fixture = 50.00
V_fixture = 3.30
V_fixture_min = 3.00
V_fixture_max = 3.60
| time   V(typ)   V(min)   V(max)
0s        3.3V       3V         3.6V
1.5ns     3.3V       3V         3.47V
2.1ns     3.17V      3V         1.92V
2.4ns     2.89V      3V         1.21V
2.7ns     2.36V      2.96V      910mV
3ns       1.69V      2.84V      850mV
3.6ns     1.12V      2.46V      820mV
4.8ns     1.02V      1.51V      810mV
5.4ns     1.01V      1.34V      800mV
15ns      1V         1.26V      800mV
[Falling Waveform]
R_fixture = 50.00
V_fixture = 0.000
V_fixture_min = 0.000
V_fixture_max = 0.000
| time   V(typ)   V(min)   V(max)
0s        2.17V      1.77V      2.48V
1.2ns     2.17V      1.77V      2.45V
1.5ns     2.17V      1.77V      1.56V
1.8ns     2.05V      1.77V      220mV
2.1ns     1.58V      1.77V      52.2mV
2.7ns     180mV      1.65V      16.45mV
3ns       60.71mV    1.39V      11.72mV
3.9ns     14.67mV    290mV      6.18mV
4.8ns     7.77mV     41.86mV    4.11mV
15ns      900uV      1.38mV     840uV
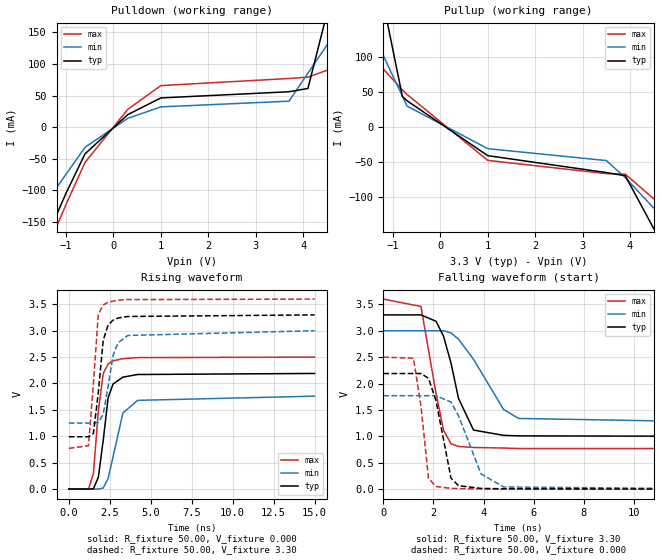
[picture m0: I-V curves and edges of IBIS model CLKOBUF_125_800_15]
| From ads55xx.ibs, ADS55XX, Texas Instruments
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|   Model CLKOBUF_125_800_15
[Model]   CLKOBUF_125_800_15
Model_type   Output
Polarity   Non-Inverting
Vmeas =   1.65V
C_comp   2pf   2pf   2pf
[Temperature Range]   50.00   0.10k   -20.00
[Voltage Range]   3.30V   3.00V   3.60V
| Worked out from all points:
|   slope of the pulldown table from 0 to 0.495 V, typ, clamps not added: 16.8 ohm
|   slope of the pullup table from 0 to 0.495 V, typ, clamps not added: 21.7 ohm
|   rising waveform, R_fixture 50.00, V_fixture 0.000: 20-80 % time 532ps typ, 760ps min, 467ps max; typ from 0 V to 2.19 V
|   rising waveform, R_fixture 50.00, V_fixture 3.30: 20-80 % time 464ps typ, 648ps min, 405ps max; typ from 0.99 V to 3.3 V
|   falling waveform, R_fixture 50.00, V_fixture 3.30: 20-80 % time 750ps typ, 1.33ns min, 635ps max; typ from 3.3 V to 1 V
|   falling waveform, R_fixture 50.00, V_fixture 0.000: 20-80 % time 535ps typ, 855ps min, 376ps max; typ from 2.19 V to 0.001 V
[Pulldown]
| voltage   I(typ)   I(min)   I(max)
-3.3V     -498.6mA   -319.5mA   -530.2mA
-1.9V     -258.7mA   -170.4mA   -281.9mA
-1.5V     -190.2mA   -127.8mA   -211mA
-1V       -104.6mA   -74.57mA   -122.4mA
-600mV    -42.36mA   -31.97mA   -55.96mA
300mV     19.71mA    13.85mA    27.99mA
1V        46.24mA    32.08mA    65.76mA
3.7V      56mA       41.08mA    76.97mA
4.1V      61.19mA    85.32mA    79.15mA
4.5V      179.6mA    129.6mA    89.93mA
4.9V      298mA      173.8mA    103.2mA
6.6V      801.2mA    361.8mA    159.3mA
[Pullup]
| voltage   I(typ)   I(min)   I(max)
-3.3V     875.5mA    402.8mA    237.7mA
-2.1V     476.3mA    230.7mA    149.1mA
-1.5V     276.7mA    144.7mA    104.8mA
-1V       110.3mA    73mA       67.91mA
-800mV    43.8mA     44.32mA    53.15mA
-700mV    37.55mA    29.98mA    46.49mA
1V        -40.68mA   -30.7mA    -47.44mA
3.5V      -64.78mA   -47.67mA   -66.27mA
3.9V      -69.33mA   -71.94mA   -67.09mA
4.7V      -169.9mA   -130mA     -114mA
5.3V      -250.4mA   -173.6mA   -163.3mA
6.6V      -424.9mA   -268mA     -270.2mA
[Ramp]
| variable   typ   min   max
dV/dt_r   1.31/0.49n   1.06/0.72n   1.50/0.44n
dV/dt_f   1.38/0.70n   1.05/1.31n   1.70/0.60n
R_load = 50.00
[Rising Waveform]
R_fixture = 50.00
V_fixture = 0.000
V_fixture_min = 0.000
V_fixture_max = 0.000
| time   V(typ)   V(min)   V(max)
0s        23.84nV    34.66nV    42.08nV
1.2ns     -5.45uV    590nV      -3.4mV
1.5ns     3.77mV     36.4uV     290mV
1.8ns     220mV      -2.54mV    1.47V
2.1ns     920mV      18.16mV    2.19V
2.4ns     1.73V      200mV      2.37V
2.7ns     1.99V      610mV      2.43V
3.3ns     2.12V      1.44V      2.47V
4.2ns     2.17V      1.68V      2.49V
15ns      2.19V      1.76V      2.5V
[Rising Waveform]
R_fixture = 50.00
V_fixture = 3.30
V_fixture_min = 3.00
V_fixture_max = 3.60
| time   V(typ)   V(min)   V(max)
0s        990mV      1.25V      770mV
1.2ns     990mV      1.25V      820mV
1.5ns     1.05V      1.25V      1.99V
1.8ns     1.83V      1.26V      3.31V
2.1ns     2.82V      1.42V      3.49V
2.4ns     3.11V      1.95V      3.54V
2.7ns     3.2V       2.53V      3.56V
3ns       3.24V      2.77V      3.58V
3.6ns     3.27V      2.91V      3.59V
15ns      3.3V       3V         3.6V
[Falling Waveform]
R_fixture = 50.00
V_fixture = 3.30
V_fixture_min = 3.00
V_fixture_max = 3.60
| time   V(typ)   V(min)   V(max)
0s        3.3V       3V         3.6V
1.5ns     3.3V       3V         3.46V
2.1ns     3.18V      3V         1.82V
2.4ns     2.9V       3V         1.12V
2.7ns     2.39V      2.96V      860mV
3ns       1.72V      2.84V      810mV
3.6ns     1.12V      2.46V      790mV
4.8ns     1.02V      1.51V      780mV
5.4ns     1.01V      1.34V      770mV
15ns      1V         1.26V      770mV
[Falling Waveform]
R_fixture = 50.00
V_fixture = 0.000
V_fixture_min = 0.000
V_fixture_max = 0.000
| time   V(typ)   V(min)   V(max)
0s        2.19V      1.77V      2.5V
1.2ns     2.19V      1.77V      2.48V
1.5ns     2.19V      1.77V      1.58V
1.8ns     2.1V       1.77V      210mV
2.1ns     1.68V      1.77V      50.65mV
2.7ns     210mV      1.65V      16.2mV
3ns       67.02mV    1.39V      11.61mV
3.9ns     15.01mV    290mV      6.09mV
4.8ns     7.88mV     41.87mV    4.04mV
15ns      910uV      1.38mV     830uV
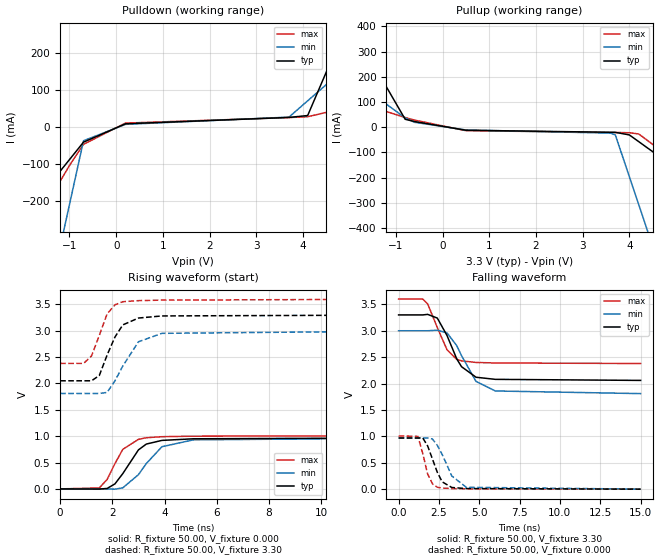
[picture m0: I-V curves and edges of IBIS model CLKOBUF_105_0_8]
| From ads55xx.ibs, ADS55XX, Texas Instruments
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|   Model CLKOBUF_105_0_8
[Model]   CLKOBUF_105_0_8
Model_type   Output
Polarity   Non-Inverting
Vmeas =   1.65V
C_comp   2pf   2pf   2pf
[Temperature Range]   50.00   0.10k   -20.00
[Voltage Range]   3.30V   3.00V   3.60V
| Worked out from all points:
|   slope of the pulldown table from 0 to 0.495 V, typ, clamps not added: 27.8 ohm
|   slope of the pullup table from 0 to 0.495 V, typ, clamps not added: 40.6 ohm
|   rising waveform, R_fixture 50.00, V_fixture 0.000: 20-80 % time 846ps typ, 987ps min, 702ps max; typ from 0 V to 0.97 V
|   rising waveform, R_fixture 50.00, V_fixture 3.30: 20-80 % time 706ps typ, 856ps min, 584ps max; typ from 2.05 V to 3.3 V
|   falling waveform, R_fixture 50.00, V_fixture 3.30: 20-80 % time 1.15ns typ, 1.27ns min, 1ns max; typ from 3.3 V to 2.06 V
|   falling waveform, R_fixture 50.00, V_fixture 0.000: 20-80 % time 756ps typ, 932ps min, 563ps max; typ from 0.97 V to 0.001 V
[Pulldown]
| voltage   I(typ)   I(min)   I(max)
-3.3V     -450.8mA   -1.537A    -592.5mA
-2.1V     -261.6mA   -844.6mA   -337.7mA
-1.7V     -198.5mA   -613.8mA   -252.8mA
-1.5V     -166.9mA   -498.5mA   -210.4mA
-1V       -88.08mA   -210mA     -104.2mA
-700mV    -40.77mA   -36.93mA   -46.67mA
200mV     9.12mA     7.6mA      10.98mA
3.7V      26.36mA    27.26mA    26.04mA
4.1V      31.52mA    71.46mA    28.25mA
4.9V      268.3mA    159.9mA    51.99mA
5.9V      564.3mA    270.4mA    84.64mA
6.6V      771.5mA    347.7mA    107.5mA
[Pullup]
| voltage   I(typ)   I(min)   I(max)
-3.3V     830.5mA    375mA      185.7mA
-2.3V     510.8mA    239.7mA    126.7mA
-2.1V     446.8mA    212.6mA    114.8mA
-800mV    31.22mA    36.74mA    38.15mA
-600mV    22.2mA     19.22mA    27.98mA
500mV     -12.3mA    -11.31mA   -14.01mA
3.6V      -20.42mA   -23.73mA   -21.15mA
3.7V      -20.63mA   -30.91mA   -21.24mA
4V        -30.83mA   -196.5mA   -22.11mA
4.2V      -57.43mA   -306.9mA   -27.05mA
4.5V      -97.33mA   -472.5mA   -68.34mA
6.6V      -376.6mA   -1.632A    -416.4mA
[Ramp]
| variable   typ   min   max
dV/dt_r   0.58/0.80n   0.58/0.96n   0.60/0.67n
dV/dt_f   0.75/1.14n   0.71/1.24n   0.73/0.97n
R_load = 50.00
[Rising Waveform]
R_fixture = 50.00
V_fixture = 0.000
V_fixture_min = 0.000
V_fixture_max = 0.000
| time   V(typ)   V(min)   V(max)
0s        29.42nV    38.19nV    59.23nV
1.5ns     -3.04mV    37.06uV    18.53mV
1.8ns     8.64mV     -2.14mV    180mV
2.1ns     95.66mV    -4.97mV    480mV
2.4ns     290mV      19.79mV    750mV
3ns       740mV      270mV      940mV
3.3ns     850mV      480mV      970mV
3.9ns     920mV      800mV      990mV
5.1ns     950mV      930mV      1V
15ns      970mV      970mV      1.01V
[Rising Waveform]
R_fixture = 50.00
V_fixture = 3.30
V_fixture_min = 3.00
V_fixture_max = 3.60
| time   V(typ)   V(min)   V(max)
0s        2.05V      1.81V      2.38V
900ps     2.05V      1.81V      2.38V
1.2ns     2.05V      1.81V      2.52V
1.5ns     2.15V      1.81V      2.91V
1.8ns     2.54V      1.83V      3.32V
2.1ns     2.88V      2.05V      3.49V
2.4ns     3.11V      2.33V      3.55V
3ns       3.24V      2.79V      3.57V
3.9ns     3.28V      2.95V      3.58V
15ns      3.3V       3V         3.6V
[Falling Waveform]
R_fixture = 50.00
V_fixture = 3.30
V_fixture_min = 3.00
V_fixture_max = 3.60
| time   V(typ)   V(min)   V(max)
0s        3.3V       3V         3.6V
1.5ns     3.3V       3V         3.6V
1.8ns     3.31V      3V         3.51V
2.4ns     3.24V      3.01V      3.06V
3ns       2.91V      2.96V      2.64V
3.6ns     2.47V      2.72V      2.46V
3.9ns     2.32V      2.53V      2.43V
4.8ns     2.12V      2.04V      2.4V
6ns       2.08V      1.86V      2.39V
15ns      2.06V      1.81V      2.38V
[Falling Waveform]
R_fixture = 50.00
V_fixture = 0.000
V_fixture_min = 0.000
V_fixture_max = 0.000
| time   V(typ)   V(min)   V(max)
0s        970mV      970mV      1.01V
1.2ns     970mV      970mV      1V
1.5ns     970mV      970mV      670mV
1.8ns     820mV      970mV      290mV
2.1ns     570mV      950mV      100mV
2.4ns     320mV      830mV      37.92mV
2.7ns     140mV      660mV      22.68mV
3.3ns     32.66mV    250mV      12.1mV
4.2ns     12.85mV    36.53mV    7.08mV
15ns      1.17mV     1.48mV     1.21mV
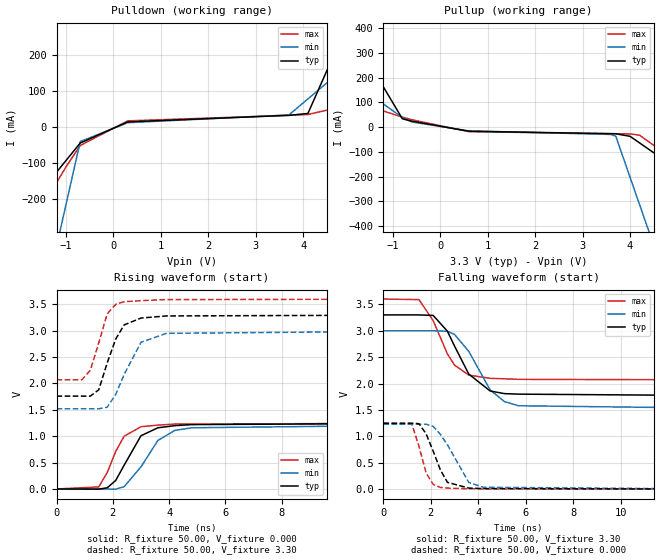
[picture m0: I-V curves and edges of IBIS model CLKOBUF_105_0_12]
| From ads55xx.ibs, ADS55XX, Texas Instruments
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|   Model CLKOBUF_105_0_12
[Model]   CLKOBUF_105_0_12
Model_type   Output
Polarity   Non-Inverting
Vmeas =   1.65V
C_comp   2pf   2pf   2pf
[Temperature Range]   50.00   0.10k   -20.00
[Voltage Range]   3.30V   3.00V   3.60V
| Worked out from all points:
|   slope of the pulldown table from 0 to 0.495 V, typ, clamps not added: 23.8 ohm
|   slope of the pullup table from 0 to 0.495 V, typ, clamps not added: 34.5 ohm
|   rising waveform, R_fixture 50.00, V_fixture 0.000: 20-80 % time 793ps typ, 960ps min, 666ps max; typ from 0 V to 1.25 V
|   rising waveform, R_fixture 50.00, V_fixture 3.30: 20-80 % time 658ps typ, 776ps min, 513ps max; typ from 1.76 V to 3.3 V
|   falling waveform, R_fixture 50.00, V_fixture 3.30: 20-80 % time 1.1ns typ, 1.17ns min, 983ps max; typ from 3.3 V to 1.77 V
|   falling waveform, R_fixture 50.00, V_fixture 0.000: 20-80 % time 704ps typ, 910ps min, 517ps max; typ from 1.25 V to 0.001 V
[Pulldown]
| voltage   I(typ)   I(min)   I(max)
-3.3V     -462.8mA   -1.548A    -610.3mA
-2.1V     -269.5mA   -851.9mA   -349.2mA
-1.7V     -205mA     -619.9mA   -262.2mA
-1.5V     -172.8mA   -503.9mA   -218.7mA
-1V       -92.25mA   -213.8mA   -109.9mA
-700mV    -43.92mA   -39.8mA    -50.76mA
300mV     14.49mA    12.29mA    17.37mA
3.7V      32.61mA    33.77mA    32.69mA
4.1V      37.8mA     78.01mA    34.94mA
4.9V      274.6mA    166.5mA    58.94mA
5.9V      570.6mA    277.1mA    91.94mA
6.6V      777.8mA    354.5mA    115mA
[Pullup]
| voltage   I(typ)   I(min)   I(max)
-3.3V     839.2mA    382.9mA    193.9mA
-2.3V     517mA      245.3mA    132.6mA
-2.1V     452.6mA    217.7mA    120.3mA
-800mV    33.74mA    38.86mA    40.65mA
-600mV    24.18mA    20.88mA    29.97mA
600mV     -16.54mA   -15.07mA   -18.32mA
3.6V      -26.61mA   -29.64mA   -26.4mA
3.7V      -26.84mA   -36.83mA   -26.5mA
4V        -37.09mA   -202.5mA   -27.4mA
4.2V      -63.71mA   -312.9mA   -32.36mA
4.5V      -103.6mA   -478.5mA   -73.69mA
6.6V      -383.1mA   -1.638A    -422mA
[Ramp]
| variable   typ   min   max
dV/dt_r   0.75/0.76n   0.73/0.92n   0.75/0.64n
dV/dt_f   0.92/1.07n   0.88/1.15n   0.92/0.95n
R_load = 50.00
[Rising Waveform]
R_fixture = 50.00
V_fixture = 0.000
V_fixture_min = 0.000
V_fixture_max = 0.000
| time   V(typ)   V(min)   V(max)
0s        27.36nV    35.59nV    54.3nV
1.5ns     -3.41mV    28.81uV    38.88mV
1.8ns     22.26mV    -2.29mV    310mV
2.1ns     160mV      -3.83mV    710mV
2.4ns     450mV      42.6mV     1V
3ns       1.01V      420mV      1.18V
3.6ns     1.16V      920mV      1.21V
4.2ns     1.2V       1.11V      1.23V
4.8ns     1.22V      1.16V      1.23V
15ns      1.25V      1.22V      1.25V
[Rising Waveform]
R_fixture = 50.00
V_fixture = 3.30
V_fixture_min = 3.00
V_fixture_max = 3.60
| time   V(typ)   V(min)   V(max)
0s        1.76V      1.52V      2.07V
900ps     1.76V      1.52V      2.07V
1.2ns     1.76V      1.52V      2.25V
1.5ns     1.88V      1.52V      2.77V
1.8ns     2.39V      1.55V      3.32V
2.1ns     2.84V      1.79V      3.5V
2.4ns     3.11V      2.17V      3.55V
3ns       3.24V      2.78V      3.57V
3.9ns     3.28V      2.95V      3.59V
15ns      3.3V       3V         3.6V
[Falling Waveform]
R_fixture = 50.00
V_fixture = 3.30
V_fixture_min = 3.00
V_fixture_max = 3.60
| time   V(typ)   V(min)   V(max)
0s        3.3V       3V         3.6V
1.5ns     3.3V       3V         3.59V
2.1ns     3.29V      3V         3.19V
2.7ns     2.99V      2.99V      2.56V
3ns       2.71V      2.93V      2.35V
3.6ns     2.18V      2.61V      2.16V
4.5ns     1.86V      1.88V      2.1V
5.1ns     1.81V      1.66V      2.09V
5.7ns     1.8V       1.58V      2.08V
15ns      1.77V      1.53V      2.07V
[Falling Waveform]
R_fixture = 50.00
V_fixture = 0.000
V_fixture_min = 0.000
V_fixture_max = 0.000
| time   V(typ)   V(min)   V(max)
0s        1.25V      1.23V      1.25V
1.2ns     1.25V      1.23V      1.23V
1.5ns     1.24V      1.23V      810mV
1.8ns     1.05V      1.23V      310mV
2.1ns     720mV      1.19V      91.14mV
2.4ns     370mV      1.04V      34.23mV
2.7ns     130mV      840mV      21.47mV
3.6ns     21.54mV    130mV      9.02mV
4.2ns     12.22mV    36.91mV    6.56mV
15ns      1.08mV     1.37mV     1.1mV
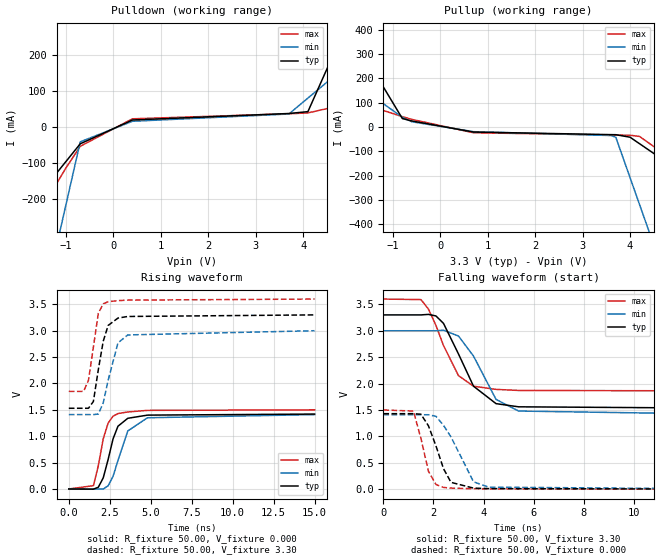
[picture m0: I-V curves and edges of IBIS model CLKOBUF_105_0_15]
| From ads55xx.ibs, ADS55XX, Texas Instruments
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|   Model CLKOBUF_105_0_15
[Model]   CLKOBUF_105_0_15
Model_type   Output
Polarity   Non-Inverting
Vmeas =   1.65V
C_comp   2pf   2pf   2pf
[Temperature Range]   50.00   0.10k   -20.00
[Voltage Range]   3.30V   3.00V   3.60V
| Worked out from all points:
|   slope of the pulldown table from 0 to 0.495 V, typ, clamps not added: 21.4 ohm
|   slope of the pullup table from 0 to 0.495 V, typ, clamps not added: 31.7 ohm
|   rising waveform, R_fixture 50.00, V_fixture 0.000: 20-80 % time 769ps typ, 923ps min, 661ps max; typ from 0 V to 1.42 V
|   rising waveform, R_fixture 50.00, V_fixture 3.30: 20-80 % time 634ps typ, 726ps min, 496ps max; typ from 1.53 V to 3.3 V
|   falling waveform, R_fixture 50.00, V_fixture 3.30: 20-80 % time 1.07ns typ, 1.08ns min, 975ps max; typ from 3.3 V to 1.53 V
|   falling waveform, R_fixture 50.00, V_fixture 0.000: 20-80 % time 675ps typ, 874ps min, 485ps max; typ from 1.43 V to 0.001 V
[Pulldown]
| voltage   I(typ)   I(min)   I(max)
-3.3V     -472mA     -1.552A    -621.4mA
-2.1V     -275.5mA   -854.8mA   -356.3mA
-1.7V     -210.1mA   -622.2mA   -268mA
-1.5V     -177.3mA   -506mA     -223.8mA
-1V       -95.46mA   -215.3mA   -113.3mA
-700mV    -46.35mA   -40.94mA   -53.31mA
400mV     19.87mA    16.32mA    23.19mA
3.7V      37.96mA    36.61mA    37.27mA
4.1V      43.14mA    80.85mA    39.55mA
4.9V      280mA      169.3mA    63.65mA
5.9V      576.1mA    279.9mA    96.8mA
6.6V      783.4mA    357.4mA    120mA
[Pullup]
| voltage   I(typ)   I(min)   I(max)
-3.3V     844.5mA    388.4mA    202mA
-2.3V     520.8mA    249.2mA    138.4mA
-2.1V     456.1mA    221.3mA    125.7mA
-800mV    35.24mA    40.36mA    43.04mA
-600mV    25.36mA    22.06mA    31.87mA
700mV     -20.18mA   -18.65mA   -23.11mA
3.6V      -30.85mA   -34.45mA   -32.16mA
3.7V      -31.09mA   -41.65mA   -32.28mA
4V        -41.37mA   -207.3mA   -33.21mA
4.2V      -68.01mA   -317.8mA   -38.19mA
4.5V      -108mA     -483.5mA   -79.55mA
6.6V      -387.7mA   -1.643A    -428mA
[Ramp]
| variable   typ   min   max
dV/dt_r   0.85/0.73n   0.85/0.89n   0.90/0.61n
dV/dt_f   1.06/1.04n   0.95/1.05n   1.05/0.95n
R_load = 50.00
[Rising Waveform]
R_fixture = 50.00
V_fixture = 0.000
V_fixture_min = 0.000
V_fixture_max = 0.000
| time   V(typ)   V(min)   V(max)
0s        26nV       34.8nV     51.84nV
1.5ns     -3.53mV    28.8uV     62.9mV
1.8ns     33.37mV    -2.08mV    440mV
2.1ns     210mV      -2.01mV    950mV
2.4ns     560mV      61.11mV    1.25V
2.7ns     950mV      240mV      1.38V
3ns       1.19V      540mV      1.43V
3.6ns     1.34V      1.1V       1.46V
4.8ns     1.4V       1.35V      1.49V
15ns      1.42V      1.41V      1.5V
[Rising Waveform]
R_fixture = 50.00
V_fixture = 3.30
V_fixture_min = 3.00
V_fixture_max = 3.60
| time   V(typ)   V(min)   V(max)
0s        1.53V      1.41V      1.85V
900ps     1.53V      1.41V      1.85V
1.2ns     1.53V      1.41V      2.06V
1.5ns     1.66V      1.41V      2.69V
1.8ns     2.26V      1.42V      3.33V
2.1ns     2.8V       1.63V      3.51V
2.4ns     3.1V       2.06V      3.55V
3ns       3.24V      2.77V      3.57V
3.6ns     3.27V      2.92V      3.58V
15ns      3.3V       3V         3.6V
[Falling Waveform]
R_fixture = 50.00
V_fixture = 3.30
V_fixture_min = 3.00
V_fixture_max = 3.60
| time   V(typ)   V(min)   V(max)
0s        3.3V       3V         3.6V
1.5ns     3.3V       3V         3.59V
1.8ns     3.31V      3V         3.41V
2.1ns     3.28V      3V         3.1V
2.4ns     3.14V      3.01V      2.72V
3ns       2.56V      2.9V       2.15V
3.6ns     1.95V      2.52V      1.95V
4.5ns     1.62V      1.7V       1.89V
5.4ns     1.56V      1.48V      1.87V
15ns      1.53V      1.41V      1.86V
[Falling Waveform]
R_fixture = 50.00
V_fixture = 0.000
V_fixture_min = 0.000
V_fixture_max = 0.000
| time   V(typ)   V(min)   V(max)
0s        1.43V      1.41V      1.5V
1.2ns     1.43V      1.41V      1.48V
1.5ns     1.42V      1.41V      960mV
1.8ns     1.2V       1.41V      340mV
2.1ns     820mV      1.38V      88.69mV
2.4ns     390mV      1.21V      34.05mV
2.7ns     130mV      990mV      21.31mV
3.6ns     20.84mV    140mV      8.79mV
4.2ns     11.74mV    39.4mV     6.34mV
15ns      1.02mV     1.34mV     1.05mV
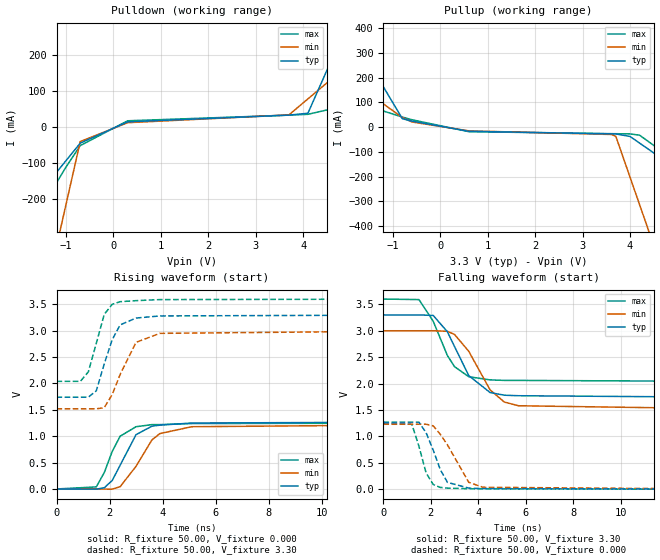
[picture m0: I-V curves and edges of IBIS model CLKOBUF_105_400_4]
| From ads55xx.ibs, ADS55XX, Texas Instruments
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|   Model CLKOBUF_105_400_4
[Model]   CLKOBUF_105_400_4
Model_type   Output
Polarity   Non-Inverting
Vmeas =   1.65V
C_comp   2pf   2pf   2pf
[Temperature Range]   50.00   0.10k   -20.00
[Voltage Range]   3.30V   3.00V   3.60V
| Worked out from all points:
|   slope of the pulldown table from 0 to 0.495 V, typ, clamps not added: 23.4 ohm
|   slope of the pullup table from 0 to 0.495 V, typ, clamps not added: 34 ohm
|   rising waveform, R_fixture 50.00, V_fixture 0.000: 20-80 % time 784ps typ, 947ps min, 666ps max; typ from 0 V to 1.27 V
|   rising waveform, R_fixture 50.00, V_fixture 3.30: 20-80 % time 656ps typ, 776ps min, 515ps max; typ from 1.74 V to 3.3 V
|   falling waveform, R_fixture 50.00, V_fixture 3.30: 20-80 % time 1.1ns typ, 1.19ns min, 974ps max; typ from 3.3 V to 1.74 V
|   falling waveform, R_fixture 50.00, V_fixture 0.000: 20-80 % time 695ps typ, 910ps min, 516ps max; typ from 1.27 V to 0.001 V
[Pulldown]
| voltage   I(typ)   I(min)   I(max)
-3.3V     -463.9mA   -1.548A    -611.7mA
-2.1V     -270.2mA   -852mA     -350.1mA
-1.7V     -205.6mA   -619.9mA   -262.9mA
-1.5V     -173.3mA   -503.9mA   -219.3mA
-1V       -92.64mA   -213.9mA   -110.3mA
-700mV    -44.22mA   -39.84mA   -51.08mA
300mV     14.66mA    12.31mA    17.57mA
3.7V      33.25mA    33.86mA    33.24mA
4.1V      38.43mA    78.1mA     35.49mA
4.9V      275.3mA    166.6mA    59.49mA
5.9V      571.4mA    277.2mA    92.49mA
6.6V      778.7mA    354.6mA    115.6mA
[Pullup]
| voltage   I(typ)   I(min)   I(max)
-3.3V     840mA      382.9mA    193.9mA
-2.3V     517.6mA    245.3mA    132.6mA
-2.1V     453.1mA    217.7mA    120.4mA
-800mV    33.96mA    38.87mA    40.68mA
-600mV    24.36mA    20.89mA    29.99mA
600mV     -16.77mA   -15.07mA   -18.35mA
3.6V      -27.21mA   -29.65mA   -26.46mA
3.7V      -27.44mA   -36.84mA   -26.57mA
4V        -37.69mA   -202.5mA   -27.47mA
4.2V      -64.33mA   -312.9mA   -32.43mA
4.5V      -104.3mA   -478.6mA   -73.76mA
6.6V      -384mA     -1.638A    -422.1mA
[Ramp]
| variable   typ   min   max
dV/dt_r   0.76/0.76n   0.73/0.92n   0.75/0.64n
dV/dt_f   0.94/1.07n   0.89/1.15n   0.93/0.95n
R_load = 50.00
[Rising Waveform]
R_fixture = 50.00
V_fixture = 0.000
V_fixture_min = 0.000
V_fixture_max = 0.000
| time   V(typ)   V(min)   V(max)
0s        27.16nV    35.58nV    53.94nV
1.5ns     -3.42mV    28.69uV    38.98mV
1.8ns     22.42mV    -2.3mV     310mV
2.1ns     160mV      -3.72mV    710mV
2.4ns     450mV      44.02mV    1V
3ns       1.03V      430mV      1.18V
3.6ns     1.19V      930mV      1.22V
3.9ns     1.21V      1.05V      1.22V
5.1ns     1.25V      1.18V      1.24V
15ns      1.27V      1.22V      1.25V
[Rising Waveform]
R_fixture = 50.00
V_fixture = 3.30
V_fixture_min = 3.00
V_fixture_max = 3.60
| time   V(typ)   V(min)   V(max)
0s        1.74V      1.52V      2.04V
900ps     1.74V      1.52V      2.04V
1.2ns     1.74V      1.52V      2.22V
1.5ns     1.86V      1.52V      2.76V
1.8ns     2.37V      1.54V      3.31V
2.1ns     2.83V      1.79V      3.5V
2.4ns     3.11V      2.17V      3.55V
3ns       3.24V      2.78V      3.57V
3.9ns     3.28V      2.95V      3.59V
15ns      3.3V       3V         3.6V
[Falling Waveform]
R_fixture = 50.00
V_fixture = 3.30
V_fixture_min = 3.00
V_fixture_max = 3.60
| time   V(typ)   V(min)   V(max)
0s        3.3V       3V         3.6V
1.5ns     3.3V       3V         3.59V
2.1ns     3.29V      3V         3.18V
2.7ns     2.98V      2.99V      2.53V
3ns       2.7V       2.93V      2.32V
3.6ns     2.15V      2.61V      2.13V
4.5ns     1.83V      1.88V      2.07V
5.1ns     1.78V      1.65V      2.06V
5.7ns     1.77V      1.58V      2.06V
15ns      1.74V      1.52V      2.04V
[Falling Waveform]
R_fixture = 50.00
V_fixture = 0.000
V_fixture_min = 0.000
V_fixture_max = 0.000
| time   V(typ)   V(min)   V(max)
0s        1.27V      1.23V      1.25V
1.2ns     1.27V      1.23V      1.23V
1.5ns     1.27V      1.23V      810mV
1.8ns     1.07V      1.23V      310mV
2.1ns     740mV      1.2V       89.04mV
2.4ns     370mV      1.04V      33.78mV
2.7ns     130mV      840mV      21.27mV
3.6ns     21.44mV    130mV      8.95mV
4.2ns     12.16mV    36.85mV    6.51mV
15ns      1.07mV     1.37mV     1.1mV
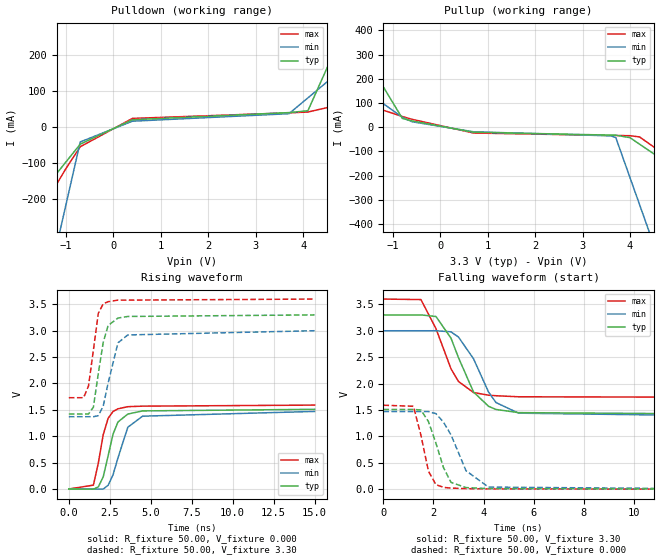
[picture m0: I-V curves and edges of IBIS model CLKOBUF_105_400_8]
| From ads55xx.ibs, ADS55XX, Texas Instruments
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|   Model CLKOBUF_105_400_8
[Model]   CLKOBUF_105_400_8
Model_type   Output
Polarity   Non-Inverting
Vmeas =   1.65V
C_comp   2pf   2pf   2pf
[Temperature Range]   50.00   0.10k   -20.00
[Voltage Range]   3.30V   3.00V   3.60V
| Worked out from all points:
|   slope of the pulldown table from 0 to 0.495 V, typ, clamps not added: 20.5 ohm
|   slope of the pullup table from 0 to 0.495 V, typ, clamps not added: 30.5 ohm
|   rising waveform, R_fixture 50.00, V_fixture 0.000: 20-80 % time 765ps typ, 892ps min, 658ps max; typ from 0 V to 1.51 V
|   rising waveform, R_fixture 50.00, V_fixture 3.30: 20-80 % time 620ps typ, 703ps min, 487ps max; typ from 1.42 V to 3.3 V
|   falling waveform, R_fixture 50.00, V_fixture 3.30: 20-80 % time 1.05ns typ, 1.05ns min, 971ps max; typ from 3.3 V to 1.42 V
|   falling waveform, R_fixture 50.00, V_fixture 0.000: 20-80 % time 662ps typ, 865ps min, 463ps max; typ from 1.51 V to 0.001 V
[Pulldown]
| voltage   I(typ)   I(min)   I(max)
-3.3V     -476.2mA   -1.554A    -627.2mA
-2.1V     -278.3mA   -855.7mA   -360.1mA
-1.7V     -212.4mA   -623mA     -271mA
-1.5V     -179.4mA   -506.6mA   -226.5mA
-1V       -96.92mA   -215.8mA   -115.2mA
-700mV    -47.45mA   -41.29mA   -54.68mA
400mV     20.71mA    16.58mA    24.32mA
3.7V      40.54mA    37.51mA    39.9mA
4.1V      45.73mA    81.71mA    42.18mA
4.9V      282.6mA    170.1mA    66.32mA
5.9V      578.7mA    280.6mA    99.52mA
6.6V      786mA      358mA      122.8mA
[Pullup]
| voltage   I(typ)   I(min)   I(max)
-3.3V     846.9mA    390.1mA    204.9mA
-2.3V     522.5mA    250.4mA    140.5mA
-2.1V     457.7mA    222.4mA    127.6mA
-800mV    35.94mA    40.82mA    43.87mA
-600mV    25.91mA    22.41mA    32.53mA
700mV     -21.06mA   -19.19mA   -24.27mA
3.6V      -32.98mA   -36.03mA   -34.32mA
3.7V      -33.22mA   -43.24mA   -34.44mA
4V        -43.52mA   -209mA     -35.39mA
4.2V      -70.18mA   -319.4mA   -40.37mA
4.5V      -110.2mA   -485.2mA   -81.75mA
6.6V      -390.1mA   -1.645A    -430.5mA
[Ramp]
| variable   typ   min   max
dV/dt_r   0.91/0.72n   0.88/0.88n   0.96/0.60n
dV/dt_f   1.13/1.02n   0.97/1.03n   1.12/0.94n
R_load = 50.00
[Rising Waveform]
R_fixture = 50.00
V_fixture = 0.000
V_fixture_min = 0.000
V_fixture_max = 0.000
| time   V(typ)   V(min)   V(max)
0s        25.44nV    34.61nV    50.61nV
1.5ns     -3.53mV    29.89uV    72.67mV
1.8ns     39.47mV    -2.07mV    490mV
2.1ns     230mV      -820uV     1.03V
2.4ns     630mV      70.62mV    1.34V
2.7ns     1.04V      270mV      1.47V
3ns       1.27V      590mV      1.52V
3.6ns     1.42V      1.17V      1.56V
4.5ns     1.48V      1.38V      1.57V
15ns      1.51V      1.47V      1.59V
[Rising Waveform]
R_fixture = 50.00
V_fixture = 3.30
V_fixture_min = 3.00
V_fixture_max = 3.60
| time   V(typ)   V(min)   V(max)
0s        1.42V      1.37V      1.73V
900ps     1.42V      1.37V      1.73V
1.2ns     1.42V      1.37V      1.95V
1.5ns     1.55V      1.37V      2.63V
1.8ns     2.19V      1.39V      3.33V
2.1ns     2.78V      1.57V      3.51V
2.4ns     3.1V       2.01V      3.55V
3ns       3.24V      2.77V      3.58V
3.6ns     3.27V      2.92V      3.58V
15ns      3.3V       3V         3.6V
[Falling Waveform]
R_fixture = 50.00
V_fixture = 3.30
V_fixture_min = 3.00
V_fixture_max = 3.60
| time   V(typ)   V(min)   V(max)
0s        3.3V       3V         3.6V
1.5ns     3.3V       3V         3.59V
2.1ns     3.27V      3V         3.04V
2.7ns     2.86V      2.98V      2.28V
3ns       2.49V      2.88V      2.04V
3.6ns     1.84V      2.47V      1.83V
4.2ns     1.57V      1.84V      1.78V
4.5ns     1.51V      1.64V      1.77V
5.4ns     1.45V      1.44V      1.75V
15ns      1.42V      1.38V      1.74V
[Falling Waveform]
R_fixture = 50.00
V_fixture = 0.000
V_fixture_min = 0.000
V_fixture_max = 0.000
| time   V(typ)   V(min)   V(max)
0s        1.51V      1.47V      1.59V
1.2ns     1.51V      1.47V      1.57V
1.5ns     1.5V       1.47V      1.02V
1.8ns     1.28V      1.47V      340mV
2.1ns     870mV      1.43V      86.42mV
2.4ns     410mV      1.27V      35.1mV
2.7ns     130mV      1.03V      21.38mV
3.3ns     30.5mV     350mV      10.85mV
4.2ns     11.54mV    39.84mV    6.24mV
15ns      1mV        1.34mV     1.03mV
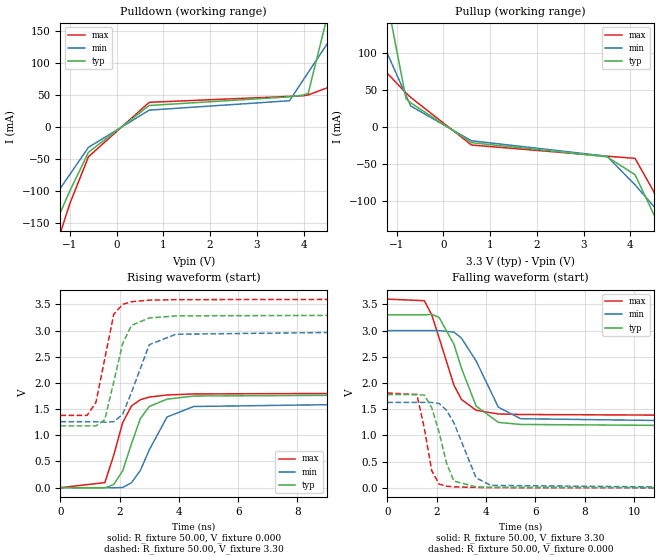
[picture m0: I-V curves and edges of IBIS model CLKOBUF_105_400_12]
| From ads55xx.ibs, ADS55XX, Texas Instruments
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|   Model CLKOBUF_105_400_12
[Model]   CLKOBUF_105_400_12
Model_type   Output
Polarity   Non-Inverting
Vmeas =   1.65V
C_comp   2pf   2pf   2pf
[Temperature Range]   50.00   0.10k   -20.00
[Voltage Range]   3.30V   3.00V   3.60V
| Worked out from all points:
|   slope of the pulldown table from 0 to 0.495 V, typ, clamps not added: 18.6 ohm
|   slope of the pullup table from 0 to 0.495 V, typ, clamps not added: 27.3 ohm
|   rising waveform, R_fixture 50.00, V_fixture 0.000: 20-80 % time 715ps typ, 848ps min, 643ps max; typ from 0 V to 1.78 V
|   rising waveform, R_fixture 50.00, V_fixture 3.30: 20-80 % time 581ps typ, 678ps min, 476ps max; typ from 1.18 V to 3.3 V
|   falling waveform, R_fixture 50.00, V_fixture 3.30: 20-80 % time 981ps typ, 1.07ns min, 953ps max; typ from 3.3 V to 1.18 V
|   falling waveform, R_fixture 50.00, V_fixture 0.000: 20-80 % time 632ps typ, 822ps min, 432ps max; typ from 1.78 V to 0.001 V
[Pulldown]
| voltage   I(typ)   I(min)   I(max)
-3.3V     -486.1mA   -319.8mA   -642.2mA
-1.9V     -251.3mA   -170.5mA   -324.5mA
-1.5V     -184.2mA   -127.9mA   -233.8mA
-1V       -100.4mA   -74.6mA    -120.3mA
-600mV    -39.63mA   -31.96mA   -46.63mA
700mV     33.56mA    26.33mA    38.59mA
3.7V      47.16mA    41.06mA    47.87mA
4V        50mA       74.24mA    48.89mA
4.1V      52.35mA    85.3mA     50.15mA
4.5V      170.8mA    129.5mA    61.05mA
4.9V      289.2mA    173.8mA    74.39mA
6.6V      792.6mA    361.8mA    131.1mA
[Pullup]
| voltage   I(typ)   I(min)   I(max)
-3.3V     854.9mA    395.9mA    211.5mA
-2.1V     462.9mA    226.2mA    131.9mA
-1.5V     266.9mA    141.4mA    92.16mA
-1V       103.5mA    70.69mA    59.01mA
-800mV    38.16mA    42.41mA    45.75mA
-700mV    32.51mA    28.27mA    39.87mA
600mV     -21.18mA   -18.62mA   -24.35mA
3.5V      -40.28mA   -39.5mA    -39.5mA
4.1V      -64.39mA   -78.11mA   -42.35mA
4.5V      -117.8mA   -107mA     -87.15mA
4.9V      -171.2mA   -135.9mA   -153.6mA
6.6V      -398.1mA   -258.9mA   -436mA
[Ramp]
| variable   typ   min   max
dV/dt_r   1.07/0.68n   0.98/0.82n   1.09/0.59n
dV/dt_f   1.27/0.95n   1.05/1.04n   1.33/0.93n
R_load = 50.00
[Rising Waveform]
R_fixture = 50.00
V_fixture = 0.000
V_fixture_min = 0.000
V_fixture_max = 0.000
| time   V(typ)   V(min)   V(max)
0s        24.3nV     33.78nV    47.59nV
1.5ns     -3.33mV    35.35uV    96.99mV
1.8ns     61.45mV    -2.05mV    620mV
2.1ns     320mV      3.14mV     1.24V
2.4ns     840mV      95.26mV    1.56V
2.7ns     1.32V      330mV      1.68V
3ns       1.55V      720mV      1.73V
3.6ns     1.69V      1.35V      1.77V
4.5ns     1.75V      1.55V      1.79V
15ns      1.78V      1.63V      1.81V
[Rising Waveform]
R_fixture = 50.00
V_fixture = 3.30
V_fixture_min = 3.00
V_fixture_max = 3.60
| time   V(typ)   V(min)   V(max)
0s        1.18V      1.26V      1.38V
900ps     1.18V      1.26V      1.38V
1.2ns     1.18V      1.26V      1.63V
1.5ns     1.3V       1.25V      2.47V
1.8ns     2.02V      1.26V      3.31V
2.1ns     2.75V      1.4V       3.5V
2.4ns     3.1V       1.82V      3.55V
3ns       3.24V      2.73V      3.58V
3.9ns     3.28V      2.93V      3.59V
15ns      3.3V       3V         3.6V
[Falling Waveform]
R_fixture = 50.00
V_fixture = 3.30
V_fixture_min = 3.00
V_fixture_max = 3.60
| time   V(typ)   V(min)   V(max)
0s        3.3V       3V         3.6V
1.5ns     3.3V       3V         3.57V
1.8ns     3.31V      3V         3.3V
2.1ns     3.25V      3V         2.86V
2.7ns     2.74V      2.97V      1.96V
3ns       2.29V      2.86V      1.69V
3.6ns     1.56V      2.42V      1.48V
4.5ns     1.25V      1.54V      1.41V
5.4ns     1.21V      1.32V      1.4V
15ns      1.18V      1.26V      1.38V
[Falling Waveform]
R_fixture = 50.00
V_fixture = 0.000
V_fixture_min = 0.000
V_fixture_max = 0.000
| time   V(typ)   V(min)   V(max)
0s        1.78V      1.63V      1.81V
1.2ns     1.78V      1.63V      1.78V
1.5ns     1.77V      1.63V      1.14V
1.8ns     1.53V      1.63V      330mV
2.1ns     1.06V      1.61V      71.77mV
2.4ns     470mV      1.48V      32.59mV
2.7ns     130mV      1.24V      20.03mV
3.6ns     20.03mV    190mV      8.2mV
4.2ns     11.21mV    47.53mV    5.91mV
15ns      950uV      1.3mV      960uV
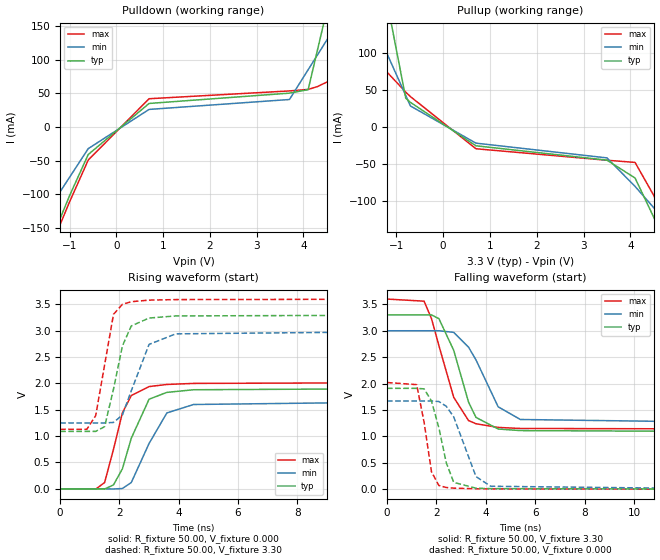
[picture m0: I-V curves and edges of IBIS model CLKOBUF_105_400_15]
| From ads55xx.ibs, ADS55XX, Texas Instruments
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|   Model CLKOBUF_105_400_15
[Model]   CLKOBUF_105_400_15
Model_type   Output
Polarity   Non-Inverting
Vmeas =   1.65V
C_comp   2pf   2pf   2pf
[Temperature Range]   50.00   0.10k   -20.00
[Voltage Range]   3.30V   3.00V   3.60V
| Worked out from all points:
|   slope of the pulldown table from 0 to 0.495 V, typ, clamps not added: 17.8 ohm
|   slope of the pullup table from 0 to 0.495 V, typ, clamps not added: 25.9 ohm
|   rising waveform, R_fixture 50.00, V_fixture 0.000: 20-80 % time 675ps typ, 814ps min, 625ps max; typ from 0 V to 1.91 V
|   rising waveform, R_fixture 50.00, V_fixture 3.30: 20-80 % time 568ps typ, 673ps min, 463ps max; typ from 1.09 V to 3.3 V
|   falling waveform, R_fixture 50.00, V_fixture 3.30: 20-80 % time 897ps typ, 1.09ns min, 940ps max; typ from 3.3 V to 1.09 V
|   falling waveform, R_fixture 50.00, V_fixture 0.000: 20-80 % time 612ps typ, 778ps min, 422ps max; typ from 1.91 V to 0.001 V
[Pulldown]
| voltage   I(typ)   I(min)   I(max)
-3.3V     -491mA     -319.8mA   -495.8mA
-1.7V     -220.4mA   -149.2mA   -228.3mA
-1.5V     -186.6mA   -127.9mA   -194.8mA
-1V       -102mA     -74.6mA    -111.2mA
-600mV    -40.71mA   -31.96mA   -48.88mA
700mV     35.19mA    26.33mA    42.21mA
3.7V      50.52mA    41.06mA    53.8mA
4.1V      55.71mA    85.3mA     56.07mA
4.3V      114.9mA    107.4mA    60.3mA
4.5V      174.1mA    129.5mA    66.97mA
4.7V      233.4mA    151.7mA    73.64mA
6.6V      796mA      361.8mA    137mA
[Pullup]
| voltage   I(typ)   I(min)   I(max)
-3.3V     859.4mA    397.7mA    217.5mA
-2.1V     465.8mA    227.4mA    135.9mA
-1.5V     269mA      142.3mA    95.11mA
-1V       105mA      71.34mA    61.11mA
-800mV    39.38mA    42.96mA    47.51mA
-700mV    33.6mA     28.77mA    41.45mA
700mV     -25.33mA   -21.73mA   -29.35mA
3.5V      -44.84mA   -41.76mA   -44.96mA
4.1V      -69.02mA   -80.42mA   -47.87mA
4.5V      -122.4mA   -109.4mA   -92.71mA
4.9V      -175.8mA   -138.3mA   -159.2mA
6.6V      -402.8mA   -261.4mA   -441.6mA
[Ramp]
| variable   typ   min   max
dV/dt_r   1.15/0.65n   1.00/0.76n   1.21/0.57n
dV/dt_f   1.32/0.85n   1.05/1.05n   1.48/0.91n
R_load = 50.00
[Rising Waveform]
R_fixture = 50.00
V_fixture = 0.000
V_fixture_min = 0.000
V_fixture_max = 0.000
| time   V(typ)   V(min)   V(max)
0s        23.84nV    34.03nV    45.92nV
1.2ns     -8.93uV    590nV      -5.88mV
1.5ns     -2.84mV    35.39uV    120mV
1.8ns     75.18mV    -2.19mV    750mV
2.1ns     380mV      6.5mV      1.44V
2.4ns     960mV      120mV      1.77V
3ns       1.7V       860mV      1.94V
3.6ns     1.83V      1.44V      1.98V
4.5ns     1.88V      1.6V       2V
15ns      1.91V      1.67V      2.02V
[Rising Waveform]
R_fixture = 50.00
V_fixture = 3.30
V_fixture_min = 3.00
V_fixture_max = 3.60
| time   V(typ)   V(min)   V(max)
0s        1.09V      1.25V      1.13V
900ps     1.09V      1.25V      1.13V
1.2ns     1.09V      1.25V      1.39V
1.5ns     1.18V      1.25V      2.35V
1.8ns     1.89V      1.26V      3.31V
2.1ns     2.71V      1.4V       3.5V
2.4ns     3.09V      1.86V      3.55V
3ns       3.24V      2.74V      3.58V
3.9ns     3.28V      2.94V      3.59V
15ns      3.3V       3V         3.6V
[Falling Waveform]
R_fixture = 50.00
V_fixture = 3.30
V_fixture_min = 3.00
V_fixture_max = 3.60
| time   V(typ)   V(min)   V(max)
0s        3.3V       3V         3.6V
1.5ns     3.3V       3V         3.56V
1.8ns     3.3V       3V         3.23V
2.1ns     3.23V      3V         2.72V
2.7ns     2.63V      2.97V      1.74V
3.3ns     1.65V      2.69V      1.3V
3.6ns     1.36V      2.45V      1.24V
4.5ns     1.14V      1.56V      1.17V
5.4ns     1.11V      1.32V      1.15V
15ns      1.09V      1.26V      1.14V
[Falling Waveform]
R_fixture = 50.00
V_fixture = 0.000
V_fixture_min = 0.000
V_fixture_max = 0.000
| time   V(typ)   V(min)   V(max)
0s        1.91V      1.67V      2.02V
1.2ns     1.91V      1.67V      1.98V
1.5ns     1.9V       1.67V      1.27V
1.8ns     1.67V      1.67V      330mV
2.1ns     1.16V      1.66V      69.53mV
2.4ns     500mV      1.57V      32.3mV
2.7ns     130mV      1.37V      19.62mV
3.6ns     19.35mV    240mV      7.98mV
4.2ns     11.06mV    56.04mV    5.73mV
15ns      930uV      1.31mV     930uV
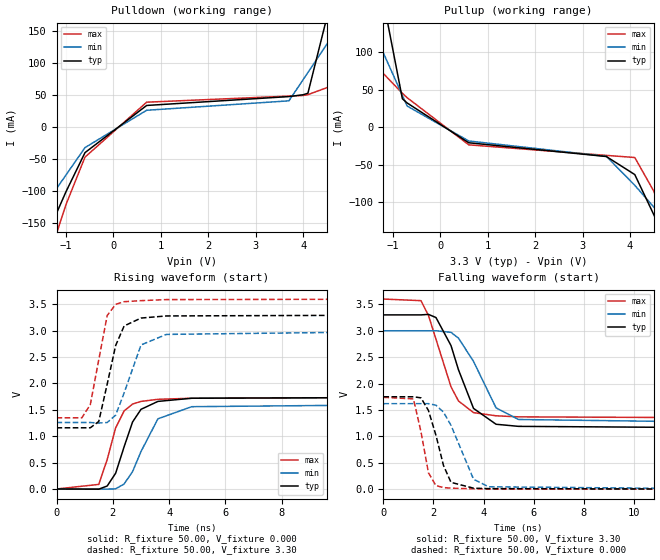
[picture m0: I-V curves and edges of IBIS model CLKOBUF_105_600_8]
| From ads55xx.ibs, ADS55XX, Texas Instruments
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|   Model CLKOBUF_105_600_8
[Model]   CLKOBUF_105_600_8
Model_type   Output
Polarity   Non-Inverting
Vmeas =   1.65V
C_comp   2pf   2pf   2pf
[Temperature Range]   50.00   0.10k   -20.00
[Voltage Range]   3.30V   3.00V   3.60V
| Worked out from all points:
|   slope of the pulldown table from 0 to 0.495 V, typ, clamps not added: 18.5 ohm
|   slope of the pullup table from 0 to 0.495 V, typ, clamps not added: 27.7 ohm
|   rising waveform, R_fixture 50.00, V_fixture 0.000: 20-80 % time 724ps typ, 855ps min, 652ps max; typ from 0 V to 1.74 V
|   rising waveform, R_fixture 50.00, V_fixture 3.30: 20-80 % time 593ps typ, 678ps min, 479ps max; typ from 1.16 V to 3.3 V
|   falling waveform, R_fixture 50.00, V_fixture 3.30: 20-80 % time 976ps typ, 1.07ns min, 962ps max; typ from 3.3 V to 1.16 V
|   falling waveform, R_fixture 50.00, V_fixture 0.000: 20-80 % time 636ps typ, 835ps min, 431ps max; typ from 1.75 V to 0.001 V
[Pulldown]
| voltage   I(typ)   I(min)   I(max)
-3.3V     -487.1mA   -319.8mA   -643.2mA
-1.9V     -251.9mA   -170.5mA   -325.1mA
-1.5V     -184.7mA   -127.9mA   -234.3mA
-1V       -100.7mA   -74.6mA    -120.7mA
-600mV    -39.81mA   -31.96mA   -46.85mA
700mV     33.83mA    26.33mA    38.95mA
3.7V      47.7mA     41.06mA    48.43mA
4V        50.54mA    74.24mA    49.45mA
4.1V      52.89mA    85.3mA     50.71mA
4.5V      171.3mA    129.5mA    61.61mA
4.9V      289.8mA    173.8mA    74.95mA
6.6V      793.1mA    361.8mA    131.6mA
[Pullup]
| voltage   I(typ)   I(min)   I(max)
-3.3V     853.8mA    395.3mA    209.4mA
-2.1V     462.2mA    225.8mA    130.5mA
-1.5V     266.3mA    141.1mA    91.1mA
-1V       103.1mA    70.5mA     58.25mA
-800mV    37.84mA    42.26mA    45.11mA
-700mV    32.23mA    28.14mA    39.3mA
600mV     -20.84mA   -18.47mA   -23.61mA
3.5V      -39.15mA   -38.94mA   -37.65mA
4.1V      -63.24mA   -77.54mA   -40.48mA
4.5V      -116.6mA   -106.5mA   -85.27mA
4.9V      -170mA     -135.4mA   -151.7mA
6.6V      -397mA     -258.3mA   -434mA
[Ramp]
| variable   typ   min   max
dV/dt_r   1.05/0.69n   0.97/0.83n   1.04/0.60n
dV/dt_f   1.28/0.94n   1.05/1.04n   1.35/0.93n
R_load = 50.00
[Rising Waveform]
R_fixture = 50.00
V_fixture = 0.000
V_fixture_min = 0.000
V_fixture_max = 0.000
| time   V(typ)   V(min)   V(max)
0s        24.18nV    33.78nV    47.34nV
1.5ns     -3.4mV     35.35uV    87.02mV
1.8ns     57.04mV    -2.05mV    560mV
2.1ns     300mV      3.06mV     1.16V
2.4ns     800mV      94.59mV    1.48V
2.7ns     1.27V      330mV      1.61V
3ns       1.51V      710mV      1.66V
3.6ns     1.66V      1.33V      1.7V
4.8ns     1.72V      1.56V      1.72V
15ns      1.74V      1.61V      1.74V
[Rising Waveform]
R_fixture = 50.00
V_fixture = 3.30
V_fixture_min = 3.00
V_fixture_max = 3.60
| time   V(typ)   V(min)   V(max)
0s        1.16V      1.26V      1.35V
900ps     1.16V      1.26V      1.35V
1.2ns     1.16V      1.26V      1.6V
1.5ns     1.28V      1.25V      2.45V
1.8ns     1.99V      1.26V      3.29V
2.1ns     2.72V      1.4V       3.5V
2.4ns     3.09V      1.82V      3.55V
3ns       3.24V      2.73V      3.57V
3.9ns     3.28V      2.93V      3.59V
15ns      3.3V       3V         3.6V
[Falling Waveform]
R_fixture = 50.00
V_fixture = 3.30
V_fixture_min = 3.00
V_fixture_max = 3.60
| time   V(typ)   V(min)   V(max)
0s        3.3V       3V         3.6V
1.5ns     3.3V       3V         3.57V
1.8ns     3.31V      3V         3.29V
2.1ns     3.25V      3V         2.84V
2.7ns     2.72V      2.97V      1.94V
3ns       2.26V      2.86V      1.67V
3.6ns     1.53V      2.42V      1.45V
4.5ns     1.23V      1.54V      1.39V
5.4ns     1.19V      1.32V      1.37V
15ns      1.16V      1.26V      1.35V
[Falling Waveform]
R_fixture = 50.00
V_fixture = 0.000
V_fixture_min = 0.000
V_fixture_max = 0.000
| time   V(typ)   V(min)   V(max)
0s        1.75V      1.62V      1.74V
1.2ns     1.75V      1.62V      1.71V
1.5ns     1.73V      1.62V      1.09V
1.8ns     1.49V      1.62V      310mV
2.1ns     1.02V      1.59V      67.7mV
2.4ns     450mV      1.46V      31.52mV
2.7ns     130mV      1.21V      19.56mV
3.6ns     19.68mV    190mV      8.12mV
4.2ns     11.05mV    45.89mV    5.87mV
15ns      950uV      1.3mV      960uV
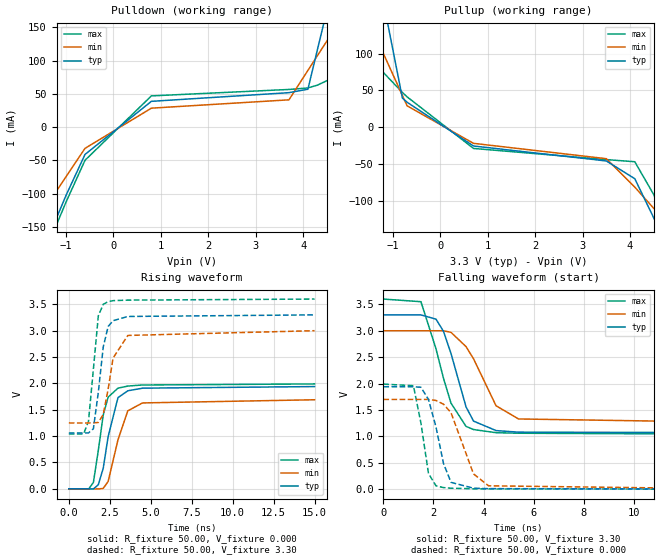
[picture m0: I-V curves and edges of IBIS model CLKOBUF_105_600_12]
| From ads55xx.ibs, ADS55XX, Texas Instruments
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|   Model CLKOBUF_105_600_12
[Model]   CLKOBUF_105_600_12
Model_type   Output
Polarity   Non-Inverting
Vmeas =   1.65V
C_comp   2pf   2pf   2pf
[Temperature Range]   50.00   0.10k   -20.00
[Voltage Range]   3.30V   3.00V   3.60V
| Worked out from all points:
|   slope of the pulldown table from 0 to 0.495 V, typ, clamps not added: 17.6 ohm
|   slope of the pullup table from 0 to 0.495 V, typ, clamps not added: 25.5 ohm
|   rising waveform, R_fixture 50.00, V_fixture 0.000: 20-80 % time 670ps typ, 795ps min, 633ps max; typ from 0 V to 1.94 V
|   rising waveform, R_fixture 50.00, V_fixture 3.30: 20-80 % time 565ps typ, 670ps min, 461ps max; typ from 1.06 V to 3.3 V
|   falling waveform, R_fixture 50.00, V_fixture 3.30: 20-80 % time 852ps typ, 1.1ns min, 923ps max; typ from 3.3 V to 1.07 V
|   falling waveform, R_fixture 50.00, V_fixture 0.000: 20-80 % time 599ps typ, 782ps min, 413ps max; typ from 1.94 V to 0.001 V
[Pulldown]
| voltage   I(typ)   I(min)   I(max)
-3.3V     -493mA     -319.8mA   -500.8mA
-1.7V     -221.5mA   -149.2mA   -230.9mA
-1.5V     -187.5mA   -127.9mA   -197.2mA
-1V       -102.7mA   -74.6mA    -112.8mA
-600mV    -41.12mA   -31.96mA   -49.89mA
800mV     38.81mA    28.55mA    46.98mA
3.7V      51.85mA    41.06mA    56.67mA
4.1V      57.03mA    85.3mA     58.93mA
4.3V      116.3mA    107.4mA    63.16mA
4.5V      175.5mA    129.5mA    69.83mA
4.7V      234.7mA    151.7mA    76.5mA
6.6V      797.3mA    361.8mA    139.9mA
[Pullup]
| voltage   I(typ)   I(min)   I(max)
-3.3V     860.7mA    399.3mA    216.8mA
-2.1V     466.6mA    228.4mA    135.4mA
-1.5V     269.6mA    142.9mA    94.75mA
-1V       105.4mA    71.75mA    60.85mA
-800mV    39.69mA    43.27mA    47.29mA
-700mV    33.88mA    29.03mA    41.26mA
700mV     -25.72mA   -22.09mA   -29.04mA
3.5V      -46.08mA   -43.01mA   -44.24mA
4.1V      -70.28mA   -81.73mA   -47.15mA
4.5V      -123.7mA   -110.7mA   -91.98mA
4.9V      -177.2mA   -139.7mA   -158.4mA
6.6V      -404.3mA   -263mA     -440.9mA
[Ramp]
| variable   typ   min   max
dV/dt_r   1.16/0.64n   1.02/0.74n   1.20/0.58n
dV/dt_f   1.34/0.82n   1.05/1.07n   1.54/0.89n
R_load = 50.00
[Rising Waveform]
R_fixture = 50.00
V_fixture = 0.000
V_fixture_min = 0.000
V_fixture_max = 0.000
| time   V(typ)   V(min)   V(max)
0s        23.67nV    34.17nV    45.14nV
1.2ns     -7.95uV    590nV      -5.95mV
1.5ns     -2.61mV    35.41uV    120mV
1.8ns     78.51mV    -2.27mV    730mV
2.1ns     390mV      8.68mV     1.4V
2.4ns     990mV      140mV      1.74V
3ns       1.73V      930mV      1.91V
3.6ns     1.86V      1.48V      1.95V
4.5ns     1.91V      1.63V      1.97V
15ns      1.94V      1.69V      1.99V
[Rising Waveform]
R_fixture = 50.00
V_fixture = 3.30
V_fixture_min = 3.00
V_fixture_max = 3.60
| time   V(typ)   V(min)   V(max)
0s        1.06V      1.25V      1.04V
900ps     1.06V      1.25V      1.04V
1.2ns     1.06V      1.25V      1.28V
1.5ns     1.14V      1.25V      2.27V
1.8ns     1.83V      1.26V      3.28V
2.1ns     2.69V      1.41V      3.5V
2.4ns     3.08V      1.89V      3.55V
2.7ns     3.19V      2.48V      3.57V
3.6ns     3.27V      2.91V      3.58V
15ns      3.3V       3V         3.6V
[Falling Waveform]
R_fixture = 50.00
V_fixture = 3.30
V_fixture_min = 3.00
V_fixture_max = 3.60
| time   V(typ)   V(min)   V(max)
0s        3.3V       3V         3.6V
1.5ns     3.3V       3V         3.55V
2.1ns     3.22V      3V         2.66V
2.4ns     2.99V      3V         2.1V
2.7ns     2.57V      2.97V      1.63V
3.3ns     1.56V      2.7V       1.19V
3.6ns     1.29V      2.47V      1.13V
4.5ns     1.11V      1.58V      1.07V
5.4ns     1.08V      1.33V      1.06V
15ns      1.07V      1.26V      1.04V
[Falling Waveform]
R_fixture = 50.00
V_fixture = 0.000
V_fixture_min = 0.000
V_fixture_max = 0.000
| time   V(typ)   V(min)   V(max)
0s        1.94V      1.7V       1.99V
1.2ns     1.94V      1.7V       1.96V
1.5ns     1.93V      1.7V       1.25V
1.8ns     1.7V       1.7V       300mV
2.1ns     1.18V      1.68V      64.13mV
2.4ns     490mV      1.61V      30.95mV
2.7ns     130mV      1.45V      18.94mV
3.6ns     19.07mV    290mV      7.81mV
4.2ns     11.07mV    64.6mV     5.63mV
15ns      920uV      1.32mV     910uV
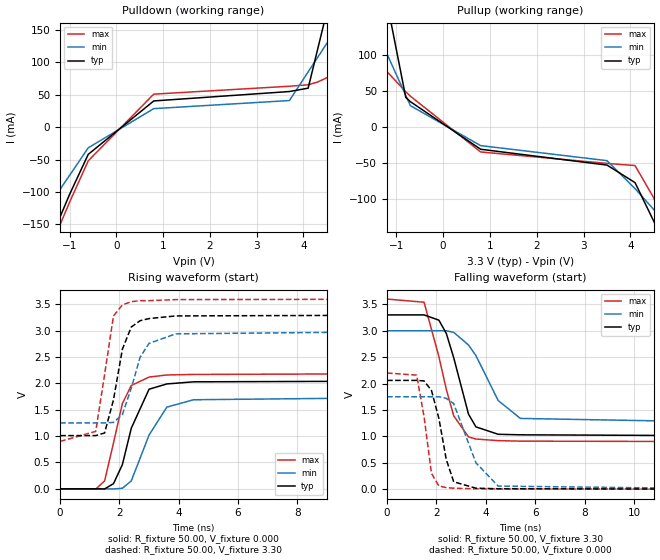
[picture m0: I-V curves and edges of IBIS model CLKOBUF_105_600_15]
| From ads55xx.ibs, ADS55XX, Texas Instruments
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|   Model CLKOBUF_105_600_15
[Model]   CLKOBUF_105_600_15
Model_type   Output
Polarity   Non-Inverting
Vmeas =   1.65V
C_comp   2pf   2pf   2pf
[Temperature Range]   50.00   0.10k   -20.00
[Voltage Range]   3.30V   3.00V   3.60V
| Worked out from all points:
|   slope of the pulldown table from 0 to 0.495 V, typ, clamps not added: 17 ohm
|   slope of the pullup table from 0 to 0.495 V, typ, clamps not added: 23.9 ohm
|   rising waveform, R_fixture 50.00, V_fixture 0.000: 20-80 % time 614ps typ, 747ps min, 596ps max; typ from 0 V to 2.05 V
|   rising waveform, R_fixture 50.00, V_fixture 3.30: 20-80 % time 543ps typ, 659ps min, 443ps max; typ from 1.01 V to 3.3 V
|   falling waveform, R_fixture 50.00, V_fixture 3.30: 20-80 % time 799ps typ, 1.2ns min, 845ps max; typ from 3.3 V to 1.01 V
|   falling waveform, R_fixture 50.00, V_fixture 0.000: 20-80 % time 580ps typ, 808ps min, 409ps max; typ from 2.06 V to 0.001 V
[Pulldown]
| voltage   I(typ)   I(min)   I(max)
-3.3V     -497.2mA   -319.8mA   -510.8mA
-1.9V     -257.9mA   -170.5mA   -270.6mA
-1.5V     -189.6mA   -127.9mA   -201.9mA
-1V       -104.1mA   -74.6mA    -116.1mA
-600mV    -42.07mA   -31.96mA   -52.03mA
800mV     40.44mA    28.55mA    50.93mA
3.7V      55mA       41.06mA    63.14mA
4.1V      60.18mA    85.3mA     65.39mA
4.3V      119.4mA    107.4mA    69.6mA
4.5V      178.6mA    129.5mA    76.26mA
4.9V      297mA      173.8mA    89.58mA
6.6V      800.2mA    361.8mA    146.2mA
[Pullup]
| voltage   I(typ)   I(min)   I(max)
-3.3V     866.2mA    402.1mA    223.1mA
-2.1V     470.3mA    230.2mA    139.6mA
-1.5V     272.2mA    144.3mA    97.8mA
-1V       107.2mA    72.7mA     63mA
-800mV    41.25mA    44.06mA    49.08mA
-700mV    35.27mA    29.74mA    42.86mA
800mV     -30.65mA   -25.61mA   -34.4mA
3.5V      -52.59mA   -46.45mA   -50.25mA
4.1V      -76.92mA   -85.19mA   -53.23mA
4.5V      -130.4mA   -114.2mA   -98.1mA
4.9V      -184mA     -143.2mA   -164.6mA
6.6V      -411.4mA   -266.4mA   -447.2mA
[Ramp]
| variable   typ   min   max
dV/dt_r   1.23/0.59n   1.05/0.71n   1.32/0.54n
dV/dt_f   1.37/0.76n   1.04/1.17n   1.62/0.83n
R_load = 50.00
[Rising Waveform]
R_fixture = 50.00
V_fixture = 0.000
V_fixture_min = 0.000
V_fixture_max = 0.000
| time   V(typ)   V(min)   V(max)
0s        23.35nV    34.31nV    43.81nV
1.2ns     -6.26uV    590nV      -6.17mV
1.5ns     -1.62mV    35.43uV    150mV
1.8ns     98.42mV    -2.35mV    870mV
2.1ns     460mV      11.13mV    1.62V
2.4ns     1.15V      150mV      1.96V
3ns       1.89V      1.02V      2.12V
3.6ns     1.99V      1.55V      2.16V
4.5ns     2.03V      1.69V      2.17V
15ns      2.05V      1.75V      2.19V
[Rising Waveform]
R_fixture = 50.00
V_fixture = 3.30
V_fixture_min = 3.00
V_fixture_max = 3.60
| time   V(typ)   V(min)   V(max)
0s        1.01V      1.25V      900mV
1.2ns     1.01V      1.25V      1.09V
1.5ns     1.06V      1.25V      2.17V
1.8ns     1.69V      1.26V      3.28V
2.1ns     2.65V      1.41V      3.49V
2.4ns     3.07V      1.91V      3.55V
2.7ns     3.19V      2.5V       3.57V
3ns       3.23V      2.76V      3.57V
3.9ns     3.28V      2.94V      3.59V
15ns      3.3V       3V         3.6V
[Falling Waveform]
R_fixture = 50.00
V_fixture = 3.30
V_fixture_min = 3.00
V_fixture_max = 3.60
| time   V(typ)   V(min)   V(max)
0s        3.3V       3V         3.6V
1.5ns     3.3V       3V         3.54V
2.1ns     3.2V       3V         2.51V
2.4ns     2.95V      3V         1.89V
2.7ns     2.49V      2.97V      1.39V
3.3ns     1.42V      2.73V      990mV
3.6ns     1.18V      2.53V      950mV
4.5ns     1.04V      1.68V      920mV
5.4ns     1.03V      1.34V      910mV
15ns      1.01V      1.26V      900mV
[Falling Waveform]
R_fixture = 50.00
V_fixture = 0.000
V_fixture_min = 0.000
V_fixture_max = 0.000
| time   V(typ)   V(min)   V(max)
0s        2.06V      1.75V      2.2V
1.2ns     2.06V      1.75V      2.16V
1.5ns     2.05V      1.75V      1.37V
1.8ns     1.87V      1.75V      300mV
2.1ns     1.34V      1.75V      60.8mV
2.4ns     560mV      1.72V      30.24mV
2.7ns     140mV      1.62V      18.51mV
3.6ns     19.23mV    500mV      7.61mV
4.5ns     9.08mV     59.25mV    4.79mV
15ns      910uV      1.36mV     880uV
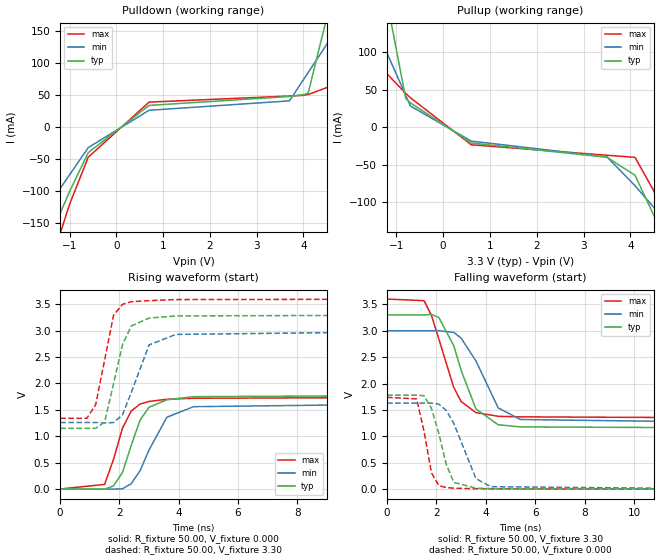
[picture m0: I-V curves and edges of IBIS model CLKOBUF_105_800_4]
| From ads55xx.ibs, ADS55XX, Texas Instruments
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|   Model CLKOBUF_105_800_4
[Model]   CLKOBUF_105_800_4
Model_type   Output
Polarity   Non-Inverting
Vmeas =   1.65V
C_comp   2pf   2pf   2pf
[Temperature Range]   50.00   0.10k   -20.00
[Voltage Range]   3.30V   3.00V   3.60V
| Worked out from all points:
|   slope of the pulldown table from 0 to 0.495 V, typ, clamps not added: 18.4 ohm
|   slope of the pullup table from 0 to 0.495 V, typ, clamps not added: 27.3 ohm
|   rising waveform, R_fixture 50.00, V_fixture 0.000: 20-80 % time 716ps typ, 856ps min, 654ps max; typ from 0 V to 1.78 V
|   rising waveform, R_fixture 50.00, V_fixture 3.30: 20-80 % time 587ps typ, 679ps min, 481ps max; typ from 1.15 V to 3.3 V
|   falling waveform, R_fixture 50.00, V_fixture 3.30: 20-80 % time 966ps typ, 1.07ns min, 951ps max; typ from 3.3 V to 1.16 V
|   falling waveform, R_fixture 50.00, V_fixture 0.000: 20-80 % time 634ps typ, 815ps min, 431ps max; typ from 1.78 V to 0.001 V
[Pulldown]
| voltage   I(typ)   I(min)   I(max)
-3.3V     -487.4mA   -319.8mA   -643.6mA
-1.9V     -252.1mA   -170.5mA   -325.3mA
-1.5V     -184.8mA   -127.9mA   -234.4mA
-1V       -100.8mA   -74.6mA    -120.8mA
-600mV    -39.88mA   -31.96mA   -46.92mA
700mV     33.93mA    26.33mA    39.07mA
3.7V      47.91mA    41.06mA    48.62mA
4V        50.75mA    74.24mA    49.64mA
4.1V      53.1mA     85.3mA     50.9mA
4.5V      171.5mA    129.5mA    61.8mA
4.9V      290mA      173.8mA    75.14mA
6.6V      793.3mA    361.8mA    131.8mA
[Pullup]
| voltage   I(typ)   I(min)   I(max)
-3.3V     854.9mA    396.2mA    209.1mA
-2.1V     462.9mA    226.4mA    130.4mA
-1.5V     266.9mA    141.5mA    91.03mA
-1V       103.5mA    70.77mA    58.23mA
-800mV    38.17mA    42.47mA    45.11mA
-700mV    32.52mA    28.32mA    39.3mA
600mV     -21.18mA   -18.68mA   -23.6mA
3.5V      -40.31mA   -39.76mA   -37.63mA
4.1V      -64.41mA   -78.37mA   -40.46mA
4.5V      -117.8mA   -107.3mA   -85.25mA
4.9V      -171.1mA   -136.2mA   -151.7mA
6.6V      -397.9mA   -259.1mA   -434mA
[Ramp]
| variable   typ   min   max
dV/dt_r   1.07/0.68n   0.98/0.81n   1.04/0.60n
dV/dt_f   1.29/0.93n   1.05/1.05n   1.35/0.93n
R_load = 50.00
[Rising Waveform]
R_fixture = 50.00
V_fixture = 0.000
V_fixture_min = 0.000
V_fixture_max = 0.000
| time   V(typ)   V(min)   V(max)
0s        24.16nV    33.83nV    47.27nV
1.5ns     -3.35mV    35.36uV    86.57mV
1.8ns     59.35mV    -2.08mV    560mV
2.1ns     310mV      3.77mV     1.15V
2.4ns     830mV      100mV      1.48V
2.7ns     1.31V      350mV      1.61V
3ns       1.55V      740mV      1.66V
3.6ns     1.69V      1.36V      1.7V
4.5ns     1.75V      1.56V      1.72V
15ns      1.78V      1.63V      1.74V
[Rising Waveform]
R_fixture = 50.00
V_fixture = 3.30
V_fixture_min = 3.00
V_fixture_max = 3.60
| time   V(typ)   V(min)   V(max)
0s        1.15V      1.26V      1.34V
900ps     1.15V      1.26V      1.34V
1.2ns     1.15V      1.26V      1.6V
1.5ns     1.27V      1.25V      2.44V
1.8ns     1.99V      1.26V      3.29V
2.1ns     2.73V      1.4V       3.5V
2.4ns     3.09V      1.83V      3.55V
3ns       3.24V      2.73V      3.57V
3.9ns     3.28V      2.93V      3.59V
15ns      3.3V       3V         3.6V
[Falling Waveform]
R_fixture = 50.00
V_fixture = 3.30
V_fixture_min = 3.00
V_fixture_max = 3.60
| time   V(typ)   V(min)   V(max)
0s        3.3V       3V         3.6V
1.5ns     3.3V       3V         3.57V
1.8ns     3.31V      3V         3.29V
2.1ns     3.25V      3V         2.84V
2.7ns     2.72V      2.97V      1.93V
3ns       2.25V      2.86V      1.66V
3.6ns     1.52V      2.43V      1.45V
4.5ns     1.22V      1.54V      1.38V
5.4ns     1.18V      1.32V      1.37V
15ns      1.16V      1.26V      1.35V
[Falling Waveform]
R_fixture = 50.00
V_fixture = 0.000
V_fixture_min = 0.000
V_fixture_max = 0.000
| time   V(typ)   V(min)   V(max)
0s        1.78V      1.63V      1.74V
1.2ns     1.78V      1.63V      1.71V
1.5ns     1.77V      1.63V      1.09V
1.8ns     1.53V      1.63V      310mV
2.1ns     1.05V      1.61V      67.28mV
2.4ns     470mV      1.49V      31.43mV
2.7ns     130mV      1.25V      19.51mV
3.6ns     19.8mV     200mV      8.11mV
4.2ns     11.1mV     48.18mV    5.86mV
15ns      940uV      1.3mV      960uV
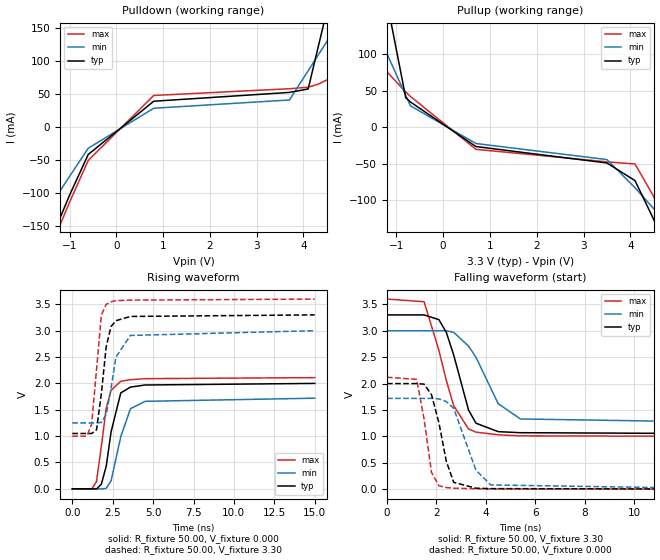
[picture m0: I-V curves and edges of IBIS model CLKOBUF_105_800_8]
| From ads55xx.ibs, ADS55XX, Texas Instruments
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|   Model CLKOBUF_105_800_8
[Model]   CLKOBUF_105_800_8
Model_type   Output
Polarity   Non-Inverting
Vmeas =   1.65V
C_comp   2pf   2pf   2pf
[Temperature Range]   50.00   0.10k   -20.00
[Voltage Range]   3.30V   3.00V   3.60V
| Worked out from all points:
|   slope of the pulldown table from 0 to 0.495 V, typ, clamps not added: 17.4 ohm
|   slope of the pullup table from 0 to 0.495 V, typ, clamps not added: 24.7 ohm
|   rising waveform, R_fixture 50.00, V_fixture 0.000: 20-80 % time 621ps typ, 759ps min, 613ps max; typ from 0 V to 2 V
|   rising waveform, R_fixture 50.00, V_fixture 3.30: 20-80 % time 553ps typ, 659ps min, 452ps max; typ from 1.05 V to 3.3 V
|   falling waveform, R_fixture 50.00, V_fixture 3.30: 20-80 % time 816ps typ, 1.14ns min, 908ps max; typ from 3.3 V to 1.05 V
|   falling waveform, R_fixture 50.00, V_fixture 0.000: 20-80 % time 590ps typ, 775ps min, 415ps max; typ from 2 V to 0.001 V
[Pulldown]
| voltage   I(typ)   I(min)   I(max)
-3.3V     -494mA     -319.8mA   -503.2mA
-1.9V     -256mA     -170.5mA   -266mA
-1.5V     -188mA     -127.9mA   -198.3mA
-1V       -103mA     -74.6mA    -113.6mA
-600mV    -41.32mA   -31.96mA   -50.37mA
800mV     39.15mA    28.55mA    47.87mA
3.7V      52.49mA    41.06mA    58.08mA
4.1V      57.68mA    85.3mA     60.34mA
4.3V      116.9mA    107.4mA    64.56mA
4.5V      176.1mA    129.5mA    71.23mA
4.7V      235.3mA    151.7mA    77.9mA
6.6V      797.9mA    361.8mA    141.3mA
[Pullup]
| voltage   I(typ)   I(min)   I(max)
-3.3V     863.2mA    400.4mA    220.6mA
-2.1V     468.3mA    229.1mA    137.9mA
-1.5V     270.9mA    143.5mA    96.57mA
-1V       106.3mA    72.17mA    62.12mA
-800mV    40.48mA    43.63mA    48.34mA
-700mV    34.58mA    29.36mA    42.2mA
700mV     -26.68mA   -22.52mA   -30.49mA
3.5V      -49.27mA   -44.57mA   -47.71mA
4.1V      -73.53mA   -83.25mA   -50.66mA
4.5V      -127mA     -112.2mA   -95.51mA
4.9V      -180.5mA   -141.2mA   -162mA
6.6V      -407.8mA   -264.2mA   -444.5mA
[Ramp]
| variable   typ   min   max
dV/dt_r   1.20/0.61n   1.03/0.72n   1.27/0.56n
dV/dt_f   1.35/0.79n   1.04/1.13n   1.56/0.88n
R_load = 50.00
[Rising Waveform]
R_fixture = 50.00
V_fixture = 0.000
V_fixture_min = 0.000
V_fixture_max = 0.000
| time   V(typ)   V(min)   V(max)
0s        23.64nV    34.28nV    44.88nV
1.2ns     -7.46uV    590nV      -6.04mV
1.5ns     -2.24mV    35.43uV    140mV
1.8ns     89.71mV    -2.34mV    810mV
2.1ns     430mV      10.69mV    1.53V
2.4ns     1.08V      150mV      1.87V
3ns       1.82V      990mV      2.04V
3.6ns     1.93V      1.52V      2.07V
4.5ns     1.97V      1.66V      2.09V
15ns      2V         1.72V      2.11V
[Rising Waveform]
R_fixture = 50.00
V_fixture = 3.30
V_fixture_min = 3.00
V_fixture_max = 3.60
| time   V(typ)   V(min)   V(max)
0s        1.05V      1.25V      1V
900ps     1.05V      1.25V      1V
1.2ns     1.05V      1.25V      1.23V
1.5ns     1.12V      1.25V      2.26V
1.8ns     1.81V      1.26V      3.3V
2.1ns     2.7V       1.41V      3.5V
2.4ns     3.08V      1.91V      3.55V
2.7ns     3.19V      2.5V       3.57V
3.6ns     3.27V      2.91V      3.58V
15ns      3.3V       3V         3.6V
[Falling Waveform]
R_fixture = 50.00
V_fixture = 3.30
V_fixture_min = 3.00
V_fixture_max = 3.60
| time   V(typ)   V(min)   V(max)
0s        3.3V       3V         3.6V
1.5ns     3.3V       3V         3.55V
2.1ns     3.21V      3V         2.63V
2.4ns     2.97V      3V         2.06V
2.7ns     2.54V      2.97V      1.58V
3.3ns     1.5V       2.71V      1.14V
3.6ns     1.25V      2.5V       1.08V
4.5ns     1.09V      1.62V      1.03V
5.4ns     1.07V      1.33V      1.01V
15ns      1.05V      1.26V      1V
[Falling Waveform]
R_fixture = 50.00
V_fixture = 0.000
V_fixture_min = 0.000
V_fixture_max = 0.000
| time   V(typ)   V(min)   V(max)
0s        2V         1.72V      2.12V
1.2ns     2V         1.72V      2.08V
1.5ns     1.99V      1.72V      1.33V
1.8ns     1.79V      1.72V      320mV
2.1ns     1.26V      1.71V      65.52mV
2.4ns     530mV      1.66V      31.48mV
2.7ns     130mV      1.53V      19.12mV
3.6ns     19.02mV    360mV      7.79mV
4.2ns     11.09mV    81.05mV    5.59mV
15ns      920uV      1.34mV     900uV
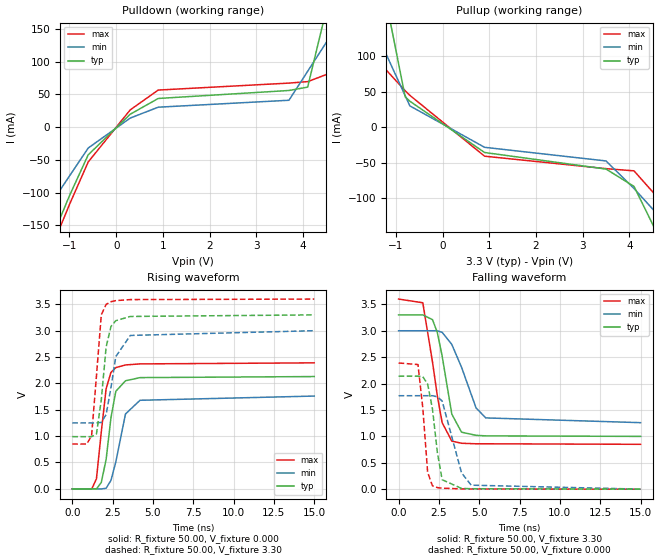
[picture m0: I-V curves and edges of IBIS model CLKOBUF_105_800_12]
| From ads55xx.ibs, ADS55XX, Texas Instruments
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|   Model CLKOBUF_105_800_12
[Model]   CLKOBUF_105_800_12
Model_type   Output
Polarity   Non-Inverting
Vmeas =   1.65V
C_comp   2pf   2pf   2pf
[Temperature Range]   50.00   0.10k   -20.00
[Voltage Range]   3.30V   3.00V   3.60V
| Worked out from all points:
|   slope of the pulldown table from 0 to 0.495 V, typ, clamps not added: 16.8 ohm
|   slope of the pullup table from 0 to 0.495 V, typ, clamps not added: 22.6 ohm
|   rising waveform, R_fixture 50.00, V_fixture 0.000: 20-80 % time 604ps typ, 726ps min, 515ps max; typ from 0 V to 2.13 V
|   rising waveform, R_fixture 50.00, V_fixture 3.30: 20-80 % time 524ps typ, 656ps min, 432ps max; typ from 0.99 V to 3.3 V
|   falling waveform, R_fixture 50.00, V_fixture 3.30: 20-80 % time 789ps typ, 1.26ns min, 809ps max; typ from 3.3 V to 1 V
|   falling waveform, R_fixture 50.00, V_fixture 0.000: 20-80 % time 579ps typ, 836ps min, 397ps max; typ from 2.14 V to 0.001 V
[Pulldown]
| voltage   I(typ)   I(min)   I(max)
-3.3V     -498.8mA   -319.8mA   -516.9mA
-1.9V     -258.8mA   -170.5mA   -274.2mA
-1.5V     -190.3mA   -127.9mA   -204.8mA
-1V       -104.6mA   -74.6mA    -118.1mA
-600mV    -42.35mA   -31.96mA   -53.28mA
300mV     19.71mA    13.85mA    26.34mA
900mV     43.78mA    30.46mA    56.62mA
3.7V      55.98mA    41.06mA    67.26mA
4.1V      61.16mA    85.3mA     69.49mA
4.5V      179.6mA    129.5mA    80.34mA
4.9V      298mA      173.8mA    93.64mA
6.6V      801.4mA    361.8mA    150.2mA
[Pullup]
| voltage   I(typ)   I(min)   I(max)
-3.3V     871.4mA    402.8mA    230.8mA
-2.1V     473.6mA    230.7mA    144.6mA
-1.5V     274.7mA    144.7mA    101.6mA
-1V       109mA      73mA       65.65mA
-800mV    42.66mA    44.32mA    51.29mA
-700mV    36.53mA    29.98mA    44.83mA
900mV     -35.73mA   -28.43mA   -40.95mA
3.5V      -59.07mA   -47.65mA   -58.51mA
4.1V      -83.53mA   -86.44mA   -61.59mA
4.7V      -163.9mA   -130mA     -106.1mA
5.3V      -244.3mA   -173.6mA   -155.3mA
6.6V      -418.5mA   -267.9mA   -262.1mA
[Ramp]
| variable   typ   min   max
dV/dt_r   1.28/0.54n   1.06/0.70n   1.43/0.50n
dV/dt_f   1.38/0.76n   1.04/1.24n   1.65/0.79n
R_load = 50.00
[Rising Waveform]
R_fixture = 50.00
V_fixture = 0.000
V_fixture_min = 0.000
V_fixture_max = 0.000
| time   V(typ)   V(min)   V(max)
0s        23.37nV    34.35nV    43.2nV
1.2ns     -5.9uV     590nV      -6.1mV
1.5ns     -630uV     35.44uV    190mV
1.8ns     120mV      -2.38mV    1.08V
2.1ns     560mV      11.95mV    1.9V
2.4ns     1.35V      160mV      2.21V
2.7ns     1.85V      510mV      2.3V
3.3ns     2.05V      1.42V      2.35V
4.2ns     2.11V      1.68V      2.37V
15ns      2.13V      1.76V      2.39V
[Rising Waveform]
R_fixture = 50.00
V_fixture = 3.30
V_fixture_min = 3.00
V_fixture_max = 3.60
| time   V(typ)   V(min)   V(max)
0s        990mV      1.25V      850mV
900ps     990mV      1.25V      850mV
1.2ns     990mV      1.25V      1.01V
1.5ns     1.04V      1.25V      2.14V
1.8ns     1.69V      1.26V      3.3V
2.1ns     2.69V      1.41V      3.5V
2.4ns     3.08V      1.92V      3.55V
2.7ns     3.19V      2.51V      3.57V
3.6ns     3.27V      2.91V      3.59V
15ns      3.3V       3V         3.6V
[Falling Waveform]
R_fixture = 50.00
V_fixture = 3.30
V_fixture_min = 3.00
V_fixture_max = 3.60
| time   V(typ)   V(min)   V(max)
0s        3.3V       3V         3.6V
1.5ns     3.3V       3V         3.53V
2.1ns     3.21V      3V         2.41V
2.4ns     2.97V      3V         1.77V
2.7ns     2.52V      2.97V      1.26V
3.3ns     1.42V      2.74V      910mV
3.9ns     1.08V      2.31V      870mV
4.8ns     1.02V      1.54V      860mV
5.4ns     1.01V      1.35V      860mV
15ns      1V         1.26V      850mV
[Falling Waveform]
R_fixture = 50.00
V_fixture = 0.000
V_fixture_min = 0.000
V_fixture_max = 0.000
| time   V(typ)   V(min)   V(max)
0s        2.14V      1.77V      2.39V
1.2ns     2.14V      1.77V      2.36V
1.5ns     2.13V      1.77V      1.54V
1.8ns     1.99V      1.77V      320mV
2.1ns     1.52V      1.77V      64.17mV
2.4ns     700mV      1.75V      30.83mV
2.7ns     180mV      1.67V      18.77mV
3.9ns     14.81mV    310mV      6.39mV
4.5ns     9.31mV     76.38mV    4.78mV
15ns      900uV      1.38mV     870uV
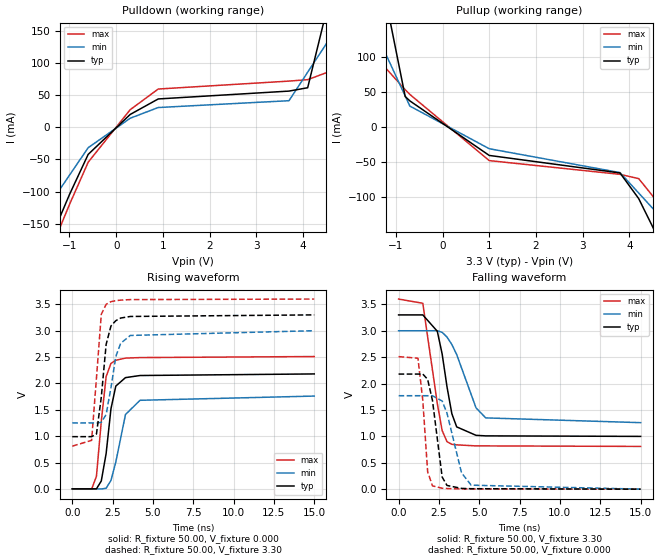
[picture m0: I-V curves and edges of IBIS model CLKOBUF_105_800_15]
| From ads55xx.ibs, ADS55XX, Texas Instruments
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|   Model CLKOBUF_105_800_15
[Model]   CLKOBUF_105_800_15
Model_type   Output
Polarity   Non-Inverting
Vmeas =   1.65V
C_comp   2pf   2pf   2pf
[Temperature Range]   50.00   0.10k   -20.00
[Voltage Range]   3.30V   3.00V   3.60V
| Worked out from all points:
|   slope of the pulldown table from 0 to 0.495 V, typ, clamps not added: 16.8 ohm
|   slope of the pullup table from 0 to 0.495 V, typ, clamps not added: 21.9 ohm
|   rising waveform, R_fixture 50.00, V_fixture 0.000: 20-80 % time 591ps typ, 734ps min, 481ps max; typ from 0 V to 2.18 V
|   rising waveform, R_fixture 50.00, V_fixture 3.30: 20-80 % time 507ps typ, 656ps min, 420ps max; typ from 0.99 V to 3.3 V
|   falling waveform, R_fixture 50.00, V_fixture 3.30: 20-80 % time 778ps typ, 1.26ns min, 767ps max; typ from 3.3 V to 1 V
|   falling waveform, R_fixture 50.00, V_fixture 0.000: 20-80 % time 548ps typ, 836ps min, 385ps max; typ from 2.18 V to 0.001 V
[Pulldown]
| voltage   I(typ)   I(min)   I(max)
-3.3V     -498.8mA   -319.8mA   -523mA
-1.9V     -258.8mA   -170.5mA   -277.7mA
-1.5V     -190.3mA   -127.9mA   -207.7mA
-1V       -104.6mA   -74.6mA    -120.1mA
-600mV    -42.35mA   -31.96mA   -54.5mA
300mV     19.71mA    13.85mA    27.1mA
900mV     43.78mA    30.46mA    59.19mA
3.7V      55.98mA    41.06mA    71.51mA
4.1V      61.17mA    85.3mA     73.72mA
4.5V      179.6mA    129.5mA    84.54mA
4.9V      298mA      173.8mA    97.8mA
6.6V      801.2mA    361.8mA    154.2mA
[Pullup]
| voltage   I(typ)   I(min)   I(max)
-3.3V     874.6mA    402.8mA    237.7mA
-2.1V     475.7mA    230.7mA    149.2mA
-1.5V     276.2mA    144.7mA    104.9mA
-1V       110mA      73mA       67.98mA
-800mV    43.57mA    44.32mA    53.22mA
-700mV    37.34mA    29.98mA    46.55mA
1V        -40.25mA   -30.7mA    -47.58mA
3.8V      -65.16mA   -64.66mA   -67.15mA
4.2V      -101.6mA   -93.7mA    -73.21mA
4.7V      -168.7mA   -130mA     -114.4mA
5.1V      -222.4mA   -159mA     -147.3mA
6.6V      -423.7mA   -267.9mA   -270.7mA
[Ramp]
| variable   typ   min   max
dV/dt_r   1.31/0.50n   1.06/0.71n   1.50/0.44n
dV/dt_f   1.38/0.75n   1.04/1.24n   1.67/0.74n
R_load = 50.00
[Rising Waveform]
R_fixture = 50.00
V_fixture = 0.000
V_fixture_min = 0.000
V_fixture_max = 0.000
| time   V(typ)   V(min)   V(max)
0s        23.51nV    34.34nV    42.66nV
1.2ns     -5.86uV    590nV      -5.64mV
1.5ns     410uV      35.44uV    240mV
1.8ns     150mV      -2.37mV    1.28V
2.1ns     670mV      11.7mV     2.13V
2.4ns     1.52V      160mV      2.38V
2.7ns     1.95V      510mV      2.44V
3.3ns     2.11V      1.41V      2.48V
4.2ns     2.15V      1.68V      2.49V
15ns      2.18V      1.76V      2.51V
[Rising Waveform]
R_fixture = 50.00
V_fixture = 3.30
V_fixture_min = 3.00
V_fixture_max = 3.60
| time   V(typ)   V(min)   V(max)
0s        990mV      1.25V      810mV
1.2ns     990mV      1.25V      920mV
1.5ns     1.04V      1.25V      2.1V
1.8ns     1.74V      1.26V      3.31V
2.1ns     2.74V      1.41V      3.5V
2.4ns     3.09V      1.92V      3.55V
2.7ns     3.19V      2.51V      3.57V
3ns       3.24V      2.76V      3.58V
3.6ns     3.27V      2.91V      3.59V
15ns      3.3V       3V         3.6V
[Falling Waveform]
R_fixture = 50.00
V_fixture = 3.30
V_fixture_min = 3.00
V_fixture_max = 3.60
| time   V(typ)   V(min)   V(max)
0s        3.3V       3V         3.6V
1.5ns     3.3V       3V         3.52V
2.4ns     2.99V      3V         1.62V
2.7ns     2.56V      2.97V      1.11V
3ns       1.94V      2.88V      900mV
3.3ns     1.43V      2.74V      850mV
3.6ns     1.18V      2.55V      840mV
4.8ns     1.02V      1.54V      820mV
5.4ns     1.01V      1.35V      820mV
15ns      1V         1.26V      810mV
[Falling Waveform]
R_fixture = 50.00
V_fixture = 0.000
V_fixture_min = 0.000
V_fixture_max = 0.000
| time   V(typ)   V(min)   V(max)
0s        2.18V      1.77V      2.51V
1.2ns     2.18V      1.77V      2.48V
1.5ns     2.18V      1.77V      1.68V
1.8ns     2.08V      1.77V      330mV
2.1ns     1.68V      1.77V      62.98mV
2.7ns     230mV      1.67V      18.68mV
3ns       71.31mV    1.44V      12.67mV
3.9ns     15.42mV    310mV      6.33mV
4.5ns     9.59mV     76.25mV    4.72mV
15ns      910uV      1.38mV     850uV
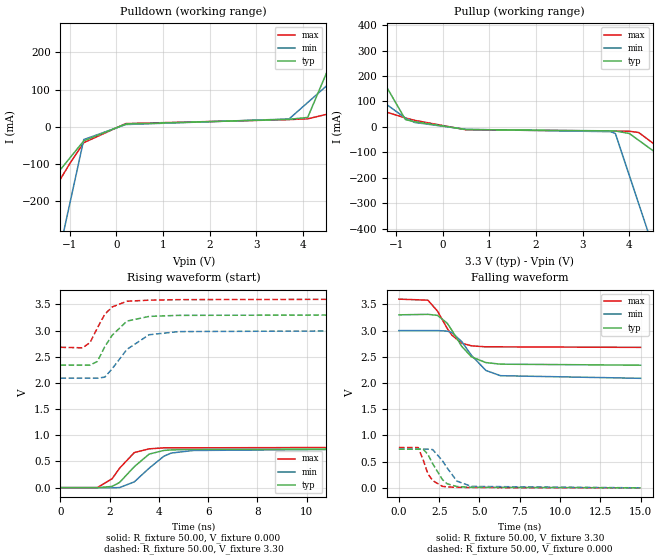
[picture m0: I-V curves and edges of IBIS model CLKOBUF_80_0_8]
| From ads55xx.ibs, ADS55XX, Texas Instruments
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|   Model CLKOBUF_80_0_8
[Model]   CLKOBUF_80_0_8
Model_type   Output
Polarity   Non-Inverting
Vmeas =   1.65V
C_comp   2pf   2pf   2pf
[Temperature Range]   50.00   0.10k   -20.00
[Voltage Range]   3.30V   3.00V   3.60V
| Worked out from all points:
|   slope of the pulldown table from 0 to 0.495 V, typ, clamps not added: 34.1 ohm
|   slope of the pullup table from 0 to 0.495 V, typ, clamps not added: 48.7 ohm
|   rising waveform, R_fixture 50.00, V_fixture 0.000: 20-80 % time 927ps typ, 1.07ns min, 805ps max; typ from 0 V to 0.74 V
|   rising waveform, R_fixture 50.00, V_fixture 3.30: 20-80 % time 853ps typ, 1.02ns min, 726ps max; typ from 2.34 V to 3.3 V
|   falling waveform, R_fixture 50.00, V_fixture 3.30: 20-80 % time 1.32ns typ, 1.45ns min, 1.16ns max; typ from 3.3 V to 2.34 V
|   falling waveform, R_fixture 50.00, V_fixture 0.000: 20-80 % time 861ps typ, 1.01ns min, 665ps max; typ from 0.74 V to 0.001 V
[Pulldown]
| voltage   I(typ)   I(min)   I(max)
-3.3V     -438.5mA   -1.526A    -576.8mA
-2.3V     -284.2mA   -952mA     -368.8mA
-1.9V     -222.5mA   -722.5mA   -285.6mA
-1.5V     -160.8mA   -492.9mA   -202.4mA
-1V       -83.64mA   -206.1mA   -98.38mA
-700mV    -37.35mA   -33.91mA   -42.22mA
200mV     7.75mA     6.46mA     9.01mA
3.7V      20.38mA    21.3mA     19.7mA
4.1V      25.51mA    65.5mA     21.83mA
4.9V      262.1mA    153.9mA    45.27mA
5.9V      557.9mA    264.4mA    77.52mA
6.6V      765mA      341.7mA    100.1mA
[Pullup]
| voltage   I(typ)   I(min)   I(max)
-3.3V     822.1mA    367.1mA    176.1mA
-2.3V     504.8mA    234.1mA    119.8mA
-2.1V     441.3mA    207.5mA    108.5mA
-800mV    28.85mA    34.56mA    35.34mA
-600mV    20.34mA    17.51mA    25.73mA
500mV     -10.24mA   -9.51mA    -11.2mA
3.6V      -15.51mA   -18.63mA   -16.07mA
3.7V      -15.71mA   -25.79mA   -16.15mA
4V        -25.87mA   -191.4mA   -16.98mA
4.2V      -52.45mA   -301.7mA   -21.88mA
4.5V      -92.32mA   -467.3mA   -63.15mA
6.6V      -371.4mA   -1.626A    -411mA
[Ramp]
| variable   typ   min   max
dV/dt_r   0.45/0.89n   0.44/1.06n   0.46/0.78n
dV/dt_f   0.58/1.31n   0.55/1.43n   0.55/1.12n
R_load = 50.00
[Rising Waveform]
R_fixture = 50.00
V_fixture = 0.000
V_fixture_min = 0.000
V_fixture_max = 0.000
| time   V(typ)   V(min)   V(max)
0s        32.02nV    41.35nV    66.06nV
1.5ns     -2.31mV    37.09uV    490uV
2.1ns     23.07mV    -4.57mV    170mV
2.4ns     98.69mV    800uV      370mV
3ns       400mV      110mV      670mV
3.6ns     640mV      370mV      740mV
4.2ns     710mV      600mV      760mV
4.5ns     720mV      660mV      760mV
5.4ns     730mV      710mV      760mV
15ns      740mV      740mV      770mV
[Rising Waveform]
R_fixture = 50.00
V_fixture = 3.30
V_fixture_min = 3.00
V_fixture_max = 3.60
| time   V(typ)   V(min)   V(max)
0s        2.34V      2.09V      2.68V
900ps     2.34V      2.09V      2.67V
1.2ns     2.34V      2.09V      2.77V
1.5ns     2.41V      2.09V      3.05V
1.8ns     2.69V      2.11V      3.31V
2.1ns     2.91V      2.27V      3.45V
2.7ns     3.18V      2.64V      3.56V
3.6ns     3.27V      2.92V      3.58V
4.8ns     3.29V      2.98V      3.59V
15ns      3.3V       3V         3.6V
[Falling Waveform]
R_fixture = 50.00
V_fixture = 3.30
V_fixture_min = 3.00
V_fixture_max = 3.60
| time   V(typ)   V(min)   V(max)
0s        3.3V       3V         3.6V
1.8ns     3.31V      3V         3.58V
2.4ns     3.29V      3V         3.37V
3ns       3.14V      2.99V      3.04V
3.3ns     3V         2.96V      2.91V
3.9ns     2.7V       2.79V      2.76V
4.5ns     2.5V       2.53V      2.71V
5.4ns     2.39V      2.24V      2.69V
6.3ns     2.36V      2.14V      2.69V
15ns      2.34V      2.09V      2.68V
[Falling Waveform]
R_fixture = 50.00
V_fixture = 0.000
V_fixture_min = 0.000
V_fixture_max = 0.000
| time   V(typ)   V(min)   V(max)
0s        740mV      740mV      770mV
1.2ns     740mV      740mV      770mV
1.5ns     740mV      740mV      540mV
1.8ns     640mV      740mV      270mV
2.1ns     460mV      730mV      140mV
2.7ns     160mV      520mV      30.25mV
3ns       78.57mV    380mV      19.2mV
3.6ns     26.18mV    130mV      11.34mV
4.5ns     11.83mV    29.1mV     7.01mV
15ns      1.29mV     1.63mV     1.36mV
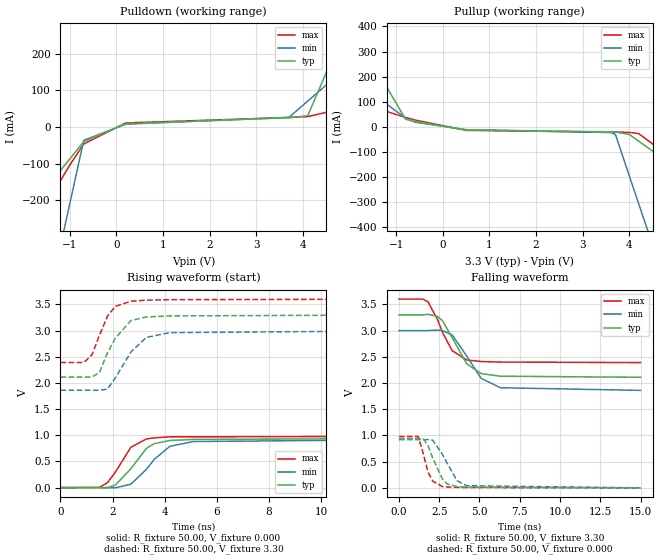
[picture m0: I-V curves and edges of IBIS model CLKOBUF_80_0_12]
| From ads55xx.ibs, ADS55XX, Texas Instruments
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|   Model CLKOBUF_80_0_12
[Model]   CLKOBUF_80_0_12
Model_type   Output
Polarity   Non-Inverting
Vmeas =   1.65V
C_comp   2pf   2pf   2pf
[Temperature Range]   50.00   0.10k   -20.00
[Voltage Range]   3.30V   3.00V   3.60V
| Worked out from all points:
|   slope of the pulldown table from 0 to 0.495 V, typ, clamps not added: 28.8 ohm
|   slope of the pullup table from 0 to 0.495 V, typ, clamps not added: 41.5 ohm
|   rising waveform, R_fixture 50.00, V_fixture 0.000: 20-80 % time 865ps typ, 1.03ns min, 778ps max; typ from 0 V to 0.94 V
|   rising waveform, R_fixture 50.00, V_fixture 3.30: 20-80 % time 769ps typ, 909ps min, 658ps max; typ from 2.11 V to 3.3 V
|   falling waveform, R_fixture 50.00, V_fixture 3.30: 20-80 % time 1.3ns typ, 1.38ns min, 1.1ns max; typ from 3.3 V to 2.11 V
|   falling waveform, R_fixture 50.00, V_fixture 0.000: 20-80 % time 796ps typ, 984ps min, 599ps max; typ from 0.94 V to 0.001 V
[Pulldown]
| voltage   I(typ)   I(min)   I(max)
-3.3V     -448.6mA   -1.535A    -591.8mA
-2.3V     -291.5mA   -958.8mA   -379.8mA
-1.9V     -228.6mA   -728.2mA   -294.9mA
-1.5V     -165.8mA   -497.6mA   -210.1mA
-1V       -87.25mA   -209.4mA   -104mA
-700mV    -40.12mA   -36.43mA   -46.53mA
200mV     8.86mA     7.42mA     10.91mA
3.7V      25.17mA    26.23mA    25.82mA
4.1V      30.32mA    70.43mA    28.02mA
4.9V      267.1mA    158.8mA    51.76mA
5.9V      563.1mA    269.3mA    84.41mA
6.6V      770.3mA    346.7mA    107.3mA
[Pullup]
| voltage   I(typ)   I(min)   I(max)
-3.3V     829.1mA    373.3mA    184.6mA
-2.3V     509.8mA    238.5mA    125.9mA
-2.1V     446mA      211.5mA    114.2mA
-800mV    30.89mA    36.27mA    37.89mA
-600mV    21.94mA    18.85mA    27.77mA
500mV     -12.01mA   -10.92mA   -13.75mA
3.6V      -19.67mA   -22.55mA   -20.65mA
3.7V      -19.88mA   -29.71mA   -20.74mA
4V        -30.07mA   -195.3mA   -21.6mA
4.2V      -56.67mA   -305.7mA   -26.53mA
4.5V      -96.57mA   -471.3mA   -67.83mA
6.6V      -375.9mA   -1.631A    -416mA
[Ramp]
| variable   typ   min   max
dV/dt_r   0.56/0.85n   0.55/1.01n   0.59/0.75n
dV/dt_f   0.71/1.27n   0.68/1.37n   0.73/1.08n
R_load = 50.00
[Rising Waveform]
R_fixture = 50.00
V_fixture = 0.000
V_fixture_min = 0.000
V_fixture_max = 0.000
| time   V(typ)   V(min)   V(max)
0s        29.69nV    38.44nV    59.12nV
1.5ns     -2.67mV    36.53uV    5.32mV
1.8ns     180uV      -1.94mV    92.86mV
2.1ns     45.61mV    -4.99mV    290mV
2.7ns     360mV      64.47mV    770mV
3.3ns     750mV      350mV      930mV
3.6ns     840mV      540mV      950mV
4.2ns     900mV      790mV      970mV
5.1ns     920mV      880mV      970mV
15ns      940mV      920mV      980mV
[Rising Waveform]
R_fixture = 50.00
V_fixture = 3.30
V_fixture_min = 3.00
V_fixture_max = 3.60
| time   V(typ)   V(min)   V(max)
0s        2.11V      1.86V      2.39V
900ps     2.11V      1.86V      2.39V
1.2ns     2.11V      1.86V      2.53V
1.5ns     2.2V       1.86V      2.91V
1.8ns     2.57V      1.88V      3.27V
2.1ns     2.85V      2.09V      3.46V
2.7ns     3.19V      2.59V      3.56V
3.3ns     3.26V      2.87V      3.58V
4.2ns     3.28V      2.96V      3.59V
15ns      3.3V       3V         3.6V
[Falling Waveform]
R_fixture = 50.00
V_fixture = 3.30
V_fixture_min = 3.00
V_fixture_max = 3.60
| time   V(typ)   V(min)   V(max)
0s        3.3V       3V         3.6V
1.5ns     3.3V       3V         3.6V
1.8ns     3.31V      3V         3.55V
2.4ns     3.27V      3.01V      3.21V
2.7ns     3.19V      3V         2.97V
3.3ns     2.87V      2.92V      2.62V
4.2ns     2.37V      2.52V      2.44V
5.1ns     2.18V      2.09V      2.41V
6.3ns     2.13V      1.91V      2.4V
15ns      2.11V      1.86V      2.39V
[Falling Waveform]
R_fixture = 50.00
V_fixture = 0.000
V_fixture_min = 0.000
V_fixture_max = 0.000
| time   V(typ)   V(min)   V(max)
0s        940mV      920mV      980mV
1.2ns     940mV      920mV      980mV
1.5ns     940mV      920mV      670mV
1.8ns     810mV      920mV      310mV
2.1ns     570mV      910mV      130mV
2.7ns     170mV      640mV      26.19mV
3ns       74.23mV    470mV      17.74mV
3.6ns     25.1mV     140mV      10.23mV
4.2ns     14.06mV    41.84mV    7.24mV
15ns      1.19mV     1.51mV     1.22mV
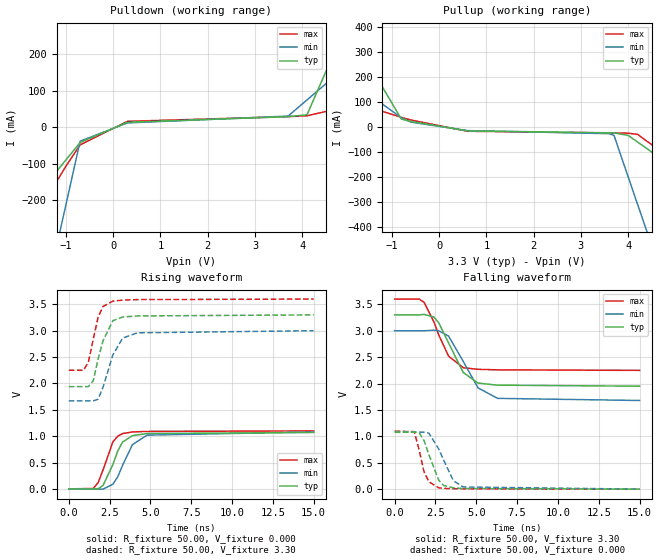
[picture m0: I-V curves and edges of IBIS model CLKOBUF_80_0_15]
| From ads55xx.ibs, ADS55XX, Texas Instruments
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|   Model CLKOBUF_80_0_15
[Model]   CLKOBUF_80_0_15
Model_type   Output
Polarity   Non-Inverting
Vmeas =   1.65V
C_comp   2pf   2pf   2pf
[Temperature Range]   50.00   0.10k   -20.00
[Voltage Range]   3.30V   3.00V   3.60V
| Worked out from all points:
|   slope of the pulldown table from 0 to 0.495 V, typ, clamps not added: 26.1 ohm
|   slope of the pullup table from 0 to 0.495 V, typ, clamps not added: 37.9 ohm
|   rising waveform, R_fixture 50.00, V_fixture 0.000: 20-80 % time 852ps typ, 1ns min, 762ps max; typ from 0 V to 1.07 V
|   rising waveform, R_fixture 50.00, V_fixture 3.30: 20-80 % time 736ps typ, 859ps min, 623ps max; typ from 1.94 V to 3.3 V
|   falling waveform, R_fixture 50.00, V_fixture 3.30: 20-80 % time 1.27ns typ, 1.36ns min, 1.12ns max; typ from 3.3 V to 1.95 V
|   falling waveform, R_fixture 50.00, V_fixture 0.000: 20-80 % time 771ps typ, 967ps min, 592ps max; typ from 1.08 V to 0.001 V
[Pulldown]
| voltage   I(typ)   I(min)   I(max)
-3.3V     -455.4mA   -1.542A    -600.3mA
-2.1V     -264.6mA   -848.1mA   -342.7mA
-1.7V     -201mA     -616.7mA   -256.9mA
-1.5V     -169.2mA   -501mA     -214mA
-1V       -89.71mA   -211.9mA   -106.7mA
-700mV    -42.01mA   -38.33mA   -48.47mA
300mV     13.37mA    11.47mA    15.92mA
3.7V      28.73mA    30.32mA    28.86mA
4.1V      33.9mA     74.56mA    31.09mA
4.9V      270.7mA    163mA      54.94mA
5.9V      566.7mA    273.6mA    87.74mA
6.6V      773.9mA    351.1mA    110.7mA
[Pullup]
| voltage   I(typ)   I(min)   I(max)
-3.3V     834mA      378.4mA    188.7mA
-2.3V     513.3mA    242.1mA    128.9mA
-2.1V     449.1mA    214.8mA    116.9mA
-800mV    32.21mA    37.66mA    39.17mA
-600mV    22.98mA    19.94mA    28.79mA
600mV     -14.92mA   -13.86mA   -16.53mA
3.6V      -22.72mA   -26.16mA   -23.19mA
3.7V      -22.94mA   -33.33mA   -23.29mA
4V        -33.16mA   -199mA     -24.17mA
4.2V      -59.76mA   -309.4mA   -29.11mA
4.5V      -99.66mA   -475mA     -70.42mA
6.6V      -379mA     -1.634A    -418.6mA
[Ramp]
| variable   typ   min   max
dV/dt_r   0.64/0.82n   0.65/0.98n   0.66/0.74n
dV/dt_f   0.81/1.24n   0.79/1.34n   0.81/1.11n
R_load = 50.00
[Rising Waveform]
R_fixture = 50.00
V_fixture = 0.000
V_fixture_min = 0.000
V_fixture_max = 0.000
| time   V(typ)   V(min)   V(max)
0s        28.33nV    36.54nV    56.58nV
1.5ns     -2.91mV    35.13uV    9.01mV
1.8ns     3.12mV     -2.1mV     120mV
2.1ns     64.82mV    -5.07mV    360mV
2.7ns     460mV      88.85mV    890mV
3ns       720mV      230mV      1V
3.3ns     890mV      450mV      1.05V
3.9ns     1.01V      840mV      1.08V
4.8ns     1.05V      1.02V      1.09V
15ns      1.07V      1.08V      1.1V
[Rising Waveform]
R_fixture = 50.00
V_fixture = 3.30
V_fixture_min = 3.00
V_fixture_max = 3.60
| time   V(typ)   V(min)   V(max)
0s        1.94V      1.67V      2.25V
900ps     1.94V      1.67V      2.25V
1.2ns     1.94V      1.67V      2.4V
1.5ns     2.05V      1.67V      2.84V
1.8ns     2.47V      1.7V       3.26V
2.1ns     2.81V      1.93V      3.46V
2.7ns     3.19V      2.54V      3.56V
3.3ns     3.26V      2.86V      3.58V
4.2ns     3.28V      2.96V      3.59V
15ns      3.3V       3V         3.6V
[Falling Waveform]
R_fixture = 50.00
V_fixture = 3.30
V_fixture_min = 3.00
V_fixture_max = 3.60
| time   V(typ)   V(min)   V(max)
0s        3.3V       3V         3.6V
1.5ns     3.3V       3V         3.6V
1.8ns     3.31V      3V         3.54V
2.4ns     3.26V      3.01V      3.17V
2.7ns     3.15V      3V         2.92V
3.3ns     2.77V      2.9V       2.52V
4.2ns     2.21V      2.42V      2.3V
5.1ns     2.01V      1.92V      2.27V
6.3ns     1.97V      1.72V      2.26V
15ns      1.95V      1.68V      2.25V
[Falling Waveform]
R_fixture = 50.00
V_fixture = 0.000
V_fixture_min = 0.000
V_fixture_max = 0.000
| time   V(typ)   V(min)   V(max)
0s        1.08V      1.08V      1.1V
1.2ns     1.08V      1.08V      1.09V
1.5ns     1.07V      1.08V      740mV
1.8ns     920mV      1.08V      330mV
2.1ns     650mV      1.06V      140mV
2.7ns     170mV      760mV      26.02mV
3ns       71.1mV     550mV      17.59mV
3.6ns     24.98mV    160mV      10.01mV
4.2ns     13.67mV    42.72mV    7.01mV
15ns      1.14mV     1.43mV     1.16mV
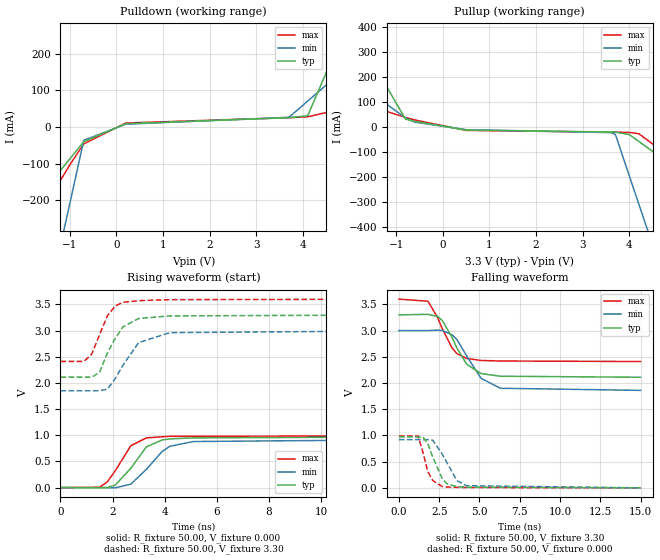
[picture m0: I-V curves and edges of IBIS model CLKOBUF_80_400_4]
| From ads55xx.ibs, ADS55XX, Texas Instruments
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|   Model CLKOBUF_80_400_4
[Model]   CLKOBUF_80_400_4
Model_type   Output
Polarity   Non-Inverting
Vmeas =   1.65V
C_comp   2pf   2pf   2pf
[Temperature Range]   50.00   0.10k   -20.00
[Voltage Range]   3.30V   3.00V   3.60V
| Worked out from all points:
|   slope of the pulldown table from 0 to 0.495 V, typ, clamps not added: 28.8 ohm
|   slope of the pullup table from 0 to 0.495 V, typ, clamps not added: 40.6 ohm
|   rising waveform, R_fixture 50.00, V_fixture 0.000: 20-80 % time 857ps typ, 1.03ns min, 763ps max; typ from 0 V to 0.97 V
|   rising waveform, R_fixture 50.00, V_fixture 3.30: 20-80 % time 769ps typ, 900ps min, 650ps max; typ from 2.11 V to 3.3 V
|   falling waveform, R_fixture 50.00, V_fixture 3.30: 20-80 % time 1.27ns typ, 1.38ns min, 1.14ns max; typ from 3.3 V to 2.11 V
|   falling waveform, R_fixture 50.00, V_fixture 0.000: 20-80 % time 784ps typ, 984ps min, 611ps max; typ from 0.97 V to 0.001 V
[Pulldown]
| voltage   I(typ)   I(min)   I(max)
-3.3V     -448.6mA   -1.535A    -590.5mA
-2.3V     -291.5mA   -958.9mA   -378.8mA
-1.9V     -228.7mA   -728.3mA   -294.1mA
-1.5V     -165.8mA   -497.7mA   -209.4mA
-1V       -87.28mA   -209.4mA   -103.6mA
-700mV    -40.15mA   -36.49mA   -46.19mA
200mV     8.87mA     7.44mA     10.77mA
3.7V      25.22mA    26.35mA    25.31mA
4.1V      30.37mA    70.55mA    27.51mA
4.9V      267.2mA    158.9mA    51.24mA
5.9V      563.2mA    269.4mA    83.89mA
6.6V      770.4mA    346.8mA    106.7mA
[Pullup]
| voltage   I(typ)   I(min)   I(max)
-3.3V     830.5mA    373.5mA    185mA
-2.3V     510.8mA    238.6mA    126.2mA
-2.1V     446.8mA    211.7mA    114.4mA
-800mV    31.22mA    36.29mA    38mA
-600mV    22.2mA     18.87mA    27.86mA
500mV     -12.3mA    -10.94mA   -13.85mA
3.6V      -20.41mA   -22.6mA    -20.85mA
3.7V      -20.62mA   -29.77mA   -20.94mA
4V        -30.82mA   -195.4mA   -21.81mA
4.2V      -57.42mA   -305.8mA   -26.74mA
4.5V      -97.32mA   -471.4mA   -68.03mA
6.6V      -376.6mA   -1.631A    -416.1mA
[Ramp]
| variable   typ   min   max
dV/dt_r   0.58/0.85n   0.55/1.01n   0.60/0.74n
dV/dt_f   0.71/1.26n   0.69/1.37n   0.71/1.11n
R_load = 50.00
[Rising Waveform]
R_fixture = 50.00
V_fixture = 0.000
V_fixture_min = 0.000
V_fixture_max = 0.000
| time   V(typ)   V(min)   V(max)
0s        29.68nV    38.38nV    59.66nV
1.5ns     -2.69mV    36.49uV    6.94mV
1.8ns     370uV      -1.95mV    110mV
2.1ns     46.96mV    -5mV       320mV
2.7ns     370mV      65.61mV    800mV
3.3ns     780mV      350mV      950mV
3.9ns     910mV      690mV      970mV
4.2ns     930mV      790mV      980mV
5.1ns     950mV      880mV      980mV
15ns      970mV      920mV      990mV
[Rising Waveform]
R_fixture = 50.00
V_fixture = 3.30
V_fixture_min = 3.00
V_fixture_max = 3.60
| time   V(typ)   V(min)   V(max)
0s        2.11V      1.85V      2.41V
900ps     2.11V      1.85V      2.41V
1.2ns     2.11V      1.85V      2.55V
1.5ns     2.2V       1.85V      2.92V
1.8ns     2.57V      1.88V      3.28V
2.1ns     2.85V      2.08V      3.47V
2.4ns     3.07V      2.34V      3.54V
3ns       3.23V      2.77V      3.57V
4.2ns     3.28V      2.96V      3.59V
15ns      3.3V       3V         3.6V
[Falling Waveform]
R_fixture = 50.00
V_fixture = 3.30
V_fixture_min = 3.00
V_fixture_max = 3.60
| time   V(typ)   V(min)   V(max)
0s        3.3V       3V         3.6V
1.8ns     3.31V      3V         3.56V
2.4ns     3.27V      3.01V      3.25V
2.7ns     3.19V      3V         3.03V
3.3ns     2.87V      2.92V      2.67V
3.6ns     2.67V      2.83V      2.56V
4.2ns     2.36V      2.52V      2.47V
5.1ns     2.18V      2.09V      2.43V
6.3ns     2.13V      1.9V       2.42V
15ns      2.11V      1.86V      2.41V
[Falling Waveform]
R_fixture = 50.00
V_fixture = 0.000
V_fixture_min = 0.000
V_fixture_max = 0.000
| time   V(typ)   V(min)   V(max)
0s        970mV      920mV      990mV
1.2ns     970mV      920mV      990mV
1.5ns     970mV      920mV      670mV
1.8ns     840mV      920mV      310mV
2.1ns     590mV      910mV      140mV
2.7ns     170mV      640mV      26.19mV
3ns       76.09mV    470mV      17.6mV
3.6ns     25.54mV    140mV      10.39mV
4.2ns     14.19mV    41.83mV    7.27mV
15ns      1.19mV     1.51mV     1.23mV
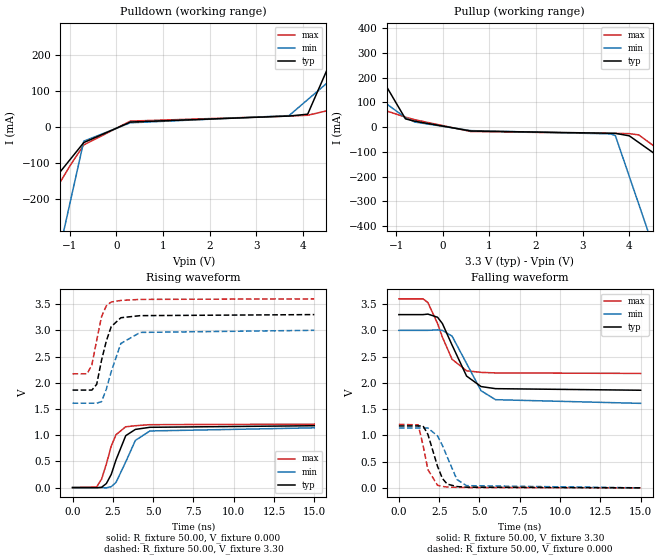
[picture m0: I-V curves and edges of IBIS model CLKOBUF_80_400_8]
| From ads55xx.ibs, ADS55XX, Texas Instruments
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|   Model CLKOBUF_80_400_8
[Model]   CLKOBUF_80_400_8
Model_type   Output
Polarity   Non-Inverting
Vmeas =   1.65V
C_comp   2pf   2pf   2pf
[Temperature Range]   50.00   0.10k   -20.00
[Voltage Range]   3.30V   3.00V   3.60V
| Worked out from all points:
|   slope of the pulldown table from 0 to 0.495 V, typ, clamps not added: 24.9 ohm
|   slope of the pullup table from 0 to 0.495 V, typ, clamps not added: 35.7 ohm
|   rising waveform, R_fixture 50.00, V_fixture 0.000: 20-80 % time 843ps typ, 996ps min, 758ps max; typ from 0 V to 1.18 V
|   rising waveform, R_fixture 50.00, V_fixture 3.30: 20-80 % time 719ps typ, 855ps min, 603ps max; typ from 1.86 V to 3.3 V
|   falling waveform, R_fixture 50.00, V_fixture 3.30: 20-80 % time 1.26ns typ, 1.35ns min, 1.11ns max; typ from 3.3 V to 1.86 V
|   falling waveform, R_fixture 50.00, V_fixture 0.000: 20-80 % time 750ps typ, 955ps min, 575ps max; typ from 1.18 V to 0.001 V
[Pulldown]
| voltage   I(typ)   I(min)   I(max)
-3.3V     -458.9mA   -1.545A    -604.6mA
-2.1V     -266.9mA   -849.7mA   -345.5mA
-1.7V     -202.9mA   -618mA     -259.1mA
-1.5V     -170.9mA   -502.2mA   -216mA
-1V       -90.9mA    -212.7mA   -108mA
-700mV    -42.9mA    -38.94mA   -49.43mA
300mV     13.89mA    11.81mA    16.53mA
3.7V      30.51mA    31.72mA    30.43mA
4.1V      35.68mA    75.92mA    32.67mA
4.9V      272.5mA    164.3mA    56.59mA
5.9V      568.5mA    274.8mA    89.49mA
6.6V      775.7mA    352.2mA    112.5mA
[Pullup]
| voltage   I(typ)   I(min)   I(max)
-3.3V     837.2mA    380.4mA    192.8mA
-2.3V     515.6mA    243.5mA    131.8mA
-2.1V     451.2mA    216.2mA    119.6mA
-800mV    33.16mA    38.18mA    40.29mA
-600mV    23.73mA    20.35mA    29.69mA
600mV     -15.93mA   -14.38mA   -17.89mA
3.6V      -25.09mA   -27.61mA   -25.6mA
3.7V      -25.32mA   -34.79mA   -25.71mA
4V        -35.55mA   -200.4mA   -26.6mA
4.2V      -62.17mA   -310.8mA   -31.55mA
4.5V      -102.1mA   -476.5mA   -72.87mA
6.6V      -381.6mA   -1.636A    -421.2mA
[Ramp]
| variable   typ   min   max
dV/dt_r   0.71/0.80n   0.68/0.96n   0.73/0.71n
dV/dt_f   0.86/1.23n   0.83/1.31n   0.85/1.10n
R_load = 50.00
[Rising Waveform]
R_fixture = 50.00
V_fixture = 0.000
V_fixture_min = 0.000
V_fixture_max = 0.000
| time   V(typ)   V(min)   V(max)
0s        27.76nV    35.99nV    55.51nV
1.5ns     -3.03mV    33.84uV    14.4mV
1.8ns     5.33mV     -2.15mV    160mV
2.1ns     77.38mV    -5.03mV    450mV
2.4ns     250mV      17.31mV    790mV
2.7ns     530mV      99.46mV    1.01V
3.3ns     990mV      490mV      1.16V
3.9ns     1.11V      900mV      1.18V
4.8ns     1.15V      1.08V      1.2V
15ns      1.18V      1.14V      1.21V
[Rising Waveform]
R_fixture = 50.00
V_fixture = 3.30
V_fixture_min = 3.00
V_fixture_max = 3.60
| time   V(typ)   V(min)   V(max)
0s        1.86V      1.61V      2.17V
900ps     1.86V      1.61V      2.17V
1.2ns     1.86V      1.61V      2.34V
1.5ns     1.97V      1.61V      2.81V
1.8ns     2.43V      1.64V      3.26V
2.1ns     2.8V       1.88V      3.47V
2.4ns     3.07V      2.21V      3.54V
3ns       3.24V      2.75V      3.57V
4.2ns     3.28V      2.96V      3.59V
15ns      3.3V       3V         3.6V
[Falling Waveform]
R_fixture = 50.00
V_fixture = 3.30
V_fixture_min = 3.00
V_fixture_max = 3.60
| time   V(typ)   V(min)   V(max)
0s        3.3V       3V         3.6V
1.5ns     3.3V       3V         3.6V
1.8ns     3.31V      3V         3.53V
2.4ns     3.25V      3.01V      3.13V
2.7ns     3.13V      3V         2.87V
3.3ns     2.72V      2.89V      2.45V
4.2ns     2.13V      2.37V      2.23V
5.1ns     1.93V      1.85V      2.2V
6ns       1.89V      1.68V      2.19V
15ns      1.86V      1.61V      2.18V
[Falling Waveform]
R_fixture = 50.00
V_fixture = 0.000
V_fixture_min = 0.000
V_fixture_max = 0.000
| time   V(typ)   V(min)   V(max)
0s        1.18V      1.14V      1.21V
1.2ns     1.18V      1.14V      1.2V
1.5ns     1.18V      1.14V      810mV
1.8ns     1.02V      1.14V      350mV
2.4ns     410mV      990mV      49.56mV
2.7ns     180mV      810mV      26.28mV
3ns       72.12mV    590mV      17.65mV
3.6ns     25.3mV     160mV      9.96mV
4.2ns     13.66mV    42.8mV     6.94mV
15ns      1.11mV     1.41mV     1.14mV
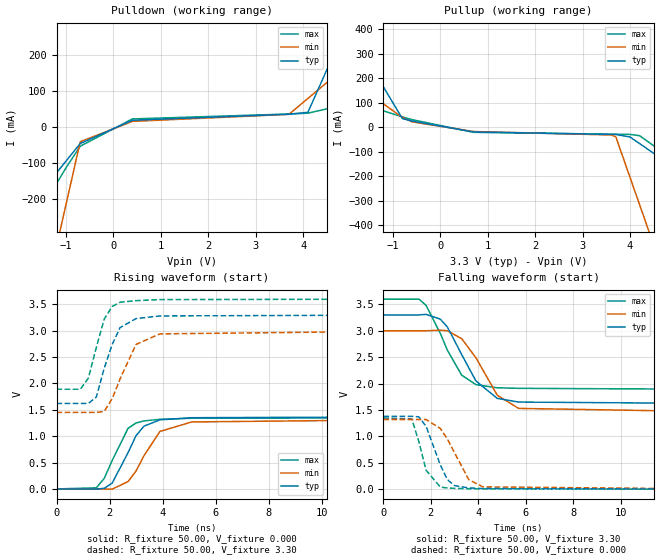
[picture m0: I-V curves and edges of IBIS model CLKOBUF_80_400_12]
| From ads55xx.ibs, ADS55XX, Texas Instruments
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|   Model CLKOBUF_80_400_12
[Model]   CLKOBUF_80_400_12
Model_type   Output
Polarity   Non-Inverting
Vmeas =   1.65V
C_comp   2pf   2pf   2pf
[Temperature Range]   50.00   0.10k   -20.00
[Voltage Range]   3.30V   3.00V   3.60V
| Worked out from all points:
|   slope of the pulldown table from 0 to 0.495 V, typ, clamps not added: 22.2 ohm
|   slope of the pullup table from 0 to 0.495 V, typ, clamps not added: 32.4 ohm
|   rising waveform, R_fixture 50.00, V_fixture 0.000: 20-80 % time 820ps typ, 957ps min, 751ps max; typ from 0 V to 1.37 V
|   rising waveform, R_fixture 50.00, V_fixture 3.30: 20-80 % time 692ps typ, 803ps min, 579ps max; typ from 1.62 V to 3.3 V
|   falling waveform, R_fixture 50.00, V_fixture 3.30: 20-80 % time 1.24ns typ, 1.22ns min, 1.1ns max; typ from 3.3 V to 1.62 V
|   falling waveform, R_fixture 50.00, V_fixture 0.000: 20-80 % time 723ps typ, 938ps min, 541ps max; typ from 1.38 V to 0.001 V
[Pulldown]
| voltage   I(typ)   I(min)   I(max)
-3.3V     -468.2mA   -1.551A    -619.7mA
-2.1V     -273.1mA   -853.6mA   -355.2mA
-1.7V     -208.1mA   -621.3mA   -267mA
-1.5V     -175.5mA   -505.1mA   -223mA
-1V       -94.23mA   -214.7mA   -112.8mA
-700mV    -45.45mA   -40.5mA    -52.88mA
400mV     19.18mA    16mA       22.84mA
3.7V      35.91mA    35.49mA    36.47mA
4.1V      41.09mA    79.69mA    38.74mA
4.9V      278mA      168.1mA    62.81mA
5.9V      574.1mA    278.6mA    95.91mA
6.6V      781.3mA    355.9mA    119.1mA
[Pullup]
| voltage   I(typ)   I(min)   I(max)
-3.3V     843.3mA    385.6mA    197.4mA
-2.3V     519.9mA    247.2mA    135.1mA
-2.1V     455.2mA    219.5mA    122.6mA
-800mV    34.82mA    39.62mA    41.64mA
-600mV    25.03mA    21.48mA    30.76mA
700mV     -19.66mA   -17.77mA   -21.12mA
3.6V      -29.63mA   -32mA      -28.7mA
3.7V      -29.87mA   -39.19mA   -28.81mA
4V        -40.14mA   -204.9mA   -29.73mA
4.2V      -66.78mA   -315.3mA   -34.69mA
4.5V      -106.7mA   -481mA     -76.03mA
6.6V      -386.5mA   -1.641A    -424.4mA
[Ramp]
| variable   typ   min   max
dV/dt_r   0.82/0.78n   0.79/0.92n   0.81/0.70n
dV/dt_f   1.01/1.21n   0.93/1.22n   1.02/1.08n
R_load = 50.00
[Rising Waveform]
R_fixture = 50.00
V_fixture = 0.000
V_fixture_min = 0.000
V_fixture_max = 0.000
| time   V(typ)   V(min)   V(max)
0s        26.24nV    34.73nV    51.81nV
1.5ns     -3.31mV    27.41uV    20.29mV
1.8ns     11.52mV    -2.05mV    200mV
2.1ns     110mV      -4.62mV    540mV
2.7ns     690mV      140mV      1.15V
3ns       1.01V      340mV      1.25V
3.3ns     1.19V      630mV      1.29V
3.9ns     1.31V      1.09V      1.32V
5.1ns     1.35V      1.27V      1.34V
15ns      1.37V      1.32V      1.35V
[Rising Waveform]
R_fixture = 50.00
V_fixture = 3.30
V_fixture_min = 3.00
V_fixture_max = 3.60
| time   V(typ)   V(min)   V(max)
0s        1.62V      1.45V      1.89V
900ps     1.62V      1.45V      1.89V
1.2ns     1.62V      1.45V      2.1V
1.5ns     1.74V      1.45V      2.68V
1.8ns     2.29V      1.47V      3.22V
2.1ns     2.74V      1.71V      3.46V
2.4ns     3.06V      2.09V      3.54V
3ns       3.23V      2.74V      3.57V
3.9ns     3.28V      2.94V      3.59V
15ns      3.3V       3V         3.6V
[Falling Waveform]
R_fixture = 50.00
V_fixture = 3.30
V_fixture_min = 3.00
V_fixture_max = 3.60
| time   V(typ)   V(min)   V(max)
0s        3.3V       3V         3.6V
1.5ns     3.3V       3V         3.6V
1.8ns     3.31V      3V         3.48V
2.4ns     3.22V      3.01V      2.95V
2.7ns     3.07V      3V         2.63V
3.3ns     2.55V      2.85V      2.16V
3.9ns     2.05V      2.49V      1.98V
4.8ns     1.72V      1.78V      1.92V
5.7ns     1.65V      1.53V      1.91V
15ns      1.62V      1.46V      1.89V
[Falling Waveform]
R_fixture = 50.00
V_fixture = 0.000
V_fixture_min = 0.000
V_fixture_max = 0.000
| time   V(typ)   V(min)   V(max)
0s        1.38V      1.32V      1.35V
1.2ns     1.38V      1.32V      1.33V
1.5ns     1.37V      1.32V      890mV
1.8ns     1.19V      1.32V      360mV
2.4ns     460mV      1.15V      40.15mV
2.7ns     180mV      950mV      23.84mV
3ns       68.35mV    690mV      16.11mV
3.6ns     24.41mV    180mV      9.15mV
4.2ns     13.06mV    44.1mV     6.44mV
15ns      1.05mV     1.36mV     1.06mV
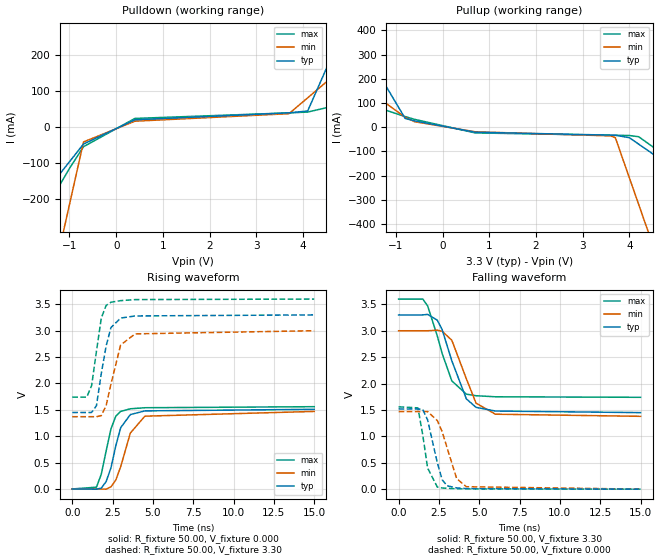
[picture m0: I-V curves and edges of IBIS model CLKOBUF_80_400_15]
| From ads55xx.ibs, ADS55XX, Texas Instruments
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|   Model CLKOBUF_80_400_15
[Model]   CLKOBUF_80_400_15
Model_type   Output
Polarity   Non-Inverting
Vmeas =   1.65V
C_comp   2pf   2pf   2pf
[Temperature Range]   50.00   0.10k   -20.00
[Voltage Range]   3.30V   3.00V   3.60V
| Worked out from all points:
|   slope of the pulldown table from 0 to 0.495 V, typ, clamps not added: 20.7 ohm
|   slope of the pullup table from 0 to 0.495 V, typ, clamps not added: 30.5 ohm
|   rising waveform, R_fixture 50.00, V_fixture 0.000: 20-80 % time 798ps typ, 945ps min, 713ps max; typ from 0 V to 1.51 V
|   rising waveform, R_fixture 50.00, V_fixture 3.30: 20-80 % time 671ps typ, 755ps min, 524ps max; typ from 1.45 V to 3.3 V
|   falling waveform, R_fixture 50.00, V_fixture 3.30: 20-80 % time 1.22ns typ, 1.14ns min, 1.12ns max; typ from 3.3 V to 1.45 V
|   falling waveform, R_fixture 50.00, V_fixture 0.000: 20-80 % time 709ps typ, 909ps min, 529ps max; typ from 1.52 V to 0.001 V
[Pulldown]
| voltage   I(typ)   I(min)   I(max)
-3.3V     -474.9mA   -1.554A    -626.9mA
-2.1V     -277.5mA   -855.7mA   -359.9mA
-1.7V     -211.7mA   -623mA     -270.9mA
-1.5V     -178.8mA   -506.7mA   -226.4mA
-1V       -96.52mA   -215.8mA   -115.1mA
-700mV    -47.17mA   -41.31mA   -54.63mA
400mV     20.49mA    16.6mA     24.28mA
3.7V      39.86mA    37.56mA    39.81mA
4.1V      45.04mA    81.8mA     42.09mA
4.9V      281.9mA    170.3mA    66.23mA
5.9V      578mA      280.9mA    99.43mA
6.6V      785.3mA    358.3mA    122.7mA
[Pullup]
| voltage   I(typ)   I(min)   I(max)
-3.3V     847.2mA    390.1mA    203.8mA
-2.3V     522.7mA    250.4mA    139.7mA
-2.1V     457.8mA    222.5mA    126.9mA
-800mV    35.96mA    40.86mA    43.57mA
-600mV    25.93mA    22.44mA    32.29mA
700mV     -21.09mA   -19.24mA   -23.85mA
3.6V      -33.05mA   -36.16mA   -33.53mA
3.7V      -33.3mA    -43.37mA   -33.65mA
4V        -43.59mA   -209.1mA   -34.6mA
4.2V      -70.25mA   -319.5mA   -39.58mA
4.5V      -110.2mA   -485.2mA   -80.94mA
6.6V      -390.2mA   -1.645A    -429.4mA
[Ramp]
| variable   typ   min   max
dV/dt_r   0.91/0.75n   0.88/0.89n   0.94/0.68n
dV/dt_f   1.11/1.18n   0.97/1.12n   1.12/1.11n
R_load = 50.00
[Rising Waveform]
R_fixture = 50.00
V_fixture = 0.000
V_fixture_min = 0.000
V_fixture_max = 0.000
| time   V(typ)   V(min)   V(max)
0s        25.34nV    34.19nV    50.31nV
1.5ns     -3.46mV    28.78uV    34.4mV
1.8ns     17.06mV    -1.89mV    280mV
2.1ns     140mV      -3.7mV     720mV
2.4ns     400mV      39.67mV    1.14V
2.7ns     820mV      170mV      1.38V
3ns       1.16V      420mV      1.47V
3.6ns     1.41V      1.06V      1.52V
4.5ns     1.48V      1.38V      1.54V
15ns      1.51V      1.47V      1.56V
[Rising Waveform]
R_fixture = 50.00
V_fixture = 3.30
V_fixture_min = 3.00
V_fixture_max = 3.60
| time   V(typ)   V(min)   V(max)
0s        1.45V      1.37V      1.74V
900ps     1.45V      1.37V      1.74V
1.2ns     1.45V      1.37V      1.96V
1.5ns     1.58V      1.37V      2.61V
1.8ns     2.19V      1.39V      3.24V
2.1ns     2.71V      1.58V      3.48V
2.4ns     3.06V      1.99V      3.54V
3ns       3.24V      2.73V      3.57V
3.9ns     3.28V      2.94V      3.59V
15ns      3.3V       3V         3.6V
[Falling Waveform]
R_fixture = 50.00
V_fixture = 3.30
V_fixture_min = 3.00
V_fixture_max = 3.60
| time   V(typ)   V(min)   V(max)
0s        3.3V       3V         3.6V
1.5ns     3.3V       3V         3.6V
1.8ns     3.31V      3V         3.47V
2.4ns     3.2V       3.01V      2.9V
2.7ns     3.02V      2.99V      2.57V
3.3ns     2.43V      2.82V      2.05V
4.2ns     1.71V      2.09V      1.8V
4.8ns     1.55V      1.63V      1.77V
6ns       1.48V      1.42V      1.75V
15ns      1.45V      1.38V      1.74V
[Falling Waveform]
R_fixture = 50.00
V_fixture = 0.000
V_fixture_min = 0.000
V_fixture_max = 0.000
| time   V(typ)   V(min)   V(max)
0s        1.52V      1.47V      1.56V
1.2ns     1.52V      1.47V      1.54V
1.5ns     1.51V      1.47V      1.02V
1.8ns     1.31V      1.47V      400mV
2.4ns     500mV      1.3V       40.9mV
2.7ns     180mV      1.09V      23.92mV
3ns       65.99mV    790mV      16.34mV
3.6ns     23.9mV     200mV      9.11mV
4.2ns     12.77mV    47.12mV    6.33mV
15ns      1.01mV     1.34mV     1.03mV
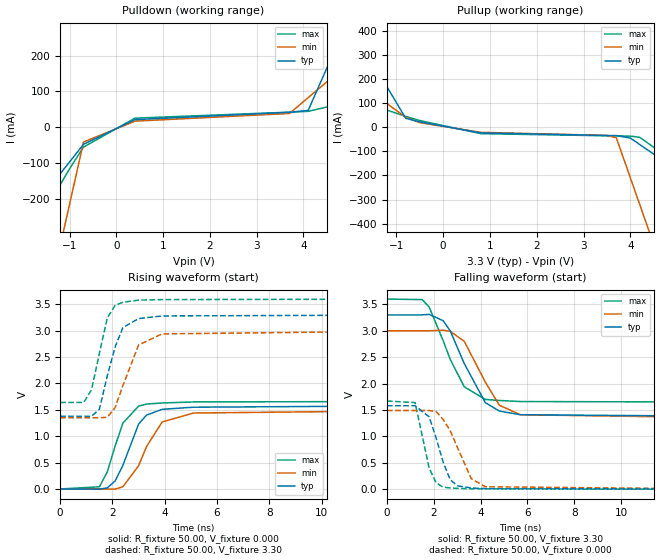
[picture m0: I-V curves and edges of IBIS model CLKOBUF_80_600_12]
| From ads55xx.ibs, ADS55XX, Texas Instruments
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|   Model CLKOBUF_80_600_12
[Model]   CLKOBUF_80_600_12
Model_type   Output
Polarity   Non-Inverting
Vmeas =   1.65V
C_comp   2pf   2pf   2pf
[Temperature Range]   50.00   0.10k   -20.00
[Voltage Range]   3.30V   3.00V   3.60V
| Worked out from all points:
|   slope of the pulldown table from 0 to 0.495 V, typ, clamps not added: 20.2 ohm
|   slope of the pullup table from 0 to 0.495 V, typ, clamps not added: 29.6 ohm
|   rising waveform, R_fixture 50.00, V_fixture 0.000: 20-80 % time 794ps typ, 926ps min, 694ps max; typ from 0 V to 1.58 V
|   rising waveform, R_fixture 50.00, V_fixture 3.30: 20-80 % time 662ps typ, 740ps min, 520ps max; typ from 1.38 V to 3.3 V
|   falling waveform, R_fixture 50.00, V_fixture 3.30: 20-80 % time 1.19ns typ, 1.14ns min, 1.1ns max; typ from 3.3 V to 1.38 V
|   falling waveform, R_fixture 50.00, V_fixture 0.000: 20-80 % time 696ps typ, 894ps min, 507ps max; typ from 1.58 V to 0.001 V
[Pulldown]
| voltage   I(typ)   I(min)   I(max)
-3.3V     -477.6mA   -1.554A    -631mA
-2.1V     -279.3mA   -856.2mA   -362.6mA
-1.7V     -213.2mA   -623.4mA   -273.1mA
-1.5V     -180.1mA   -507.1mA   -228.4mA
-1V       -97.45mA   -216.1mA   -116.5mA
-700mV    -47.86mA   -41.55mA   -55.67mA
400mV     21.02mA    16.77mA    25.13mA
3.7V      41.52mA    38.17mA    41.88mA
4.1V      46.7mA     82.37mA    44.16mA
4.9V      283.6mA    170.8mA    68.34mA
5.9V      579.7mA    281.3mA    101.6mA
6.6V      786.9mA    358.6mA    124.9mA
[Pullup]
| voltage   I(typ)   I(min)   I(max)
-3.3V     849mA      391mA      207mA
-2.3V     524mA      251mA      142mA
-2.1V     459mA      223mA      129mA
-800mV    36.48mA    41.04mA    44.49mA
-500mV    21.73mA    18.61mA    27.32mA
800mV     -23.77mA   -21.45mA   -26.96mA
3.5V      -34.57mA   -34.35mA   -35.89mA
3.7V      -34.94mA   -44mA      -36.14mA
4V        -45.24mA   -209.7mA   -37.1mA
4.2V      -71.9mA    -320.2mA   -42.09mA
4.5V      -111.9mA   -485.9mA   -83.46mA
6.6V      -391.8mA   -1.646A    -432.1mA
[Ramp]
| variable   typ   min   max
dV/dt_r   0.95/0.74n   0.89/0.88n   1.00/0.66n
dV/dt_f   1.15/1.17n   0.99/1.10n   1.17/1.08n
R_load = 50.00
[Rising Waveform]
R_fixture = 50.00
V_fixture = 0.000
V_fixture_min = 0.000
V_fixture_max = 0.000
| time   V(typ)   V(min)   V(max)
0s        25.02nV    34.05nV    49.46nV
1.5ns     -3.54mV    29.61uV    41.67mV
1.8ns     20.54mV    -1.87mV    320mV
2.1ns     150mV      -3.25mV    810mV
2.4ns     450mV      43.49mV    1.25V
3ns       1.23V      440mV      1.57V
3.3ns     1.4V       800mV      1.61V
3.9ns     1.51V      1.27V      1.63V
5.1ns     1.55V      1.44V      1.65V
15ns      1.58V      1.49V      1.66V
[Rising Waveform]
R_fixture = 50.00
V_fixture = 3.30
V_fixture_min = 3.00
V_fixture_max = 3.60
| time   V(typ)   V(min)   V(max)
0s        1.38V      1.35V      1.64V
900ps     1.38V      1.35V      1.64V
1.2ns     1.38V      1.35V      1.88V
1.5ns     1.51V      1.35V      2.57V
1.8ns     2.14V      1.36V      3.24V
2.1ns     2.69V      1.54V      3.48V
2.4ns     3.06V      1.96V      3.54V
3ns       3.23V      2.73V      3.58V
3.9ns     3.28V      2.94V      3.59V
15ns      3.3V       3V         3.6V
[Falling Waveform]
R_fixture = 50.00
V_fixture = 3.30
V_fixture_min = 3.00
V_fixture_max = 3.60
| time   V(typ)   V(min)   V(max)
0s        3.3V       3V         3.6V
1.5ns     3.3V       3V         3.59V
1.8ns     3.31V      3V         3.45V
2.4ns     3.19V      3.01V      2.81V
2.7ns     3V         2.99V      2.46V
3.3ns     2.38V      2.8V       1.94V
4.2ns     1.64V      2.03V      1.7V
4.8ns     1.48V      1.59V      1.68V
5.7ns     1.41V      1.41V      1.66V
15ns      1.38V      1.35V      1.65V
[Falling Waveform]
R_fixture = 50.00
V_fixture = 0.000
V_fixture_min = 0.000
V_fixture_max = 0.000
| time   V(typ)   V(min)   V(max)
0s        1.58V      1.49V      1.67V
1.2ns     1.58V      1.49V      1.64V
1.8ns     1.37V      1.49V      400mV
2.1ns     970mV      1.47V      120mV
2.4ns     510mV      1.32V      39.15mV
2.7ns     180mV      1.11V      23.65mV
3ns       65.54mV    800mV      15.95mV
3.6ns     23.54mV    200mV      8.92mV
4.2ns     12.6mV     46.37mV    6.23mV
15ns      1mV        1.33mV     1.01mV
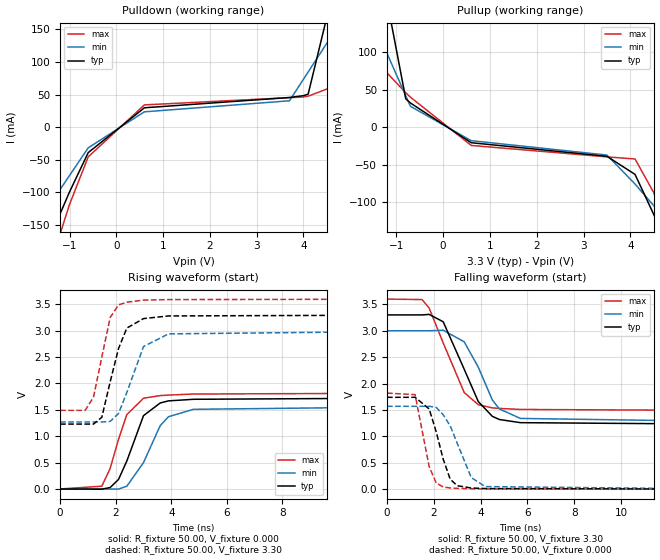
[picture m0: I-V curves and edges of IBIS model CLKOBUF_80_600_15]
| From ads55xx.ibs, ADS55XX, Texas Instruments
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|   Model CLKOBUF_80_600_15
[Model]   CLKOBUF_80_600_15
Model_type   Output
Polarity   Non-Inverting
Vmeas =   1.65V
C_comp   2pf   2pf   2pf
[Temperature Range]   50.00   0.10k   -20.00
[Voltage Range]   3.30V   3.00V   3.60V
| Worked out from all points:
|   slope of the pulldown table from 0 to 0.495 V, typ, clamps not added: 19 ohm
|   slope of the pullup table from 0 to 0.495 V, typ, clamps not added: 27.8 ohm
|   rising waveform, R_fixture 50.00, V_fixture 0.000: 20-80 % time 753ps typ, 891ps min, 683ps max; typ from 0 V to 1.73 V
|   rising waveform, R_fixture 50.00, V_fixture 3.30: 20-80 % time 647ps typ, 720ps min, 503ps max; typ from 1.23 V to 3.3 V
|   falling waveform, R_fixture 50.00, V_fixture 3.30: 20-80 % time 1.16ns typ, 1.12ns min, 1.14ns max; typ from 3.3 V to 1.23 V
|   falling waveform, R_fixture 50.00, V_fixture 0.000: 20-80 % time 685ps typ, 875ps min, 499ps max; typ from 1.74 V to 0.001 V
[Pulldown]
| voltage   I(typ)   I(min)   I(max)
-3.3V     -483.6mA   -318.8mA   -637.6mA
-1.9V     -249.8mA   -169.9mA   -321.8mA
-1.5V     -183mA     -127.4mA   -231.5mA
-1V       -99.53mA   -74.28mA   -118.7mA
-600mV    -39.06mA   -31.76mA   -45.58mA
600mV     29.7mA     23.51mA    34.14mA
3.7V      45.47mA    40.42mA    45.28mA
4V        48.3mA     73.6mA     46.29mA
4.1V      50.65mA    84.66mA    47.56mA
4.5V      169.1mA    128.9mA    58.45mA
4.9V      287.5mA    173.1mA    71.79mA
6.6V      790.9mA    361.2mA    128.5mA
[Pullup]
| voltage   I(typ)   I(min)   I(max)
-3.3V     853.8mA    393.8mA    211.3mA
-2.1V     462.1mA    224.8mA    131.8mA
-1.5V     266.2mA    140.4mA    92.13mA
-1V       103mA      69.97mA    59.03mA
-800mV    37.75mA    41.81mA    45.79mA
-700mV    32.15mA    27.73mA    39.91mA
600mV     -20.75mA   -18.02mA   -24.39mA
3.5V      -38.84mA   -37.19mA   -39.6mA
4.1V      -62.92mA   -75.74mA   -42.44mA
4.5V      -116.3mA   -104.6mA   -87.24mA
4.9V      -169.7mA   -133.5mA   -153.7mA
6.6V      -396.7mA   -256.2mA   -435.9mA
[Ramp]
| variable   typ   min   max
dV/dt_r   1.04/0.73n   0.94/0.85n   1.09/0.65n
dV/dt_f   1.24/1.14n   1.03/1.09n   1.26/1.11n
R_load = 50.00
[Rising Waveform]
R_fixture = 50.00
V_fixture = 0.000
V_fixture_min = 0.000
V_fixture_max = 0.000
| time   V(typ)   V(min)   V(max)
0s        24.31nV    33.48nV    48.2nV
1.5ns     -3.62mV    32.77uV    52.87mV
1.8ns     27.65mV    -1.82mV    390mV
2.1ns     180mV      -1.89mV    940mV
2.4ns     530mV      52.8mV     1.41V
3ns       1.39V      500mV      1.72V
3.6ns     1.63V      1.2V       1.77V
3.9ns     1.67V      1.37V      1.78V
4.8ns     1.7V       1.51V      1.8V
15ns      1.73V      1.57V      1.82V
[Rising Waveform]
R_fixture = 50.00
V_fixture = 3.30
V_fixture_min = 3.00
V_fixture_max = 3.60
| time   V(typ)   V(min)   V(max)
0s        1.23V      1.27V      1.49V
900ps     1.23V      1.27V      1.49V
1.2ns     1.23V      1.27V      1.74V
1.5ns     1.36V      1.27V      2.5V
1.8ns     2.03V      1.28V      3.25V
2.1ns     2.66V      1.43V      3.49V
2.4ns     3.05V      1.83V      3.54V
3ns       3.23V      2.7V       3.58V
3.9ns     3.28V      2.94V      3.59V
15ns      3.3V       3V         3.6V
[Falling Waveform]
R_fixture = 50.00
V_fixture = 3.30
V_fixture_min = 3.00
V_fixture_max = 3.60
| time   V(typ)   V(min)   V(max)
0s        3.3V       3V         3.6V
1.5ns     3.3V       3V         3.59V
1.8ns     3.31V      3V         3.43V
2.4ns     3.17V      3.01V      2.77V
3.3ns     2.27V      2.79V      1.83V
3.9ns     1.66V      2.31V      1.6V
4.5ns     1.38V      1.69V      1.54V
4.8ns     1.32V      1.52V      1.53V
5.7ns     1.26V      1.34V      1.51V
15ns      1.23V      1.28V      1.49V
[Falling Waveform]
R_fixture = 50.00
V_fixture = 0.000
V_fixture_min = 0.000
V_fixture_max = 0.000
| time   V(typ)   V(min)   V(max)
0s        1.74V      1.57V      1.82V
1.2ns     1.74V      1.57V      1.79V
1.8ns     1.52V      1.57V      430mV
2.1ns     1.09V      1.55V      120mV
2.4ns     570mV      1.41V      40.78mV
2.7ns     190mV      1.2V       24.05mV
3ns       66.8mV     870mV      16.11mV
3.6ns     23.52mV    220mV      8.89mV
4.2ns     12.5mV     49.73mV    6.13mV
15ns      970uV      1.31mV     980uV
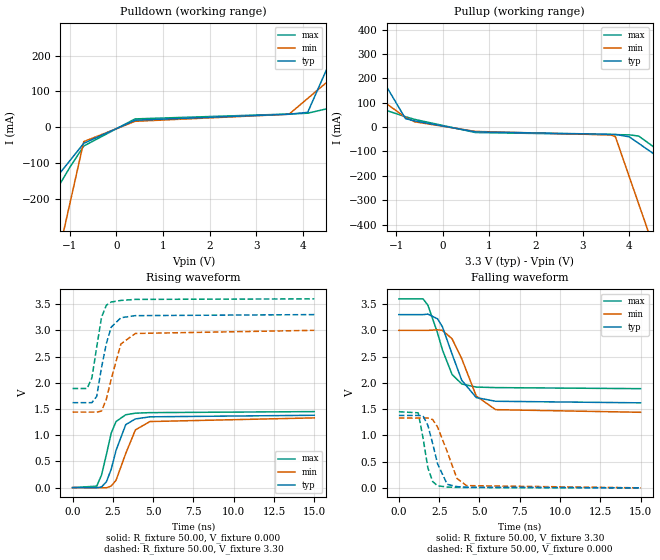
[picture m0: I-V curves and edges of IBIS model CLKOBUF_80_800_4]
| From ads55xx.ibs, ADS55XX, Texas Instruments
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|   Model CLKOBUF_80_800_4
[Model]   CLKOBUF_80_800_4
Model_type   Output
Polarity   Non-Inverting
Vmeas =   1.65V
C_comp   2pf   2pf   2pf
[Temperature Range]   50.00   0.10k   -20.00
[Voltage Range]   3.30V   3.00V   3.60V
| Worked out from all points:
|   slope of the pulldown table from 0 to 0.495 V, typ, clamps not added: 22.2 ohm
|   slope of the pullup table from 0 to 0.495 V, typ, clamps not added: 32.3 ohm
|   rising waveform, R_fixture 50.00, V_fixture 0.000: 20-80 % time 823ps typ, 956ps min, 725ps max; typ from 0 V to 1.38 V
|   rising waveform, R_fixture 50.00, V_fixture 3.30: 20-80 % time 689ps typ, 791ps min, 538ps max; typ from 1.62 V to 3.3 V
|   falling waveform, R_fixture 50.00, V_fixture 3.30: 20-80 % time 1.24ns typ, 1.19ns min, 1.1ns max; typ from 3.3 V to 1.62 V
|   falling waveform, R_fixture 50.00, V_fixture 0.000: 20-80 % time 723ps typ, 932ps min, 534ps max; typ from 1.38 V to 0.001 V
[Pulldown]
| voltage   I(typ)   I(min)   I(max)
-3.3V     -468.5mA   -1.551A    -619.4mA
-2.1V     -273.2mA   -854mA     -355.1mA
-1.7V     -208.1mA   -621.6mA   -267mA
-1.5V     -175.6mA   -505.4mA   -222.9mA
-1V       -94.25mA   -214.9mA   -112.8mA
-700mV    -45.44mA   -40.64mA   -52.88mA
400mV     19.18mA    16.1mA     22.84mA
3.7V      35.89mA    35.85mA    36.49mA
4.1V      41.08mA    80.05mA    38.75mA
4.9V      278mA      168.4mA    62.85mA
5.9V      574.1mA    278.9mA    96mA
6.6V      781.3mA    356.3mA    119.2mA
[Pullup]
| voltage   I(typ)   I(min)   I(max)
-3.3V     843.1mA    385.9mA    200.3mA
-2.3V     519.8mA    247.4mA    137.2mA
-2.1V     455.1mA    219.7mA    124.6mA
-800mV    34.85mA    39.69mA    42.56mA
-600mV    25.06mA    21.53mA    31.49mA
700mV     -19.7mA    -17.85mA   -22.42mA
3.6V      -29.71mA   -32.21mA   -30.93mA
3.7V      -29.95mA   -39.41mA   -31.04mA
4V        -40.21mA   -205.1mA   -31.97mA
4.2V      -66.87mA   -315.5mA   -36.94mA
4.5V      -106.9mA   -481.2mA   -78.29mA
6.6V      -386.8mA   -1.641A    -426.8mA
[Ramp]
| variable   typ   min   max
dV/dt_r   0.83/0.77n   0.80/0.91n   0.87/0.68n
dV/dt_f   1.01/1.21n   0.94/1.20n   1.02/1.08n
R_load = 50.00
[Rising Waveform]
R_fixture = 50.00
V_fixture = 0.000
V_fixture_min = 0.000
V_fixture_max = 0.000
| time   V(typ)   V(min)   V(max)
0s        26.26nV    34.63nV    51.9nV
1.5ns     -3.32mV    27.44uV    27.53mV
1.8ns     12.46mV    -2.01mV    240mV
2.1ns     110mV      -4.53mV    630mV
2.4ns     350mV      30.24mV    1.04V
2.7ns     710mV      140mV      1.26V
3.3ns     1.2V       650mV      1.39V
3.9ns     1.31V      1.1V       1.42V
4.8ns     1.35V      1.26V      1.43V
15ns      1.38V      1.33V      1.45V
[Rising Waveform]
R_fixture = 50.00
V_fixture = 3.30
V_fixture_min = 3.00
V_fixture_max = 3.60
| time   V(typ)   V(min)   V(max)
0s        1.62V      1.44V      1.89V
900ps     1.62V      1.44V      1.89V
1.2ns     1.62V      1.44V      2.09V
1.5ns     1.74V      1.44V      2.68V
1.8ns     2.29V      1.46V      3.25V
2.1ns     2.75V      1.69V      3.48V
2.4ns     3.06V      2.07V      3.54V
3ns       3.24V      2.74V      3.57V
3.9ns     3.28V      2.94V      3.59V
15ns      3.3V       3V         3.6V
[Falling Waveform]
R_fixture = 50.00
V_fixture = 3.30
V_fixture_min = 3.00
V_fixture_max = 3.60
| time   V(typ)   V(min)   V(max)
0s        3.3V       3V         3.6V
1.5ns     3.3V       3V         3.6V
1.8ns     3.31V      3V         3.48V
2.4ns     3.22V      3.01V      2.95V
2.7ns     3.07V      3V         2.63V
3.3ns     2.55V      2.84V      2.16V
3.9ns     2.05V      2.46V      1.98V
4.8ns     1.72V      1.75V      1.92V
6ns       1.65V      1.49V      1.91V
15ns      1.62V      1.44V      1.89V
[Falling Waveform]
R_fixture = 50.00
V_fixture = 0.000
V_fixture_min = 0.000
V_fixture_max = 0.000
| time   V(typ)   V(min)   V(max)
0s        1.38V      1.33V      1.45V
1.2ns     1.38V      1.33V      1.43V
1.5ns     1.37V      1.33V      950mV
1.8ns     1.19V      1.33V      380mV
2.1ns     840mV      1.3V       120mV
2.4ns     460mV      1.16V      40.66mV
3ns       68.43mV    690mV      16.3mV
3.6ns     24.42mV    180mV      9.24mV
4.2ns     13.07mV    43.42mV    6.49mV
15ns      1.05mV     1.35mV     1.06mV
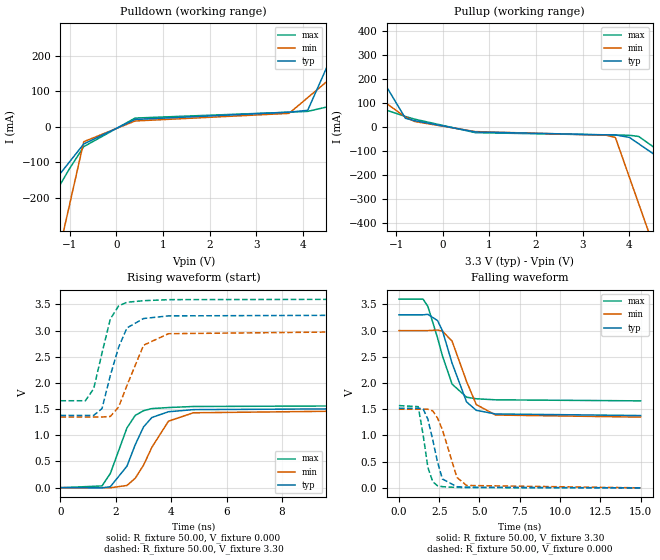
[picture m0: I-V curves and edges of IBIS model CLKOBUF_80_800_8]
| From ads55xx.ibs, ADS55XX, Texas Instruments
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|   Model CLKOBUF_80_800_8
[Model]   CLKOBUF_80_800_8
Model_type   Output
Polarity   Non-Inverting
Vmeas =   1.65V
C_comp   2pf   2pf   2pf
[Temperature Range]   50.00   0.10k   -20.00
[Voltage Range]   3.30V   3.00V   3.60V
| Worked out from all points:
|   slope of the pulldown table from 0 to 0.495 V, typ, clamps not added: 20.2 ohm
|   slope of the pullup table from 0 to 0.495 V, typ, clamps not added: 30.4 ohm
|   rising waveform, R_fixture 50.00, V_fixture 0.000: 20-80 % time 811ps typ, 928ps min, 715ps max; typ from 0 V to 1.52 V
|   rising waveform, R_fixture 50.00, V_fixture 3.30: 20-80 % time 670ps typ, 748ps min, 527ps max; typ from 1.38 V to 3.3 V
|   falling waveform, R_fixture 50.00, V_fixture 3.30: 20-80 % time 1.19ns typ, 1.14ns min, 1.13ns max; typ from 3.3 V to 1.38 V
|   falling waveform, R_fixture 50.00, V_fixture 0.000: 20-80 % time 701ps typ, 897ps min, 517ps max; typ from 1.52 V to 0.001 V
[Pulldown]
| voltage   I(typ)   I(min)   I(max)
-3.3V     -477.6mA   -1.555A    -630.1mA
-2.1V     -279.3mA   -856.4mA   -362mA
-1.7V     -213.2mA   -623.6mA   -272.6mA
-1.5V     -180.1mA   -507.2mA   -228mA
-1V       -97.46mA   -216.2mA   -116.3mA
-700mV    -47.87mA   -41.56mA   -55.48mA
400mV     21.03mA    16.78mA    24.97mA
3.7V      41.54mA    38.2mA     41.49mA
4.1V      46.73mA    82.44mA    43.77mA
4.9V      283.6mA    170.9mA    67.94mA
5.9V      579.7mA    281.5mA    101.2mA
6.6V      787mA      358.9mA    124.5mA
[Pullup]
| voltage   I(typ)   I(min)   I(max)
-3.3V     847.2mA    390.8mA    204.1mA
-2.3V     522.7mA    250.9mA    139.9mA
-2.1V     457.8mA    222.9mA    127.1mA
-800mV    35.98mA    41.06mA    43.63mA
-600mV    25.94mA    22.6mA     32.34mA
700mV     -21.11mA   -19.48mA   -23.93mA
3.5V      -32.99mA   -34.44mA   -33.57mA
3.7V      -33.34mA   -44.09mA   -33.81mA
4V        -43.64mA   -209.8mA   -34.75mA
4.2V      -70.3mA    -320.3mA   -39.74mA
4.5V      -110.3mA   -486mA     -81.1mA
6.6V      -390.2mA   -1.646A    -429.7mA
[Ramp]
| variable   typ   min   max
dV/dt_r   0.91/0.75n   0.90/0.89n   0.94/0.68n
dV/dt_f   1.15/1.17n   0.99/1.09n   1.16/1.11n
R_load = 50.00
[Rising Waveform]
R_fixture = 50.00
V_fixture = 0.000
V_fixture_min = 0.000
V_fixture_max = 0.000
| time   V(typ)   V(min)   V(max)
0s        24.98nV    34.01nV    49.53nV
1.5ns     -3.51mV    29.67uV    33.01mV
1.8ns     17.62mV    -1.85mV    270mV
2.4ns     410mV      41.59mV    1.14V
2.7ns     820mV      180mV      1.38V
3ns       1.16V      430mV      1.47V
3.3ns     1.34V      770mV      1.51V
3.9ns     1.45V      1.27V      1.53V
4.8ns     1.49V      1.43V      1.55V
15ns      1.52V      1.49V      1.57V
[Rising Waveform]
R_fixture = 50.00
V_fixture = 3.30
V_fixture_min = 3.00
V_fixture_max = 3.60
| time   V(typ)   V(min)   V(max)
0s        1.38V      1.35V      1.66V
900ps     1.38V      1.35V      1.66V
1.2ns     1.38V      1.35V      1.89V
1.5ns     1.51V      1.35V      2.57V
1.8ns     2.14V      1.36V      3.22V
2.1ns     2.68V      1.54V      3.47V
2.4ns     3.05V      1.95V      3.54V
3ns       3.23V      2.72V      3.57V
3.9ns     3.28V      2.94V      3.59V
15ns      3.3V       3V         3.6V
[Falling Waveform]
R_fixture = 50.00
V_fixture = 3.30
V_fixture_min = 3.00
V_fixture_max = 3.60
| time   V(typ)   V(min)   V(max)
0s        3.3V       3V         3.6V
1.5ns     3.3V       3V         3.6V
1.8ns     3.31V      3V         3.46V
2.4ns     3.19V      3.01V      2.86V
2.7ns     3V         2.99V      2.52V
3.3ns     2.38V      2.8V       1.98V
4.2ns     1.64V      2.03V      1.73V
4.8ns     1.48V      1.59V      1.7V
6ns       1.41V      1.39V      1.68V
15ns      1.38V      1.35V      1.66V
[Falling Waveform]
R_fixture = 50.00
V_fixture = 0.000
V_fixture_min = 0.000
V_fixture_max = 0.000
| time   V(typ)   V(min)   V(max)
0s        1.52V      1.5V       1.57V
1.2ns     1.52V      1.5V       1.55V
1.5ns     1.51V      1.5V       1.02V
1.8ns     1.31V      1.5V       390mV
2.1ns     920mV      1.47V      120mV
2.4ns     490mV      1.33V      39.84mV
2.7ns     170mV      1.11V      23.82mV
3.6ns     23.19mV    200mV      8.96mV
4.2ns     12.46mV    46.59mV    6.23mV
15ns      1mV        1.33mV     1.01mV
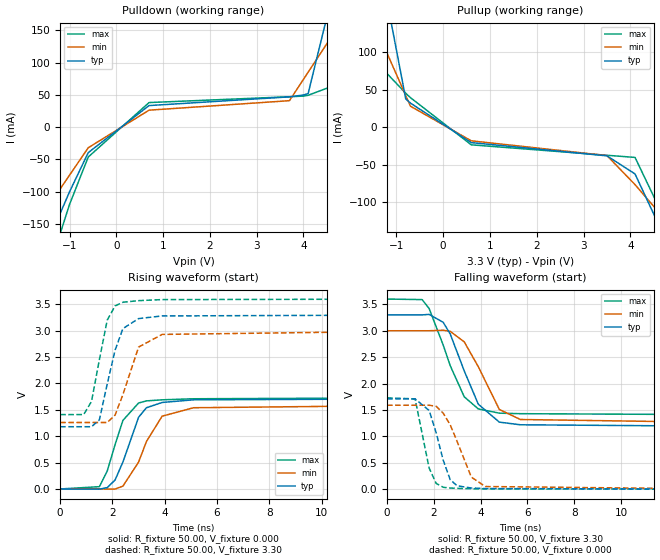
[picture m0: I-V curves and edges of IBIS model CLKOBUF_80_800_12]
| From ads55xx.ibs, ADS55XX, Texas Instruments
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|   Model CLKOBUF_80_800_12
[Model]   CLKOBUF_80_800_12
Model_type   Output
Polarity   Non-Inverting
Vmeas =   1.65V
C_comp   2pf   2pf   2pf
[Temperature Range]   50.00   0.10k   -20.00
[Voltage Range]   3.30V   3.00V   3.60V
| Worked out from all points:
|   slope of the pulldown table from 0 to 0.495 V, typ, clamps not added: 18.6 ohm
|   slope of the pullup table from 0 to 0.495 V, typ, clamps not added: 28.1 ohm
|   rising waveform, R_fixture 50.00, V_fixture 0.000: 20-80 % time 762ps typ, 889ps min, 701ps max; typ from 0 V to 1.71 V
|   rising waveform, R_fixture 50.00, V_fixture 3.30: 20-80 % time 650ps typ, 707ps min, 513ps max; typ from 1.18 V to 3.3 V
|   falling waveform, R_fixture 50.00, V_fixture 3.30: 20-80 % time 1.14ns typ, 1.13ns min, 1.13ns max; typ from 3.3 V to 1.19 V
|   falling waveform, R_fixture 50.00, V_fixture 0.000: 20-80 % time 681ps typ, 876ps min, 489ps max; typ from 1.71 V to 0.001 V
[Pulldown]
| voltage   I(typ)   I(min)   I(max)
-3.3V     -486mA     -319.5mA   -641.1mA
-1.9V     -251.2mA   -170.4mA   -323.8mA
-1.5V     -184.2mA   -127.8mA   -233.2mA
-1V       -100.3mA   -74.56mA   -119.9mA
-600mV    -39.56mA   -31.96mA   -46.33mA
700mV     33.45mA    26.31mA    38.11mA
3.7V      46.95mA    41.03mA    47.13mA
4V        49.78mA    74.18mA    48.15mA
4.1V      52.13mA    85.23mA    49.41mA
4.5V      170.6mA    129.4mA    60.3mA
4.9V      289mA      173.6mA    73.62mA
6.6V      792.4mA    361.5mA    130.2mA
[Pullup]
| voltage   I(typ)   I(min)   I(max)
-3.3V     852.8mA    394.5mA    209mA
-2.1V     461.5mA    225.3mA    130.3mA
-1.5V     265.8mA    140.7mA    90.95mA
-1V       102.8mA    70.18mA    58.15mA
-800mV    37.56mA    41.98mA    45.03mA
-700mV    31.97mA    27.88mA    39.23mA
600mV     -20.55mA   -18.19mA   -23.51mA
3.5V      -38.16mA   -37.82mA   -37.41mA
4.1V      -62.22mA   -76.42mA   -40.23mA
4.7V      -142.3mA   -119.8mA   -118.2mA
4.9V      -168.9mA   -134.3mA   -151.4mA
6.6V      -395.7mA   -257.2mA   -433.7mA
[Ramp]
| variable   typ   min   max
dV/dt_r   1.03/0.73n   0.95/0.84n   1.04/0.66n
dV/dt_f   1.27/1.14n   1.04/1.10n   1.31/1.11n
R_load = 50.00
[Rising Waveform]
R_fixture = 50.00
V_fixture = 0.000
V_fixture_min = 0.000
V_fixture_max = 0.000
| time   V(typ)   V(min)   V(max)
0s        24.02nV    33.33nV    47.45nV
1.5ns     -3.63mV    33.76uV    43.58mV
1.8ns     25.88mV    -1.81mV    340mV
2.1ns     170mV      -1.62mV    840mV
2.4ns     510mV      54.28mV    1.3V
3ns       1.36V      510mV      1.63V
3.3ns     1.54V      900mV      1.67V
3.9ns     1.64V      1.38V      1.69V
5.1ns     1.69V      1.54V      1.71V
15ns      1.71V      1.59V      1.73V
[Rising Waveform]
R_fixture = 50.00
V_fixture = 3.30
V_fixture_min = 3.00
V_fixture_max = 3.60
| time   V(typ)   V(min)   V(max)
0s        1.18V      1.26V      1.41V
900ps     1.18V      1.26V      1.41V
1.2ns     1.18V      1.26V      1.66V
1.5ns     1.31V      1.26V      2.45V
1.8ns     1.99V      1.26V      3.2V
2.1ns     2.63V      1.4V       3.47V
2.4ns     3.04V      1.79V      3.54V
3ns       3.23V      2.69V      3.57V
3.9ns     3.28V      2.93V      3.59V
15ns      3.3V       3V         3.6V
[Falling Waveform]
R_fixture = 50.00
V_fixture = 3.30
V_fixture_min = 3.00
V_fixture_max = 3.60
| time   V(typ)   V(min)   V(max)
0s        3.3V       3V         3.6V
1.5ns     3.3V       3V         3.59V
1.8ns     3.31V      3V         3.42V
2.4ns     3.16V      3.01V      2.73V
2.7ns     2.94V      2.99V      2.34V
3.3ns     2.24V      2.79V      1.75V
3.9ns     1.61V      2.32V      1.52V
4.8ns     1.27V      1.51V      1.44V
5.7ns     1.22V      1.32V      1.43V
15ns      1.19V      1.26V      1.41V
[Falling Waveform]
R_fixture = 50.00
V_fixture = 0.000
V_fixture_min = 0.000
V_fixture_max = 0.000
| time   V(typ)   V(min)   V(max)
0s        1.71V      1.59V      1.73V
1.2ns     1.71V      1.59V      1.71V
1.8ns     1.49V      1.59V      400mV
2.1ns     1.07V      1.57V      110mV
2.4ns     550mV      1.44V      37.08mV
2.7ns     180mV      1.22V      22.84mV
3ns       64.4mV     900mV      15.45mV
3.6ns     23.09mV    230mV      8.63mV
4.2ns     12.27mV    51.11mV    5.99mV
15ns      950uV      1.3mV      970uV
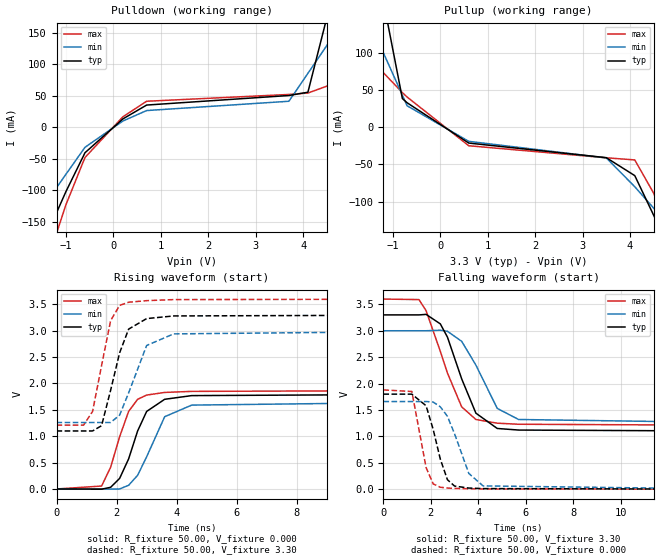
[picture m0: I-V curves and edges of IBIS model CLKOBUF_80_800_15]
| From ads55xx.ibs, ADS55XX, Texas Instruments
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|   Model CLKOBUF_80_800_15
[Model]   CLKOBUF_80_800_15
Model_type   Output
Polarity   Non-Inverting
Vmeas =   1.65V
C_comp   2pf   2pf   2pf
[Temperature Range]   50.00   0.10k   -20.00
[Voltage Range]   3.30V   3.00V   3.60V
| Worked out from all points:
|   slope of the pulldown table from 0 to 0.495 V, typ, clamps not added: 17.9 ohm
|   slope of the pullup table from 0 to 0.495 V, typ, clamps not added: 27.1 ohm
|   rising waveform, R_fixture 50.00, V_fixture 0.000: 20-80 % time 746ps typ, 798ps min, 664ps max; typ from 0 V to 1.8 V
|   rising waveform, R_fixture 50.00, V_fixture 3.30: 20-80 % time 634ps typ, 691ps min, 501ps max; typ from 1.1 V to 3.3 V
|   falling waveform, R_fixture 50.00, V_fixture 3.30: 20-80 % time 1.08ns typ, 1.13ns min, 1.14ns max; typ from 3.3 V to 1.1 V
|   falling waveform, R_fixture 50.00, V_fixture 0.000: 20-80 % time 668ps typ, 824ps min, 470ps max; typ from 1.8 V to 0.001 V
[Pulldown]
| voltage   I(typ)   I(min)   I(max)
-3.3V     -490.8mA   -319.5mA   -648.9mA
-1.9V     -254.1mA   -170.4mA   -328.5mA
-1.5V     -186.4mA   -127.8mA   -237mA
-1V       -101.9mA   -74.56mA   -122.6mA
-600mV    -40.6mA    -31.96mA   -48.14mA
200mV     13.08mA    9.71mA     16.46mA
700mV     35.01mA    26.31mA    41.04mA
3.7V      50.15mA    41.03mA    51.81mA
4.1V      55.33mA    85.27mA    54.08mA
4.5V      173.8mA    129.5mA    64.98mA
4.9V      292.2mA    173.8mA    78.32mA
6.6V      795.6mA    361.8mA    135mA
[Pullup]
| voltage   I(typ)   I(min)   I(max)
-3.3V     855.6mA    397.6mA    213mA
-2.1V     463.3mA    227.3mA    133mA
-1.5V     267.2mA    142.2mA    92.98mA
-1V       103.7mA    71.23mA    59.63mA
-800mV    38.34mA    42.85mA    46.29mA
-700mV    32.67mA    28.66mA    40.36mA
600mV     -21.36mA   -19.06mA   -24.97mA
3.5V      -40.94mA   -41.29mA   -41.1mA
4.1V      -65.04mA   -79.9mA    -43.97mA
4.5V      -118.4mA   -108.8mA   -88.78mA
4.9V      -171.8mA   -137.7mA   -155.2mA
6.6V      -398.5mA   -260.6mA   -437.6mA
[Ramp]
| variable   typ   min   max
dV/dt_r   1.08/0.71n   1.00/0.77n   1.12/0.65n
dV/dt_f   1.32/1.06n   1.04/1.10n   1.43/1.10n
R_load = 50.00
[Rising Waveform]
R_fixture = 50.00
V_fixture = 0.000
V_fixture_min = 0.000
V_fixture_max = 0.000
| time   V(typ)   V(min)   V(max)
0s        23.54nV    33.51nV    46.06nV
1.5ns     -3.58mV    33.79uV    55.62mV
1.8ns     31.17mV    -1.92mV    410mV
2.1ns     200mV      -73.91uV   990mV
2.4ns     570mV      69.92mV    1.47V
2.7ns     1.1V       260mV      1.7V
3ns       1.47V      610mV      1.78V
3.6ns     1.7V       1.37V      1.83V
4.5ns     1.77V      1.59V      1.85V
15ns      1.8V       1.66V      1.87V
[Rising Waveform]
R_fixture = 50.00
V_fixture = 3.30
V_fixture_min = 3.00
V_fixture_max = 3.60
| time   V(typ)   V(min)   V(max)
0s        1.1V       1.26V      1.21V
900ps     1.1V       1.26V      1.21V
1.2ns     1.1V       1.26V      1.47V
1.5ns     1.2V       1.26V      2.34V
1.8ns     1.87V      1.26V      3.19V
2.1ns     2.58V      1.4V       3.48V
2.4ns     3.03V      1.82V      3.54V
3ns       3.23V      2.72V      3.57V
3.9ns     3.28V      2.94V      3.59V
15ns      3.3V       3V         3.6V
[Falling Waveform]
R_fixture = 50.00
V_fixture = 3.30
V_fixture_min = 3.00
V_fixture_max = 3.60
| time   V(typ)   V(min)   V(max)
0s        3.3V       3V         3.6V
1.5ns     3.3V       3V         3.59V
1.8ns     3.31V      3V         3.38V
2.4ns     3.13V      3.01V      2.61V
2.7ns     2.88V      2.99V      2.2V
3.3ns     2.09V      2.8V       1.56V
3.9ns     1.44V      2.35V      1.32V
4.8ns     1.15V      1.53V      1.25V
5.7ns     1.12V      1.32V      1.23V
15ns      1.1V       1.26V      1.21V
[Falling Waveform]
R_fixture = 50.00
V_fixture = 0.000
V_fixture_min = 0.000
V_fixture_max = 0.000
| time   V(typ)   V(min)   V(max)
0s        1.8V       1.66V      1.88V
1.2ns     1.8V       1.66V      1.85V
1.8ns     1.58V      1.66V      410mV
2.1ns     1.13V      1.65V      100mV
2.4ns     570mV      1.56V      37.39mV
2.7ns     180mV      1.38V      22.53mV
3ns       59.8mV     1.05V      15.11mV
3.6ns     22.19mV    300mV      8.41mV
4.2ns     11.85mV    62.81mV    5.82mV
15ns      930uV      1.32mV     940uV
